VERSION 5.7 ;
  NOWIREEXTENSIONATPIN ON ;
  DIVIDERCHAR "/" ;
  BUSBITCHARS "[]" ;
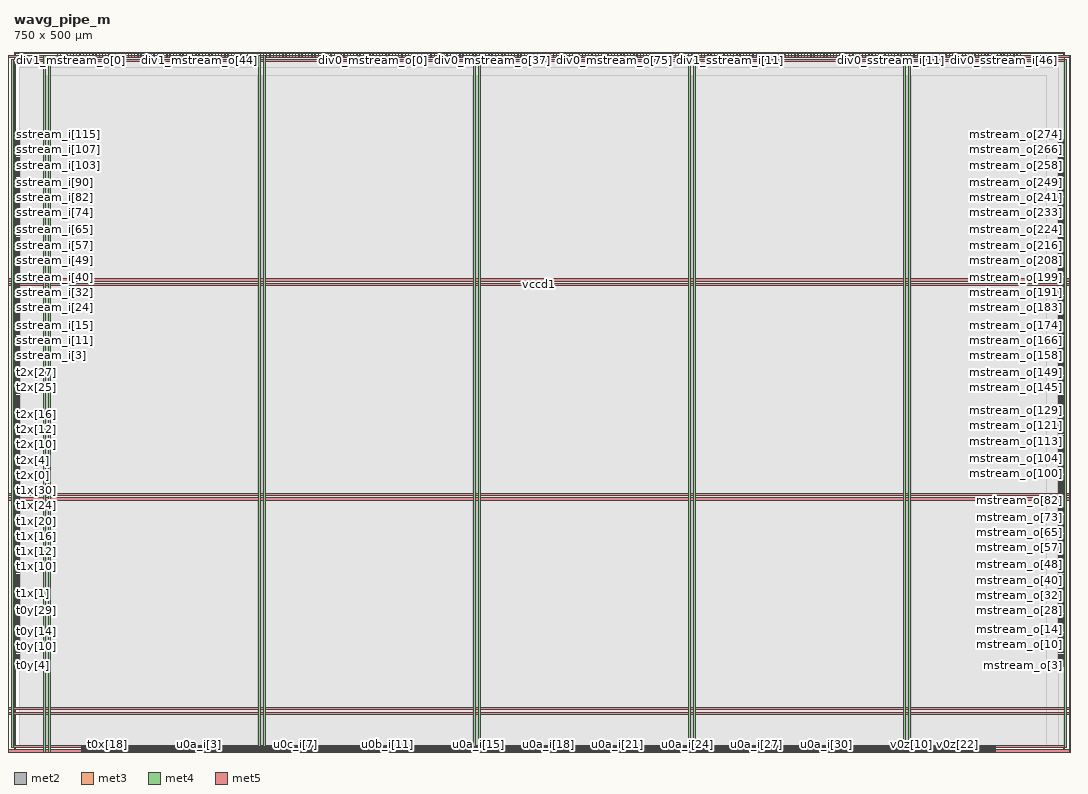
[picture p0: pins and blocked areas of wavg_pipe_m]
MACRO wavg_pipe_m
  CLASS BLOCK ;
  FOREIGN wavg_pipe_m ;
  ORIGIN 0.000 0.000 ;
  SIZE 750.000 BY 500.000 ;
  PIN clk_i
    DIRECTION INPUT ;
    USE SIGNAL ;
    ANTENNAGATEAREA 0.852000 ;
    PORT
      LAYER met2 ;
        RECT 48.390 0.000 48.670 4.000 ;
    END
  END clk_i
  PIN div0_mstream_i
    DIRECTION INPUT ;
    USE SIGNAL ;
    ANTENNAGATEAREA 0.213000 ;
    PORT
      LAYER met2 ;
        RECT 484.010 496.000 484.290 500.000 ;
    END
  END div0_mstream_i
  PIN div0_mstream_o[0]
    DIRECTION OUTPUT TRISTATE ;
    USE SIGNAL ;
    ANTENNADIFFAREA 0.795200 ;
    PORT
      LAYER met2 ;
        RECT 256.310 496.000 256.590 500.000 ;
    END
  END div0_mstream_o[0]
  PIN div0_mstream_o[10]
    DIRECTION OUTPUT TRISTATE ;
    USE SIGNAL ;
    ANTENNADIFFAREA 0.795200 ;
    PORT
      LAYER met2 ;
        RECT 279.310 496.000 279.590 500.000 ;
    END
  END div0_mstream_o[10]
  PIN div0_mstream_o[11]
    DIRECTION OUTPUT TRISTATE ;
    USE SIGNAL ;
    ANTENNADIFFAREA 0.795200 ;
    PORT
      LAYER met2 ;
        RECT 281.610 496.000 281.890 500.000 ;
    END
  END div0_mstream_o[11]
  PIN div0_mstream_o[12]
    DIRECTION OUTPUT TRISTATE ;
    USE SIGNAL ;
    ANTENNADIFFAREA 0.795200 ;
    PORT
      LAYER met2 ;
        RECT 283.910 496.000 284.190 500.000 ;
    END
  END div0_mstream_o[12]
  PIN div0_mstream_o[13]
    DIRECTION OUTPUT TRISTATE ;
    USE SIGNAL ;
    ANTENNADIFFAREA 0.795200 ;
    PORT
      LAYER met2 ;
        RECT 286.210 496.000 286.490 500.000 ;
    END
  END div0_mstream_o[13]
  PIN div0_mstream_o[14]
    DIRECTION OUTPUT TRISTATE ;
    USE SIGNAL ;
    ANTENNADIFFAREA 0.795200 ;
    PORT
      LAYER met2 ;
        RECT 288.510 496.000 288.790 500.000 ;
    END
  END div0_mstream_o[14]
  PIN div0_mstream_o[15]
    DIRECTION OUTPUT TRISTATE ;
    USE SIGNAL ;
    ANTENNADIFFAREA 0.795200 ;
    PORT
      LAYER met2 ;
        RECT 290.810 496.000 291.090 500.000 ;
    END
  END div0_mstream_o[15]
  PIN div0_mstream_o[16]
    DIRECTION OUTPUT TRISTATE ;
    USE SIGNAL ;
    ANTENNADIFFAREA 0.795200 ;
    PORT
      LAYER met2 ;
        RECT 293.110 496.000 293.390 500.000 ;
    END
  END div0_mstream_o[16]
  PIN div0_mstream_o[17]
    DIRECTION OUTPUT TRISTATE ;
    USE SIGNAL ;
    ANTENNADIFFAREA 0.795200 ;
    PORT
      LAYER met2 ;
        RECT 295.410 496.000 295.690 500.000 ;
    END
  END div0_mstream_o[17]
  PIN div0_mstream_o[18]
    DIRECTION OUTPUT TRISTATE ;
    USE SIGNAL ;
    ANTENNADIFFAREA 0.795200 ;
    PORT
      LAYER met2 ;
        RECT 297.710 496.000 297.990 500.000 ;
    END
  END div0_mstream_o[18]
  PIN div0_mstream_o[19]
    DIRECTION OUTPUT TRISTATE ;
    USE SIGNAL ;
    ANTENNADIFFAREA 0.795200 ;
    PORT
      LAYER met2 ;
        RECT 300.010 496.000 300.290 500.000 ;
    END
  END div0_mstream_o[19]
  PIN div0_mstream_o[1]
    DIRECTION OUTPUT TRISTATE ;
    USE SIGNAL ;
    ANTENNADIFFAREA 0.795200 ;
    PORT
      LAYER met2 ;
        RECT 258.610 496.000 258.890 500.000 ;
    END
  END div0_mstream_o[1]
  PIN div0_mstream_o[20]
    DIRECTION OUTPUT TRISTATE ;
    USE SIGNAL ;
    ANTENNADIFFAREA 0.795200 ;
    PORT
      LAYER met2 ;
        RECT 302.310 496.000 302.590 500.000 ;
    END
  END div0_mstream_o[20]
  PIN div0_mstream_o[21]
    DIRECTION OUTPUT TRISTATE ;
    USE SIGNAL ;
    ANTENNADIFFAREA 0.795200 ;
    PORT
      LAYER met2 ;
        RECT 304.610 496.000 304.890 500.000 ;
    END
  END div0_mstream_o[21]
  PIN div0_mstream_o[22]
    DIRECTION OUTPUT TRISTATE ;
    USE SIGNAL ;
    ANTENNADIFFAREA 0.795200 ;
    PORT
      LAYER met2 ;
        RECT 306.910 496.000 307.190 500.000 ;
    END
  END div0_mstream_o[22]
  PIN div0_mstream_o[23]
    DIRECTION OUTPUT TRISTATE ;
    USE SIGNAL ;
    ANTENNADIFFAREA 0.795200 ;
    PORT
      LAYER met2 ;
        RECT 309.210 496.000 309.490 500.000 ;
    END
  END div0_mstream_o[23]
  PIN div0_mstream_o[24]
    DIRECTION OUTPUT TRISTATE ;
    USE SIGNAL ;
    ANTENNADIFFAREA 0.795200 ;
    PORT
      LAYER met2 ;
        RECT 311.510 496.000 311.790 500.000 ;
    END
  END div0_mstream_o[24]
  PIN div0_mstream_o[25]
    DIRECTION OUTPUT TRISTATE ;
    USE SIGNAL ;
    ANTENNADIFFAREA 0.795200 ;
    PORT
      LAYER met2 ;
        RECT 313.810 496.000 314.090 500.000 ;
    END
  END div0_mstream_o[25]
  PIN div0_mstream_o[26]
    DIRECTION OUTPUT TRISTATE ;
    USE SIGNAL ;
    ANTENNADIFFAREA 0.795200 ;
    PORT
      LAYER met2 ;
        RECT 316.110 496.000 316.390 500.000 ;
    END
  END div0_mstream_o[26]
  PIN div0_mstream_o[27]
    DIRECTION OUTPUT TRISTATE ;
    USE SIGNAL ;
    ANTENNADIFFAREA 0.795200 ;
    PORT
      LAYER met2 ;
        RECT 318.410 496.000 318.690 500.000 ;
    END
  END div0_mstream_o[27]
  PIN div0_mstream_o[28]
    DIRECTION OUTPUT TRISTATE ;
    USE SIGNAL ;
    ANTENNADIFFAREA 0.795200 ;
    PORT
      LAYER met2 ;
        RECT 320.710 496.000 320.990 500.000 ;
    END
  END div0_mstream_o[28]
  PIN div0_mstream_o[29]
    DIRECTION OUTPUT TRISTATE ;
    USE SIGNAL ;
    ANTENNADIFFAREA 0.795200 ;
    PORT
      LAYER met2 ;
        RECT 323.010 496.000 323.290 500.000 ;
    END
  END div0_mstream_o[29]
  PIN div0_mstream_o[2]
    DIRECTION OUTPUT TRISTATE ;
    USE SIGNAL ;
    ANTENNADIFFAREA 0.795200 ;
    PORT
      LAYER met2 ;
        RECT 260.910 496.000 261.190 500.000 ;
    END
  END div0_mstream_o[2]
  PIN div0_mstream_o[30]
    DIRECTION OUTPUT TRISTATE ;
    USE SIGNAL ;
    ANTENNADIFFAREA 0.795200 ;
    PORT
      LAYER met2 ;
        RECT 325.310 496.000 325.590 500.000 ;
    END
  END div0_mstream_o[30]
  PIN div0_mstream_o[31]
    DIRECTION OUTPUT TRISTATE ;
    USE SIGNAL ;
    ANTENNADIFFAREA 0.795200 ;
    PORT
      LAYER met2 ;
        RECT 327.610 496.000 327.890 500.000 ;
    END
  END div0_mstream_o[31]
  PIN div0_mstream_o[32]
    DIRECTION OUTPUT TRISTATE ;
    USE SIGNAL ;
    ANTENNADIFFAREA 0.795200 ;
    PORT
      LAYER met2 ;
        RECT 329.910 496.000 330.190 500.000 ;
    END
  END div0_mstream_o[32]
  PIN div0_mstream_o[33]
    DIRECTION OUTPUT TRISTATE ;
    USE SIGNAL ;
    ANTENNADIFFAREA 0.795200 ;
    PORT
      LAYER met2 ;
        RECT 332.210 496.000 332.490 500.000 ;
    END
  END div0_mstream_o[33]
  PIN div0_mstream_o[34]
    DIRECTION OUTPUT TRISTATE ;
    USE SIGNAL ;
    ANTENNADIFFAREA 0.795200 ;
    PORT
      LAYER met2 ;
        RECT 334.510 496.000 334.790 500.000 ;
    END
  END div0_mstream_o[34]
  PIN div0_mstream_o[35]
    DIRECTION OUTPUT TRISTATE ;
    USE SIGNAL ;
    ANTENNADIFFAREA 0.795200 ;
    PORT
      LAYER met2 ;
        RECT 336.810 496.000 337.090 500.000 ;
    END
  END div0_mstream_o[35]
  PIN div0_mstream_o[36]
    DIRECTION OUTPUT TRISTATE ;
    USE SIGNAL ;
    ANTENNADIFFAREA 0.795200 ;
    PORT
      LAYER met2 ;
        RECT 339.110 496.000 339.390 500.000 ;
    END
  END div0_mstream_o[36]
  PIN div0_mstream_o[37]
    DIRECTION OUTPUT TRISTATE ;
    USE SIGNAL ;
    ANTENNADIFFAREA 0.795200 ;
    PORT
      LAYER met2 ;
        RECT 341.410 496.000 341.690 500.000 ;
    END
  END div0_mstream_o[37]
  PIN div0_mstream_o[38]
    DIRECTION OUTPUT TRISTATE ;
    USE SIGNAL ;
    ANTENNADIFFAREA 0.795200 ;
    PORT
      LAYER met2 ;
        RECT 343.710 496.000 343.990 500.000 ;
    END
  END div0_mstream_o[38]
  PIN div0_mstream_o[39]
    DIRECTION OUTPUT TRISTATE ;
    USE SIGNAL ;
    ANTENNADIFFAREA 0.795200 ;
    PORT
      LAYER met2 ;
        RECT 346.010 496.000 346.290 500.000 ;
    END
  END div0_mstream_o[39]
  PIN div0_mstream_o[3]
    DIRECTION OUTPUT TRISTATE ;
    USE SIGNAL ;
    ANTENNADIFFAREA 0.795200 ;
    PORT
      LAYER met2 ;
        RECT 263.210 496.000 263.490 500.000 ;
    END
  END div0_mstream_o[3]
  PIN div0_mstream_o[40]
    DIRECTION OUTPUT TRISTATE ;
    USE SIGNAL ;
    ANTENNADIFFAREA 0.795200 ;
    PORT
      LAYER met2 ;
        RECT 348.310 496.000 348.590 500.000 ;
    END
  END div0_mstream_o[40]
  PIN div0_mstream_o[41]
    DIRECTION OUTPUT TRISTATE ;
    USE SIGNAL ;
    ANTENNADIFFAREA 0.795200 ;
    PORT
      LAYER met2 ;
        RECT 350.610 496.000 350.890 500.000 ;
    END
  END div0_mstream_o[41]
  PIN div0_mstream_o[42]
    DIRECTION OUTPUT TRISTATE ;
    USE SIGNAL ;
    ANTENNADIFFAREA 0.795200 ;
    PORT
      LAYER met2 ;
        RECT 352.910 496.000 353.190 500.000 ;
    END
  END div0_mstream_o[42]
  PIN div0_mstream_o[43]
    DIRECTION OUTPUT TRISTATE ;
    USE SIGNAL ;
    ANTENNADIFFAREA 0.795200 ;
    PORT
      LAYER met2 ;
        RECT 355.210 496.000 355.490 500.000 ;
    END
  END div0_mstream_o[43]
  PIN div0_mstream_o[44]
    DIRECTION OUTPUT TRISTATE ;
    USE SIGNAL ;
    ANTENNADIFFAREA 0.795200 ;
    PORT
      LAYER met2 ;
        RECT 357.510 496.000 357.790 500.000 ;
    END
  END div0_mstream_o[44]
  PIN div0_mstream_o[45]
    DIRECTION OUTPUT TRISTATE ;
    USE SIGNAL ;
    ANTENNADIFFAREA 0.795200 ;
    PORT
      LAYER met2 ;
        RECT 359.810 496.000 360.090 500.000 ;
    END
  END div0_mstream_o[45]
  PIN div0_mstream_o[46]
    DIRECTION OUTPUT TRISTATE ;
    USE SIGNAL ;
    ANTENNADIFFAREA 0.795200 ;
    PORT
      LAYER met2 ;
        RECT 362.110 496.000 362.390 500.000 ;
    END
  END div0_mstream_o[46]
  PIN div0_mstream_o[47]
    DIRECTION OUTPUT TRISTATE ;
    USE SIGNAL ;
    ANTENNADIFFAREA 0.795200 ;
    PORT
      LAYER met2 ;
        RECT 364.410 496.000 364.690 500.000 ;
    END
  END div0_mstream_o[47]
  PIN div0_mstream_o[48]
    DIRECTION OUTPUT TRISTATE ;
    USE SIGNAL ;
    PORT
      LAYER met2 ;
        RECT 366.710 496.000 366.990 500.000 ;
    END
  END div0_mstream_o[48]
  PIN div0_mstream_o[49]
    DIRECTION OUTPUT TRISTATE ;
    USE SIGNAL ;
    PORT
      LAYER met2 ;
        RECT 369.010 496.000 369.290 500.000 ;
    END
  END div0_mstream_o[49]
  PIN div0_mstream_o[4]
    DIRECTION OUTPUT TRISTATE ;
    USE SIGNAL ;
    ANTENNADIFFAREA 0.795200 ;
    PORT
      LAYER met2 ;
        RECT 265.510 496.000 265.790 500.000 ;
    END
  END div0_mstream_o[4]
  PIN div0_mstream_o[50]
    DIRECTION OUTPUT TRISTATE ;
    USE SIGNAL ;
    PORT
      LAYER met2 ;
        RECT 371.310 496.000 371.590 500.000 ;
    END
  END div0_mstream_o[50]
  PIN div0_mstream_o[51]
    DIRECTION OUTPUT TRISTATE ;
    USE SIGNAL ;
    PORT
      LAYER met2 ;
        RECT 373.610 496.000 373.890 500.000 ;
    END
  END div0_mstream_o[51]
  PIN div0_mstream_o[52]
    DIRECTION OUTPUT TRISTATE ;
    USE SIGNAL ;
    PORT
      LAYER met2 ;
        RECT 375.910 496.000 376.190 500.000 ;
    END
  END div0_mstream_o[52]
  PIN div0_mstream_o[53]
    DIRECTION OUTPUT TRISTATE ;
    USE SIGNAL ;
    PORT
      LAYER met2 ;
        RECT 378.210 496.000 378.490 500.000 ;
    END
  END div0_mstream_o[53]
  PIN div0_mstream_o[54]
    DIRECTION OUTPUT TRISTATE ;
    USE SIGNAL ;
    PORT
      LAYER met2 ;
        RECT 380.510 496.000 380.790 500.000 ;
    END
  END div0_mstream_o[54]
  PIN div0_mstream_o[55]
    DIRECTION OUTPUT TRISTATE ;
    USE SIGNAL ;
    PORT
      LAYER met2 ;
        RECT 382.810 496.000 383.090 500.000 ;
    END
  END div0_mstream_o[55]
  PIN div0_mstream_o[56]
    DIRECTION OUTPUT TRISTATE ;
    USE SIGNAL ;
    PORT
      LAYER met2 ;
        RECT 385.110 496.000 385.390 500.000 ;
    END
  END div0_mstream_o[56]
  PIN div0_mstream_o[57]
    DIRECTION OUTPUT TRISTATE ;
    USE SIGNAL ;
    PORT
      LAYER met2 ;
        RECT 387.410 496.000 387.690 500.000 ;
    END
  END div0_mstream_o[57]
  PIN div0_mstream_o[58]
    DIRECTION OUTPUT TRISTATE ;
    USE SIGNAL ;
    PORT
      LAYER met2 ;
        RECT 389.710 496.000 389.990 500.000 ;
    END
  END div0_mstream_o[58]
  PIN div0_mstream_o[59]
    DIRECTION OUTPUT TRISTATE ;
    USE SIGNAL ;
    PORT
      LAYER met2 ;
        RECT 392.010 496.000 392.290 500.000 ;
    END
  END div0_mstream_o[59]
  PIN div0_mstream_o[5]
    DIRECTION OUTPUT TRISTATE ;
    USE SIGNAL ;
    ANTENNADIFFAREA 0.795200 ;
    PORT
      LAYER met2 ;
        RECT 267.810 496.000 268.090 500.000 ;
    END
  END div0_mstream_o[5]
  PIN div0_mstream_o[60]
    DIRECTION OUTPUT TRISTATE ;
    USE SIGNAL ;
    PORT
      LAYER met2 ;
        RECT 394.310 496.000 394.590 500.000 ;
    END
  END div0_mstream_o[60]
  PIN div0_mstream_o[61]
    DIRECTION OUTPUT TRISTATE ;
    USE SIGNAL ;
    PORT
      LAYER met2 ;
        RECT 396.610 496.000 396.890 500.000 ;
    END
  END div0_mstream_o[61]
  PIN div0_mstream_o[62]
    DIRECTION OUTPUT TRISTATE ;
    USE SIGNAL ;
    PORT
      LAYER met2 ;
        RECT 398.910 496.000 399.190 500.000 ;
    END
  END div0_mstream_o[62]
  PIN div0_mstream_o[63]
    DIRECTION OUTPUT TRISTATE ;
    USE SIGNAL ;
    PORT
      LAYER met2 ;
        RECT 401.210 496.000 401.490 500.000 ;
    END
  END div0_mstream_o[63]
  PIN div0_mstream_o[64]
    DIRECTION OUTPUT TRISTATE ;
    USE SIGNAL ;
    PORT
      LAYER met2 ;
        RECT 403.510 496.000 403.790 500.000 ;
    END
  END div0_mstream_o[64]
  PIN div0_mstream_o[65]
    DIRECTION OUTPUT TRISTATE ;
    USE SIGNAL ;
    PORT
      LAYER met2 ;
        RECT 405.810 496.000 406.090 500.000 ;
    END
  END div0_mstream_o[65]
  PIN div0_mstream_o[66]
    DIRECTION OUTPUT TRISTATE ;
    USE SIGNAL ;
    PORT
      LAYER met2 ;
        RECT 408.110 496.000 408.390 500.000 ;
    END
  END div0_mstream_o[66]
  PIN div0_mstream_o[67]
    DIRECTION OUTPUT TRISTATE ;
    USE SIGNAL ;
    PORT
      LAYER met2 ;
        RECT 410.410 496.000 410.690 500.000 ;
    END
  END div0_mstream_o[67]
  PIN div0_mstream_o[68]
    DIRECTION OUTPUT TRISTATE ;
    USE SIGNAL ;
    PORT
      LAYER met2 ;
        RECT 412.710 496.000 412.990 500.000 ;
    END
  END div0_mstream_o[68]
  PIN div0_mstream_o[69]
    DIRECTION OUTPUT TRISTATE ;
    USE SIGNAL ;
    PORT
      LAYER met2 ;
        RECT 415.010 496.000 415.290 500.000 ;
    END
  END div0_mstream_o[69]
  PIN div0_mstream_o[6]
    DIRECTION OUTPUT TRISTATE ;
    USE SIGNAL ;
    ANTENNADIFFAREA 0.795200 ;
    PORT
      LAYER met2 ;
        RECT 270.110 496.000 270.390 500.000 ;
    END
  END div0_mstream_o[6]
  PIN div0_mstream_o[70]
    DIRECTION OUTPUT TRISTATE ;
    USE SIGNAL ;
    PORT
      LAYER met2 ;
        RECT 417.310 496.000 417.590 500.000 ;
    END
  END div0_mstream_o[70]
  PIN div0_mstream_o[71]
    DIRECTION OUTPUT TRISTATE ;
    USE SIGNAL ;
    PORT
      LAYER met2 ;
        RECT 419.610 496.000 419.890 500.000 ;
    END
  END div0_mstream_o[71]
  PIN div0_mstream_o[72]
    DIRECTION OUTPUT TRISTATE ;
    USE SIGNAL ;
    PORT
      LAYER met2 ;
        RECT 421.910 496.000 422.190 500.000 ;
    END
  END div0_mstream_o[72]
  PIN div0_mstream_o[73]
    DIRECTION OUTPUT TRISTATE ;
    USE SIGNAL ;
    PORT
      LAYER met2 ;
        RECT 424.210 496.000 424.490 500.000 ;
    END
  END div0_mstream_o[73]
  PIN div0_mstream_o[74]
    DIRECTION OUTPUT TRISTATE ;
    USE SIGNAL ;
    PORT
      LAYER met2 ;
        RECT 426.510 496.000 426.790 500.000 ;
    END
  END div0_mstream_o[74]
  PIN div0_mstream_o[75]
    DIRECTION OUTPUT TRISTATE ;
    USE SIGNAL ;
    PORT
      LAYER met2 ;
        RECT 428.810 496.000 429.090 500.000 ;
    END
  END div0_mstream_o[75]
  PIN div0_mstream_o[76]
    DIRECTION OUTPUT TRISTATE ;
    USE SIGNAL ;
    PORT
      LAYER met2 ;
        RECT 431.110 496.000 431.390 500.000 ;
    END
  END div0_mstream_o[76]
  PIN div0_mstream_o[77]
    DIRECTION OUTPUT TRISTATE ;
    USE SIGNAL ;
    PORT
      LAYER met2 ;
        RECT 433.410 496.000 433.690 500.000 ;
    END
  END div0_mstream_o[77]
  PIN div0_mstream_o[78]
    DIRECTION OUTPUT TRISTATE ;
    USE SIGNAL ;
    PORT
      LAYER met2 ;
        RECT 435.710 496.000 435.990 500.000 ;
    END
  END div0_mstream_o[78]
  PIN div0_mstream_o[79]
    DIRECTION OUTPUT TRISTATE ;
    USE SIGNAL ;
    PORT
      LAYER met2 ;
        RECT 438.010 496.000 438.290 500.000 ;
    END
  END div0_mstream_o[79]
  PIN div0_mstream_o[7]
    DIRECTION OUTPUT TRISTATE ;
    USE SIGNAL ;
    ANTENNADIFFAREA 0.795200 ;
    PORT
      LAYER met2 ;
        RECT 272.410 496.000 272.690 500.000 ;
    END
  END div0_mstream_o[7]
  PIN div0_mstream_o[80]
    DIRECTION OUTPUT TRISTATE ;
    USE SIGNAL ;
    ANTENNADIFFAREA 0.795200 ;
    PORT
      LAYER met2 ;
        RECT 440.310 496.000 440.590 500.000 ;
    END
  END div0_mstream_o[80]
  PIN div0_mstream_o[81]
    DIRECTION OUTPUT TRISTATE ;
    USE SIGNAL ;
    ANTENNADIFFAREA 0.795200 ;
    PORT
      LAYER met2 ;
        RECT 442.610 496.000 442.890 500.000 ;
    END
  END div0_mstream_o[81]
  PIN div0_mstream_o[82]
    DIRECTION OUTPUT TRISTATE ;
    USE SIGNAL ;
    ANTENNADIFFAREA 0.795200 ;
    PORT
      LAYER met2 ;
        RECT 444.910 496.000 445.190 500.000 ;
    END
  END div0_mstream_o[82]
  PIN div0_mstream_o[83]
    DIRECTION OUTPUT TRISTATE ;
    USE SIGNAL ;
    ANTENNADIFFAREA 0.795200 ;
    PORT
      LAYER met2 ;
        RECT 447.210 496.000 447.490 500.000 ;
    END
  END div0_mstream_o[83]
  PIN div0_mstream_o[84]
    DIRECTION OUTPUT TRISTATE ;
    USE SIGNAL ;
    ANTENNADIFFAREA 0.795200 ;
    PORT
      LAYER met2 ;
        RECT 449.510 496.000 449.790 500.000 ;
    END
  END div0_mstream_o[84]
  PIN div0_mstream_o[85]
    DIRECTION OUTPUT TRISTATE ;
    USE SIGNAL ;
    ANTENNADIFFAREA 0.795200 ;
    PORT
      LAYER met2 ;
        RECT 451.810 496.000 452.090 500.000 ;
    END
  END div0_mstream_o[85]
  PIN div0_mstream_o[86]
    DIRECTION OUTPUT TRISTATE ;
    USE SIGNAL ;
    ANTENNADIFFAREA 0.795200 ;
    PORT
      LAYER met2 ;
        RECT 454.110 496.000 454.390 500.000 ;
    END
  END div0_mstream_o[86]
  PIN div0_mstream_o[87]
    DIRECTION OUTPUT TRISTATE ;
    USE SIGNAL ;
    ANTENNADIFFAREA 0.795200 ;
    PORT
      LAYER met2 ;
        RECT 456.410 496.000 456.690 500.000 ;
    END
  END div0_mstream_o[87]
  PIN div0_mstream_o[88]
    DIRECTION OUTPUT TRISTATE ;
    USE SIGNAL ;
    ANTENNADIFFAREA 0.795200 ;
    PORT
      LAYER met2 ;
        RECT 458.710 496.000 458.990 500.000 ;
    END
  END div0_mstream_o[88]
  PIN div0_mstream_o[89]
    DIRECTION OUTPUT TRISTATE ;
    USE SIGNAL ;
    ANTENNADIFFAREA 0.795200 ;
    PORT
      LAYER met2 ;
        RECT 461.010 496.000 461.290 500.000 ;
    END
  END div0_mstream_o[89]
  PIN div0_mstream_o[8]
    DIRECTION OUTPUT TRISTATE ;
    USE SIGNAL ;
    ANTENNADIFFAREA 0.795200 ;
    PORT
      LAYER met2 ;
        RECT 274.710 496.000 274.990 500.000 ;
    END
  END div0_mstream_o[8]
  PIN div0_mstream_o[90]
    DIRECTION OUTPUT TRISTATE ;
    USE SIGNAL ;
    ANTENNADIFFAREA 0.795200 ;
    PORT
      LAYER met2 ;
        RECT 463.310 496.000 463.590 500.000 ;
    END
  END div0_mstream_o[90]
  PIN div0_mstream_o[91]
    DIRECTION OUTPUT TRISTATE ;
    USE SIGNAL ;
    ANTENNADIFFAREA 0.795200 ;
    PORT
      LAYER met2 ;
        RECT 465.610 496.000 465.890 500.000 ;
    END
  END div0_mstream_o[91]
  PIN div0_mstream_o[92]
    DIRECTION OUTPUT TRISTATE ;
    USE SIGNAL ;
    ANTENNADIFFAREA 0.795200 ;
    PORT
      LAYER met2 ;
        RECT 467.910 496.000 468.190 500.000 ;
    END
  END div0_mstream_o[92]
  PIN div0_mstream_o[93]
    DIRECTION OUTPUT TRISTATE ;
    USE SIGNAL ;
    ANTENNADIFFAREA 0.795200 ;
    PORT
      LAYER met2 ;
        RECT 470.210 496.000 470.490 500.000 ;
    END
  END div0_mstream_o[93]
  PIN div0_mstream_o[94]
    DIRECTION OUTPUT TRISTATE ;
    USE SIGNAL ;
    ANTENNADIFFAREA 0.795200 ;
    PORT
      LAYER met2 ;
        RECT 472.510 496.000 472.790 500.000 ;
    END
  END div0_mstream_o[94]
  PIN div0_mstream_o[95]
    DIRECTION OUTPUT TRISTATE ;
    USE SIGNAL ;
    ANTENNADIFFAREA 0.795200 ;
    PORT
      LAYER met2 ;
        RECT 474.810 496.000 475.090 500.000 ;
    END
  END div0_mstream_o[95]
  PIN div0_mstream_o[96]
    DIRECTION OUTPUT TRISTATE ;
    USE SIGNAL ;
    ANTENNADIFFAREA 0.795200 ;
    PORT
      LAYER met2 ;
        RECT 477.110 496.000 477.390 500.000 ;
    END
  END div0_mstream_o[96]
  PIN div0_mstream_o[97]
    DIRECTION OUTPUT TRISTATE ;
    USE SIGNAL ;
    PORT
      LAYER met2 ;
        RECT 479.410 496.000 479.690 500.000 ;
    END
  END div0_mstream_o[97]
  PIN div0_mstream_o[9]
    DIRECTION OUTPUT TRISTATE ;
    USE SIGNAL ;
    ANTENNADIFFAREA 0.795200 ;
    PORT
      LAYER met2 ;
        RECT 277.010 496.000 277.290 500.000 ;
    END
  END div0_mstream_o[9]
  PIN div0_sstream_i[0]
    DIRECTION INPUT ;
    USE SIGNAL ;
    ANTENNAGATEAREA 0.426000 ;
    PORT
      LAYER met2 ;
        RECT 601.310 496.000 601.590 500.000 ;
    END
  END div0_sstream_i[0]
  PIN div0_sstream_i[10]
    DIRECTION INPUT ;
    USE SIGNAL ;
    ANTENNAGATEAREA 0.495000 ;
    PORT
      LAYER met2 ;
        RECT 624.310 496.000 624.590 500.000 ;
    END
  END div0_sstream_i[10]
  PIN div0_sstream_i[11]
    DIRECTION INPUT ;
    USE SIGNAL ;
    ANTENNAGATEAREA 0.495000 ;
    PORT
      LAYER met2 ;
        RECT 626.610 496.000 626.890 500.000 ;
    END
  END div0_sstream_i[11]
  PIN div0_sstream_i[12]
    DIRECTION INPUT ;
    USE SIGNAL ;
    ANTENNAGATEAREA 0.495000 ;
    PORT
      LAYER met2 ;
        RECT 628.910 496.000 629.190 500.000 ;
    END
  END div0_sstream_i[12]
  PIN div0_sstream_i[13]
    DIRECTION INPUT ;
    USE SIGNAL ;
    ANTENNAGATEAREA 0.426000 ;
    PORT
      LAYER met2 ;
        RECT 631.210 496.000 631.490 500.000 ;
    END
  END div0_sstream_i[13]
  PIN div0_sstream_i[14]
    DIRECTION INPUT ;
    USE SIGNAL ;
    ANTENNAGATEAREA 0.426000 ;
    PORT
      LAYER met2 ;
        RECT 633.510 496.000 633.790 500.000 ;
    END
  END div0_sstream_i[14]
  PIN div0_sstream_i[15]
    DIRECTION INPUT ;
    USE SIGNAL ;
    ANTENNAGATEAREA 0.426000 ;
    PORT
      LAYER met2 ;
        RECT 635.810 496.000 636.090 500.000 ;
    END
  END div0_sstream_i[15]
  PIN div0_sstream_i[16]
    DIRECTION INPUT ;
    USE SIGNAL ;
    ANTENNAGATEAREA 0.426000 ;
    PORT
      LAYER met2 ;
        RECT 638.110 496.000 638.390 500.000 ;
    END
  END div0_sstream_i[16]
  PIN div0_sstream_i[17]
    DIRECTION INPUT ;
    USE SIGNAL ;
    ANTENNAGATEAREA 0.426000 ;
    PORT
      LAYER met2 ;
        RECT 640.410 496.000 640.690 500.000 ;
    END
  END div0_sstream_i[17]
  PIN div0_sstream_i[18]
    DIRECTION INPUT ;
    USE SIGNAL ;
    ANTENNAGATEAREA 0.426000 ;
    PORT
      LAYER met2 ;
        RECT 642.710 496.000 642.990 500.000 ;
    END
  END div0_sstream_i[18]
  PIN div0_sstream_i[19]
    DIRECTION INPUT ;
    USE SIGNAL ;
    ANTENNAGATEAREA 0.426000 ;
    PORT
      LAYER met2 ;
        RECT 645.010 496.000 645.290 500.000 ;
    END
  END div0_sstream_i[19]
  PIN div0_sstream_i[1]
    DIRECTION INPUT ;
    USE SIGNAL ;
    ANTENNAGATEAREA 0.495000 ;
    PORT
      LAYER met2 ;
        RECT 603.610 496.000 603.890 500.000 ;
    END
  END div0_sstream_i[1]
  PIN div0_sstream_i[20]
    DIRECTION INPUT ;
    USE SIGNAL ;
    ANTENNAGATEAREA 0.426000 ;
    PORT
      LAYER met2 ;
        RECT 647.310 496.000 647.590 500.000 ;
    END
  END div0_sstream_i[20]
  PIN div0_sstream_i[21]
    DIRECTION INPUT ;
    USE SIGNAL ;
    ANTENNAGATEAREA 0.426000 ;
    PORT
      LAYER met2 ;
        RECT 649.610 496.000 649.890 500.000 ;
    END
  END div0_sstream_i[21]
  PIN div0_sstream_i[22]
    DIRECTION INPUT ;
    USE SIGNAL ;
    ANTENNAGATEAREA 0.426000 ;
    PORT
      LAYER met2 ;
        RECT 651.910 496.000 652.190 500.000 ;
    END
  END div0_sstream_i[22]
  PIN div0_sstream_i[23]
    DIRECTION INPUT ;
    USE SIGNAL ;
    ANTENNAGATEAREA 0.247500 ;
    PORT
      LAYER met2 ;
        RECT 654.210 496.000 654.490 500.000 ;
    END
  END div0_sstream_i[23]
  PIN div0_sstream_i[24]
    DIRECTION INPUT ;
    USE SIGNAL ;
    ANTENNAGATEAREA 0.247500 ;
    PORT
      LAYER met2 ;
        RECT 656.510 496.000 656.790 500.000 ;
    END
  END div0_sstream_i[24]
  PIN div0_sstream_i[25]
    DIRECTION INPUT ;
    USE SIGNAL ;
    ANTENNAGATEAREA 0.426000 ;
    PORT
      LAYER met2 ;
        RECT 658.810 496.000 659.090 500.000 ;
    END
  END div0_sstream_i[25]
  PIN div0_sstream_i[26]
    DIRECTION INPUT ;
    USE SIGNAL ;
    ANTENNAGATEAREA 0.247500 ;
    PORT
      LAYER met2 ;
        RECT 661.110 496.000 661.390 500.000 ;
    END
  END div0_sstream_i[26]
  PIN div0_sstream_i[27]
    DIRECTION INPUT ;
    USE SIGNAL ;
    ANTENNAGATEAREA 0.426000 ;
    PORT
      LAYER met2 ;
        RECT 663.410 496.000 663.690 500.000 ;
    END
  END div0_sstream_i[27]
  PIN div0_sstream_i[28]
    DIRECTION INPUT ;
    USE SIGNAL ;
    ANTENNAGATEAREA 0.247500 ;
    PORT
      LAYER met2 ;
        RECT 665.710 496.000 665.990 500.000 ;
    END
  END div0_sstream_i[28]
  PIN div0_sstream_i[29]
    DIRECTION INPUT ;
    USE SIGNAL ;
    ANTENNAGATEAREA 0.247500 ;
    PORT
      LAYER met2 ;
        RECT 668.010 496.000 668.290 500.000 ;
    END
  END div0_sstream_i[29]
  PIN div0_sstream_i[2]
    DIRECTION INPUT ;
    USE SIGNAL ;
    ANTENNAGATEAREA 0.426000 ;
    PORT
      LAYER met2 ;
        RECT 605.910 496.000 606.190 500.000 ;
    END
  END div0_sstream_i[2]
  PIN div0_sstream_i[30]
    DIRECTION INPUT ;
    USE SIGNAL ;
    ANTENNAGATEAREA 0.247500 ;
    PORT
      LAYER met2 ;
        RECT 670.310 496.000 670.590 500.000 ;
    END
  END div0_sstream_i[30]
  PIN div0_sstream_i[31]
    DIRECTION INPUT ;
    USE SIGNAL ;
    ANTENNAGATEAREA 0.426000 ;
    PORT
      LAYER met2 ;
        RECT 672.610 496.000 672.890 500.000 ;
    END
  END div0_sstream_i[31]
  PIN div0_sstream_i[32]
    DIRECTION INPUT ;
    USE SIGNAL ;
    ANTENNAGATEAREA 0.426000 ;
    PORT
      LAYER met2 ;
        RECT 674.910 496.000 675.190 500.000 ;
    END
  END div0_sstream_i[32]
  PIN div0_sstream_i[33]
    DIRECTION INPUT ;
    USE SIGNAL ;
    ANTENNAGATEAREA 0.247500 ;
    PORT
      LAYER met2 ;
        RECT 677.210 496.000 677.490 500.000 ;
    END
  END div0_sstream_i[33]
  PIN div0_sstream_i[34]
    DIRECTION INPUT ;
    USE SIGNAL ;
    ANTENNAGATEAREA 0.247500 ;
    PORT
      LAYER met2 ;
        RECT 679.510 496.000 679.790 500.000 ;
    END
  END div0_sstream_i[34]
  PIN div0_sstream_i[35]
    DIRECTION INPUT ;
    USE SIGNAL ;
    ANTENNAGATEAREA 0.247500 ;
    PORT
      LAYER met2 ;
        RECT 681.810 496.000 682.090 500.000 ;
    END
  END div0_sstream_i[35]
  PIN div0_sstream_i[36]
    DIRECTION INPUT ;
    USE SIGNAL ;
    ANTENNAGATEAREA 0.247500 ;
    PORT
      LAYER met2 ;
        RECT 684.110 496.000 684.390 500.000 ;
    END
  END div0_sstream_i[36]
  PIN div0_sstream_i[37]
    DIRECTION INPUT ;
    USE SIGNAL ;
    ANTENNAGATEAREA 0.247500 ;
    PORT
      LAYER met2 ;
        RECT 686.410 496.000 686.690 500.000 ;
    END
  END div0_sstream_i[37]
  PIN div0_sstream_i[38]
    DIRECTION INPUT ;
    USE SIGNAL ;
    ANTENNAGATEAREA 0.213000 ;
    PORT
      LAYER met2 ;
        RECT 688.710 496.000 688.990 500.000 ;
    END
  END div0_sstream_i[38]
  PIN div0_sstream_i[39]
    DIRECTION INPUT ;
    USE SIGNAL ;
    ANTENNAGATEAREA 0.213000 ;
    PORT
      LAYER met2 ;
        RECT 691.010 496.000 691.290 500.000 ;
    END
  END div0_sstream_i[39]
  PIN div0_sstream_i[3]
    DIRECTION INPUT ;
    USE SIGNAL ;
    ANTENNAGATEAREA 0.495000 ;
    PORT
      LAYER met2 ;
        RECT 608.210 496.000 608.490 500.000 ;
    END
  END div0_sstream_i[3]
  PIN div0_sstream_i[40]
    DIRECTION INPUT ;
    USE SIGNAL ;
    ANTENNAGATEAREA 0.247500 ;
    PORT
      LAYER met2 ;
        RECT 693.310 496.000 693.590 500.000 ;
    END
  END div0_sstream_i[40]
  PIN div0_sstream_i[41]
    DIRECTION INPUT ;
    USE SIGNAL ;
    ANTENNAGATEAREA 0.213000 ;
    PORT
      LAYER met2 ;
        RECT 695.610 496.000 695.890 500.000 ;
    END
  END div0_sstream_i[41]
  PIN div0_sstream_i[42]
    DIRECTION INPUT ;
    USE SIGNAL ;
    ANTENNAGATEAREA 0.213000 ;
    PORT
      LAYER met2 ;
        RECT 697.910 496.000 698.190 500.000 ;
    END
  END div0_sstream_i[42]
  PIN div0_sstream_i[43]
    DIRECTION INPUT ;
    USE SIGNAL ;
    ANTENNAGATEAREA 0.213000 ;
    PORT
      LAYER met2 ;
        RECT 700.210 496.000 700.490 500.000 ;
    END
  END div0_sstream_i[43]
  PIN div0_sstream_i[44]
    DIRECTION INPUT ;
    USE SIGNAL ;
    ANTENNAGATEAREA 0.213000 ;
    PORT
      LAYER met2 ;
        RECT 702.510 496.000 702.790 500.000 ;
    END
  END div0_sstream_i[44]
  PIN div0_sstream_i[45]
    DIRECTION INPUT ;
    USE SIGNAL ;
    ANTENNAGATEAREA 0.213000 ;
    PORT
      LAYER met2 ;
        RECT 704.810 496.000 705.090 500.000 ;
    END
  END div0_sstream_i[45]
  PIN div0_sstream_i[46]
    DIRECTION INPUT ;
    USE SIGNAL ;
    ANTENNAGATEAREA 0.213000 ;
    PORT
      LAYER met2 ;
        RECT 707.110 496.000 707.390 500.000 ;
    END
  END div0_sstream_i[46]
  PIN div0_sstream_i[47]
    DIRECTION INPUT ;
    USE SIGNAL ;
    ANTENNAGATEAREA 0.213000 ;
    PORT
      LAYER met2 ;
        RECT 709.410 496.000 709.690 500.000 ;
    END
  END div0_sstream_i[47]
  PIN div0_sstream_i[48]
    DIRECTION INPUT ;
    USE SIGNAL ;
    ANTENNAGATEAREA 0.742500 ;
    PORT
      LAYER met2 ;
        RECT 711.710 496.000 711.990 500.000 ;
    END
  END div0_sstream_i[48]
  PIN div0_sstream_i[49]
    DIRECTION INPUT ;
    USE SIGNAL ;
    PORT
      LAYER met2 ;
        RECT 714.010 496.000 714.290 500.000 ;
    END
  END div0_sstream_i[49]
  PIN div0_sstream_i[4]
    DIRECTION INPUT ;
    USE SIGNAL ;
    ANTENNAGATEAREA 0.426000 ;
    PORT
      LAYER met2 ;
        RECT 610.510 496.000 610.790 500.000 ;
    END
  END div0_sstream_i[4]
  PIN div0_sstream_i[5]
    DIRECTION INPUT ;
    USE SIGNAL ;
    ANTENNAGATEAREA 0.426000 ;
    PORT
      LAYER met2 ;
        RECT 612.810 496.000 613.090 500.000 ;
    END
  END div0_sstream_i[5]
  PIN div0_sstream_i[6]
    DIRECTION INPUT ;
    USE SIGNAL ;
    ANTENNAGATEAREA 0.247500 ;
    PORT
      LAYER met2 ;
        RECT 615.110 496.000 615.390 500.000 ;
    END
  END div0_sstream_i[6]
  PIN div0_sstream_i[7]
    DIRECTION INPUT ;
    USE SIGNAL ;
    ANTENNAGATEAREA 0.426000 ;
    PORT
      LAYER met2 ;
        RECT 617.410 496.000 617.690 500.000 ;
    END
  END div0_sstream_i[7]
  PIN div0_sstream_i[8]
    DIRECTION INPUT ;
    USE SIGNAL ;
    ANTENNAGATEAREA 0.495000 ;
    PORT
      LAYER met2 ;
        RECT 619.710 496.000 619.990 500.000 ;
    END
  END div0_sstream_i[8]
  PIN div0_sstream_i[9]
    DIRECTION INPUT ;
    USE SIGNAL ;
    ANTENNAGATEAREA 0.495000 ;
    PORT
      LAYER met2 ;
        RECT 622.010 496.000 622.290 500.000 ;
    END
  END div0_sstream_i[9]
  PIN div0_sstream_o
    DIRECTION OUTPUT TRISTATE ;
    USE SIGNAL ;
    ANTENNADIFFAREA 0.795200 ;
    PORT
      LAYER met2 ;
        RECT 718.610 496.000 718.890 500.000 ;
    END
  END div0_sstream_o
  PIN div1_mstream_i
    DIRECTION INPUT ;
    USE SIGNAL ;
    ANTENNAGATEAREA 0.213000 ;
    PORT
      LAYER met2 ;
        RECT 481.710 496.000 481.990 500.000 ;
    END
  END div1_mstream_i
  PIN div1_mstream_o[0]
    DIRECTION OUTPUT TRISTATE ;
    USE SIGNAL ;
    ANTENNADIFFAREA 0.795200 ;
    PORT
      LAYER met2 ;
        RECT 30.910 496.000 31.190 500.000 ;
    END
  END div1_mstream_o[0]
  PIN div1_mstream_o[10]
    DIRECTION OUTPUT TRISTATE ;
    USE SIGNAL ;
    ANTENNADIFFAREA 0.795200 ;
    PORT
      LAYER met2 ;
        RECT 53.910 496.000 54.190 500.000 ;
    END
  END div1_mstream_o[10]
  PIN div1_mstream_o[11]
    DIRECTION OUTPUT TRISTATE ;
    USE SIGNAL ;
    ANTENNADIFFAREA 0.795200 ;
    PORT
      LAYER met2 ;
        RECT 56.210 496.000 56.490 500.000 ;
    END
  END div1_mstream_o[11]
  PIN div1_mstream_o[12]
    DIRECTION OUTPUT TRISTATE ;
    USE SIGNAL ;
    ANTENNADIFFAREA 0.795200 ;
    PORT
      LAYER met2 ;
        RECT 58.510 496.000 58.790 500.000 ;
    END
  END div1_mstream_o[12]
  PIN div1_mstream_o[13]
    DIRECTION OUTPUT TRISTATE ;
    USE SIGNAL ;
    ANTENNADIFFAREA 0.795200 ;
    PORT
      LAYER met2 ;
        RECT 60.810 496.000 61.090 500.000 ;
    END
  END div1_mstream_o[13]
  PIN div1_mstream_o[14]
    DIRECTION OUTPUT TRISTATE ;
    USE SIGNAL ;
    ANTENNADIFFAREA 0.795200 ;
    PORT
      LAYER met2 ;
        RECT 63.110 496.000 63.390 500.000 ;
    END
  END div1_mstream_o[14]
  PIN div1_mstream_o[15]
    DIRECTION OUTPUT TRISTATE ;
    USE SIGNAL ;
    ANTENNADIFFAREA 0.795200 ;
    PORT
      LAYER met2 ;
        RECT 65.410 496.000 65.690 500.000 ;
    END
  END div1_mstream_o[15]
  PIN div1_mstream_o[16]
    DIRECTION OUTPUT TRISTATE ;
    USE SIGNAL ;
    ANTENNADIFFAREA 0.795200 ;
    PORT
      LAYER met2 ;
        RECT 67.710 496.000 67.990 500.000 ;
    END
  END div1_mstream_o[16]
  PIN div1_mstream_o[17]
    DIRECTION OUTPUT TRISTATE ;
    USE SIGNAL ;
    ANTENNADIFFAREA 0.795200 ;
    PORT
      LAYER met2 ;
        RECT 70.010 496.000 70.290 500.000 ;
    END
  END div1_mstream_o[17]
  PIN div1_mstream_o[18]
    DIRECTION OUTPUT TRISTATE ;
    USE SIGNAL ;
    ANTENNADIFFAREA 0.795200 ;
    PORT
      LAYER met2 ;
        RECT 72.310 496.000 72.590 500.000 ;
    END
  END div1_mstream_o[18]
  PIN div1_mstream_o[19]
    DIRECTION OUTPUT TRISTATE ;
    USE SIGNAL ;
    ANTENNADIFFAREA 0.795200 ;
    PORT
      LAYER met2 ;
        RECT 74.610 496.000 74.890 500.000 ;
    END
  END div1_mstream_o[19]
  PIN div1_mstream_o[1]
    DIRECTION OUTPUT TRISTATE ;
    USE SIGNAL ;
    ANTENNADIFFAREA 0.795200 ;
    PORT
      LAYER met2 ;
        RECT 33.210 496.000 33.490 500.000 ;
    END
  END div1_mstream_o[1]
  PIN div1_mstream_o[20]
    DIRECTION OUTPUT TRISTATE ;
    USE SIGNAL ;
    ANTENNADIFFAREA 0.795200 ;
    PORT
      LAYER met2 ;
        RECT 76.910 496.000 77.190 500.000 ;
    END
  END div1_mstream_o[20]
  PIN div1_mstream_o[21]
    DIRECTION OUTPUT TRISTATE ;
    USE SIGNAL ;
    ANTENNADIFFAREA 0.795200 ;
    PORT
      LAYER met2 ;
        RECT 79.210 496.000 79.490 500.000 ;
    END
  END div1_mstream_o[21]
  PIN div1_mstream_o[22]
    DIRECTION OUTPUT TRISTATE ;
    USE SIGNAL ;
    ANTENNADIFFAREA 0.795200 ;
    PORT
      LAYER met2 ;
        RECT 81.510 496.000 81.790 500.000 ;
    END
  END div1_mstream_o[22]
  PIN div1_mstream_o[23]
    DIRECTION OUTPUT TRISTATE ;
    USE SIGNAL ;
    ANTENNADIFFAREA 0.795200 ;
    PORT
      LAYER met2 ;
        RECT 83.810 496.000 84.090 500.000 ;
    END
  END div1_mstream_o[23]
  PIN div1_mstream_o[24]
    DIRECTION OUTPUT TRISTATE ;
    USE SIGNAL ;
    ANTENNADIFFAREA 0.795200 ;
    PORT
      LAYER met2 ;
        RECT 86.110 496.000 86.390 500.000 ;
    END
  END div1_mstream_o[24]
  PIN div1_mstream_o[25]
    DIRECTION OUTPUT TRISTATE ;
    USE SIGNAL ;
    ANTENNADIFFAREA 0.795200 ;
    PORT
      LAYER met2 ;
        RECT 88.410 496.000 88.690 500.000 ;
    END
  END div1_mstream_o[25]
  PIN div1_mstream_o[26]
    DIRECTION OUTPUT TRISTATE ;
    USE SIGNAL ;
    ANTENNADIFFAREA 0.795200 ;
    PORT
      LAYER met2 ;
        RECT 90.710 496.000 90.990 500.000 ;
    END
  END div1_mstream_o[26]
  PIN div1_mstream_o[27]
    DIRECTION OUTPUT TRISTATE ;
    USE SIGNAL ;
    ANTENNADIFFAREA 0.795200 ;
    PORT
      LAYER met2 ;
        RECT 93.010 496.000 93.290 500.000 ;
    END
  END div1_mstream_o[27]
  PIN div1_mstream_o[28]
    DIRECTION OUTPUT TRISTATE ;
    USE SIGNAL ;
    ANTENNADIFFAREA 0.795200 ;
    PORT
      LAYER met2 ;
        RECT 95.310 496.000 95.590 500.000 ;
    END
  END div1_mstream_o[28]
  PIN div1_mstream_o[29]
    DIRECTION OUTPUT TRISTATE ;
    USE SIGNAL ;
    ANTENNADIFFAREA 0.795200 ;
    PORT
      LAYER met2 ;
        RECT 97.610 496.000 97.890 500.000 ;
    END
  END div1_mstream_o[29]
  PIN div1_mstream_o[2]
    DIRECTION OUTPUT TRISTATE ;
    USE SIGNAL ;
    ANTENNADIFFAREA 0.795200 ;
    PORT
      LAYER met2 ;
        RECT 35.510 496.000 35.790 500.000 ;
    END
  END div1_mstream_o[2]
  PIN div1_mstream_o[30]
    DIRECTION OUTPUT TRISTATE ;
    USE SIGNAL ;
    ANTENNADIFFAREA 0.795200 ;
    PORT
      LAYER met2 ;
        RECT 99.910 496.000 100.190 500.000 ;
    END
  END div1_mstream_o[30]
  PIN div1_mstream_o[31]
    DIRECTION OUTPUT TRISTATE ;
    USE SIGNAL ;
    ANTENNADIFFAREA 0.795200 ;
    PORT
      LAYER met2 ;
        RECT 102.210 496.000 102.490 500.000 ;
    END
  END div1_mstream_o[31]
  PIN div1_mstream_o[32]
    DIRECTION OUTPUT TRISTATE ;
    USE SIGNAL ;
    ANTENNADIFFAREA 0.795200 ;
    PORT
      LAYER met2 ;
        RECT 104.510 496.000 104.790 500.000 ;
    END
  END div1_mstream_o[32]
  PIN div1_mstream_o[33]
    DIRECTION OUTPUT TRISTATE ;
    USE SIGNAL ;
    ANTENNADIFFAREA 0.795200 ;
    PORT
      LAYER met2 ;
        RECT 106.810 496.000 107.090 500.000 ;
    END
  END div1_mstream_o[33]
  PIN div1_mstream_o[34]
    DIRECTION OUTPUT TRISTATE ;
    USE SIGNAL ;
    ANTENNADIFFAREA 0.795200 ;
    PORT
      LAYER met2 ;
        RECT 109.110 496.000 109.390 500.000 ;
    END
  END div1_mstream_o[34]
  PIN div1_mstream_o[35]
    DIRECTION OUTPUT TRISTATE ;
    USE SIGNAL ;
    ANTENNADIFFAREA 0.795200 ;
    PORT
      LAYER met2 ;
        RECT 111.410 496.000 111.690 500.000 ;
    END
  END div1_mstream_o[35]
  PIN div1_mstream_o[36]
    DIRECTION OUTPUT TRISTATE ;
    USE SIGNAL ;
    ANTENNADIFFAREA 0.795200 ;
    PORT
      LAYER met2 ;
        RECT 113.710 496.000 113.990 500.000 ;
    END
  END div1_mstream_o[36]
  PIN div1_mstream_o[37]
    DIRECTION OUTPUT TRISTATE ;
    USE SIGNAL ;
    ANTENNADIFFAREA 0.795200 ;
    PORT
      LAYER met2 ;
        RECT 116.010 496.000 116.290 500.000 ;
    END
  END div1_mstream_o[37]
  PIN div1_mstream_o[38]
    DIRECTION OUTPUT TRISTATE ;
    USE SIGNAL ;
    ANTENNADIFFAREA 0.795200 ;
    PORT
      LAYER met2 ;
        RECT 118.310 496.000 118.590 500.000 ;
    END
  END div1_mstream_o[38]
  PIN div1_mstream_o[39]
    DIRECTION OUTPUT TRISTATE ;
    USE SIGNAL ;
    ANTENNADIFFAREA 0.795200 ;
    PORT
      LAYER met2 ;
        RECT 120.610 496.000 120.890 500.000 ;
    END
  END div1_mstream_o[39]
  PIN div1_mstream_o[3]
    DIRECTION OUTPUT TRISTATE ;
    USE SIGNAL ;
    ANTENNADIFFAREA 0.795200 ;
    PORT
      LAYER met2 ;
        RECT 37.810 496.000 38.090 500.000 ;
    END
  END div1_mstream_o[3]
  PIN div1_mstream_o[40]
    DIRECTION OUTPUT TRISTATE ;
    USE SIGNAL ;
    ANTENNADIFFAREA 0.795200 ;
    PORT
      LAYER met2 ;
        RECT 122.910 496.000 123.190 500.000 ;
    END
  END div1_mstream_o[40]
  PIN div1_mstream_o[41]
    DIRECTION OUTPUT TRISTATE ;
    USE SIGNAL ;
    ANTENNADIFFAREA 0.795200 ;
    PORT
      LAYER met2 ;
        RECT 125.210 496.000 125.490 500.000 ;
    END
  END div1_mstream_o[41]
  PIN div1_mstream_o[42]
    DIRECTION OUTPUT TRISTATE ;
    USE SIGNAL ;
    ANTENNADIFFAREA 0.795200 ;
    PORT
      LAYER met2 ;
        RECT 127.510 496.000 127.790 500.000 ;
    END
  END div1_mstream_o[42]
  PIN div1_mstream_o[43]
    DIRECTION OUTPUT TRISTATE ;
    USE SIGNAL ;
    ANTENNADIFFAREA 0.795200 ;
    PORT
      LAYER met2 ;
        RECT 129.810 496.000 130.090 500.000 ;
    END
  END div1_mstream_o[43]
  PIN div1_mstream_o[44]
    DIRECTION OUTPUT TRISTATE ;
    USE SIGNAL ;
    ANTENNADIFFAREA 0.795200 ;
    PORT
      LAYER met2 ;
        RECT 132.110 496.000 132.390 500.000 ;
    END
  END div1_mstream_o[44]
  PIN div1_mstream_o[45]
    DIRECTION OUTPUT TRISTATE ;
    USE SIGNAL ;
    ANTENNADIFFAREA 0.795200 ;
    PORT
      LAYER met2 ;
        RECT 134.410 496.000 134.690 500.000 ;
    END
  END div1_mstream_o[45]
  PIN div1_mstream_o[46]
    DIRECTION OUTPUT TRISTATE ;
    USE SIGNAL ;
    ANTENNADIFFAREA 0.795200 ;
    PORT
      LAYER met2 ;
        RECT 136.710 496.000 136.990 500.000 ;
    END
  END div1_mstream_o[46]
  PIN div1_mstream_o[47]
    DIRECTION OUTPUT TRISTATE ;
    USE SIGNAL ;
    ANTENNADIFFAREA 0.795200 ;
    PORT
      LAYER met2 ;
        RECT 139.010 496.000 139.290 500.000 ;
    END
  END div1_mstream_o[47]
  PIN div1_mstream_o[48]
    DIRECTION OUTPUT TRISTATE ;
    USE SIGNAL ;
    ANTENNADIFFAREA 0.795200 ;
    PORT
      LAYER met2 ;
        RECT 141.310 496.000 141.590 500.000 ;
    END
  END div1_mstream_o[48]
  PIN div1_mstream_o[49]
    DIRECTION OUTPUT TRISTATE ;
    USE SIGNAL ;
    ANTENNADIFFAREA 0.795200 ;
    PORT
      LAYER met2 ;
        RECT 143.610 496.000 143.890 500.000 ;
    END
  END div1_mstream_o[49]
  PIN div1_mstream_o[4]
    DIRECTION OUTPUT TRISTATE ;
    USE SIGNAL ;
    ANTENNADIFFAREA 0.795200 ;
    PORT
      LAYER met2 ;
        RECT 40.110 496.000 40.390 500.000 ;
    END
  END div1_mstream_o[4]
  PIN div1_mstream_o[50]
    DIRECTION OUTPUT TRISTATE ;
    USE SIGNAL ;
    ANTENNADIFFAREA 0.795200 ;
    PORT
      LAYER met2 ;
        RECT 145.910 496.000 146.190 500.000 ;
    END
  END div1_mstream_o[50]
  PIN div1_mstream_o[51]
    DIRECTION OUTPUT TRISTATE ;
    USE SIGNAL ;
    ANTENNADIFFAREA 0.795200 ;
    PORT
      LAYER met2 ;
        RECT 148.210 496.000 148.490 500.000 ;
    END
  END div1_mstream_o[51]
  PIN div1_mstream_o[52]
    DIRECTION OUTPUT TRISTATE ;
    USE SIGNAL ;
    ANTENNADIFFAREA 0.795200 ;
    PORT
      LAYER met2 ;
        RECT 150.510 496.000 150.790 500.000 ;
    END
  END div1_mstream_o[52]
  PIN div1_mstream_o[53]
    DIRECTION OUTPUT TRISTATE ;
    USE SIGNAL ;
    ANTENNADIFFAREA 0.795200 ;
    PORT
      LAYER met2 ;
        RECT 152.810 496.000 153.090 500.000 ;
    END
  END div1_mstream_o[53]
  PIN div1_mstream_o[54]
    DIRECTION OUTPUT TRISTATE ;
    USE SIGNAL ;
    ANTENNADIFFAREA 0.795200 ;
    PORT
      LAYER met2 ;
        RECT 155.110 496.000 155.390 500.000 ;
    END
  END div1_mstream_o[54]
  PIN div1_mstream_o[55]
    DIRECTION OUTPUT TRISTATE ;
    USE SIGNAL ;
    ANTENNADIFFAREA 0.795200 ;
    PORT
      LAYER met2 ;
        RECT 157.410 496.000 157.690 500.000 ;
    END
  END div1_mstream_o[55]
  PIN div1_mstream_o[56]
    DIRECTION OUTPUT TRISTATE ;
    USE SIGNAL ;
    ANTENNADIFFAREA 0.795200 ;
    PORT
      LAYER met2 ;
        RECT 159.710 496.000 159.990 500.000 ;
    END
  END div1_mstream_o[56]
  PIN div1_mstream_o[57]
    DIRECTION OUTPUT TRISTATE ;
    USE SIGNAL ;
    ANTENNADIFFAREA 0.795200 ;
    PORT
      LAYER met2 ;
        RECT 162.010 496.000 162.290 500.000 ;
    END
  END div1_mstream_o[57]
  PIN div1_mstream_o[58]
    DIRECTION OUTPUT TRISTATE ;
    USE SIGNAL ;
    ANTENNADIFFAREA 0.795200 ;
    PORT
      LAYER met2 ;
        RECT 164.310 496.000 164.590 500.000 ;
    END
  END div1_mstream_o[58]
  PIN div1_mstream_o[59]
    DIRECTION OUTPUT TRISTATE ;
    USE SIGNAL ;
    ANTENNADIFFAREA 0.795200 ;
    PORT
      LAYER met2 ;
        RECT 166.610 496.000 166.890 500.000 ;
    END
  END div1_mstream_o[59]
  PIN div1_mstream_o[5]
    DIRECTION OUTPUT TRISTATE ;
    USE SIGNAL ;
    ANTENNADIFFAREA 0.795200 ;
    PORT
      LAYER met2 ;
        RECT 42.410 496.000 42.690 500.000 ;
    END
  END div1_mstream_o[5]
  PIN div1_mstream_o[60]
    DIRECTION OUTPUT TRISTATE ;
    USE SIGNAL ;
    ANTENNADIFFAREA 0.795200 ;
    PORT
      LAYER met2 ;
        RECT 168.910 496.000 169.190 500.000 ;
    END
  END div1_mstream_o[60]
  PIN div1_mstream_o[61]
    DIRECTION OUTPUT TRISTATE ;
    USE SIGNAL ;
    ANTENNADIFFAREA 0.795200 ;
    PORT
      LAYER met2 ;
        RECT 171.210 496.000 171.490 500.000 ;
    END
  END div1_mstream_o[61]
  PIN div1_mstream_o[62]
    DIRECTION OUTPUT TRISTATE ;
    USE SIGNAL ;
    ANTENNADIFFAREA 0.795200 ;
    PORT
      LAYER met2 ;
        RECT 173.510 496.000 173.790 500.000 ;
    END
  END div1_mstream_o[62]
  PIN div1_mstream_o[63]
    DIRECTION OUTPUT TRISTATE ;
    USE SIGNAL ;
    ANTENNADIFFAREA 0.795200 ;
    PORT
      LAYER met2 ;
        RECT 175.810 496.000 176.090 500.000 ;
    END
  END div1_mstream_o[63]
  PIN div1_mstream_o[64]
    DIRECTION OUTPUT TRISTATE ;
    USE SIGNAL ;
    ANTENNADIFFAREA 0.795200 ;
    PORT
      LAYER met2 ;
        RECT 178.110 496.000 178.390 500.000 ;
    END
  END div1_mstream_o[64]
  PIN div1_mstream_o[65]
    DIRECTION OUTPUT TRISTATE ;
    USE SIGNAL ;
    ANTENNADIFFAREA 0.795200 ;
    PORT
      LAYER met2 ;
        RECT 180.410 496.000 180.690 500.000 ;
    END
  END div1_mstream_o[65]
  PIN div1_mstream_o[66]
    DIRECTION OUTPUT TRISTATE ;
    USE SIGNAL ;
    ANTENNADIFFAREA 0.795200 ;
    PORT
      LAYER met2 ;
        RECT 182.710 496.000 182.990 500.000 ;
    END
  END div1_mstream_o[66]
  PIN div1_mstream_o[67]
    DIRECTION OUTPUT TRISTATE ;
    USE SIGNAL ;
    ANTENNADIFFAREA 0.795200 ;
    PORT
      LAYER met2 ;
        RECT 185.010 496.000 185.290 500.000 ;
    END
  END div1_mstream_o[67]
  PIN div1_mstream_o[68]
    DIRECTION OUTPUT TRISTATE ;
    USE SIGNAL ;
    ANTENNADIFFAREA 0.795200 ;
    PORT
      LAYER met2 ;
        RECT 187.310 496.000 187.590 500.000 ;
    END
  END div1_mstream_o[68]
  PIN div1_mstream_o[69]
    DIRECTION OUTPUT TRISTATE ;
    USE SIGNAL ;
    ANTENNADIFFAREA 0.795200 ;
    PORT
      LAYER met2 ;
        RECT 189.610 496.000 189.890 500.000 ;
    END
  END div1_mstream_o[69]
  PIN div1_mstream_o[6]
    DIRECTION OUTPUT TRISTATE ;
    USE SIGNAL ;
    ANTENNADIFFAREA 0.795200 ;
    PORT
      LAYER met2 ;
        RECT 44.710 496.000 44.990 500.000 ;
    END
  END div1_mstream_o[6]
  PIN div1_mstream_o[70]
    DIRECTION OUTPUT TRISTATE ;
    USE SIGNAL ;
    ANTENNADIFFAREA 0.795200 ;
    PORT
      LAYER met2 ;
        RECT 191.910 496.000 192.190 500.000 ;
    END
  END div1_mstream_o[70]
  PIN div1_mstream_o[71]
    DIRECTION OUTPUT TRISTATE ;
    USE SIGNAL ;
    ANTENNADIFFAREA 0.795200 ;
    PORT
      LAYER met2 ;
        RECT 194.210 496.000 194.490 500.000 ;
    END
  END div1_mstream_o[71]
  PIN div1_mstream_o[72]
    DIRECTION OUTPUT TRISTATE ;
    USE SIGNAL ;
    ANTENNADIFFAREA 0.795200 ;
    PORT
      LAYER met2 ;
        RECT 196.510 496.000 196.790 500.000 ;
    END
  END div1_mstream_o[72]
  PIN div1_mstream_o[73]
    DIRECTION OUTPUT TRISTATE ;
    USE SIGNAL ;
    ANTENNADIFFAREA 0.795200 ;
    PORT
      LAYER met2 ;
        RECT 198.810 496.000 199.090 500.000 ;
    END
  END div1_mstream_o[73]
  PIN div1_mstream_o[74]
    DIRECTION OUTPUT TRISTATE ;
    USE SIGNAL ;
    ANTENNADIFFAREA 0.795200 ;
    PORT
      LAYER met2 ;
        RECT 201.110 496.000 201.390 500.000 ;
    END
  END div1_mstream_o[74]
  PIN div1_mstream_o[75]
    DIRECTION OUTPUT TRISTATE ;
    USE SIGNAL ;
    ANTENNADIFFAREA 0.795200 ;
    PORT
      LAYER met2 ;
        RECT 203.410 496.000 203.690 500.000 ;
    END
  END div1_mstream_o[75]
  PIN div1_mstream_o[76]
    DIRECTION OUTPUT TRISTATE ;
    USE SIGNAL ;
    ANTENNADIFFAREA 0.795200 ;
    PORT
      LAYER met2 ;
        RECT 205.710 496.000 205.990 500.000 ;
    END
  END div1_mstream_o[76]
  PIN div1_mstream_o[77]
    DIRECTION OUTPUT TRISTATE ;
    USE SIGNAL ;
    ANTENNADIFFAREA 0.795200 ;
    PORT
      LAYER met2 ;
        RECT 208.010 496.000 208.290 500.000 ;
    END
  END div1_mstream_o[77]
  PIN div1_mstream_o[78]
    DIRECTION OUTPUT TRISTATE ;
    USE SIGNAL ;
    ANTENNADIFFAREA 0.795200 ;
    PORT
      LAYER met2 ;
        RECT 210.310 496.000 210.590 500.000 ;
    END
  END div1_mstream_o[78]
  PIN div1_mstream_o[79]
    DIRECTION OUTPUT TRISTATE ;
    USE SIGNAL ;
    ANTENNADIFFAREA 0.795200 ;
    PORT
      LAYER met2 ;
        RECT 212.610 496.000 212.890 500.000 ;
    END
  END div1_mstream_o[79]
  PIN div1_mstream_o[7]
    DIRECTION OUTPUT TRISTATE ;
    USE SIGNAL ;
    ANTENNADIFFAREA 0.795200 ;
    PORT
      LAYER met2 ;
        RECT 47.010 496.000 47.290 500.000 ;
    END
  END div1_mstream_o[7]
  PIN div1_mstream_o[80]
    DIRECTION OUTPUT TRISTATE ;
    USE SIGNAL ;
    ANTENNADIFFAREA 0.795200 ;
    PORT
      LAYER met2 ;
        RECT 214.910 496.000 215.190 500.000 ;
    END
  END div1_mstream_o[80]
  PIN div1_mstream_o[81]
    DIRECTION OUTPUT TRISTATE ;
    USE SIGNAL ;
    ANTENNADIFFAREA 0.795200 ;
    PORT
      LAYER met2 ;
        RECT 217.210 496.000 217.490 500.000 ;
    END
  END div1_mstream_o[81]
  PIN div1_mstream_o[82]
    DIRECTION OUTPUT TRISTATE ;
    USE SIGNAL ;
    ANTENNADIFFAREA 0.795200 ;
    PORT
      LAYER met2 ;
        RECT 219.510 496.000 219.790 500.000 ;
    END
  END div1_mstream_o[82]
  PIN div1_mstream_o[83]
    DIRECTION OUTPUT TRISTATE ;
    USE SIGNAL ;
    ANTENNADIFFAREA 0.795200 ;
    PORT
      LAYER met2 ;
        RECT 221.810 496.000 222.090 500.000 ;
    END
  END div1_mstream_o[83]
  PIN div1_mstream_o[84]
    DIRECTION OUTPUT TRISTATE ;
    USE SIGNAL ;
    ANTENNADIFFAREA 0.795200 ;
    PORT
      LAYER met2 ;
        RECT 224.110 496.000 224.390 500.000 ;
    END
  END div1_mstream_o[84]
  PIN div1_mstream_o[85]
    DIRECTION OUTPUT TRISTATE ;
    USE SIGNAL ;
    ANTENNADIFFAREA 0.795200 ;
    PORT
      LAYER met2 ;
        RECT 226.410 496.000 226.690 500.000 ;
    END
  END div1_mstream_o[85]
  PIN div1_mstream_o[86]
    DIRECTION OUTPUT TRISTATE ;
    USE SIGNAL ;
    ANTENNADIFFAREA 0.795200 ;
    PORT
      LAYER met2 ;
        RECT 228.710 496.000 228.990 500.000 ;
    END
  END div1_mstream_o[86]
  PIN div1_mstream_o[87]
    DIRECTION OUTPUT TRISTATE ;
    USE SIGNAL ;
    ANTENNADIFFAREA 0.795200 ;
    PORT
      LAYER met2 ;
        RECT 231.010 496.000 231.290 500.000 ;
    END
  END div1_mstream_o[87]
  PIN div1_mstream_o[88]
    DIRECTION OUTPUT TRISTATE ;
    USE SIGNAL ;
    ANTENNADIFFAREA 0.795200 ;
    PORT
      LAYER met2 ;
        RECT 233.310 496.000 233.590 500.000 ;
    END
  END div1_mstream_o[88]
  PIN div1_mstream_o[89]
    DIRECTION OUTPUT TRISTATE ;
    USE SIGNAL ;
    ANTENNADIFFAREA 0.795200 ;
    PORT
      LAYER met2 ;
        RECT 235.610 496.000 235.890 500.000 ;
    END
  END div1_mstream_o[89]
  PIN div1_mstream_o[8]
    DIRECTION OUTPUT TRISTATE ;
    USE SIGNAL ;
    ANTENNADIFFAREA 0.795200 ;
    PORT
      LAYER met2 ;
        RECT 49.310 496.000 49.590 500.000 ;
    END
  END div1_mstream_o[8]
  PIN div1_mstream_o[90]
    DIRECTION OUTPUT TRISTATE ;
    USE SIGNAL ;
    ANTENNADIFFAREA 0.795200 ;
    PORT
      LAYER met2 ;
        RECT 237.910 496.000 238.190 500.000 ;
    END
  END div1_mstream_o[90]
  PIN div1_mstream_o[91]
    DIRECTION OUTPUT TRISTATE ;
    USE SIGNAL ;
    ANTENNADIFFAREA 0.795200 ;
    PORT
      LAYER met2 ;
        RECT 240.210 496.000 240.490 500.000 ;
    END
  END div1_mstream_o[91]
  PIN div1_mstream_o[92]
    DIRECTION OUTPUT TRISTATE ;
    USE SIGNAL ;
    ANTENNADIFFAREA 0.795200 ;
    PORT
      LAYER met2 ;
        RECT 242.510 496.000 242.790 500.000 ;
    END
  END div1_mstream_o[92]
  PIN div1_mstream_o[93]
    DIRECTION OUTPUT TRISTATE ;
    USE SIGNAL ;
    ANTENNADIFFAREA 0.795200 ;
    PORT
      LAYER met2 ;
        RECT 244.810 496.000 245.090 500.000 ;
    END
  END div1_mstream_o[93]
  PIN div1_mstream_o[94]
    DIRECTION OUTPUT TRISTATE ;
    USE SIGNAL ;
    ANTENNADIFFAREA 0.795200 ;
    PORT
      LAYER met2 ;
        RECT 247.110 496.000 247.390 500.000 ;
    END
  END div1_mstream_o[94]
  PIN div1_mstream_o[95]
    DIRECTION OUTPUT TRISTATE ;
    USE SIGNAL ;
    ANTENNADIFFAREA 0.795200 ;
    PORT
      LAYER met2 ;
        RECT 249.410 496.000 249.690 500.000 ;
    END
  END div1_mstream_o[95]
  PIN div1_mstream_o[96]
    DIRECTION OUTPUT TRISTATE ;
    USE SIGNAL ;
    ANTENNADIFFAREA 0.795200 ;
    PORT
      LAYER met2 ;
        RECT 251.710 496.000 251.990 500.000 ;
    END
  END div1_mstream_o[96]
  PIN div1_mstream_o[97]
    DIRECTION OUTPUT TRISTATE ;
    USE SIGNAL ;
    PORT
      LAYER met2 ;
        RECT 254.010 496.000 254.290 500.000 ;
    END
  END div1_mstream_o[97]
  PIN div1_mstream_o[9]
    DIRECTION OUTPUT TRISTATE ;
    USE SIGNAL ;
    ANTENNADIFFAREA 0.795200 ;
    PORT
      LAYER met2 ;
        RECT 51.610 496.000 51.890 500.000 ;
    END
  END div1_mstream_o[9]
  PIN div1_sstream_i[0]
    DIRECTION INPUT ;
    USE SIGNAL ;
    ANTENNAGATEAREA 0.247500 ;
    PORT
      LAYER met2 ;
        RECT 486.310 496.000 486.590 500.000 ;
    END
  END div1_sstream_i[0]
  PIN div1_sstream_i[10]
    DIRECTION INPUT ;
    USE SIGNAL ;
    ANTENNAGATEAREA 0.247500 ;
    PORT
      LAYER met2 ;
        RECT 509.310 496.000 509.590 500.000 ;
    END
  END div1_sstream_i[10]
  PIN div1_sstream_i[11]
    DIRECTION INPUT ;
    USE SIGNAL ;
    ANTENNAGATEAREA 0.247500 ;
    PORT
      LAYER met2 ;
        RECT 511.610 496.000 511.890 500.000 ;
    END
  END div1_sstream_i[11]
  PIN div1_sstream_i[12]
    DIRECTION INPUT ;
    USE SIGNAL ;
    ANTENNAGATEAREA 0.247500 ;
    PORT
      LAYER met2 ;
        RECT 513.910 496.000 514.190 500.000 ;
    END
  END div1_sstream_i[12]
  PIN div1_sstream_i[13]
    DIRECTION INPUT ;
    USE SIGNAL ;
    ANTENNAGATEAREA 0.247500 ;
    PORT
      LAYER met2 ;
        RECT 516.210 496.000 516.490 500.000 ;
    END
  END div1_sstream_i[13]
  PIN div1_sstream_i[14]
    DIRECTION INPUT ;
    USE SIGNAL ;
    ANTENNAGATEAREA 0.247500 ;
    PORT
      LAYER met2 ;
        RECT 518.510 496.000 518.790 500.000 ;
    END
  END div1_sstream_i[14]
  PIN div1_sstream_i[15]
    DIRECTION INPUT ;
    USE SIGNAL ;
    ANTENNAGATEAREA 0.247500 ;
    PORT
      LAYER met2 ;
        RECT 520.810 496.000 521.090 500.000 ;
    END
  END div1_sstream_i[15]
  PIN div1_sstream_i[16]
    DIRECTION INPUT ;
    USE SIGNAL ;
    ANTENNAGATEAREA 0.495000 ;
    PORT
      LAYER met2 ;
        RECT 523.110 496.000 523.390 500.000 ;
    END
  END div1_sstream_i[16]
  PIN div1_sstream_i[17]
    DIRECTION INPUT ;
    USE SIGNAL ;
    ANTENNAGATEAREA 0.495000 ;
    PORT
      LAYER met2 ;
        RECT 525.410 496.000 525.690 500.000 ;
    END
  END div1_sstream_i[17]
  PIN div1_sstream_i[18]
    DIRECTION INPUT ;
    USE SIGNAL ;
    ANTENNAGATEAREA 0.426000 ;
    PORT
      LAYER met2 ;
        RECT 527.710 496.000 527.990 500.000 ;
    END
  END div1_sstream_i[18]
  PIN div1_sstream_i[19]
    DIRECTION INPUT ;
    USE SIGNAL ;
    ANTENNAGATEAREA 0.426000 ;
    PORT
      LAYER met2 ;
        RECT 530.010 496.000 530.290 500.000 ;
    END
  END div1_sstream_i[19]
  PIN div1_sstream_i[1]
    DIRECTION INPUT ;
    USE SIGNAL ;
    ANTENNAGATEAREA 0.247500 ;
    PORT
      LAYER met2 ;
        RECT 488.610 496.000 488.890 500.000 ;
    END
  END div1_sstream_i[1]
  PIN div1_sstream_i[20]
    DIRECTION INPUT ;
    USE SIGNAL ;
    ANTENNAGATEAREA 0.495000 ;
    PORT
      LAYER met2 ;
        RECT 532.310 496.000 532.590 500.000 ;
    END
  END div1_sstream_i[20]
  PIN div1_sstream_i[21]
    DIRECTION INPUT ;
    USE SIGNAL ;
    ANTENNAGATEAREA 0.495000 ;
    PORT
      LAYER met2 ;
        RECT 534.610 496.000 534.890 500.000 ;
    END
  END div1_sstream_i[21]
  PIN div1_sstream_i[22]
    DIRECTION INPUT ;
    USE SIGNAL ;
    ANTENNAGATEAREA 0.426000 ;
    PORT
      LAYER met2 ;
        RECT 536.910 496.000 537.190 500.000 ;
    END
  END div1_sstream_i[22]
  PIN div1_sstream_i[23]
    DIRECTION INPUT ;
    USE SIGNAL ;
    ANTENNAGATEAREA 0.426000 ;
    PORT
      LAYER met2 ;
        RECT 539.210 496.000 539.490 500.000 ;
    END
  END div1_sstream_i[23]
  PIN div1_sstream_i[24]
    DIRECTION INPUT ;
    USE SIGNAL ;
    ANTENNAGATEAREA 0.495000 ;
    PORT
      LAYER met2 ;
        RECT 541.510 496.000 541.790 500.000 ;
    END
  END div1_sstream_i[24]
  PIN div1_sstream_i[25]
    DIRECTION INPUT ;
    USE SIGNAL ;
    ANTENNAGATEAREA 0.426000 ;
    PORT
      LAYER met2 ;
        RECT 543.810 496.000 544.090 500.000 ;
    END
  END div1_sstream_i[25]
  PIN div1_sstream_i[26]
    DIRECTION INPUT ;
    USE SIGNAL ;
    ANTENNAGATEAREA 0.426000 ;
    PORT
      LAYER met2 ;
        RECT 546.110 496.000 546.390 500.000 ;
    END
  END div1_sstream_i[26]
  PIN div1_sstream_i[27]
    DIRECTION INPUT ;
    USE SIGNAL ;
    ANTENNAGATEAREA 0.426000 ;
    PORT
      LAYER met2 ;
        RECT 548.410 496.000 548.690 500.000 ;
    END
  END div1_sstream_i[27]
  PIN div1_sstream_i[28]
    DIRECTION INPUT ;
    USE SIGNAL ;
    ANTENNAGATEAREA 0.426000 ;
    PORT
      LAYER met2 ;
        RECT 550.710 496.000 550.990 500.000 ;
    END
  END div1_sstream_i[28]
  PIN div1_sstream_i[29]
    DIRECTION INPUT ;
    USE SIGNAL ;
    ANTENNAGATEAREA 0.426000 ;
    PORT
      LAYER met2 ;
        RECT 553.010 496.000 553.290 500.000 ;
    END
  END div1_sstream_i[29]
  PIN div1_sstream_i[2]
    DIRECTION INPUT ;
    USE SIGNAL ;
    ANTENNAGATEAREA 0.247500 ;
    PORT
      LAYER met2 ;
        RECT 490.910 496.000 491.190 500.000 ;
    END
  END div1_sstream_i[2]
  PIN div1_sstream_i[30]
    DIRECTION INPUT ;
    USE SIGNAL ;
    ANTENNAGATEAREA 0.426000 ;
    PORT
      LAYER met2 ;
        RECT 555.310 496.000 555.590 500.000 ;
    END
  END div1_sstream_i[30]
  PIN div1_sstream_i[31]
    DIRECTION INPUT ;
    USE SIGNAL ;
    ANTENNAGATEAREA 0.426000 ;
    PORT
      LAYER met2 ;
        RECT 557.610 496.000 557.890 500.000 ;
    END
  END div1_sstream_i[31]
  PIN div1_sstream_i[32]
    DIRECTION INPUT ;
    USE SIGNAL ;
    PORT
      LAYER met2 ;
        RECT 559.910 496.000 560.190 500.000 ;
    END
  END div1_sstream_i[32]
  PIN div1_sstream_i[33]
    DIRECTION INPUT ;
    USE SIGNAL ;
    PORT
      LAYER met2 ;
        RECT 562.210 496.000 562.490 500.000 ;
    END
  END div1_sstream_i[33]
  PIN div1_sstream_i[34]
    DIRECTION INPUT ;
    USE SIGNAL ;
    PORT
      LAYER met2 ;
        RECT 564.510 496.000 564.790 500.000 ;
    END
  END div1_sstream_i[34]
  PIN div1_sstream_i[35]
    DIRECTION INPUT ;
    USE SIGNAL ;
    PORT
      LAYER met2 ;
        RECT 566.810 496.000 567.090 500.000 ;
    END
  END div1_sstream_i[35]
  PIN div1_sstream_i[36]
    DIRECTION INPUT ;
    USE SIGNAL ;
    PORT
      LAYER met2 ;
        RECT 569.110 496.000 569.390 500.000 ;
    END
  END div1_sstream_i[36]
  PIN div1_sstream_i[37]
    DIRECTION INPUT ;
    USE SIGNAL ;
    PORT
      LAYER met2 ;
        RECT 571.410 496.000 571.690 500.000 ;
    END
  END div1_sstream_i[37]
  PIN div1_sstream_i[38]
    DIRECTION INPUT ;
    USE SIGNAL ;
    PORT
      LAYER met2 ;
        RECT 573.710 496.000 573.990 500.000 ;
    END
  END div1_sstream_i[38]
  PIN div1_sstream_i[39]
    DIRECTION INPUT ;
    USE SIGNAL ;
    PORT
      LAYER met2 ;
        RECT 576.010 496.000 576.290 500.000 ;
    END
  END div1_sstream_i[39]
  PIN div1_sstream_i[3]
    DIRECTION INPUT ;
    USE SIGNAL ;
    ANTENNAGATEAREA 0.247500 ;
    PORT
      LAYER met2 ;
        RECT 493.210 496.000 493.490 500.000 ;
    END
  END div1_sstream_i[3]
  PIN div1_sstream_i[40]
    DIRECTION INPUT ;
    USE SIGNAL ;
    PORT
      LAYER met2 ;
        RECT 578.310 496.000 578.590 500.000 ;
    END
  END div1_sstream_i[40]
  PIN div1_sstream_i[41]
    DIRECTION INPUT ;
    USE SIGNAL ;
    PORT
      LAYER met2 ;
        RECT 580.610 496.000 580.890 500.000 ;
    END
  END div1_sstream_i[41]
  PIN div1_sstream_i[42]
    DIRECTION INPUT ;
    USE SIGNAL ;
    PORT
      LAYER met2 ;
        RECT 582.910 496.000 583.190 500.000 ;
    END
  END div1_sstream_i[42]
  PIN div1_sstream_i[43]
    DIRECTION INPUT ;
    USE SIGNAL ;
    PORT
      LAYER met2 ;
        RECT 585.210 496.000 585.490 500.000 ;
    END
  END div1_sstream_i[43]
  PIN div1_sstream_i[44]
    DIRECTION INPUT ;
    USE SIGNAL ;
    PORT
      LAYER met2 ;
        RECT 587.510 496.000 587.790 500.000 ;
    END
  END div1_sstream_i[44]
  PIN div1_sstream_i[45]
    DIRECTION INPUT ;
    USE SIGNAL ;
    PORT
      LAYER met2 ;
        RECT 589.810 496.000 590.090 500.000 ;
    END
  END div1_sstream_i[45]
  PIN div1_sstream_i[46]
    DIRECTION INPUT ;
    USE SIGNAL ;
    PORT
      LAYER met2 ;
        RECT 592.110 496.000 592.390 500.000 ;
    END
  END div1_sstream_i[46]
  PIN div1_sstream_i[47]
    DIRECTION INPUT ;
    USE SIGNAL ;
    PORT
      LAYER met2 ;
        RECT 594.410 496.000 594.690 500.000 ;
    END
  END div1_sstream_i[47]
  PIN div1_sstream_i[48]
    DIRECTION INPUT ;
    USE SIGNAL ;
    ANTENNAGATEAREA 0.247500 ;
    PORT
      LAYER met2 ;
        RECT 596.710 496.000 596.990 500.000 ;
    END
  END div1_sstream_i[48]
  PIN div1_sstream_i[49]
    DIRECTION INPUT ;
    USE SIGNAL ;
    PORT
      LAYER met2 ;
        RECT 599.010 496.000 599.290 500.000 ;
    END
  END div1_sstream_i[49]
  PIN div1_sstream_i[4]
    DIRECTION INPUT ;
    USE SIGNAL ;
    ANTENNAGATEAREA 0.247500 ;
    PORT
      LAYER met2 ;
        RECT 495.510 496.000 495.790 500.000 ;
    END
  END div1_sstream_i[4]
  PIN div1_sstream_i[5]
    DIRECTION INPUT ;
    USE SIGNAL ;
    ANTENNAGATEAREA 0.247500 ;
    PORT
      LAYER met2 ;
        RECT 497.810 496.000 498.090 500.000 ;
    END
  END div1_sstream_i[5]
  PIN div1_sstream_i[6]
    DIRECTION INPUT ;
    USE SIGNAL ;
    ANTENNAGATEAREA 0.247500 ;
    PORT
      LAYER met2 ;
        RECT 500.110 496.000 500.390 500.000 ;
    END
  END div1_sstream_i[6]
  PIN div1_sstream_i[7]
    DIRECTION INPUT ;
    USE SIGNAL ;
    ANTENNAGATEAREA 0.247500 ;
    PORT
      LAYER met2 ;
        RECT 502.410 496.000 502.690 500.000 ;
    END
  END div1_sstream_i[7]
  PIN div1_sstream_i[8]
    DIRECTION INPUT ;
    USE SIGNAL ;
    ANTENNAGATEAREA 0.247500 ;
    PORT
      LAYER met2 ;
        RECT 504.710 496.000 504.990 500.000 ;
    END
  END div1_sstream_i[8]
  PIN div1_sstream_i[9]
    DIRECTION INPUT ;
    USE SIGNAL ;
    ANTENNAGATEAREA 0.247500 ;
    PORT
      LAYER met2 ;
        RECT 507.010 496.000 507.290 500.000 ;
    END
  END div1_sstream_i[9]
  PIN div1_sstream_o
    DIRECTION OUTPUT TRISTATE ;
    USE SIGNAL ;
    ANTENNADIFFAREA 0.795200 ;
    PORT
      LAYER met2 ;
        RECT 716.310 496.000 716.590 500.000 ;
    END
  END div1_sstream_o
  PIN mstream_i
    DIRECTION INPUT ;
    USE SIGNAL ;
    ANTENNAGATEAREA 0.196500 ;
    PORT
      LAYER met3 ;
        RECT 746.000 61.240 750.000 61.840 ;
    END
  END mstream_i
  PIN mstream_o[0]
    DIRECTION OUTPUT TRISTATE ;
    USE SIGNAL ;
    ANTENNADIFFAREA 0.795200 ;
    PORT
      LAYER met3 ;
        RECT 746.000 62.600 750.000 63.200 ;
    END
  END mstream_o[0]
  PIN mstream_o[100]
    DIRECTION OUTPUT TRISTATE ;
    USE SIGNAL ;
    ANTENNADIFFAREA 0.795200 ;
    PORT
      LAYER met3 ;
        RECT 746.000 198.600 750.000 199.200 ;
    END
  END mstream_o[100]
  PIN mstream_o[101]
    DIRECTION OUTPUT TRISTATE ;
    USE SIGNAL ;
    ANTENNADIFFAREA 0.795200 ;
    PORT
      LAYER met3 ;
        RECT 746.000 199.960 750.000 200.560 ;
    END
  END mstream_o[101]
  PIN mstream_o[102]
    DIRECTION OUTPUT TRISTATE ;
    USE SIGNAL ;
    ANTENNADIFFAREA 0.795200 ;
    PORT
      LAYER met3 ;
        RECT 746.000 201.320 750.000 201.920 ;
    END
  END mstream_o[102]
  PIN mstream_o[103]
    DIRECTION OUTPUT TRISTATE ;
    USE SIGNAL ;
    ANTENNADIFFAREA 0.795200 ;
    PORT
      LAYER met3 ;
        RECT 746.000 202.680 750.000 203.280 ;
    END
  END mstream_o[103]
  PIN mstream_o[104]
    DIRECTION OUTPUT TRISTATE ;
    USE SIGNAL ;
    ANTENNADIFFAREA 0.795200 ;
    PORT
      LAYER met3 ;
        RECT 746.000 204.040 750.000 204.640 ;
    END
  END mstream_o[104]
  PIN mstream_o[105]
    DIRECTION OUTPUT TRISTATE ;
    USE SIGNAL ;
    ANTENNADIFFAREA 0.795200 ;
    PORT
      LAYER met3 ;
        RECT 746.000 205.400 750.000 206.000 ;
    END
  END mstream_o[105]
  PIN mstream_o[106]
    DIRECTION OUTPUT TRISTATE ;
    USE SIGNAL ;
    ANTENNADIFFAREA 0.795200 ;
    PORT
      LAYER met3 ;
        RECT 746.000 206.760 750.000 207.360 ;
    END
  END mstream_o[106]
  PIN mstream_o[107]
    DIRECTION OUTPUT TRISTATE ;
    USE SIGNAL ;
    ANTENNADIFFAREA 0.795200 ;
    PORT
      LAYER met3 ;
        RECT 746.000 208.120 750.000 208.720 ;
    END
  END mstream_o[107]
  PIN mstream_o[108]
    DIRECTION OUTPUT TRISTATE ;
    USE SIGNAL ;
    ANTENNADIFFAREA 0.795200 ;
    PORT
      LAYER met3 ;
        RECT 746.000 209.480 750.000 210.080 ;
    END
  END mstream_o[108]
  PIN mstream_o[109]
    DIRECTION OUTPUT TRISTATE ;
    USE SIGNAL ;
    ANTENNADIFFAREA 0.795200 ;
    PORT
      LAYER met3 ;
        RECT 746.000 210.840 750.000 211.440 ;
    END
  END mstream_o[109]
  PIN mstream_o[10]
    DIRECTION OUTPUT TRISTATE ;
    USE SIGNAL ;
    ANTENNADIFFAREA 0.795200 ;
    PORT
      LAYER met3 ;
        RECT 746.000 76.200 750.000 76.800 ;
    END
  END mstream_o[10]
  PIN mstream_o[110]
    DIRECTION OUTPUT TRISTATE ;
    USE SIGNAL ;
    ANTENNADIFFAREA 0.795200 ;
    PORT
      LAYER met3 ;
        RECT 746.000 212.200 750.000 212.800 ;
    END
  END mstream_o[110]
  PIN mstream_o[111]
    DIRECTION OUTPUT TRISTATE ;
    USE SIGNAL ;
    ANTENNADIFFAREA 0.795200 ;
    PORT
      LAYER met3 ;
        RECT 746.000 213.560 750.000 214.160 ;
    END
  END mstream_o[111]
  PIN mstream_o[112]
    DIRECTION OUTPUT TRISTATE ;
    USE SIGNAL ;
    ANTENNADIFFAREA 0.795200 ;
    PORT
      LAYER met3 ;
        RECT 746.000 214.920 750.000 215.520 ;
    END
  END mstream_o[112]
  PIN mstream_o[113]
    DIRECTION OUTPUT TRISTATE ;
    USE SIGNAL ;
    ANTENNADIFFAREA 0.795200 ;
    PORT
      LAYER met3 ;
        RECT 746.000 216.280 750.000 216.880 ;
    END
  END mstream_o[113]
  PIN mstream_o[114]
    DIRECTION OUTPUT TRISTATE ;
    USE SIGNAL ;
    ANTENNADIFFAREA 0.795200 ;
    PORT
      LAYER met3 ;
        RECT 746.000 217.640 750.000 218.240 ;
    END
  END mstream_o[114]
  PIN mstream_o[115]
    DIRECTION OUTPUT TRISTATE ;
    USE SIGNAL ;
    ANTENNADIFFAREA 0.795200 ;
    PORT
      LAYER met3 ;
        RECT 746.000 219.000 750.000 219.600 ;
    END
  END mstream_o[115]
  PIN mstream_o[116]
    DIRECTION OUTPUT TRISTATE ;
    USE SIGNAL ;
    ANTENNADIFFAREA 0.795200 ;
    PORT
      LAYER met3 ;
        RECT 746.000 220.360 750.000 220.960 ;
    END
  END mstream_o[116]
  PIN mstream_o[117]
    DIRECTION OUTPUT TRISTATE ;
    USE SIGNAL ;
    ANTENNADIFFAREA 0.795200 ;
    PORT
      LAYER met3 ;
        RECT 746.000 221.720 750.000 222.320 ;
    END
  END mstream_o[117]
  PIN mstream_o[118]
    DIRECTION OUTPUT TRISTATE ;
    USE SIGNAL ;
    ANTENNADIFFAREA 0.795200 ;
    PORT
      LAYER met3 ;
        RECT 746.000 223.080 750.000 223.680 ;
    END
  END mstream_o[118]
  PIN mstream_o[119]
    DIRECTION OUTPUT TRISTATE ;
    USE SIGNAL ;
    ANTENNADIFFAREA 0.795200 ;
    PORT
      LAYER met3 ;
        RECT 746.000 224.440 750.000 225.040 ;
    END
  END mstream_o[119]
  PIN mstream_o[11]
    DIRECTION OUTPUT TRISTATE ;
    USE SIGNAL ;
    ANTENNADIFFAREA 0.795200 ;
    PORT
      LAYER met3 ;
        RECT 746.000 77.560 750.000 78.160 ;
    END
  END mstream_o[11]
  PIN mstream_o[120]
    DIRECTION OUTPUT TRISTATE ;
    USE SIGNAL ;
    ANTENNADIFFAREA 0.795200 ;
    PORT
      LAYER met3 ;
        RECT 746.000 225.800 750.000 226.400 ;
    END
  END mstream_o[120]
  PIN mstream_o[121]
    DIRECTION OUTPUT TRISTATE ;
    USE SIGNAL ;
    ANTENNADIFFAREA 0.445500 ;
    PORT
      LAYER met3 ;
        RECT 746.000 227.160 750.000 227.760 ;
    END
  END mstream_o[121]
  PIN mstream_o[122]
    DIRECTION OUTPUT TRISTATE ;
    USE SIGNAL ;
    ANTENNADIFFAREA 0.795200 ;
    PORT
      LAYER met3 ;
        RECT 746.000 228.520 750.000 229.120 ;
    END
  END mstream_o[122]
  PIN mstream_o[123]
    DIRECTION OUTPUT TRISTATE ;
    USE SIGNAL ;
    ANTENNADIFFAREA 0.795200 ;
    PORT
      LAYER met3 ;
        RECT 746.000 229.880 750.000 230.480 ;
    END
  END mstream_o[123]
  PIN mstream_o[124]
    DIRECTION OUTPUT TRISTATE ;
    USE SIGNAL ;
    ANTENNADIFFAREA 0.795200 ;
    PORT
      LAYER met3 ;
        RECT 746.000 231.240 750.000 231.840 ;
    END
  END mstream_o[124]
  PIN mstream_o[125]
    DIRECTION OUTPUT TRISTATE ;
    USE SIGNAL ;
    ANTENNADIFFAREA 0.795200 ;
    PORT
      LAYER met3 ;
        RECT 746.000 232.600 750.000 233.200 ;
    END
  END mstream_o[125]
  PIN mstream_o[126]
    DIRECTION OUTPUT TRISTATE ;
    USE SIGNAL ;
    ANTENNADIFFAREA 0.795200 ;
    PORT
      LAYER met3 ;
        RECT 746.000 233.960 750.000 234.560 ;
    END
  END mstream_o[126]
  PIN mstream_o[127]
    DIRECTION OUTPUT TRISTATE ;
    USE SIGNAL ;
    ANTENNADIFFAREA 0.795200 ;
    PORT
      LAYER met3 ;
        RECT 746.000 235.320 750.000 235.920 ;
    END
  END mstream_o[127]
  PIN mstream_o[128]
    DIRECTION OUTPUT TRISTATE ;
    USE SIGNAL ;
    ANTENNADIFFAREA 0.445500 ;
    PORT
      LAYER met3 ;
        RECT 746.000 236.680 750.000 237.280 ;
    END
  END mstream_o[128]
  PIN mstream_o[129]
    DIRECTION OUTPUT TRISTATE ;
    USE SIGNAL ;
    ANTENNADIFFAREA 0.445500 ;
    PORT
      LAYER met3 ;
        RECT 746.000 238.040 750.000 238.640 ;
    END
  END mstream_o[129]
  PIN mstream_o[12]
    DIRECTION OUTPUT TRISTATE ;
    USE SIGNAL ;
    ANTENNADIFFAREA 0.795200 ;
    PORT
      LAYER met3 ;
        RECT 746.000 78.920 750.000 79.520 ;
    END
  END mstream_o[12]
  PIN mstream_o[130]
    DIRECTION OUTPUT TRISTATE ;
    USE SIGNAL ;
    ANTENNADIFFAREA 0.445500 ;
    PORT
      LAYER met3 ;
        RECT 746.000 239.400 750.000 240.000 ;
    END
  END mstream_o[130]
  PIN mstream_o[131]
    DIRECTION OUTPUT TRISTATE ;
    USE SIGNAL ;
    ANTENNADIFFAREA 0.795200 ;
    PORT
      LAYER met3 ;
        RECT 746.000 240.760 750.000 241.360 ;
    END
  END mstream_o[131]
  PIN mstream_o[132]
    DIRECTION OUTPUT TRISTATE ;
    USE SIGNAL ;
    ANTENNADIFFAREA 0.445500 ;
    PORT
      LAYER met3 ;
        RECT 746.000 242.120 750.000 242.720 ;
    END
  END mstream_o[132]
  PIN mstream_o[133]
    DIRECTION OUTPUT TRISTATE ;
    USE SIGNAL ;
    ANTENNADIFFAREA 0.445500 ;
    PORT
      LAYER met3 ;
        RECT 746.000 243.480 750.000 244.080 ;
    END
  END mstream_o[133]
  PIN mstream_o[134]
    DIRECTION OUTPUT TRISTATE ;
    USE SIGNAL ;
    ANTENNADIFFAREA 0.445500 ;
    PORT
      LAYER met3 ;
        RECT 746.000 244.840 750.000 245.440 ;
    END
  END mstream_o[134]
  PIN mstream_o[135]
    DIRECTION OUTPUT TRISTATE ;
    USE SIGNAL ;
    ANTENNADIFFAREA 0.795200 ;
    PORT
      LAYER met3 ;
        RECT 746.000 246.200 750.000 246.800 ;
    END
  END mstream_o[135]
  PIN mstream_o[136]
    DIRECTION OUTPUT TRISTATE ;
    USE SIGNAL ;
    ANTENNADIFFAREA 0.795200 ;
    PORT
      LAYER met3 ;
        RECT 746.000 247.560 750.000 248.160 ;
    END
  END mstream_o[136]
  PIN mstream_o[137]
    DIRECTION OUTPUT TRISTATE ;
    USE SIGNAL ;
    ANTENNADIFFAREA 0.445500 ;
    PORT
      LAYER met3 ;
        RECT 746.000 248.920 750.000 249.520 ;
    END
  END mstream_o[137]
  PIN mstream_o[138]
    DIRECTION OUTPUT TRISTATE ;
    USE SIGNAL ;
    ANTENNADIFFAREA 0.445500 ;
    PORT
      LAYER met3 ;
        RECT 746.000 250.280 750.000 250.880 ;
    END
  END mstream_o[138]
  PIN mstream_o[139]
    DIRECTION OUTPUT TRISTATE ;
    USE SIGNAL ;
    ANTENNADIFFAREA 0.445500 ;
    PORT
      LAYER met3 ;
        RECT 746.000 251.640 750.000 252.240 ;
    END
  END mstream_o[139]
  PIN mstream_o[13]
    DIRECTION OUTPUT TRISTATE ;
    USE SIGNAL ;
    ANTENNADIFFAREA 0.795200 ;
    PORT
      LAYER met3 ;
        RECT 746.000 80.280 750.000 80.880 ;
    END
  END mstream_o[13]
  PIN mstream_o[140]
    DIRECTION OUTPUT TRISTATE ;
    USE SIGNAL ;
    ANTENNADIFFAREA 0.445500 ;
    PORT
      LAYER met3 ;
        RECT 746.000 253.000 750.000 253.600 ;
    END
  END mstream_o[140]
  PIN mstream_o[141]
    DIRECTION OUTPUT TRISTATE ;
    USE SIGNAL ;
    ANTENNADIFFAREA 0.795200 ;
    PORT
      LAYER met3 ;
        RECT 746.000 254.360 750.000 254.960 ;
    END
  END mstream_o[141]
  PIN mstream_o[142]
    DIRECTION OUTPUT TRISTATE ;
    USE SIGNAL ;
    ANTENNADIFFAREA 0.445500 ;
    PORT
      LAYER met3 ;
        RECT 746.000 255.720 750.000 256.320 ;
    END
  END mstream_o[142]
  PIN mstream_o[143]
    DIRECTION OUTPUT TRISTATE ;
    USE SIGNAL ;
    ANTENNADIFFAREA 0.445500 ;
    PORT
      LAYER met3 ;
        RECT 746.000 257.080 750.000 257.680 ;
    END
  END mstream_o[143]
  PIN mstream_o[144]
    DIRECTION OUTPUT TRISTATE ;
    USE SIGNAL ;
    ANTENNADIFFAREA 0.445500 ;
    PORT
      LAYER met3 ;
        RECT 746.000 258.440 750.000 259.040 ;
    END
  END mstream_o[144]
  PIN mstream_o[145]
    DIRECTION OUTPUT TRISTATE ;
    USE SIGNAL ;
    ANTENNADIFFAREA 0.795200 ;
    PORT
      LAYER met3 ;
        RECT 746.000 259.800 750.000 260.400 ;
    END
  END mstream_o[145]
  PIN mstream_o[146]
    DIRECTION OUTPUT TRISTATE ;
    USE SIGNAL ;
    ANTENNADIFFAREA 0.795200 ;
    PORT
      LAYER met3 ;
        RECT 746.000 261.160 750.000 261.760 ;
    END
  END mstream_o[146]
  PIN mstream_o[147]
    DIRECTION OUTPUT TRISTATE ;
    USE SIGNAL ;
    ANTENNADIFFAREA 0.445500 ;
    PORT
      LAYER met3 ;
        RECT 746.000 262.520 750.000 263.120 ;
    END
  END mstream_o[147]
  PIN mstream_o[148]
    DIRECTION OUTPUT TRISTATE ;
    USE SIGNAL ;
    ANTENNADIFFAREA 0.445500 ;
    PORT
      LAYER met3 ;
        RECT 746.000 263.880 750.000 264.480 ;
    END
  END mstream_o[148]
  PIN mstream_o[149]
    DIRECTION OUTPUT TRISTATE ;
    USE SIGNAL ;
    ANTENNADIFFAREA 0.445500 ;
    PORT
      LAYER met3 ;
        RECT 746.000 265.240 750.000 265.840 ;
    END
  END mstream_o[149]
  PIN mstream_o[14]
    DIRECTION OUTPUT TRISTATE ;
    USE SIGNAL ;
    ANTENNADIFFAREA 0.795200 ;
    PORT
      LAYER met3 ;
        RECT 746.000 81.640 750.000 82.240 ;
    END
  END mstream_o[14]
  PIN mstream_o[150]
    DIRECTION OUTPUT TRISTATE ;
    USE SIGNAL ;
    ANTENNADIFFAREA 0.445500 ;
    PORT
      LAYER met3 ;
        RECT 746.000 266.600 750.000 267.200 ;
    END
  END mstream_o[150]
  PIN mstream_o[151]
    DIRECTION OUTPUT TRISTATE ;
    USE SIGNAL ;
    ANTENNADIFFAREA 0.795200 ;
    PORT
      LAYER met3 ;
        RECT 746.000 267.960 750.000 268.560 ;
    END
  END mstream_o[151]
  PIN mstream_o[152]
    DIRECTION OUTPUT TRISTATE ;
    USE SIGNAL ;
    ANTENNADIFFAREA 0.445500 ;
    PORT
      LAYER met3 ;
        RECT 746.000 269.320 750.000 269.920 ;
    END
  END mstream_o[152]
  PIN mstream_o[153]
    DIRECTION OUTPUT TRISTATE ;
    USE SIGNAL ;
    ANTENNADIFFAREA 0.445500 ;
    PORT
      LAYER met3 ;
        RECT 746.000 270.680 750.000 271.280 ;
    END
  END mstream_o[153]
  PIN mstream_o[154]
    DIRECTION OUTPUT TRISTATE ;
    USE SIGNAL ;
    ANTENNADIFFAREA 0.445500 ;
    PORT
      LAYER met3 ;
        RECT 746.000 272.040 750.000 272.640 ;
    END
  END mstream_o[154]
  PIN mstream_o[155]
    DIRECTION OUTPUT TRISTATE ;
    USE SIGNAL ;
    ANTENNADIFFAREA 0.795200 ;
    PORT
      LAYER met3 ;
        RECT 746.000 273.400 750.000 274.000 ;
    END
  END mstream_o[155]
  PIN mstream_o[156]
    DIRECTION OUTPUT TRISTATE ;
    USE SIGNAL ;
    ANTENNADIFFAREA 0.795200 ;
    PORT
      LAYER met3 ;
        RECT 746.000 274.760 750.000 275.360 ;
    END
  END mstream_o[156]
  PIN mstream_o[157]
    DIRECTION OUTPUT TRISTATE ;
    USE SIGNAL ;
    ANTENNADIFFAREA 0.445500 ;
    PORT
      LAYER met3 ;
        RECT 746.000 276.120 750.000 276.720 ;
    END
  END mstream_o[157]
  PIN mstream_o[158]
    DIRECTION OUTPUT TRISTATE ;
    USE SIGNAL ;
    ANTENNADIFFAREA 0.445500 ;
    PORT
      LAYER met3 ;
        RECT 746.000 277.480 750.000 278.080 ;
    END
  END mstream_o[158]
  PIN mstream_o[159]
    DIRECTION OUTPUT TRISTATE ;
    USE SIGNAL ;
    ANTENNADIFFAREA 0.445500 ;
    PORT
      LAYER met3 ;
        RECT 746.000 278.840 750.000 279.440 ;
    END
  END mstream_o[159]
  PIN mstream_o[15]
    DIRECTION OUTPUT TRISTATE ;
    USE SIGNAL ;
    ANTENNADIFFAREA 0.795200 ;
    PORT
      LAYER met3 ;
        RECT 746.000 83.000 750.000 83.600 ;
    END
  END mstream_o[15]
  PIN mstream_o[160]
    DIRECTION OUTPUT TRISTATE ;
    USE SIGNAL ;
    ANTENNADIFFAREA 0.445500 ;
    PORT
      LAYER met3 ;
        RECT 746.000 280.200 750.000 280.800 ;
    END
  END mstream_o[160]
  PIN mstream_o[161]
    DIRECTION OUTPUT TRISTATE ;
    USE SIGNAL ;
    ANTENNADIFFAREA 0.795200 ;
    PORT
      LAYER met3 ;
        RECT 746.000 281.560 750.000 282.160 ;
    END
  END mstream_o[161]
  PIN mstream_o[162]
    DIRECTION OUTPUT TRISTATE ;
    USE SIGNAL ;
    ANTENNADIFFAREA 0.795200 ;
    PORT
      LAYER met3 ;
        RECT 746.000 282.920 750.000 283.520 ;
    END
  END mstream_o[162]
  PIN mstream_o[163]
    DIRECTION OUTPUT TRISTATE ;
    USE SIGNAL ;
    ANTENNADIFFAREA 0.445500 ;
    PORT
      LAYER met3 ;
        RECT 746.000 284.280 750.000 284.880 ;
    END
  END mstream_o[163]
  PIN mstream_o[164]
    DIRECTION OUTPUT TRISTATE ;
    USE SIGNAL ;
    ANTENNADIFFAREA 0.445500 ;
    PORT
      LAYER met3 ;
        RECT 746.000 285.640 750.000 286.240 ;
    END
  END mstream_o[164]
  PIN mstream_o[165]
    DIRECTION OUTPUT TRISTATE ;
    USE SIGNAL ;
    ANTENNADIFFAREA 0.445500 ;
    PORT
      LAYER met3 ;
        RECT 746.000 287.000 750.000 287.600 ;
    END
  END mstream_o[165]
  PIN mstream_o[166]
    DIRECTION OUTPUT TRISTATE ;
    USE SIGNAL ;
    ANTENNADIFFAREA 0.445500 ;
    PORT
      LAYER met3 ;
        RECT 746.000 288.360 750.000 288.960 ;
    END
  END mstream_o[166]
  PIN mstream_o[167]
    DIRECTION OUTPUT TRISTATE ;
    USE SIGNAL ;
    ANTENNADIFFAREA 0.445500 ;
    PORT
      LAYER met3 ;
        RECT 746.000 289.720 750.000 290.320 ;
    END
  END mstream_o[167]
  PIN mstream_o[168]
    DIRECTION OUTPUT TRISTATE ;
    USE SIGNAL ;
    ANTENNADIFFAREA 0.445500 ;
    PORT
      LAYER met3 ;
        RECT 746.000 291.080 750.000 291.680 ;
    END
  END mstream_o[168]
  PIN mstream_o[169]
    DIRECTION OUTPUT TRISTATE ;
    USE SIGNAL ;
    ANTENNADIFFAREA 0.445500 ;
    PORT
      LAYER met3 ;
        RECT 746.000 292.440 750.000 293.040 ;
    END
  END mstream_o[169]
  PIN mstream_o[16]
    DIRECTION OUTPUT TRISTATE ;
    USE SIGNAL ;
    ANTENNADIFFAREA 0.795200 ;
    PORT
      LAYER met3 ;
        RECT 746.000 84.360 750.000 84.960 ;
    END
  END mstream_o[16]
  PIN mstream_o[170]
    DIRECTION OUTPUT TRISTATE ;
    USE SIGNAL ;
    ANTENNADIFFAREA 0.445500 ;
    PORT
      LAYER met3 ;
        RECT 746.000 293.800 750.000 294.400 ;
    END
  END mstream_o[170]
  PIN mstream_o[171]
    DIRECTION OUTPUT TRISTATE ;
    USE SIGNAL ;
    ANTENNADIFFAREA 0.795200 ;
    PORT
      LAYER met3 ;
        RECT 746.000 295.160 750.000 295.760 ;
    END
  END mstream_o[171]
  PIN mstream_o[172]
    DIRECTION OUTPUT TRISTATE ;
    USE SIGNAL ;
    ANTENNADIFFAREA 0.445500 ;
    PORT
      LAYER met3 ;
        RECT 746.000 296.520 750.000 297.120 ;
    END
  END mstream_o[172]
  PIN mstream_o[173]
    DIRECTION OUTPUT TRISTATE ;
    USE SIGNAL ;
    ANTENNADIFFAREA 0.445500 ;
    PORT
      LAYER met3 ;
        RECT 746.000 297.880 750.000 298.480 ;
    END
  END mstream_o[173]
  PIN mstream_o[174]
    DIRECTION OUTPUT TRISTATE ;
    USE SIGNAL ;
    ANTENNADIFFAREA 0.445500 ;
    PORT
      LAYER met3 ;
        RECT 746.000 299.240 750.000 299.840 ;
    END
  END mstream_o[174]
  PIN mstream_o[175]
    DIRECTION OUTPUT TRISTATE ;
    USE SIGNAL ;
    ANTENNADIFFAREA 0.445500 ;
    PORT
      LAYER met3 ;
        RECT 746.000 300.600 750.000 301.200 ;
    END
  END mstream_o[175]
  PIN mstream_o[176]
    DIRECTION OUTPUT TRISTATE ;
    USE SIGNAL ;
    ANTENNADIFFAREA 0.445500 ;
    PORT
      LAYER met3 ;
        RECT 746.000 301.960 750.000 302.560 ;
    END
  END mstream_o[176]
  PIN mstream_o[177]
    DIRECTION OUTPUT TRISTATE ;
    USE SIGNAL ;
    ANTENNADIFFAREA 0.445500 ;
    PORT
      LAYER met3 ;
        RECT 746.000 303.320 750.000 303.920 ;
    END
  END mstream_o[177]
  PIN mstream_o[178]
    DIRECTION OUTPUT TRISTATE ;
    USE SIGNAL ;
    ANTENNADIFFAREA 0.795200 ;
    PORT
      LAYER met3 ;
        RECT 746.000 304.680 750.000 305.280 ;
    END
  END mstream_o[178]
  PIN mstream_o[179]
    DIRECTION OUTPUT TRISTATE ;
    USE SIGNAL ;
    ANTENNADIFFAREA 0.445500 ;
    PORT
      LAYER met3 ;
        RECT 746.000 306.040 750.000 306.640 ;
    END
  END mstream_o[179]
  PIN mstream_o[17]
    DIRECTION OUTPUT TRISTATE ;
    USE SIGNAL ;
    ANTENNADIFFAREA 0.795200 ;
    PORT
      LAYER met3 ;
        RECT 746.000 85.720 750.000 86.320 ;
    END
  END mstream_o[17]
  PIN mstream_o[180]
    DIRECTION OUTPUT TRISTATE ;
    USE SIGNAL ;
    ANTENNADIFFAREA 0.795200 ;
    PORT
      LAYER met3 ;
        RECT 746.000 307.400 750.000 308.000 ;
    END
  END mstream_o[180]
  PIN mstream_o[181]
    DIRECTION OUTPUT TRISTATE ;
    USE SIGNAL ;
    ANTENNADIFFAREA 0.795200 ;
    PORT
      LAYER met3 ;
        RECT 746.000 308.760 750.000 309.360 ;
    END
  END mstream_o[181]
  PIN mstream_o[182]
    DIRECTION OUTPUT TRISTATE ;
    USE SIGNAL ;
    ANTENNADIFFAREA 0.795200 ;
    PORT
      LAYER met3 ;
        RECT 746.000 310.120 750.000 310.720 ;
    END
  END mstream_o[182]
  PIN mstream_o[183]
    DIRECTION OUTPUT TRISTATE ;
    USE SIGNAL ;
    ANTENNADIFFAREA 0.795200 ;
    PORT
      LAYER met3 ;
        RECT 746.000 311.480 750.000 312.080 ;
    END
  END mstream_o[183]
  PIN mstream_o[184]
    DIRECTION OUTPUT TRISTATE ;
    USE SIGNAL ;
    ANTENNADIFFAREA 0.795200 ;
    PORT
      LAYER met3 ;
        RECT 746.000 312.840 750.000 313.440 ;
    END
  END mstream_o[184]
  PIN mstream_o[185]
    DIRECTION OUTPUT TRISTATE ;
    USE SIGNAL ;
    ANTENNADIFFAREA 0.445500 ;
    PORT
      LAYER met3 ;
        RECT 746.000 314.200 750.000 314.800 ;
    END
  END mstream_o[185]
  PIN mstream_o[186]
    DIRECTION OUTPUT TRISTATE ;
    USE SIGNAL ;
    ANTENNADIFFAREA 0.445500 ;
    PORT
      LAYER met3 ;
        RECT 746.000 315.560 750.000 316.160 ;
    END
  END mstream_o[186]
  PIN mstream_o[187]
    DIRECTION OUTPUT TRISTATE ;
    USE SIGNAL ;
    ANTENNADIFFAREA 0.795200 ;
    PORT
      LAYER met3 ;
        RECT 746.000 316.920 750.000 317.520 ;
    END
  END mstream_o[187]
  PIN mstream_o[188]
    DIRECTION OUTPUT TRISTATE ;
    USE SIGNAL ;
    ANTENNADIFFAREA 0.795200 ;
    PORT
      LAYER met3 ;
        RECT 746.000 318.280 750.000 318.880 ;
    END
  END mstream_o[188]
  PIN mstream_o[189]
    DIRECTION OUTPUT TRISTATE ;
    USE SIGNAL ;
    ANTENNADIFFAREA 0.795200 ;
    PORT
      LAYER met3 ;
        RECT 746.000 319.640 750.000 320.240 ;
    END
  END mstream_o[189]
  PIN mstream_o[18]
    DIRECTION OUTPUT TRISTATE ;
    USE SIGNAL ;
    ANTENNADIFFAREA 0.795200 ;
    PORT
      LAYER met3 ;
        RECT 746.000 87.080 750.000 87.680 ;
    END
  END mstream_o[18]
  PIN mstream_o[190]
    DIRECTION OUTPUT TRISTATE ;
    USE SIGNAL ;
    ANTENNADIFFAREA 0.795200 ;
    PORT
      LAYER met3 ;
        RECT 746.000 321.000 750.000 321.600 ;
    END
  END mstream_o[190]
  PIN mstream_o[191]
    DIRECTION OUTPUT TRISTATE ;
    USE SIGNAL ;
    ANTENNADIFFAREA 0.795200 ;
    PORT
      LAYER met3 ;
        RECT 746.000 322.360 750.000 322.960 ;
    END
  END mstream_o[191]
  PIN mstream_o[192]
    DIRECTION OUTPUT TRISTATE ;
    USE SIGNAL ;
    ANTENNADIFFAREA 0.795200 ;
    PORT
      LAYER met3 ;
        RECT 746.000 323.720 750.000 324.320 ;
    END
  END mstream_o[192]
  PIN mstream_o[193]
    DIRECTION OUTPUT TRISTATE ;
    USE SIGNAL ;
    ANTENNADIFFAREA 0.795200 ;
    PORT
      LAYER met3 ;
        RECT 746.000 325.080 750.000 325.680 ;
    END
  END mstream_o[193]
  PIN mstream_o[194]
    DIRECTION OUTPUT TRISTATE ;
    USE SIGNAL ;
    ANTENNADIFFAREA 0.795200 ;
    PORT
      LAYER met3 ;
        RECT 746.000 326.440 750.000 327.040 ;
    END
  END mstream_o[194]
  PIN mstream_o[195]
    DIRECTION OUTPUT TRISTATE ;
    USE SIGNAL ;
    ANTENNADIFFAREA 0.795200 ;
    PORT
      LAYER met3 ;
        RECT 746.000 327.800 750.000 328.400 ;
    END
  END mstream_o[195]
  PIN mstream_o[196]
    DIRECTION OUTPUT TRISTATE ;
    USE SIGNAL ;
    ANTENNADIFFAREA 0.795200 ;
    PORT
      LAYER met3 ;
        RECT 746.000 329.160 750.000 329.760 ;
    END
  END mstream_o[196]
  PIN mstream_o[197]
    DIRECTION OUTPUT TRISTATE ;
    USE SIGNAL ;
    ANTENNADIFFAREA 0.795200 ;
    PORT
      LAYER met3 ;
        RECT 746.000 330.520 750.000 331.120 ;
    END
  END mstream_o[197]
  PIN mstream_o[198]
    DIRECTION OUTPUT TRISTATE ;
    USE SIGNAL ;
    ANTENNADIFFAREA 0.795200 ;
    PORT
      LAYER met3 ;
        RECT 746.000 331.880 750.000 332.480 ;
    END
  END mstream_o[198]
  PIN mstream_o[199]
    DIRECTION OUTPUT TRISTATE ;
    USE SIGNAL ;
    ANTENNADIFFAREA 0.795200 ;
    PORT
      LAYER met3 ;
        RECT 746.000 333.240 750.000 333.840 ;
    END
  END mstream_o[199]
  PIN mstream_o[19]
    DIRECTION OUTPUT TRISTATE ;
    USE SIGNAL ;
    ANTENNADIFFAREA 0.795200 ;
    PORT
      LAYER met3 ;
        RECT 746.000 88.440 750.000 89.040 ;
    END
  END mstream_o[19]
  PIN mstream_o[1]
    DIRECTION OUTPUT TRISTATE ;
    USE SIGNAL ;
    ANTENNADIFFAREA 0.795200 ;
    PORT
      LAYER met3 ;
        RECT 746.000 63.960 750.000 64.560 ;
    END
  END mstream_o[1]
  PIN mstream_o[200]
    DIRECTION OUTPUT TRISTATE ;
    USE SIGNAL ;
    ANTENNADIFFAREA 0.795200 ;
    PORT
      LAYER met3 ;
        RECT 746.000 334.600 750.000 335.200 ;
    END
  END mstream_o[200]
  PIN mstream_o[201]
    DIRECTION OUTPUT TRISTATE ;
    USE SIGNAL ;
    ANTENNADIFFAREA 0.795200 ;
    PORT
      LAYER met3 ;
        RECT 746.000 335.960 750.000 336.560 ;
    END
  END mstream_o[201]
  PIN mstream_o[202]
    DIRECTION OUTPUT TRISTATE ;
    USE SIGNAL ;
    ANTENNADIFFAREA 0.795200 ;
    PORT
      LAYER met3 ;
        RECT 746.000 337.320 750.000 337.920 ;
    END
  END mstream_o[202]
  PIN mstream_o[203]
    DIRECTION OUTPUT TRISTATE ;
    USE SIGNAL ;
    ANTENNADIFFAREA 0.795200 ;
    PORT
      LAYER met3 ;
        RECT 746.000 338.680 750.000 339.280 ;
    END
  END mstream_o[203]
  PIN mstream_o[204]
    DIRECTION OUTPUT TRISTATE ;
    USE SIGNAL ;
    ANTENNADIFFAREA 0.795200 ;
    PORT
      LAYER met3 ;
        RECT 746.000 340.040 750.000 340.640 ;
    END
  END mstream_o[204]
  PIN mstream_o[205]
    DIRECTION OUTPUT TRISTATE ;
    USE SIGNAL ;
    ANTENNADIFFAREA 0.795200 ;
    PORT
      LAYER met3 ;
        RECT 746.000 341.400 750.000 342.000 ;
    END
  END mstream_o[205]
  PIN mstream_o[206]
    DIRECTION OUTPUT TRISTATE ;
    USE SIGNAL ;
    ANTENNADIFFAREA 0.795200 ;
    PORT
      LAYER met3 ;
        RECT 746.000 342.760 750.000 343.360 ;
    END
  END mstream_o[206]
  PIN mstream_o[207]
    DIRECTION OUTPUT TRISTATE ;
    USE SIGNAL ;
    ANTENNADIFFAREA 0.795200 ;
    PORT
      LAYER met3 ;
        RECT 746.000 344.120 750.000 344.720 ;
    END
  END mstream_o[207]
  PIN mstream_o[208]
    DIRECTION OUTPUT TRISTATE ;
    USE SIGNAL ;
    ANTENNADIFFAREA 0.795200 ;
    PORT
      LAYER met3 ;
        RECT 746.000 345.480 750.000 346.080 ;
    END
  END mstream_o[208]
  PIN mstream_o[209]
    DIRECTION OUTPUT TRISTATE ;
    USE SIGNAL ;
    ANTENNADIFFAREA 0.795200 ;
    PORT
      LAYER met3 ;
        RECT 746.000 346.840 750.000 347.440 ;
    END
  END mstream_o[209]
  PIN mstream_o[20]
    DIRECTION OUTPUT TRISTATE ;
    USE SIGNAL ;
    ANTENNADIFFAREA 0.795200 ;
    PORT
      LAYER met3 ;
        RECT 746.000 89.800 750.000 90.400 ;
    END
  END mstream_o[20]
  PIN mstream_o[210]
    DIRECTION OUTPUT TRISTATE ;
    USE SIGNAL ;
    ANTENNADIFFAREA 0.795200 ;
    PORT
      LAYER met3 ;
        RECT 746.000 348.200 750.000 348.800 ;
    END
  END mstream_o[210]
  PIN mstream_o[211]
    DIRECTION OUTPUT TRISTATE ;
    USE SIGNAL ;
    ANTENNADIFFAREA 0.795200 ;
    PORT
      LAYER met3 ;
        RECT 746.000 349.560 750.000 350.160 ;
    END
  END mstream_o[211]
  PIN mstream_o[212]
    DIRECTION OUTPUT TRISTATE ;
    USE SIGNAL ;
    ANTENNADIFFAREA 0.795200 ;
    PORT
      LAYER met3 ;
        RECT 746.000 350.920 750.000 351.520 ;
    END
  END mstream_o[212]
  PIN mstream_o[213]
    DIRECTION OUTPUT TRISTATE ;
    USE SIGNAL ;
    ANTENNADIFFAREA 0.795200 ;
    PORT
      LAYER met3 ;
        RECT 746.000 352.280 750.000 352.880 ;
    END
  END mstream_o[213]
  PIN mstream_o[214]
    DIRECTION OUTPUT TRISTATE ;
    USE SIGNAL ;
    ANTENNADIFFAREA 0.795200 ;
    PORT
      LAYER met3 ;
        RECT 746.000 353.640 750.000 354.240 ;
    END
  END mstream_o[214]
  PIN mstream_o[215]
    DIRECTION OUTPUT TRISTATE ;
    USE SIGNAL ;
    ANTENNADIFFAREA 0.795200 ;
    PORT
      LAYER met3 ;
        RECT 746.000 355.000 750.000 355.600 ;
    END
  END mstream_o[215]
  PIN mstream_o[216]
    DIRECTION OUTPUT TRISTATE ;
    USE SIGNAL ;
    ANTENNADIFFAREA 0.795200 ;
    PORT
      LAYER met3 ;
        RECT 746.000 356.360 750.000 356.960 ;
    END
  END mstream_o[216]
  PIN mstream_o[217]
    DIRECTION OUTPUT TRISTATE ;
    USE SIGNAL ;
    ANTENNADIFFAREA 0.795200 ;
    PORT
      LAYER met3 ;
        RECT 746.000 357.720 750.000 358.320 ;
    END
  END mstream_o[217]
  PIN mstream_o[218]
    DIRECTION OUTPUT TRISTATE ;
    USE SIGNAL ;
    ANTENNADIFFAREA 0.795200 ;
    PORT
      LAYER met3 ;
        RECT 746.000 359.080 750.000 359.680 ;
    END
  END mstream_o[218]
  PIN mstream_o[219]
    DIRECTION OUTPUT TRISTATE ;
    USE SIGNAL ;
    ANTENNADIFFAREA 0.445500 ;
    PORT
      LAYER met3 ;
        RECT 746.000 360.440 750.000 361.040 ;
    END
  END mstream_o[219]
  PIN mstream_o[21]
    DIRECTION OUTPUT TRISTATE ;
    USE SIGNAL ;
    ANTENNADIFFAREA 0.795200 ;
    PORT
      LAYER met3 ;
        RECT 746.000 91.160 750.000 91.760 ;
    END
  END mstream_o[21]
  PIN mstream_o[220]
    DIRECTION OUTPUT TRISTATE ;
    USE SIGNAL ;
    ANTENNADIFFAREA 0.795200 ;
    PORT
      LAYER met3 ;
        RECT 746.000 361.800 750.000 362.400 ;
    END
  END mstream_o[220]
  PIN mstream_o[221]
    DIRECTION OUTPUT TRISTATE ;
    USE SIGNAL ;
    ANTENNADIFFAREA 0.445500 ;
    PORT
      LAYER met3 ;
        RECT 746.000 363.160 750.000 363.760 ;
    END
  END mstream_o[221]
  PIN mstream_o[222]
    DIRECTION OUTPUT TRISTATE ;
    USE SIGNAL ;
    ANTENNADIFFAREA 0.795200 ;
    PORT
      LAYER met3 ;
        RECT 746.000 364.520 750.000 365.120 ;
    END
  END mstream_o[222]
  PIN mstream_o[223]
    DIRECTION OUTPUT TRISTATE ;
    USE SIGNAL ;
    ANTENNADIFFAREA 0.795200 ;
    PORT
      LAYER met3 ;
        RECT 746.000 365.880 750.000 366.480 ;
    END
  END mstream_o[223]
  PIN mstream_o[224]
    DIRECTION OUTPUT TRISTATE ;
    USE SIGNAL ;
    ANTENNADIFFAREA 0.795200 ;
    PORT
      LAYER met3 ;
        RECT 746.000 367.240 750.000 367.840 ;
    END
  END mstream_o[224]
  PIN mstream_o[225]
    DIRECTION OUTPUT TRISTATE ;
    USE SIGNAL ;
    ANTENNADIFFAREA 0.795200 ;
    PORT
      LAYER met3 ;
        RECT 746.000 368.600 750.000 369.200 ;
    END
  END mstream_o[225]
  PIN mstream_o[226]
    DIRECTION OUTPUT TRISTATE ;
    USE SIGNAL ;
    ANTENNADIFFAREA 0.795200 ;
    PORT
      LAYER met3 ;
        RECT 746.000 369.960 750.000 370.560 ;
    END
  END mstream_o[226]
  PIN mstream_o[227]
    DIRECTION OUTPUT TRISTATE ;
    USE SIGNAL ;
    ANTENNADIFFAREA 0.795200 ;
    PORT
      LAYER met3 ;
        RECT 746.000 371.320 750.000 371.920 ;
    END
  END mstream_o[227]
  PIN mstream_o[228]
    DIRECTION OUTPUT TRISTATE ;
    USE SIGNAL ;
    ANTENNADIFFAREA 0.795200 ;
    PORT
      LAYER met3 ;
        RECT 746.000 372.680 750.000 373.280 ;
    END
  END mstream_o[228]
  PIN mstream_o[229]
    DIRECTION OUTPUT TRISTATE ;
    USE SIGNAL ;
    ANTENNADIFFAREA 0.795200 ;
    PORT
      LAYER met3 ;
        RECT 746.000 374.040 750.000 374.640 ;
    END
  END mstream_o[229]
  PIN mstream_o[22]
    DIRECTION OUTPUT TRISTATE ;
    USE SIGNAL ;
    ANTENNADIFFAREA 0.795200 ;
    PORT
      LAYER met3 ;
        RECT 746.000 92.520 750.000 93.120 ;
    END
  END mstream_o[22]
  PIN mstream_o[230]
    DIRECTION OUTPUT TRISTATE ;
    USE SIGNAL ;
    ANTENNADIFFAREA 0.795200 ;
    PORT
      LAYER met3 ;
        RECT 746.000 375.400 750.000 376.000 ;
    END
  END mstream_o[230]
  PIN mstream_o[231]
    DIRECTION OUTPUT TRISTATE ;
    USE SIGNAL ;
    ANTENNADIFFAREA 0.795200 ;
    PORT
      LAYER met3 ;
        RECT 746.000 376.760 750.000 377.360 ;
    END
  END mstream_o[231]
  PIN mstream_o[232]
    DIRECTION OUTPUT TRISTATE ;
    USE SIGNAL ;
    ANTENNADIFFAREA 0.795200 ;
    PORT
      LAYER met3 ;
        RECT 746.000 378.120 750.000 378.720 ;
    END
  END mstream_o[232]
  PIN mstream_o[233]
    DIRECTION OUTPUT TRISTATE ;
    USE SIGNAL ;
    ANTENNADIFFAREA 0.795200 ;
    PORT
      LAYER met3 ;
        RECT 746.000 379.480 750.000 380.080 ;
    END
  END mstream_o[233]
  PIN mstream_o[234]
    DIRECTION OUTPUT TRISTATE ;
    USE SIGNAL ;
    ANTENNADIFFAREA 0.795200 ;
    PORT
      LAYER met3 ;
        RECT 746.000 380.840 750.000 381.440 ;
    END
  END mstream_o[234]
  PIN mstream_o[235]
    DIRECTION OUTPUT TRISTATE ;
    USE SIGNAL ;
    ANTENNADIFFAREA 0.795200 ;
    PORT
      LAYER met3 ;
        RECT 746.000 382.200 750.000 382.800 ;
    END
  END mstream_o[235]
  PIN mstream_o[236]
    DIRECTION OUTPUT TRISTATE ;
    USE SIGNAL ;
    ANTENNADIFFAREA 0.795200 ;
    PORT
      LAYER met3 ;
        RECT 746.000 383.560 750.000 384.160 ;
    END
  END mstream_o[236]
  PIN mstream_o[237]
    DIRECTION OUTPUT TRISTATE ;
    USE SIGNAL ;
    ANTENNADIFFAREA 0.795200 ;
    PORT
      LAYER met3 ;
        RECT 746.000 384.920 750.000 385.520 ;
    END
  END mstream_o[237]
  PIN mstream_o[238]
    DIRECTION OUTPUT TRISTATE ;
    USE SIGNAL ;
    ANTENNADIFFAREA 0.795200 ;
    PORT
      LAYER met3 ;
        RECT 746.000 386.280 750.000 386.880 ;
    END
  END mstream_o[238]
  PIN mstream_o[239]
    DIRECTION OUTPUT TRISTATE ;
    USE SIGNAL ;
    ANTENNADIFFAREA 0.795200 ;
    PORT
      LAYER met3 ;
        RECT 746.000 387.640 750.000 388.240 ;
    END
  END mstream_o[239]
  PIN mstream_o[23]
    DIRECTION OUTPUT TRISTATE ;
    USE SIGNAL ;
    ANTENNADIFFAREA 0.795200 ;
    PORT
      LAYER met3 ;
        RECT 746.000 93.880 750.000 94.480 ;
    END
  END mstream_o[23]
  PIN mstream_o[240]
    DIRECTION OUTPUT TRISTATE ;
    USE SIGNAL ;
    ANTENNADIFFAREA 0.795200 ;
    PORT
      LAYER met3 ;
        RECT 746.000 389.000 750.000 389.600 ;
    END
  END mstream_o[240]
  PIN mstream_o[241]
    DIRECTION OUTPUT TRISTATE ;
    USE SIGNAL ;
    ANTENNADIFFAREA 0.795200 ;
    PORT
      LAYER met3 ;
        RECT 746.000 390.360 750.000 390.960 ;
    END
  END mstream_o[241]
  PIN mstream_o[242]
    DIRECTION OUTPUT TRISTATE ;
    USE SIGNAL ;
    ANTENNADIFFAREA 0.795200 ;
    PORT
      LAYER met3 ;
        RECT 746.000 391.720 750.000 392.320 ;
    END
  END mstream_o[242]
  PIN mstream_o[243]
    DIRECTION OUTPUT TRISTATE ;
    USE SIGNAL ;
    ANTENNADIFFAREA 0.795200 ;
    PORT
      LAYER met3 ;
        RECT 746.000 393.080 750.000 393.680 ;
    END
  END mstream_o[243]
  PIN mstream_o[244]
    DIRECTION OUTPUT TRISTATE ;
    USE SIGNAL ;
    ANTENNADIFFAREA 0.795200 ;
    PORT
      LAYER met3 ;
        RECT 746.000 394.440 750.000 395.040 ;
    END
  END mstream_o[244]
  PIN mstream_o[245]
    DIRECTION OUTPUT TRISTATE ;
    USE SIGNAL ;
    ANTENNADIFFAREA 0.795200 ;
    PORT
      LAYER met3 ;
        RECT 746.000 395.800 750.000 396.400 ;
    END
  END mstream_o[245]
  PIN mstream_o[246]
    DIRECTION OUTPUT TRISTATE ;
    USE SIGNAL ;
    ANTENNADIFFAREA 0.795200 ;
    PORT
      LAYER met3 ;
        RECT 746.000 397.160 750.000 397.760 ;
    END
  END mstream_o[246]
  PIN mstream_o[247]
    DIRECTION OUTPUT TRISTATE ;
    USE SIGNAL ;
    ANTENNADIFFAREA 0.795200 ;
    PORT
      LAYER met3 ;
        RECT 746.000 398.520 750.000 399.120 ;
    END
  END mstream_o[247]
  PIN mstream_o[248]
    DIRECTION OUTPUT TRISTATE ;
    USE SIGNAL ;
    ANTENNADIFFAREA 0.795200 ;
    PORT
      LAYER met3 ;
        RECT 746.000 399.880 750.000 400.480 ;
    END
  END mstream_o[248]
  PIN mstream_o[249]
    DIRECTION OUTPUT TRISTATE ;
    USE SIGNAL ;
    ANTENNADIFFAREA 0.795200 ;
    PORT
      LAYER met3 ;
        RECT 746.000 401.240 750.000 401.840 ;
    END
  END mstream_o[249]
  PIN mstream_o[24]
    DIRECTION OUTPUT TRISTATE ;
    USE SIGNAL ;
    ANTENNADIFFAREA 0.795200 ;
    PORT
      LAYER met3 ;
        RECT 746.000 95.240 750.000 95.840 ;
    END
  END mstream_o[24]
  PIN mstream_o[250]
    DIRECTION OUTPUT TRISTATE ;
    USE SIGNAL ;
    ANTENNADIFFAREA 0.795200 ;
    PORT
      LAYER met3 ;
        RECT 746.000 402.600 750.000 403.200 ;
    END
  END mstream_o[250]
  PIN mstream_o[251]
    DIRECTION OUTPUT TRISTATE ;
    USE SIGNAL ;
    ANTENNADIFFAREA 0.445500 ;
    PORT
      LAYER met3 ;
        RECT 746.000 403.960 750.000 404.560 ;
    END
  END mstream_o[251]
  PIN mstream_o[252]
    DIRECTION OUTPUT TRISTATE ;
    USE SIGNAL ;
    ANTENNADIFFAREA 0.795200 ;
    PORT
      LAYER met3 ;
        RECT 746.000 405.320 750.000 405.920 ;
    END
  END mstream_o[252]
  PIN mstream_o[253]
    DIRECTION OUTPUT TRISTATE ;
    USE SIGNAL ;
    ANTENNADIFFAREA 0.795200 ;
    PORT
      LAYER met3 ;
        RECT 746.000 406.680 750.000 407.280 ;
    END
  END mstream_o[253]
  PIN mstream_o[254]
    DIRECTION OUTPUT TRISTATE ;
    USE SIGNAL ;
    ANTENNADIFFAREA 0.795200 ;
    PORT
      LAYER met3 ;
        RECT 746.000 408.040 750.000 408.640 ;
    END
  END mstream_o[254]
  PIN mstream_o[255]
    DIRECTION OUTPUT TRISTATE ;
    USE SIGNAL ;
    ANTENNADIFFAREA 0.795200 ;
    PORT
      LAYER met3 ;
        RECT 746.000 409.400 750.000 410.000 ;
    END
  END mstream_o[255]
  PIN mstream_o[256]
    DIRECTION OUTPUT TRISTATE ;
    USE SIGNAL ;
    ANTENNADIFFAREA 0.795200 ;
    PORT
      LAYER met3 ;
        RECT 746.000 410.760 750.000 411.360 ;
    END
  END mstream_o[256]
  PIN mstream_o[257]
    DIRECTION OUTPUT TRISTATE ;
    USE SIGNAL ;
    ANTENNADIFFAREA 0.795200 ;
    PORT
      LAYER met3 ;
        RECT 746.000 412.120 750.000 412.720 ;
    END
  END mstream_o[257]
  PIN mstream_o[258]
    DIRECTION OUTPUT TRISTATE ;
    USE SIGNAL ;
    ANTENNADIFFAREA 0.795200 ;
    PORT
      LAYER met3 ;
        RECT 746.000 413.480 750.000 414.080 ;
    END
  END mstream_o[258]
  PIN mstream_o[259]
    DIRECTION OUTPUT TRISTATE ;
    USE SIGNAL ;
    ANTENNADIFFAREA 0.795200 ;
    PORT
      LAYER met3 ;
        RECT 746.000 414.840 750.000 415.440 ;
    END
  END mstream_o[259]
  PIN mstream_o[25]
    DIRECTION OUTPUT TRISTATE ;
    USE SIGNAL ;
    ANTENNADIFFAREA 0.795200 ;
    PORT
      LAYER met3 ;
        RECT 746.000 96.600 750.000 97.200 ;
    END
  END mstream_o[25]
  PIN mstream_o[260]
    DIRECTION OUTPUT TRISTATE ;
    USE SIGNAL ;
    ANTENNADIFFAREA 0.795200 ;
    PORT
      LAYER met3 ;
        RECT 746.000 416.200 750.000 416.800 ;
    END
  END mstream_o[260]
  PIN mstream_o[261]
    DIRECTION OUTPUT TRISTATE ;
    USE SIGNAL ;
    ANTENNADIFFAREA 0.795200 ;
    PORT
      LAYER met3 ;
        RECT 746.000 417.560 750.000 418.160 ;
    END
  END mstream_o[261]
  PIN mstream_o[262]
    DIRECTION OUTPUT TRISTATE ;
    USE SIGNAL ;
    ANTENNADIFFAREA 0.795200 ;
    PORT
      LAYER met3 ;
        RECT 746.000 418.920 750.000 419.520 ;
    END
  END mstream_o[262]
  PIN mstream_o[263]
    DIRECTION OUTPUT TRISTATE ;
    USE SIGNAL ;
    ANTENNADIFFAREA 0.795200 ;
    PORT
      LAYER met3 ;
        RECT 746.000 420.280 750.000 420.880 ;
    END
  END mstream_o[263]
  PIN mstream_o[264]
    DIRECTION OUTPUT TRISTATE ;
    USE SIGNAL ;
    ANTENNADIFFAREA 0.795200 ;
    PORT
      LAYER met3 ;
        RECT 746.000 421.640 750.000 422.240 ;
    END
  END mstream_o[264]
  PIN mstream_o[265]
    DIRECTION OUTPUT TRISTATE ;
    USE SIGNAL ;
    ANTENNADIFFAREA 0.795200 ;
    PORT
      LAYER met3 ;
        RECT 746.000 423.000 750.000 423.600 ;
    END
  END mstream_o[265]
  PIN mstream_o[266]
    DIRECTION OUTPUT TRISTATE ;
    USE SIGNAL ;
    ANTENNADIFFAREA 0.795200 ;
    PORT
      LAYER met3 ;
        RECT 746.000 424.360 750.000 424.960 ;
    END
  END mstream_o[266]
  PIN mstream_o[267]
    DIRECTION OUTPUT TRISTATE ;
    USE SIGNAL ;
    ANTENNADIFFAREA 0.795200 ;
    PORT
      LAYER met3 ;
        RECT 746.000 425.720 750.000 426.320 ;
    END
  END mstream_o[267]
  PIN mstream_o[268]
    DIRECTION OUTPUT TRISTATE ;
    USE SIGNAL ;
    ANTENNADIFFAREA 0.795200 ;
    PORT
      LAYER met3 ;
        RECT 746.000 427.080 750.000 427.680 ;
    END
  END mstream_o[268]
  PIN mstream_o[269]
    DIRECTION OUTPUT TRISTATE ;
    USE SIGNAL ;
    ANTENNADIFFAREA 0.795200 ;
    PORT
      LAYER met3 ;
        RECT 746.000 428.440 750.000 429.040 ;
    END
  END mstream_o[269]
  PIN mstream_o[26]
    DIRECTION OUTPUT TRISTATE ;
    USE SIGNAL ;
    ANTENNADIFFAREA 0.795200 ;
    PORT
      LAYER met3 ;
        RECT 746.000 97.960 750.000 98.560 ;
    END
  END mstream_o[26]
  PIN mstream_o[270]
    DIRECTION OUTPUT TRISTATE ;
    USE SIGNAL ;
    ANTENNADIFFAREA 0.795200 ;
    PORT
      LAYER met3 ;
        RECT 746.000 429.800 750.000 430.400 ;
    END
  END mstream_o[270]
  PIN mstream_o[271]
    DIRECTION OUTPUT TRISTATE ;
    USE SIGNAL ;
    ANTENNADIFFAREA 0.795200 ;
    PORT
      LAYER met3 ;
        RECT 746.000 431.160 750.000 431.760 ;
    END
  END mstream_o[271]
  PIN mstream_o[272]
    DIRECTION OUTPUT TRISTATE ;
    USE SIGNAL ;
    ANTENNADIFFAREA 0.795200 ;
    PORT
      LAYER met3 ;
        RECT 746.000 432.520 750.000 433.120 ;
    END
  END mstream_o[272]
  PIN mstream_o[273]
    DIRECTION OUTPUT TRISTATE ;
    USE SIGNAL ;
    ANTENNADIFFAREA 0.795200 ;
    PORT
      LAYER met3 ;
        RECT 746.000 433.880 750.000 434.480 ;
    END
  END mstream_o[273]
  PIN mstream_o[274]
    DIRECTION OUTPUT TRISTATE ;
    USE SIGNAL ;
    ANTENNADIFFAREA 0.795200 ;
    PORT
      LAYER met3 ;
        RECT 746.000 435.240 750.000 435.840 ;
    END
  END mstream_o[274]
  PIN mstream_o[275]
    DIRECTION OUTPUT TRISTATE ;
    USE SIGNAL ;
    PORT
      LAYER met3 ;
        RECT 746.000 436.600 750.000 437.200 ;
    END
  END mstream_o[275]
  PIN mstream_o[27]
    DIRECTION OUTPUT TRISTATE ;
    USE SIGNAL ;
    ANTENNADIFFAREA 0.795200 ;
    PORT
      LAYER met3 ;
        RECT 746.000 99.320 750.000 99.920 ;
    END
  END mstream_o[27]
  PIN mstream_o[28]
    DIRECTION OUTPUT TRISTATE ;
    USE SIGNAL ;
    ANTENNADIFFAREA 0.795200 ;
    PORT
      LAYER met3 ;
        RECT 746.000 100.680 750.000 101.280 ;
    END
  END mstream_o[28]
  PIN mstream_o[29]
    DIRECTION OUTPUT TRISTATE ;
    USE SIGNAL ;
    ANTENNADIFFAREA 0.795200 ;
    PORT
      LAYER met3 ;
        RECT 746.000 102.040 750.000 102.640 ;
    END
  END mstream_o[29]
  PIN mstream_o[2]
    DIRECTION OUTPUT TRISTATE ;
    USE SIGNAL ;
    ANTENNADIFFAREA 0.795200 ;
    PORT
      LAYER met3 ;
        RECT 746.000 65.320 750.000 65.920 ;
    END
  END mstream_o[2]
  PIN mstream_o[30]
    DIRECTION OUTPUT TRISTATE ;
    USE SIGNAL ;
    ANTENNADIFFAREA 0.795200 ;
    PORT
      LAYER met3 ;
        RECT 746.000 103.400 750.000 104.000 ;
    END
  END mstream_o[30]
  PIN mstream_o[31]
    DIRECTION OUTPUT TRISTATE ;
    USE SIGNAL ;
    ANTENNADIFFAREA 0.795200 ;
    PORT
      LAYER met3 ;
        RECT 746.000 104.760 750.000 105.360 ;
    END
  END mstream_o[31]
  PIN mstream_o[32]
    DIRECTION OUTPUT TRISTATE ;
    USE SIGNAL ;
    ANTENNADIFFAREA 0.795200 ;
    PORT
      LAYER met3 ;
        RECT 746.000 106.120 750.000 106.720 ;
    END
  END mstream_o[32]
  PIN mstream_o[33]
    DIRECTION OUTPUT TRISTATE ;
    USE SIGNAL ;
    ANTENNADIFFAREA 0.795200 ;
    PORT
      LAYER met3 ;
        RECT 746.000 107.480 750.000 108.080 ;
    END
  END mstream_o[33]
  PIN mstream_o[34]
    DIRECTION OUTPUT TRISTATE ;
    USE SIGNAL ;
    ANTENNADIFFAREA 0.795200 ;
    PORT
      LAYER met3 ;
        RECT 746.000 108.840 750.000 109.440 ;
    END
  END mstream_o[34]
  PIN mstream_o[35]
    DIRECTION OUTPUT TRISTATE ;
    USE SIGNAL ;
    ANTENNADIFFAREA 0.795200 ;
    PORT
      LAYER met3 ;
        RECT 746.000 110.200 750.000 110.800 ;
    END
  END mstream_o[35]
  PIN mstream_o[36]
    DIRECTION OUTPUT TRISTATE ;
    USE SIGNAL ;
    ANTENNADIFFAREA 0.795200 ;
    PORT
      LAYER met3 ;
        RECT 746.000 111.560 750.000 112.160 ;
    END
  END mstream_o[36]
  PIN mstream_o[37]
    DIRECTION OUTPUT TRISTATE ;
    USE SIGNAL ;
    ANTENNADIFFAREA 0.795200 ;
    PORT
      LAYER met3 ;
        RECT 746.000 112.920 750.000 113.520 ;
    END
  END mstream_o[37]
  PIN mstream_o[38]
    DIRECTION OUTPUT TRISTATE ;
    USE SIGNAL ;
    ANTENNADIFFAREA 0.795200 ;
    PORT
      LAYER met3 ;
        RECT 746.000 114.280 750.000 114.880 ;
    END
  END mstream_o[38]
  PIN mstream_o[39]
    DIRECTION OUTPUT TRISTATE ;
    USE SIGNAL ;
    ANTENNADIFFAREA 0.795200 ;
    PORT
      LAYER met3 ;
        RECT 746.000 115.640 750.000 116.240 ;
    END
  END mstream_o[39]
  PIN mstream_o[3]
    DIRECTION OUTPUT TRISTATE ;
    USE SIGNAL ;
    ANTENNADIFFAREA 0.795200 ;
    PORT
      LAYER met3 ;
        RECT 746.000 66.680 750.000 67.280 ;
    END
  END mstream_o[3]
  PIN mstream_o[40]
    DIRECTION OUTPUT TRISTATE ;
    USE SIGNAL ;
    ANTENNADIFFAREA 0.795200 ;
    PORT
      LAYER met3 ;
        RECT 746.000 117.000 750.000 117.600 ;
    END
  END mstream_o[40]
  PIN mstream_o[41]
    DIRECTION OUTPUT TRISTATE ;
    USE SIGNAL ;
    ANTENNADIFFAREA 0.795200 ;
    PORT
      LAYER met3 ;
        RECT 746.000 118.360 750.000 118.960 ;
    END
  END mstream_o[41]
  PIN mstream_o[42]
    DIRECTION OUTPUT TRISTATE ;
    USE SIGNAL ;
    ANTENNADIFFAREA 0.795200 ;
    PORT
      LAYER met3 ;
        RECT 746.000 119.720 750.000 120.320 ;
    END
  END mstream_o[42]
  PIN mstream_o[43]
    DIRECTION OUTPUT TRISTATE ;
    USE SIGNAL ;
    ANTENNADIFFAREA 0.795200 ;
    PORT
      LAYER met3 ;
        RECT 746.000 121.080 750.000 121.680 ;
    END
  END mstream_o[43]
  PIN mstream_o[44]
    DIRECTION OUTPUT TRISTATE ;
    USE SIGNAL ;
    ANTENNADIFFAREA 0.795200 ;
    PORT
      LAYER met3 ;
        RECT 746.000 122.440 750.000 123.040 ;
    END
  END mstream_o[44]
  PIN mstream_o[45]
    DIRECTION OUTPUT TRISTATE ;
    USE SIGNAL ;
    ANTENNADIFFAREA 0.795200 ;
    PORT
      LAYER met3 ;
        RECT 746.000 123.800 750.000 124.400 ;
    END
  END mstream_o[45]
  PIN mstream_o[46]
    DIRECTION OUTPUT TRISTATE ;
    USE SIGNAL ;
    ANTENNADIFFAREA 0.795200 ;
    PORT
      LAYER met3 ;
        RECT 746.000 125.160 750.000 125.760 ;
    END
  END mstream_o[46]
  PIN mstream_o[47]
    DIRECTION OUTPUT TRISTATE ;
    USE SIGNAL ;
    ANTENNADIFFAREA 0.795200 ;
    PORT
      LAYER met3 ;
        RECT 746.000 126.520 750.000 127.120 ;
    END
  END mstream_o[47]
  PIN mstream_o[48]
    DIRECTION OUTPUT TRISTATE ;
    USE SIGNAL ;
    ANTENNADIFFAREA 0.795200 ;
    PORT
      LAYER met3 ;
        RECT 746.000 127.880 750.000 128.480 ;
    END
  END mstream_o[48]
  PIN mstream_o[49]
    DIRECTION OUTPUT TRISTATE ;
    USE SIGNAL ;
    ANTENNADIFFAREA 0.795200 ;
    PORT
      LAYER met3 ;
        RECT 746.000 129.240 750.000 129.840 ;
    END
  END mstream_o[49]
  PIN mstream_o[4]
    DIRECTION OUTPUT TRISTATE ;
    USE SIGNAL ;
    ANTENNADIFFAREA 0.795200 ;
    PORT
      LAYER met3 ;
        RECT 746.000 68.040 750.000 68.640 ;
    END
  END mstream_o[4]
  PIN mstream_o[50]
    DIRECTION OUTPUT TRISTATE ;
    USE SIGNAL ;
    ANTENNADIFFAREA 0.795200 ;
    PORT
      LAYER met3 ;
        RECT 746.000 130.600 750.000 131.200 ;
    END
  END mstream_o[50]
  PIN mstream_o[51]
    DIRECTION OUTPUT TRISTATE ;
    USE SIGNAL ;
    ANTENNADIFFAREA 0.795200 ;
    PORT
      LAYER met3 ;
        RECT 746.000 131.960 750.000 132.560 ;
    END
  END mstream_o[51]
  PIN mstream_o[52]
    DIRECTION OUTPUT TRISTATE ;
    USE SIGNAL ;
    ANTENNADIFFAREA 0.795200 ;
    PORT
      LAYER met3 ;
        RECT 746.000 133.320 750.000 133.920 ;
    END
  END mstream_o[52]
  PIN mstream_o[53]
    DIRECTION OUTPUT TRISTATE ;
    USE SIGNAL ;
    ANTENNADIFFAREA 0.795200 ;
    PORT
      LAYER met3 ;
        RECT 746.000 134.680 750.000 135.280 ;
    END
  END mstream_o[53]
  PIN mstream_o[54]
    DIRECTION OUTPUT TRISTATE ;
    USE SIGNAL ;
    ANTENNADIFFAREA 0.795200 ;
    PORT
      LAYER met3 ;
        RECT 746.000 136.040 750.000 136.640 ;
    END
  END mstream_o[54]
  PIN mstream_o[55]
    DIRECTION OUTPUT TRISTATE ;
    USE SIGNAL ;
    ANTENNADIFFAREA 0.795200 ;
    PORT
      LAYER met3 ;
        RECT 746.000 137.400 750.000 138.000 ;
    END
  END mstream_o[55]
  PIN mstream_o[56]
    DIRECTION OUTPUT TRISTATE ;
    USE SIGNAL ;
    ANTENNADIFFAREA 0.795200 ;
    PORT
      LAYER met3 ;
        RECT 746.000 138.760 750.000 139.360 ;
    END
  END mstream_o[56]
  PIN mstream_o[57]
    DIRECTION OUTPUT TRISTATE ;
    USE SIGNAL ;
    ANTENNADIFFAREA 0.795200 ;
    PORT
      LAYER met3 ;
        RECT 746.000 140.120 750.000 140.720 ;
    END
  END mstream_o[57]
  PIN mstream_o[58]
    DIRECTION OUTPUT TRISTATE ;
    USE SIGNAL ;
    ANTENNADIFFAREA 0.795200 ;
    PORT
      LAYER met3 ;
        RECT 746.000 141.480 750.000 142.080 ;
    END
  END mstream_o[58]
  PIN mstream_o[59]
    DIRECTION OUTPUT TRISTATE ;
    USE SIGNAL ;
    ANTENNADIFFAREA 0.795200 ;
    PORT
      LAYER met3 ;
        RECT 746.000 142.840 750.000 143.440 ;
    END
  END mstream_o[59]
  PIN mstream_o[5]
    DIRECTION OUTPUT TRISTATE ;
    USE SIGNAL ;
    ANTENNADIFFAREA 0.795200 ;
    PORT
      LAYER met3 ;
        RECT 746.000 69.400 750.000 70.000 ;
    END
  END mstream_o[5]
  PIN mstream_o[60]
    DIRECTION OUTPUT TRISTATE ;
    USE SIGNAL ;
    ANTENNADIFFAREA 0.795200 ;
    PORT
      LAYER met3 ;
        RECT 746.000 144.200 750.000 144.800 ;
    END
  END mstream_o[60]
  PIN mstream_o[61]
    DIRECTION OUTPUT TRISTATE ;
    USE SIGNAL ;
    ANTENNADIFFAREA 0.795200 ;
    PORT
      LAYER met3 ;
        RECT 746.000 145.560 750.000 146.160 ;
    END
  END mstream_o[61]
  PIN mstream_o[62]
    DIRECTION OUTPUT TRISTATE ;
    USE SIGNAL ;
    ANTENNADIFFAREA 0.795200 ;
    PORT
      LAYER met3 ;
        RECT 746.000 146.920 750.000 147.520 ;
    END
  END mstream_o[62]
  PIN mstream_o[63]
    DIRECTION OUTPUT TRISTATE ;
    USE SIGNAL ;
    ANTENNADIFFAREA 0.795200 ;
    PORT
      LAYER met3 ;
        RECT 746.000 148.280 750.000 148.880 ;
    END
  END mstream_o[63]
  PIN mstream_o[64]
    DIRECTION OUTPUT TRISTATE ;
    USE SIGNAL ;
    ANTENNADIFFAREA 0.445500 ;
    PORT
      LAYER met3 ;
        RECT 746.000 149.640 750.000 150.240 ;
    END
  END mstream_o[64]
  PIN mstream_o[65]
    DIRECTION OUTPUT TRISTATE ;
    USE SIGNAL ;
    ANTENNADIFFAREA 0.795200 ;
    PORT
      LAYER met3 ;
        RECT 746.000 151.000 750.000 151.600 ;
    END
  END mstream_o[65]
  PIN mstream_o[66]
    DIRECTION OUTPUT TRISTATE ;
    USE SIGNAL ;
    ANTENNADIFFAREA 0.795200 ;
    PORT
      LAYER met3 ;
        RECT 746.000 152.360 750.000 152.960 ;
    END
  END mstream_o[66]
  PIN mstream_o[67]
    DIRECTION OUTPUT TRISTATE ;
    USE SIGNAL ;
    ANTENNADIFFAREA 0.795200 ;
    PORT
      LAYER met3 ;
        RECT 746.000 153.720 750.000 154.320 ;
    END
  END mstream_o[67]
  PIN mstream_o[68]
    DIRECTION OUTPUT TRISTATE ;
    USE SIGNAL ;
    ANTENNADIFFAREA 0.795200 ;
    PORT
      LAYER met3 ;
        RECT 746.000 155.080 750.000 155.680 ;
    END
  END mstream_o[68]
  PIN mstream_o[69]
    DIRECTION OUTPUT TRISTATE ;
    USE SIGNAL ;
    ANTENNADIFFAREA 0.795200 ;
    PORT
      LAYER met3 ;
        RECT 746.000 156.440 750.000 157.040 ;
    END
  END mstream_o[69]
  PIN mstream_o[6]
    DIRECTION OUTPUT TRISTATE ;
    USE SIGNAL ;
    ANTENNADIFFAREA 0.795200 ;
    PORT
      LAYER met3 ;
        RECT 746.000 70.760 750.000 71.360 ;
    END
  END mstream_o[6]
  PIN mstream_o[70]
    DIRECTION OUTPUT TRISTATE ;
    USE SIGNAL ;
    ANTENNADIFFAREA 0.795200 ;
    PORT
      LAYER met3 ;
        RECT 746.000 157.800 750.000 158.400 ;
    END
  END mstream_o[70]
  PIN mstream_o[71]
    DIRECTION OUTPUT TRISTATE ;
    USE SIGNAL ;
    ANTENNADIFFAREA 0.795200 ;
    PORT
      LAYER met3 ;
        RECT 746.000 159.160 750.000 159.760 ;
    END
  END mstream_o[71]
  PIN mstream_o[72]
    DIRECTION OUTPUT TRISTATE ;
    USE SIGNAL ;
    ANTENNADIFFAREA 0.795200 ;
    PORT
      LAYER met3 ;
        RECT 746.000 160.520 750.000 161.120 ;
    END
  END mstream_o[72]
  PIN mstream_o[73]
    DIRECTION OUTPUT TRISTATE ;
    USE SIGNAL ;
    ANTENNADIFFAREA 0.795200 ;
    PORT
      LAYER met3 ;
        RECT 746.000 161.880 750.000 162.480 ;
    END
  END mstream_o[73]
  PIN mstream_o[74]
    DIRECTION OUTPUT TRISTATE ;
    USE SIGNAL ;
    ANTENNADIFFAREA 0.795200 ;
    PORT
      LAYER met3 ;
        RECT 746.000 163.240 750.000 163.840 ;
    END
  END mstream_o[74]
  PIN mstream_o[75]
    DIRECTION OUTPUT TRISTATE ;
    USE SIGNAL ;
    ANTENNADIFFAREA 0.445500 ;
    PORT
      LAYER met3 ;
        RECT 746.000 164.600 750.000 165.200 ;
    END
  END mstream_o[75]
  PIN mstream_o[76]
    DIRECTION OUTPUT TRISTATE ;
    USE SIGNAL ;
    ANTENNADIFFAREA 0.795200 ;
    PORT
      LAYER met3 ;
        RECT 746.000 165.960 750.000 166.560 ;
    END
  END mstream_o[76]
  PIN mstream_o[77]
    DIRECTION OUTPUT TRISTATE ;
    USE SIGNAL ;
    ANTENNADIFFAREA 0.795200 ;
    PORT
      LAYER met3 ;
        RECT 746.000 167.320 750.000 167.920 ;
    END
  END mstream_o[77]
  PIN mstream_o[78]
    DIRECTION OUTPUT TRISTATE ;
    USE SIGNAL ;
    ANTENNADIFFAREA 0.795200 ;
    PORT
      LAYER met3 ;
        RECT 746.000 168.680 750.000 169.280 ;
    END
  END mstream_o[78]
  PIN mstream_o[79]
    DIRECTION OUTPUT TRISTATE ;
    USE SIGNAL ;
    ANTENNADIFFAREA 0.795200 ;
    PORT
      LAYER met3 ;
        RECT 746.000 170.040 750.000 170.640 ;
    END
  END mstream_o[79]
  PIN mstream_o[7]
    DIRECTION OUTPUT TRISTATE ;
    USE SIGNAL ;
    ANTENNADIFFAREA 0.795200 ;
    PORT
      LAYER met3 ;
        RECT 746.000 72.120 750.000 72.720 ;
    END
  END mstream_o[7]
  PIN mstream_o[80]
    DIRECTION OUTPUT TRISTATE ;
    USE SIGNAL ;
    ANTENNADIFFAREA 0.795200 ;
    PORT
      LAYER met3 ;
        RECT 746.000 171.400 750.000 172.000 ;
    END
  END mstream_o[80]
  PIN mstream_o[81]
    DIRECTION OUTPUT TRISTATE ;
    USE SIGNAL ;
    ANTENNADIFFAREA 0.795200 ;
    PORT
      LAYER met3 ;
        RECT 746.000 172.760 750.000 173.360 ;
    END
  END mstream_o[81]
  PIN mstream_o[82]
    DIRECTION OUTPUT TRISTATE ;
    USE SIGNAL ;
    ANTENNADIFFAREA 0.795200 ;
    PORT
      LAYER met3 ;
        RECT 746.000 174.120 750.000 174.720 ;
    END
  END mstream_o[82]
  PIN mstream_o[83]
    DIRECTION OUTPUT TRISTATE ;
    USE SIGNAL ;
    ANTENNADIFFAREA 0.795200 ;
    PORT
      LAYER met3 ;
        RECT 746.000 175.480 750.000 176.080 ;
    END
  END mstream_o[83]
  PIN mstream_o[84]
    DIRECTION OUTPUT TRISTATE ;
    USE SIGNAL ;
    ANTENNADIFFAREA 0.795200 ;
    PORT
      LAYER met3 ;
        RECT 746.000 176.840 750.000 177.440 ;
    END
  END mstream_o[84]
  PIN mstream_o[85]
    DIRECTION OUTPUT TRISTATE ;
    USE SIGNAL ;
    ANTENNADIFFAREA 0.795200 ;
    PORT
      LAYER met3 ;
        RECT 746.000 178.200 750.000 178.800 ;
    END
  END mstream_o[85]
  PIN mstream_o[86]
    DIRECTION OUTPUT TRISTATE ;
    USE SIGNAL ;
    ANTENNADIFFAREA 0.795200 ;
    PORT
      LAYER met3 ;
        RECT 746.000 179.560 750.000 180.160 ;
    END
  END mstream_o[86]
  PIN mstream_o[87]
    DIRECTION OUTPUT TRISTATE ;
    USE SIGNAL ;
    ANTENNADIFFAREA 0.795200 ;
    PORT
      LAYER met3 ;
        RECT 746.000 180.920 750.000 181.520 ;
    END
  END mstream_o[87]
  PIN mstream_o[88]
    DIRECTION OUTPUT TRISTATE ;
    USE SIGNAL ;
    ANTENNADIFFAREA 0.795200 ;
    PORT
      LAYER met3 ;
        RECT 746.000 182.280 750.000 182.880 ;
    END
  END mstream_o[88]
  PIN mstream_o[89]
    DIRECTION OUTPUT TRISTATE ;
    USE SIGNAL ;
    ANTENNADIFFAREA 0.795200 ;
    PORT
      LAYER met3 ;
        RECT 746.000 183.640 750.000 184.240 ;
    END
  END mstream_o[89]
  PIN mstream_o[8]
    DIRECTION OUTPUT TRISTATE ;
    USE SIGNAL ;
    ANTENNADIFFAREA 0.795200 ;
    PORT
      LAYER met3 ;
        RECT 746.000 73.480 750.000 74.080 ;
    END
  END mstream_o[8]
  PIN mstream_o[90]
    DIRECTION OUTPUT TRISTATE ;
    USE SIGNAL ;
    ANTENNADIFFAREA 0.795200 ;
    PORT
      LAYER met3 ;
        RECT 746.000 185.000 750.000 185.600 ;
    END
  END mstream_o[90]
  PIN mstream_o[91]
    DIRECTION OUTPUT TRISTATE ;
    USE SIGNAL ;
    ANTENNADIFFAREA 0.795200 ;
    PORT
      LAYER met3 ;
        RECT 746.000 186.360 750.000 186.960 ;
    END
  END mstream_o[91]
  PIN mstream_o[92]
    DIRECTION OUTPUT TRISTATE ;
    USE SIGNAL ;
    ANTENNADIFFAREA 0.795200 ;
    PORT
      LAYER met3 ;
        RECT 746.000 187.720 750.000 188.320 ;
    END
  END mstream_o[92]
  PIN mstream_o[93]
    DIRECTION OUTPUT TRISTATE ;
    USE SIGNAL ;
    ANTENNADIFFAREA 0.795200 ;
    PORT
      LAYER met3 ;
        RECT 746.000 189.080 750.000 189.680 ;
    END
  END mstream_o[93]
  PIN mstream_o[94]
    DIRECTION OUTPUT TRISTATE ;
    USE SIGNAL ;
    ANTENNADIFFAREA 0.795200 ;
    PORT
      LAYER met3 ;
        RECT 746.000 190.440 750.000 191.040 ;
    END
  END mstream_o[94]
  PIN mstream_o[95]
    DIRECTION OUTPUT TRISTATE ;
    USE SIGNAL ;
    ANTENNADIFFAREA 0.795200 ;
    PORT
      LAYER met3 ;
        RECT 746.000 191.800 750.000 192.400 ;
    END
  END mstream_o[95]
  PIN mstream_o[96]
    DIRECTION OUTPUT TRISTATE ;
    USE SIGNAL ;
    ANTENNADIFFAREA 0.795200 ;
    PORT
      LAYER met3 ;
        RECT 746.000 193.160 750.000 193.760 ;
    END
  END mstream_o[96]
  PIN mstream_o[97]
    DIRECTION OUTPUT TRISTATE ;
    USE SIGNAL ;
    ANTENNADIFFAREA 0.795200 ;
    PORT
      LAYER met3 ;
        RECT 746.000 194.520 750.000 195.120 ;
    END
  END mstream_o[97]
  PIN mstream_o[98]
    DIRECTION OUTPUT TRISTATE ;
    USE SIGNAL ;
    ANTENNADIFFAREA 0.795200 ;
    PORT
      LAYER met3 ;
        RECT 746.000 195.880 750.000 196.480 ;
    END
  END mstream_o[98]
  PIN mstream_o[99]
    DIRECTION OUTPUT TRISTATE ;
    USE SIGNAL ;
    ANTENNADIFFAREA 0.795200 ;
    PORT
      LAYER met3 ;
        RECT 746.000 197.240 750.000 197.840 ;
    END
  END mstream_o[99]
  PIN mstream_o[9]
    DIRECTION OUTPUT TRISTATE ;
    USE SIGNAL ;
    ANTENNADIFFAREA 0.795200 ;
    PORT
      LAYER met3 ;
        RECT 746.000 74.840 750.000 75.440 ;
    END
  END mstream_o[9]
  PIN nrst_i
    DIRECTION INPUT ;
    USE SIGNAL ;
    ANTENNAGATEAREA 0.426000 ;
    PORT
      LAYER met2 ;
        RECT 49.310 0.000 49.590 4.000 ;
    END
  END nrst_i
  PIN sstream_i[0]
    DIRECTION INPUT ;
    USE SIGNAL ;
    ANTENNAGATEAREA 0.196500 ;
    PORT
      LAYER met3 ;
        RECT 0.000 278.840 4.000 279.440 ;
    END
  END sstream_i[0]
  PIN sstream_i[100]
    DIRECTION INPUT ;
    USE SIGNAL ;
    ANTENNAGATEAREA 0.426000 ;
    PORT
      LAYER met3 ;
        RECT 0.000 414.840 4.000 415.440 ;
    END
  END sstream_i[100]
  PIN sstream_i[101]
    DIRECTION INPUT ;
    USE SIGNAL ;
    ANTENNAGATEAREA 0.426000 ;
    PORT
      LAYER met3 ;
        RECT 0.000 416.200 4.000 416.800 ;
    END
  END sstream_i[101]
  PIN sstream_i[102]
    DIRECTION INPUT ;
    USE SIGNAL ;
    ANTENNAGATEAREA 0.247500 ;
    PORT
      LAYER met3 ;
        RECT 0.000 417.560 4.000 418.160 ;
    END
  END sstream_i[102]
  PIN sstream_i[103]
    DIRECTION INPUT ;
    USE SIGNAL ;
    ANTENNAGATEAREA 0.247500 ;
    PORT
      LAYER met3 ;
        RECT 0.000 418.920 4.000 419.520 ;
    END
  END sstream_i[103]
  PIN sstream_i[104]
    DIRECTION INPUT ;
    USE SIGNAL ;
    ANTENNAGATEAREA 0.247500 ;
    PORT
      LAYER met3 ;
        RECT 0.000 420.280 4.000 420.880 ;
    END
  END sstream_i[104]
  PIN sstream_i[105]
    DIRECTION INPUT ;
    USE SIGNAL ;
    ANTENNAGATEAREA 0.247500 ;
    PORT
      LAYER met3 ;
        RECT 0.000 421.640 4.000 422.240 ;
    END
  END sstream_i[105]
  PIN sstream_i[106]
    DIRECTION INPUT ;
    USE SIGNAL ;
    ANTENNAGATEAREA 0.426000 ;
    PORT
      LAYER met3 ;
        RECT 0.000 423.000 4.000 423.600 ;
    END
  END sstream_i[106]
  PIN sstream_i[107]
    DIRECTION INPUT ;
    USE SIGNAL ;
    ANTENNAGATEAREA 0.247500 ;
    PORT
      LAYER met3 ;
        RECT 0.000 424.360 4.000 424.960 ;
    END
  END sstream_i[107]
  PIN sstream_i[108]
    DIRECTION INPUT ;
    USE SIGNAL ;
    ANTENNAGATEAREA 0.426000 ;
    PORT
      LAYER met3 ;
        RECT 0.000 425.720 4.000 426.320 ;
    END
  END sstream_i[108]
  PIN sstream_i[109]
    DIRECTION INPUT ;
    USE SIGNAL ;
    ANTENNAGATEAREA 0.247500 ;
    PORT
      LAYER met3 ;
        RECT 0.000 427.080 4.000 427.680 ;
    END
  END sstream_i[109]
  PIN sstream_i[10]
    DIRECTION INPUT ;
    USE SIGNAL ;
    ANTENNAGATEAREA 0.196500 ;
    PORT
      LAYER met3 ;
        RECT 0.000 292.440 4.000 293.040 ;
    END
  END sstream_i[10]
  PIN sstream_i[110]
    DIRECTION INPUT ;
    USE SIGNAL ;
    ANTENNAGATEAREA 0.247500 ;
    PORT
      LAYER met3 ;
        RECT 0.000 428.440 4.000 429.040 ;
    END
  END sstream_i[110]
  PIN sstream_i[111]
    DIRECTION INPUT ;
    USE SIGNAL ;
    ANTENNAGATEAREA 0.426000 ;
    PORT
      LAYER met3 ;
        RECT 0.000 429.800 4.000 430.400 ;
    END
  END sstream_i[111]
  PIN sstream_i[112]
    DIRECTION INPUT ;
    USE SIGNAL ;
    ANTENNAGATEAREA 0.426000 ;
    PORT
      LAYER met3 ;
        RECT 0.000 431.160 4.000 431.760 ;
    END
  END sstream_i[112]
  PIN sstream_i[113]
    DIRECTION INPUT ;
    USE SIGNAL ;
    ANTENNAGATEAREA 0.426000 ;
    PORT
      LAYER met3 ;
        RECT 0.000 432.520 4.000 433.120 ;
    END
  END sstream_i[113]
  PIN sstream_i[114]
    DIRECTION INPUT ;
    USE SIGNAL ;
    ANTENNAGATEAREA 0.213000 ;
    PORT
      LAYER met3 ;
        RECT 0.000 433.880 4.000 434.480 ;
    END
  END sstream_i[114]
  PIN sstream_i[115]
    DIRECTION INPUT ;
    USE SIGNAL ;
    PORT
      LAYER met3 ;
        RECT 0.000 435.240 4.000 435.840 ;
    END
  END sstream_i[115]
  PIN sstream_i[11]
    DIRECTION INPUT ;
    USE SIGNAL ;
    ANTENNAGATEAREA 0.196500 ;
    PORT
      LAYER met3 ;
        RECT 0.000 293.800 4.000 294.400 ;
    END
  END sstream_i[11]
  PIN sstream_i[12]
    DIRECTION INPUT ;
    USE SIGNAL ;
    ANTENNAGATEAREA 0.196500 ;
    PORT
      LAYER met3 ;
        RECT 0.000 295.160 4.000 295.760 ;
    END
  END sstream_i[12]
  PIN sstream_i[13]
    DIRECTION INPUT ;
    USE SIGNAL ;
    ANTENNAGATEAREA 0.196500 ;
    PORT
      LAYER met3 ;
        RECT 0.000 296.520 4.000 297.120 ;
    END
  END sstream_i[13]
  PIN sstream_i[14]
    DIRECTION INPUT ;
    USE SIGNAL ;
    ANTENNAGATEAREA 0.196500 ;
    PORT
      LAYER met3 ;
        RECT 0.000 297.880 4.000 298.480 ;
    END
  END sstream_i[14]
  PIN sstream_i[15]
    DIRECTION INPUT ;
    USE SIGNAL ;
    ANTENNAGATEAREA 0.196500 ;
    PORT
      LAYER met3 ;
        RECT 0.000 299.240 4.000 299.840 ;
    END
  END sstream_i[15]
  PIN sstream_i[16]
    DIRECTION INPUT ;
    USE SIGNAL ;
    PORT
      LAYER met3 ;
        RECT 0.000 300.600 4.000 301.200 ;
    END
  END sstream_i[16]
  PIN sstream_i[17]
    DIRECTION INPUT ;
    USE SIGNAL ;
    PORT
      LAYER met3 ;
        RECT 0.000 301.960 4.000 302.560 ;
    END
  END sstream_i[17]
  PIN sstream_i[18]
    DIRECTION INPUT ;
    USE SIGNAL ;
    PORT
      LAYER met3 ;
        RECT 0.000 303.320 4.000 303.920 ;
    END
  END sstream_i[18]
  PIN sstream_i[19]
    DIRECTION INPUT ;
    USE SIGNAL ;
    PORT
      LAYER met3 ;
        RECT 0.000 304.680 4.000 305.280 ;
    END
  END sstream_i[19]
  PIN sstream_i[1]
    DIRECTION INPUT ;
    USE SIGNAL ;
    ANTENNAGATEAREA 0.196500 ;
    PORT
      LAYER met3 ;
        RECT 0.000 280.200 4.000 280.800 ;
    END
  END sstream_i[1]
  PIN sstream_i[20]
    DIRECTION INPUT ;
    USE SIGNAL ;
    PORT
      LAYER met3 ;
        RECT 0.000 306.040 4.000 306.640 ;
    END
  END sstream_i[20]
  PIN sstream_i[21]
    DIRECTION INPUT ;
    USE SIGNAL ;
    PORT
      LAYER met3 ;
        RECT 0.000 307.400 4.000 308.000 ;
    END
  END sstream_i[21]
  PIN sstream_i[22]
    DIRECTION INPUT ;
    USE SIGNAL ;
    PORT
      LAYER met3 ;
        RECT 0.000 308.760 4.000 309.360 ;
    END
  END sstream_i[22]
  PIN sstream_i[23]
    DIRECTION INPUT ;
    USE SIGNAL ;
    PORT
      LAYER met3 ;
        RECT 0.000 310.120 4.000 310.720 ;
    END
  END sstream_i[23]
  PIN sstream_i[24]
    DIRECTION INPUT ;
    USE SIGNAL ;
    PORT
      LAYER met3 ;
        RECT 0.000 311.480 4.000 312.080 ;
    END
  END sstream_i[24]
  PIN sstream_i[25]
    DIRECTION INPUT ;
    USE SIGNAL ;
    PORT
      LAYER met3 ;
        RECT 0.000 312.840 4.000 313.440 ;
    END
  END sstream_i[25]
  PIN sstream_i[26]
    DIRECTION INPUT ;
    USE SIGNAL ;
    PORT
      LAYER met3 ;
        RECT 0.000 314.200 4.000 314.800 ;
    END
  END sstream_i[26]
  PIN sstream_i[27]
    DIRECTION INPUT ;
    USE SIGNAL ;
    PORT
      LAYER met3 ;
        RECT 0.000 315.560 4.000 316.160 ;
    END
  END sstream_i[27]
  PIN sstream_i[28]
    DIRECTION INPUT ;
    USE SIGNAL ;
    PORT
      LAYER met3 ;
        RECT 0.000 316.920 4.000 317.520 ;
    END
  END sstream_i[28]
  PIN sstream_i[29]
    DIRECTION INPUT ;
    USE SIGNAL ;
    PORT
      LAYER met3 ;
        RECT 0.000 318.280 4.000 318.880 ;
    END
  END sstream_i[29]
  PIN sstream_i[2]
    DIRECTION INPUT ;
    USE SIGNAL ;
    ANTENNAGATEAREA 0.196500 ;
    PORT
      LAYER met3 ;
        RECT 0.000 281.560 4.000 282.160 ;
    END
  END sstream_i[2]
  PIN sstream_i[30]
    DIRECTION INPUT ;
    USE SIGNAL ;
    PORT
      LAYER met3 ;
        RECT 0.000 319.640 4.000 320.240 ;
    END
  END sstream_i[30]
  PIN sstream_i[31]
    DIRECTION INPUT ;
    USE SIGNAL ;
    PORT
      LAYER met3 ;
        RECT 0.000 321.000 4.000 321.600 ;
    END
  END sstream_i[31]
  PIN sstream_i[32]
    DIRECTION INPUT ;
    USE SIGNAL ;
    ANTENNAGATEAREA 0.196500 ;
    PORT
      LAYER met3 ;
        RECT 0.000 322.360 4.000 322.960 ;
    END
  END sstream_i[32]
  PIN sstream_i[33]
    DIRECTION INPUT ;
    USE SIGNAL ;
    ANTENNAGATEAREA 0.196500 ;
    PORT
      LAYER met3 ;
        RECT 0.000 323.720 4.000 324.320 ;
    END
  END sstream_i[33]
  PIN sstream_i[34]
    DIRECTION INPUT ;
    USE SIGNAL ;
    ANTENNAGATEAREA 0.196500 ;
    PORT
      LAYER met3 ;
        RECT 0.000 325.080 4.000 325.680 ;
    END
  END sstream_i[34]
  PIN sstream_i[35]
    DIRECTION INPUT ;
    USE SIGNAL ;
    ANTENNAGATEAREA 0.196500 ;
    PORT
      LAYER met3 ;
        RECT 0.000 326.440 4.000 327.040 ;
    END
  END sstream_i[35]
  PIN sstream_i[36]
    DIRECTION INPUT ;
    USE SIGNAL ;
    ANTENNAGATEAREA 0.196500 ;
    PORT
      LAYER met3 ;
        RECT 0.000 327.800 4.000 328.400 ;
    END
  END sstream_i[36]
  PIN sstream_i[37]
    DIRECTION INPUT ;
    USE SIGNAL ;
    ANTENNAGATEAREA 0.196500 ;
    PORT
      LAYER met3 ;
        RECT 0.000 329.160 4.000 329.760 ;
    END
  END sstream_i[37]
  PIN sstream_i[38]
    DIRECTION INPUT ;
    USE SIGNAL ;
    ANTENNAGATEAREA 0.196500 ;
    PORT
      LAYER met3 ;
        RECT 0.000 330.520 4.000 331.120 ;
    END
  END sstream_i[38]
  PIN sstream_i[39]
    DIRECTION INPUT ;
    USE SIGNAL ;
    ANTENNAGATEAREA 0.196500 ;
    PORT
      LAYER met3 ;
        RECT 0.000 331.880 4.000 332.480 ;
    END
  END sstream_i[39]
  PIN sstream_i[3]
    DIRECTION INPUT ;
    USE SIGNAL ;
    ANTENNAGATEAREA 0.196500 ;
    PORT
      LAYER met3 ;
        RECT 0.000 282.920 4.000 283.520 ;
    END
  END sstream_i[3]
  PIN sstream_i[40]
    DIRECTION INPUT ;
    USE SIGNAL ;
    ANTENNAGATEAREA 0.196500 ;
    PORT
      LAYER met3 ;
        RECT 0.000 333.240 4.000 333.840 ;
    END
  END sstream_i[40]
  PIN sstream_i[41]
    DIRECTION INPUT ;
    USE SIGNAL ;
    ANTENNAGATEAREA 0.196500 ;
    PORT
      LAYER met3 ;
        RECT 0.000 334.600 4.000 335.200 ;
    END
  END sstream_i[41]
  PIN sstream_i[42]
    DIRECTION INPUT ;
    USE SIGNAL ;
    ANTENNAGATEAREA 0.196500 ;
    PORT
      LAYER met3 ;
        RECT 0.000 335.960 4.000 336.560 ;
    END
  END sstream_i[42]
  PIN sstream_i[43]
    DIRECTION INPUT ;
    USE SIGNAL ;
    ANTENNAGATEAREA 0.196500 ;
    PORT
      LAYER met3 ;
        RECT 0.000 337.320 4.000 337.920 ;
    END
  END sstream_i[43]
  PIN sstream_i[44]
    DIRECTION INPUT ;
    USE SIGNAL ;
    ANTENNAGATEAREA 0.196500 ;
    PORT
      LAYER met3 ;
        RECT 0.000 338.680 4.000 339.280 ;
    END
  END sstream_i[44]
  PIN sstream_i[45]
    DIRECTION INPUT ;
    USE SIGNAL ;
    ANTENNAGATEAREA 0.196500 ;
    PORT
      LAYER met3 ;
        RECT 0.000 340.040 4.000 340.640 ;
    END
  END sstream_i[45]
  PIN sstream_i[46]
    DIRECTION INPUT ;
    USE SIGNAL ;
    ANTENNAGATEAREA 0.196500 ;
    PORT
      LAYER met3 ;
        RECT 0.000 341.400 4.000 342.000 ;
    END
  END sstream_i[46]
  PIN sstream_i[47]
    DIRECTION INPUT ;
    USE SIGNAL ;
    ANTENNAGATEAREA 0.196500 ;
    PORT
      LAYER met3 ;
        RECT 0.000 342.760 4.000 343.360 ;
    END
  END sstream_i[47]
  PIN sstream_i[48]
    DIRECTION INPUT ;
    USE SIGNAL ;
    PORT
      LAYER met3 ;
        RECT 0.000 344.120 4.000 344.720 ;
    END
  END sstream_i[48]
  PIN sstream_i[49]
    DIRECTION INPUT ;
    USE SIGNAL ;
    PORT
      LAYER met3 ;
        RECT 0.000 345.480 4.000 346.080 ;
    END
  END sstream_i[49]
  PIN sstream_i[4]
    DIRECTION INPUT ;
    USE SIGNAL ;
    ANTENNAGATEAREA 0.196500 ;
    PORT
      LAYER met3 ;
        RECT 0.000 284.280 4.000 284.880 ;
    END
  END sstream_i[4]
  PIN sstream_i[50]
    DIRECTION INPUT ;
    USE SIGNAL ;
    PORT
      LAYER met3 ;
        RECT 0.000 346.840 4.000 347.440 ;
    END
  END sstream_i[50]
  PIN sstream_i[51]
    DIRECTION INPUT ;
    USE SIGNAL ;
    PORT
      LAYER met3 ;
        RECT 0.000 348.200 4.000 348.800 ;
    END
  END sstream_i[51]
  PIN sstream_i[52]
    DIRECTION INPUT ;
    USE SIGNAL ;
    PORT
      LAYER met3 ;
        RECT 0.000 349.560 4.000 350.160 ;
    END
  END sstream_i[52]
  PIN sstream_i[53]
    DIRECTION INPUT ;
    USE SIGNAL ;
    PORT
      LAYER met3 ;
        RECT 0.000 350.920 4.000 351.520 ;
    END
  END sstream_i[53]
  PIN sstream_i[54]
    DIRECTION INPUT ;
    USE SIGNAL ;
    PORT
      LAYER met3 ;
        RECT 0.000 352.280 4.000 352.880 ;
    END
  END sstream_i[54]
  PIN sstream_i[55]
    DIRECTION INPUT ;
    USE SIGNAL ;
    PORT
      LAYER met3 ;
        RECT 0.000 353.640 4.000 354.240 ;
    END
  END sstream_i[55]
  PIN sstream_i[56]
    DIRECTION INPUT ;
    USE SIGNAL ;
    PORT
      LAYER met3 ;
        RECT 0.000 355.000 4.000 355.600 ;
    END
  END sstream_i[56]
  PIN sstream_i[57]
    DIRECTION INPUT ;
    USE SIGNAL ;
    PORT
      LAYER met3 ;
        RECT 0.000 356.360 4.000 356.960 ;
    END
  END sstream_i[57]
  PIN sstream_i[58]
    DIRECTION INPUT ;
    USE SIGNAL ;
    PORT
      LAYER met3 ;
        RECT 0.000 357.720 4.000 358.320 ;
    END
  END sstream_i[58]
  PIN sstream_i[59]
    DIRECTION INPUT ;
    USE SIGNAL ;
    PORT
      LAYER met3 ;
        RECT 0.000 359.080 4.000 359.680 ;
    END
  END sstream_i[59]
  PIN sstream_i[5]
    DIRECTION INPUT ;
    USE SIGNAL ;
    ANTENNAGATEAREA 0.196500 ;
    PORT
      LAYER met3 ;
        RECT 0.000 285.640 4.000 286.240 ;
    END
  END sstream_i[5]
  PIN sstream_i[60]
    DIRECTION INPUT ;
    USE SIGNAL ;
    PORT
      LAYER met3 ;
        RECT 0.000 360.440 4.000 361.040 ;
    END
  END sstream_i[60]
  PIN sstream_i[61]
    DIRECTION INPUT ;
    USE SIGNAL ;
    PORT
      LAYER met3 ;
        RECT 0.000 361.800 4.000 362.400 ;
    END
  END sstream_i[61]
  PIN sstream_i[62]
    DIRECTION INPUT ;
    USE SIGNAL ;
    PORT
      LAYER met3 ;
        RECT 0.000 363.160 4.000 363.760 ;
    END
  END sstream_i[62]
  PIN sstream_i[63]
    DIRECTION INPUT ;
    USE SIGNAL ;
    PORT
      LAYER met3 ;
        RECT 0.000 364.520 4.000 365.120 ;
    END
  END sstream_i[63]
  PIN sstream_i[64]
    DIRECTION INPUT ;
    USE SIGNAL ;
    ANTENNAGATEAREA 0.196500 ;
    PORT
      LAYER met3 ;
        RECT 0.000 365.880 4.000 366.480 ;
    END
  END sstream_i[64]
  PIN sstream_i[65]
    DIRECTION INPUT ;
    USE SIGNAL ;
    ANTENNAGATEAREA 0.196500 ;
    PORT
      LAYER met3 ;
        RECT 0.000 367.240 4.000 367.840 ;
    END
  END sstream_i[65]
  PIN sstream_i[66]
    DIRECTION INPUT ;
    USE SIGNAL ;
    ANTENNAGATEAREA 0.196500 ;
    PORT
      LAYER met3 ;
        RECT 0.000 368.600 4.000 369.200 ;
    END
  END sstream_i[66]
  PIN sstream_i[67]
    DIRECTION INPUT ;
    USE SIGNAL ;
    ANTENNAGATEAREA 0.196500 ;
    PORT
      LAYER met3 ;
        RECT 0.000 369.960 4.000 370.560 ;
    END
  END sstream_i[67]
  PIN sstream_i[68]
    DIRECTION INPUT ;
    USE SIGNAL ;
    ANTENNAGATEAREA 0.196500 ;
    PORT
      LAYER met3 ;
        RECT 0.000 371.320 4.000 371.920 ;
    END
  END sstream_i[68]
  PIN sstream_i[69]
    DIRECTION INPUT ;
    USE SIGNAL ;
    ANTENNAGATEAREA 0.196500 ;
    PORT
      LAYER met3 ;
        RECT 0.000 372.680 4.000 373.280 ;
    END
  END sstream_i[69]
  PIN sstream_i[6]
    DIRECTION INPUT ;
    USE SIGNAL ;
    ANTENNAGATEAREA 0.196500 ;
    PORT
      LAYER met3 ;
        RECT 0.000 287.000 4.000 287.600 ;
    END
  END sstream_i[6]
  PIN sstream_i[70]
    DIRECTION INPUT ;
    USE SIGNAL ;
    ANTENNAGATEAREA 0.196500 ;
    PORT
      LAYER met3 ;
        RECT 0.000 374.040 4.000 374.640 ;
    END
  END sstream_i[70]
  PIN sstream_i[71]
    DIRECTION INPUT ;
    USE SIGNAL ;
    ANTENNAGATEAREA 0.196500 ;
    PORT
      LAYER met3 ;
        RECT 0.000 375.400 4.000 376.000 ;
    END
  END sstream_i[71]
  PIN sstream_i[72]
    DIRECTION INPUT ;
    USE SIGNAL ;
    ANTENNAGATEAREA 0.196500 ;
    PORT
      LAYER met3 ;
        RECT 0.000 376.760 4.000 377.360 ;
    END
  END sstream_i[72]
  PIN sstream_i[73]
    DIRECTION INPUT ;
    USE SIGNAL ;
    ANTENNAGATEAREA 0.196500 ;
    PORT
      LAYER met3 ;
        RECT 0.000 378.120 4.000 378.720 ;
    END
  END sstream_i[73]
  PIN sstream_i[74]
    DIRECTION INPUT ;
    USE SIGNAL ;
    ANTENNAGATEAREA 0.196500 ;
    PORT
      LAYER met3 ;
        RECT 0.000 379.480 4.000 380.080 ;
    END
  END sstream_i[74]
  PIN sstream_i[75]
    DIRECTION INPUT ;
    USE SIGNAL ;
    ANTENNAGATEAREA 0.196500 ;
    PORT
      LAYER met3 ;
        RECT 0.000 380.840 4.000 381.440 ;
    END
  END sstream_i[75]
  PIN sstream_i[76]
    DIRECTION INPUT ;
    USE SIGNAL ;
    ANTENNAGATEAREA 0.196500 ;
    PORT
      LAYER met3 ;
        RECT 0.000 382.200 4.000 382.800 ;
    END
  END sstream_i[76]
  PIN sstream_i[77]
    DIRECTION INPUT ;
    USE SIGNAL ;
    ANTENNAGATEAREA 0.196500 ;
    PORT
      LAYER met3 ;
        RECT 0.000 383.560 4.000 384.160 ;
    END
  END sstream_i[77]
  PIN sstream_i[78]
    DIRECTION INPUT ;
    USE SIGNAL ;
    ANTENNAGATEAREA 0.196500 ;
    PORT
      LAYER met3 ;
        RECT 0.000 384.920 4.000 385.520 ;
    END
  END sstream_i[78]
  PIN sstream_i[79]
    DIRECTION INPUT ;
    USE SIGNAL ;
    ANTENNAGATEAREA 0.196500 ;
    PORT
      LAYER met3 ;
        RECT 0.000 386.280 4.000 386.880 ;
    END
  END sstream_i[79]
  PIN sstream_i[7]
    DIRECTION INPUT ;
    USE SIGNAL ;
    ANTENNAGATEAREA 0.196500 ;
    PORT
      LAYER met3 ;
        RECT 0.000 288.360 4.000 288.960 ;
    END
  END sstream_i[7]
  PIN sstream_i[80]
    DIRECTION INPUT ;
    USE SIGNAL ;
    PORT
      LAYER met3 ;
        RECT 0.000 387.640 4.000 388.240 ;
    END
  END sstream_i[80]
  PIN sstream_i[81]
    DIRECTION INPUT ;
    USE SIGNAL ;
    PORT
      LAYER met3 ;
        RECT 0.000 389.000 4.000 389.600 ;
    END
  END sstream_i[81]
  PIN sstream_i[82]
    DIRECTION INPUT ;
    USE SIGNAL ;
    PORT
      LAYER met3 ;
        RECT 0.000 390.360 4.000 390.960 ;
    END
  END sstream_i[82]
  PIN sstream_i[83]
    DIRECTION INPUT ;
    USE SIGNAL ;
    PORT
      LAYER met3 ;
        RECT 0.000 391.720 4.000 392.320 ;
    END
  END sstream_i[83]
  PIN sstream_i[84]
    DIRECTION INPUT ;
    USE SIGNAL ;
    PORT
      LAYER met3 ;
        RECT 0.000 393.080 4.000 393.680 ;
    END
  END sstream_i[84]
  PIN sstream_i[85]
    DIRECTION INPUT ;
    USE SIGNAL ;
    PORT
      LAYER met3 ;
        RECT 0.000 394.440 4.000 395.040 ;
    END
  END sstream_i[85]
  PIN sstream_i[86]
    DIRECTION INPUT ;
    USE SIGNAL ;
    PORT
      LAYER met3 ;
        RECT 0.000 395.800 4.000 396.400 ;
    END
  END sstream_i[86]
  PIN sstream_i[87]
    DIRECTION INPUT ;
    USE SIGNAL ;
    PORT
      LAYER met3 ;
        RECT 0.000 397.160 4.000 397.760 ;
    END
  END sstream_i[87]
  PIN sstream_i[88]
    DIRECTION INPUT ;
    USE SIGNAL ;
    PORT
      LAYER met3 ;
        RECT 0.000 398.520 4.000 399.120 ;
    END
  END sstream_i[88]
  PIN sstream_i[89]
    DIRECTION INPUT ;
    USE SIGNAL ;
    PORT
      LAYER met3 ;
        RECT 0.000 399.880 4.000 400.480 ;
    END
  END sstream_i[89]
  PIN sstream_i[8]
    DIRECTION INPUT ;
    USE SIGNAL ;
    ANTENNAGATEAREA 0.196500 ;
    PORT
      LAYER met3 ;
        RECT 0.000 289.720 4.000 290.320 ;
    END
  END sstream_i[8]
  PIN sstream_i[90]
    DIRECTION INPUT ;
    USE SIGNAL ;
    PORT
      LAYER met3 ;
        RECT 0.000 401.240 4.000 401.840 ;
    END
  END sstream_i[90]
  PIN sstream_i[91]
    DIRECTION INPUT ;
    USE SIGNAL ;
    PORT
      LAYER met3 ;
        RECT 0.000 402.600 4.000 403.200 ;
    END
  END sstream_i[91]
  PIN sstream_i[92]
    DIRECTION INPUT ;
    USE SIGNAL ;
    PORT
      LAYER met3 ;
        RECT 0.000 403.960 4.000 404.560 ;
    END
  END sstream_i[92]
  PIN sstream_i[93]
    DIRECTION INPUT ;
    USE SIGNAL ;
    PORT
      LAYER met3 ;
        RECT 0.000 405.320 4.000 405.920 ;
    END
  END sstream_i[93]
  PIN sstream_i[94]
    DIRECTION INPUT ;
    USE SIGNAL ;
    PORT
      LAYER met3 ;
        RECT 0.000 406.680 4.000 407.280 ;
    END
  END sstream_i[94]
  PIN sstream_i[95]
    DIRECTION INPUT ;
    USE SIGNAL ;
    PORT
      LAYER met3 ;
        RECT 0.000 408.040 4.000 408.640 ;
    END
  END sstream_i[95]
  PIN sstream_i[96]
    DIRECTION INPUT ;
    USE SIGNAL ;
    ANTENNAGATEAREA 0.247500 ;
    PORT
      LAYER met3 ;
        RECT 0.000 409.400 4.000 410.000 ;
    END
  END sstream_i[96]
  PIN sstream_i[97]
    DIRECTION INPUT ;
    USE SIGNAL ;
    ANTENNAGATEAREA 0.426000 ;
    PORT
      LAYER met3 ;
        RECT 0.000 410.760 4.000 411.360 ;
    END
  END sstream_i[97]
  PIN sstream_i[98]
    DIRECTION INPUT ;
    USE SIGNAL ;
    ANTENNAGATEAREA 0.247500 ;
    PORT
      LAYER met3 ;
        RECT 0.000 412.120 4.000 412.720 ;
    END
  END sstream_i[98]
  PIN sstream_i[99]
    DIRECTION INPUT ;
    USE SIGNAL ;
    ANTENNAGATEAREA 0.247500 ;
    PORT
      LAYER met3 ;
        RECT 0.000 413.480 4.000 414.080 ;
    END
  END sstream_i[99]
  PIN sstream_i[9]
    DIRECTION INPUT ;
    USE SIGNAL ;
    ANTENNAGATEAREA 0.196500 ;
    PORT
      LAYER met3 ;
        RECT 0.000 291.080 4.000 291.680 ;
    END
  END sstream_i[9]
  PIN sstream_o
    DIRECTION OUTPUT TRISTATE ;
    USE SIGNAL ;
    ANTENNADIFFAREA 0.795200 ;
    PORT
      LAYER met3 ;
        RECT 0.000 436.600 4.000 437.200 ;
    END
  END sstream_o
  PIN t0x[0]
    DIRECTION INPUT ;
    USE SIGNAL ;
    ANTENNAGATEAREA 0.196500 ;
    PORT
      LAYER met2 ;
        RECT 50.230 0.000 50.510 4.000 ;
    END
  END t0x[0]
  PIN t0x[10]
    DIRECTION INPUT ;
    USE SIGNAL ;
    ANTENNAGATEAREA 0.213000 ;
    PORT
      LAYER met2 ;
        RECT 59.430 0.000 59.710 4.000 ;
    END
  END t0x[10]
  PIN t0x[11]
    DIRECTION INPUT ;
    USE SIGNAL ;
    ANTENNAGATEAREA 0.213000 ;
    PORT
      LAYER met2 ;
        RECT 60.350 0.000 60.630 4.000 ;
    END
  END t0x[11]
  PIN t0x[12]
    DIRECTION INPUT ;
    USE SIGNAL ;
    ANTENNAGATEAREA 0.159000 ;
    PORT
      LAYER met2 ;
        RECT 61.270 0.000 61.550 4.000 ;
    END
  END t0x[12]
  PIN t0x[13]
    DIRECTION INPUT ;
    USE SIGNAL ;
    ANTENNAGATEAREA 0.213000 ;
    PORT
      LAYER met2 ;
        RECT 62.190 0.000 62.470 4.000 ;
    END
  END t0x[13]
  PIN t0x[14]
    DIRECTION INPUT ;
    USE SIGNAL ;
    ANTENNAGATEAREA 0.159000 ;
    PORT
      LAYER met2 ;
        RECT 63.110 0.000 63.390 4.000 ;
    END
  END t0x[14]
  PIN t0x[15]
    DIRECTION INPUT ;
    USE SIGNAL ;
    ANTENNAGATEAREA 0.159000 ;
    PORT
      LAYER met2 ;
        RECT 64.030 0.000 64.310 4.000 ;
    END
  END t0x[15]
  PIN t0x[16]
    DIRECTION INPUT ;
    USE SIGNAL ;
    ANTENNAGATEAREA 0.159000 ;
    PORT
      LAYER met2 ;
        RECT 64.950 0.000 65.230 4.000 ;
    END
  END t0x[16]
  PIN t0x[17]
    DIRECTION INPUT ;
    USE SIGNAL ;
    ANTENNAGATEAREA 0.159000 ;
    PORT
      LAYER met2 ;
        RECT 65.870 0.000 66.150 4.000 ;
    END
  END t0x[17]
  PIN t0x[18]
    DIRECTION INPUT ;
    USE SIGNAL ;
    ANTENNAGATEAREA 0.159000 ;
    PORT
      LAYER met2 ;
        RECT 66.790 0.000 67.070 4.000 ;
    END
  END t0x[18]
  PIN t0x[19]
    DIRECTION INPUT ;
    USE SIGNAL ;
    ANTENNAGATEAREA 0.159000 ;
    PORT
      LAYER met2 ;
        RECT 67.710 0.000 67.990 4.000 ;
    END
  END t0x[19]
  PIN t0x[1]
    DIRECTION INPUT ;
    USE SIGNAL ;
    ANTENNAGATEAREA 0.196500 ;
    PORT
      LAYER met2 ;
        RECT 51.150 0.000 51.430 4.000 ;
    END
  END t0x[1]
  PIN t0x[20]
    DIRECTION INPUT ;
    USE SIGNAL ;
    ANTENNAGATEAREA 0.159000 ;
    PORT
      LAYER met2 ;
        RECT 68.630 0.000 68.910 4.000 ;
    END
  END t0x[20]
  PIN t0x[21]
    DIRECTION INPUT ;
    USE SIGNAL ;
    ANTENNAGATEAREA 0.213000 ;
    PORT
      LAYER met2 ;
        RECT 69.550 0.000 69.830 4.000 ;
    END
  END t0x[21]
  PIN t0x[22]
    DIRECTION INPUT ;
    USE SIGNAL ;
    ANTENNAGATEAREA 0.213000 ;
    PORT
      LAYER met2 ;
        RECT 70.470 0.000 70.750 4.000 ;
    END
  END t0x[22]
  PIN t0x[23]
    DIRECTION INPUT ;
    USE SIGNAL ;
    ANTENNAGATEAREA 0.213000 ;
    PORT
      LAYER met2 ;
        RECT 71.390 0.000 71.670 4.000 ;
    END
  END t0x[23]
  PIN t0x[24]
    DIRECTION INPUT ;
    USE SIGNAL ;
    ANTENNAGATEAREA 0.213000 ;
    PORT
      LAYER met2 ;
        RECT 72.310 0.000 72.590 4.000 ;
    END
  END t0x[24]
  PIN t0x[25]
    DIRECTION INPUT ;
    USE SIGNAL ;
    ANTENNAGATEAREA 0.213000 ;
    PORT
      LAYER met2 ;
        RECT 73.230 0.000 73.510 4.000 ;
    END
  END t0x[25]
  PIN t0x[26]
    DIRECTION INPUT ;
    USE SIGNAL ;
    ANTENNAGATEAREA 0.213000 ;
    PORT
      LAYER met2 ;
        RECT 74.150 0.000 74.430 4.000 ;
    END
  END t0x[26]
  PIN t0x[27]
    DIRECTION INPUT ;
    USE SIGNAL ;
    ANTENNAGATEAREA 0.247500 ;
    PORT
      LAYER met2 ;
        RECT 75.070 0.000 75.350 4.000 ;
    END
  END t0x[27]
  PIN t0x[28]
    DIRECTION INPUT ;
    USE SIGNAL ;
    ANTENNAGATEAREA 0.247500 ;
    PORT
      LAYER met2 ;
        RECT 75.990 0.000 76.270 4.000 ;
    END
  END t0x[28]
  PIN t0x[29]
    DIRECTION INPUT ;
    USE SIGNAL ;
    ANTENNAGATEAREA 0.247500 ;
    PORT
      LAYER met2 ;
        RECT 76.910 0.000 77.190 4.000 ;
    END
  END t0x[29]
  PIN t0x[2]
    DIRECTION INPUT ;
    USE SIGNAL ;
    ANTENNAGATEAREA 0.196500 ;
    PORT
      LAYER met2 ;
        RECT 52.070 0.000 52.350 4.000 ;
    END
  END t0x[2]
  PIN t0x[30]
    DIRECTION INPUT ;
    USE SIGNAL ;
    ANTENNAGATEAREA 0.247500 ;
    PORT
      LAYER met2 ;
        RECT 77.830 0.000 78.110 4.000 ;
    END
  END t0x[30]
  PIN t0x[31]
    DIRECTION INPUT ;
    USE SIGNAL ;
    ANTENNAGATEAREA 0.247500 ;
    PORT
      LAYER met2 ;
        RECT 78.750 0.000 79.030 4.000 ;
    END
  END t0x[31]
  PIN t0x[3]
    DIRECTION INPUT ;
    USE SIGNAL ;
    ANTENNAGATEAREA 0.196500 ;
    PORT
      LAYER met2 ;
        RECT 52.990 0.000 53.270 4.000 ;
    END
  END t0x[3]
  PIN t0x[4]
    DIRECTION INPUT ;
    USE SIGNAL ;
    ANTENNAGATEAREA 0.196500 ;
    PORT
      LAYER met2 ;
        RECT 53.910 0.000 54.190 4.000 ;
    END
  END t0x[4]
  PIN t0x[5]
    DIRECTION INPUT ;
    USE SIGNAL ;
    ANTENNAGATEAREA 0.196500 ;
    PORT
      LAYER met2 ;
        RECT 54.830 0.000 55.110 4.000 ;
    END
  END t0x[5]
  PIN t0x[6]
    DIRECTION INPUT ;
    USE SIGNAL ;
    ANTENNAGATEAREA 0.126000 ;
    PORT
      LAYER met2 ;
        RECT 55.750 0.000 56.030 4.000 ;
    END
  END t0x[6]
  PIN t0x[7]
    DIRECTION INPUT ;
    USE SIGNAL ;
    ANTENNAGATEAREA 0.213000 ;
    PORT
      LAYER met2 ;
        RECT 56.670 0.000 56.950 4.000 ;
    END
  END t0x[7]
  PIN t0x[8]
    DIRECTION INPUT ;
    USE SIGNAL ;
    ANTENNAGATEAREA 0.213000 ;
    PORT
      LAYER met2 ;
        RECT 57.590 0.000 57.870 4.000 ;
    END
  END t0x[8]
  PIN t0x[9]
    DIRECTION INPUT ;
    USE SIGNAL ;
    ANTENNAGATEAREA 0.213000 ;
    PORT
      LAYER met2 ;
        RECT 58.510 0.000 58.790 4.000 ;
    END
  END t0x[9]
  PIN t0y[0]
    DIRECTION INPUT ;
    USE SIGNAL ;
    ANTENNAGATEAREA 0.196500 ;
    PORT
      LAYER met3 ;
        RECT 0.000 61.240 4.000 61.840 ;
    END
  END t0y[0]
  PIN t0y[10]
    DIRECTION INPUT ;
    USE SIGNAL ;
    ANTENNAGATEAREA 0.213000 ;
    PORT
      LAYER met3 ;
        RECT 0.000 74.840 4.000 75.440 ;
    END
  END t0y[10]
  PIN t0y[11]
    DIRECTION INPUT ;
    USE SIGNAL ;
    ANTENNAGATEAREA 0.159000 ;
    PORT
      LAYER met3 ;
        RECT 0.000 76.200 4.000 76.800 ;
    END
  END t0y[11]
  PIN t0y[12]
    DIRECTION INPUT ;
    USE SIGNAL ;
    ANTENNAGATEAREA 0.159000 ;
    PORT
      LAYER met3 ;
        RECT 0.000 77.560 4.000 78.160 ;
    END
  END t0y[12]
  PIN t0y[13]
    DIRECTION INPUT ;
    USE SIGNAL ;
    ANTENNAGATEAREA 0.159000 ;
    PORT
      LAYER met3 ;
        RECT 0.000 78.920 4.000 79.520 ;
    END
  END t0y[13]
  PIN t0y[14]
    DIRECTION INPUT ;
    USE SIGNAL ;
    ANTENNAGATEAREA 0.159000 ;
    PORT
      LAYER met3 ;
        RECT 0.000 80.280 4.000 80.880 ;
    END
  END t0y[14]
  PIN t0y[15]
    DIRECTION INPUT ;
    USE SIGNAL ;
    ANTENNAGATEAREA 0.159000 ;
    PORT
      LAYER met3 ;
        RECT 0.000 81.640 4.000 82.240 ;
    END
  END t0y[15]
  PIN t0y[16]
    DIRECTION INPUT ;
    USE SIGNAL ;
    ANTENNAGATEAREA 0.213000 ;
    PORT
      LAYER met3 ;
        RECT 0.000 83.000 4.000 83.600 ;
    END
  END t0y[16]
  PIN t0y[17]
    DIRECTION INPUT ;
    USE SIGNAL ;
    ANTENNAGATEAREA 0.213000 ;
    PORT
      LAYER met3 ;
        RECT 0.000 84.360 4.000 84.960 ;
    END
  END t0y[17]
  PIN t0y[18]
    DIRECTION INPUT ;
    USE SIGNAL ;
    ANTENNAGATEAREA 0.213000 ;
    PORT
      LAYER met3 ;
        RECT 0.000 85.720 4.000 86.320 ;
    END
  END t0y[18]
  PIN t0y[19]
    DIRECTION INPUT ;
    USE SIGNAL ;
    ANTENNAGATEAREA 0.213000 ;
    PORT
      LAYER met3 ;
        RECT 0.000 87.080 4.000 87.680 ;
    END
  END t0y[19]
  PIN t0y[1]
    DIRECTION INPUT ;
    USE SIGNAL ;
    ANTENNAGATEAREA 0.196500 ;
    PORT
      LAYER met3 ;
        RECT 0.000 62.600 4.000 63.200 ;
    END
  END t0y[1]
  PIN t0y[20]
    DIRECTION INPUT ;
    USE SIGNAL ;
    ANTENNAGATEAREA 0.213000 ;
    PORT
      LAYER met3 ;
        RECT 0.000 88.440 4.000 89.040 ;
    END
  END t0y[20]
  PIN t0y[21]
    DIRECTION INPUT ;
    USE SIGNAL ;
    ANTENNAGATEAREA 0.213000 ;
    PORT
      LAYER met3 ;
        RECT 0.000 89.800 4.000 90.400 ;
    END
  END t0y[21]
  PIN t0y[22]
    DIRECTION INPUT ;
    USE SIGNAL ;
    ANTENNAGATEAREA 0.213000 ;
    PORT
      LAYER met3 ;
        RECT 0.000 91.160 4.000 91.760 ;
    END
  END t0y[22]
  PIN t0y[23]
    DIRECTION INPUT ;
    USE SIGNAL ;
    ANTENNAGATEAREA 0.213000 ;
    PORT
      LAYER met3 ;
        RECT 0.000 92.520 4.000 93.120 ;
    END
  END t0y[23]
  PIN t0y[24]
    DIRECTION INPUT ;
    USE SIGNAL ;
    ANTENNAGATEAREA 0.213000 ;
    PORT
      LAYER met3 ;
        RECT 0.000 93.880 4.000 94.480 ;
    END
  END t0y[24]
  PIN t0y[25]
    DIRECTION INPUT ;
    USE SIGNAL ;
    ANTENNAGATEAREA 0.247500 ;
    PORT
      LAYER met3 ;
        RECT 0.000 95.240 4.000 95.840 ;
    END
  END t0y[25]
  PIN t0y[26]
    DIRECTION INPUT ;
    USE SIGNAL ;
    ANTENNAGATEAREA 0.247500 ;
    PORT
      LAYER met3 ;
        RECT 0.000 96.600 4.000 97.200 ;
    END
  END t0y[26]
  PIN t0y[27]
    DIRECTION INPUT ;
    USE SIGNAL ;
    ANTENNAGATEAREA 0.247500 ;
    PORT
      LAYER met3 ;
        RECT 0.000 97.960 4.000 98.560 ;
    END
  END t0y[27]
  PIN t0y[28]
    DIRECTION INPUT ;
    USE SIGNAL ;
    ANTENNAGATEAREA 0.247500 ;
    PORT
      LAYER met3 ;
        RECT 0.000 99.320 4.000 99.920 ;
    END
  END t0y[28]
  PIN t0y[29]
    DIRECTION INPUT ;
    USE SIGNAL ;
    ANTENNAGATEAREA 0.247500 ;
    PORT
      LAYER met3 ;
        RECT 0.000 100.680 4.000 101.280 ;
    END
  END t0y[29]
  PIN t0y[2]
    DIRECTION INPUT ;
    USE SIGNAL ;
    ANTENNAGATEAREA 0.196500 ;
    PORT
      LAYER met3 ;
        RECT 0.000 63.960 4.000 64.560 ;
    END
  END t0y[2]
  PIN t0y[30]
    DIRECTION INPUT ;
    USE SIGNAL ;
    ANTENNAGATEAREA 0.247500 ;
    PORT
      LAYER met3 ;
        RECT 0.000 102.040 4.000 102.640 ;
    END
  END t0y[30]
  PIN t0y[31]
    DIRECTION INPUT ;
    USE SIGNAL ;
    ANTENNAGATEAREA 0.247500 ;
    PORT
      LAYER met3 ;
        RECT 0.000 103.400 4.000 104.000 ;
    END
  END t0y[31]
  PIN t0y[3]
    DIRECTION INPUT ;
    USE SIGNAL ;
    ANTENNAGATEAREA 0.196500 ;
    PORT
      LAYER met3 ;
        RECT 0.000 65.320 4.000 65.920 ;
    END
  END t0y[3]
  PIN t0y[4]
    DIRECTION INPUT ;
    USE SIGNAL ;
    ANTENNAGATEAREA 0.196500 ;
    PORT
      LAYER met3 ;
        RECT 0.000 66.680 4.000 67.280 ;
    END
  END t0y[4]
  PIN t0y[5]
    DIRECTION INPUT ;
    USE SIGNAL ;
    ANTENNAGATEAREA 0.213000 ;
    PORT
      LAYER met3 ;
        RECT 0.000 68.040 4.000 68.640 ;
    END
  END t0y[5]
  PIN t0y[6]
    DIRECTION INPUT ;
    USE SIGNAL ;
    ANTENNAGATEAREA 0.213000 ;
    PORT
      LAYER met3 ;
        RECT 0.000 69.400 4.000 70.000 ;
    END
  END t0y[6]
  PIN t0y[7]
    DIRECTION INPUT ;
    USE SIGNAL ;
    ANTENNAGATEAREA 0.213000 ;
    PORT
      LAYER met3 ;
        RECT 0.000 70.760 4.000 71.360 ;
    END
  END t0y[7]
  PIN t0y[8]
    DIRECTION INPUT ;
    USE SIGNAL ;
    ANTENNAGATEAREA 0.213000 ;
    PORT
      LAYER met3 ;
        RECT 0.000 72.120 4.000 72.720 ;
    END
  END t0y[8]
  PIN t0y[9]
    DIRECTION INPUT ;
    USE SIGNAL ;
    ANTENNAGATEAREA 0.213000 ;
    PORT
      LAYER met3 ;
        RECT 0.000 73.480 4.000 74.080 ;
    END
  END t0y[9]
  PIN t1x[0]
    DIRECTION INPUT ;
    USE SIGNAL ;
    ANTENNAGATEAREA 0.126000 ;
    PORT
      LAYER met3 ;
        RECT 0.000 104.760 4.000 105.360 ;
    END
  END t1x[0]
  PIN t1x[10]
    DIRECTION INPUT ;
    USE SIGNAL ;
    ANTENNAGATEAREA 0.159000 ;
    PORT
      LAYER met3 ;
        RECT 0.000 131.960 4.000 132.560 ;
    END
  END t1x[10]
  PIN t1x[11]
    DIRECTION INPUT ;
    USE SIGNAL ;
    ANTENNAGATEAREA 0.159000 ;
    PORT
      LAYER met3 ;
        RECT 0.000 134.680 4.000 135.280 ;
    END
  END t1x[11]
  PIN t1x[12]
    DIRECTION INPUT ;
    USE SIGNAL ;
    ANTENNAGATEAREA 0.213000 ;
    PORT
      LAYER met3 ;
        RECT 0.000 137.400 4.000 138.000 ;
    END
  END t1x[12]
  PIN t1x[13]
    DIRECTION INPUT ;
    USE SIGNAL ;
    ANTENNAGATEAREA 0.213000 ;
    PORT
      LAYER met3 ;
        RECT 0.000 140.120 4.000 140.720 ;
    END
  END t1x[13]
  PIN t1x[14]
    DIRECTION INPUT ;
    USE SIGNAL ;
    ANTENNAGATEAREA 0.213000 ;
    PORT
      LAYER met3 ;
        RECT 0.000 142.840 4.000 143.440 ;
    END
  END t1x[14]
  PIN t1x[15]
    DIRECTION INPUT ;
    USE SIGNAL ;
    ANTENNAGATEAREA 0.213000 ;
    PORT
      LAYER met3 ;
        RECT 0.000 145.560 4.000 146.160 ;
    END
  END t1x[15]
  PIN t1x[16]
    DIRECTION INPUT ;
    USE SIGNAL ;
    ANTENNAGATEAREA 0.213000 ;
    PORT
      LAYER met3 ;
        RECT 0.000 148.280 4.000 148.880 ;
    END
  END t1x[16]
  PIN t1x[17]
    DIRECTION INPUT ;
    USE SIGNAL ;
    ANTENNAGATEAREA 0.213000 ;
    PORT
      LAYER met3 ;
        RECT 0.000 151.000 4.000 151.600 ;
    END
  END t1x[17]
  PIN t1x[18]
    DIRECTION INPUT ;
    USE SIGNAL ;
    ANTENNAGATEAREA 0.213000 ;
    PORT
      LAYER met3 ;
        RECT 0.000 153.720 4.000 154.320 ;
    END
  END t1x[18]
  PIN t1x[19]
    DIRECTION INPUT ;
    USE SIGNAL ;
    ANTENNAGATEAREA 0.247500 ;
    PORT
      LAYER met3 ;
        RECT 0.000 156.440 4.000 157.040 ;
    END
  END t1x[19]
  PIN t1x[1]
    DIRECTION INPUT ;
    USE SIGNAL ;
    ANTENNAGATEAREA 0.213000 ;
    PORT
      LAYER met3 ;
        RECT 0.000 107.480 4.000 108.080 ;
    END
  END t1x[1]
  PIN t1x[20]
    DIRECTION INPUT ;
    USE SIGNAL ;
    ANTENNAGATEAREA 0.247500 ;
    PORT
      LAYER met3 ;
        RECT 0.000 159.160 4.000 159.760 ;
    END
  END t1x[20]
  PIN t1x[21]
    DIRECTION INPUT ;
    USE SIGNAL ;
    ANTENNAGATEAREA 0.247500 ;
    PORT
      LAYER met3 ;
        RECT 0.000 161.880 4.000 162.480 ;
    END
  END t1x[21]
  PIN t1x[22]
    DIRECTION INPUT ;
    USE SIGNAL ;
    ANTENNAGATEAREA 0.247500 ;
    PORT
      LAYER met3 ;
        RECT 0.000 164.600 4.000 165.200 ;
    END
  END t1x[22]
  PIN t1x[23]
    DIRECTION INPUT ;
    USE SIGNAL ;
    ANTENNAGATEAREA 0.247500 ;
    PORT
      LAYER met3 ;
        RECT 0.000 167.320 4.000 167.920 ;
    END
  END t1x[23]
  PIN t1x[24]
    DIRECTION INPUT ;
    USE SIGNAL ;
    ANTENNAGATEAREA 0.247500 ;
    PORT
      LAYER met3 ;
        RECT 0.000 170.040 4.000 170.640 ;
    END
  END t1x[24]
  PIN t1x[25]
    DIRECTION INPUT ;
    USE SIGNAL ;
    ANTENNAGATEAREA 0.247500 ;
    PORT
      LAYER met3 ;
        RECT 0.000 172.760 4.000 173.360 ;
    END
  END t1x[25]
  PIN t1x[26]
    DIRECTION INPUT ;
    USE SIGNAL ;
    ANTENNAGATEAREA 0.247500 ;
    PORT
      LAYER met3 ;
        RECT 0.000 175.480 4.000 176.080 ;
    END
  END t1x[26]
  PIN t1x[27]
    DIRECTION INPUT ;
    USE SIGNAL ;
    ANTENNAGATEAREA 0.247500 ;
    PORT
      LAYER met3 ;
        RECT 0.000 178.200 4.000 178.800 ;
    END
  END t1x[27]
  PIN t1x[28]
    DIRECTION INPUT ;
    USE SIGNAL ;
    ANTENNAGATEAREA 0.247500 ;
    PORT
      LAYER met3 ;
        RECT 0.000 180.920 4.000 181.520 ;
    END
  END t1x[28]
  PIN t1x[29]
    DIRECTION INPUT ;
    USE SIGNAL ;
    ANTENNAGATEAREA 0.426000 ;
    PORT
      LAYER met3 ;
        RECT 0.000 183.640 4.000 184.240 ;
    END
  END t1x[29]
  PIN t1x[2]
    DIRECTION INPUT ;
    USE SIGNAL ;
    ANTENNAGATEAREA 0.213000 ;
    PORT
      LAYER met3 ;
        RECT 0.000 110.200 4.000 110.800 ;
    END
  END t1x[2]
  PIN t1x[30]
    DIRECTION INPUT ;
    USE SIGNAL ;
    ANTENNAGATEAREA 0.426000 ;
    PORT
      LAYER met3 ;
        RECT 0.000 186.360 4.000 186.960 ;
    END
  END t1x[30]
  PIN t1x[31]
    DIRECTION INPUT ;
    USE SIGNAL ;
    ANTENNAGATEAREA 0.426000 ;
    PORT
      LAYER met3 ;
        RECT 0.000 189.080 4.000 189.680 ;
    END
  END t1x[31]
  PIN t1x[3]
    DIRECTION INPUT ;
    USE SIGNAL ;
    ANTENNAGATEAREA 0.213000 ;
    PORT
      LAYER met3 ;
        RECT 0.000 112.920 4.000 113.520 ;
    END
  END t1x[3]
  PIN t1x[4]
    DIRECTION INPUT ;
    USE SIGNAL ;
    ANTENNAGATEAREA 0.213000 ;
    PORT
      LAYER met3 ;
        RECT 0.000 115.640 4.000 116.240 ;
    END
  END t1x[4]
  PIN t1x[5]
    DIRECTION INPUT ;
    USE SIGNAL ;
    ANTENNAGATEAREA 0.213000 ;
    PORT
      LAYER met3 ;
        RECT 0.000 118.360 4.000 118.960 ;
    END
  END t1x[5]
  PIN t1x[6]
    DIRECTION INPUT ;
    USE SIGNAL ;
    ANTENNAGATEAREA 0.159000 ;
    PORT
      LAYER met3 ;
        RECT 0.000 121.080 4.000 121.680 ;
    END
  END t1x[6]
  PIN t1x[7]
    DIRECTION INPUT ;
    USE SIGNAL ;
    ANTENNAGATEAREA 0.159000 ;
    PORT
      LAYER met3 ;
        RECT 0.000 123.800 4.000 124.400 ;
    END
  END t1x[7]
  PIN t1x[8]
    DIRECTION INPUT ;
    USE SIGNAL ;
    ANTENNAGATEAREA 0.159000 ;
    PORT
      LAYER met3 ;
        RECT 0.000 126.520 4.000 127.120 ;
    END
  END t1x[8]
  PIN t1x[9]
    DIRECTION INPUT ;
    USE SIGNAL ;
    ANTENNAGATEAREA 0.159000 ;
    PORT
      LAYER met3 ;
        RECT 0.000 129.240 4.000 129.840 ;
    END
  END t1x[9]
  PIN t1y[0]
    DIRECTION INPUT ;
    USE SIGNAL ;
    ANTENNAGATEAREA 0.126000 ;
    PORT
      LAYER met3 ;
        RECT 0.000 106.120 4.000 106.720 ;
    END
  END t1y[0]
  PIN t1y[10]
    DIRECTION INPUT ;
    USE SIGNAL ;
    ANTENNAGATEAREA 0.159000 ;
    PORT
      LAYER met3 ;
        RECT 0.000 133.320 4.000 133.920 ;
    END
  END t1y[10]
  PIN t1y[11]
    DIRECTION INPUT ;
    USE SIGNAL ;
    ANTENNAGATEAREA 0.159000 ;
    PORT
      LAYER met3 ;
        RECT 0.000 136.040 4.000 136.640 ;
    END
  END t1y[11]
  PIN t1y[12]
    DIRECTION INPUT ;
    USE SIGNAL ;
    ANTENNAGATEAREA 0.213000 ;
    PORT
      LAYER met3 ;
        RECT 0.000 138.760 4.000 139.360 ;
    END
  END t1y[12]
  PIN t1y[13]
    DIRECTION INPUT ;
    USE SIGNAL ;
    ANTENNAGATEAREA 0.213000 ;
    PORT
      LAYER met3 ;
        RECT 0.000 141.480 4.000 142.080 ;
    END
  END t1y[13]
  PIN t1y[14]
    DIRECTION INPUT ;
    USE SIGNAL ;
    ANTENNAGATEAREA 0.213000 ;
    PORT
      LAYER met3 ;
        RECT 0.000 144.200 4.000 144.800 ;
    END
  END t1y[14]
  PIN t1y[15]
    DIRECTION INPUT ;
    USE SIGNAL ;
    ANTENNAGATEAREA 0.213000 ;
    PORT
      LAYER met3 ;
        RECT 0.000 146.920 4.000 147.520 ;
    END
  END t1y[15]
  PIN t1y[16]
    DIRECTION INPUT ;
    USE SIGNAL ;
    ANTENNAGATEAREA 0.213000 ;
    PORT
      LAYER met3 ;
        RECT 0.000 149.640 4.000 150.240 ;
    END
  END t1y[16]
  PIN t1y[17]
    DIRECTION INPUT ;
    USE SIGNAL ;
    ANTENNAGATEAREA 0.213000 ;
    PORT
      LAYER met3 ;
        RECT 0.000 152.360 4.000 152.960 ;
    END
  END t1y[17]
  PIN t1y[18]
    DIRECTION INPUT ;
    USE SIGNAL ;
    ANTENNAGATEAREA 0.213000 ;
    PORT
      LAYER met3 ;
        RECT 0.000 155.080 4.000 155.680 ;
    END
  END t1y[18]
  PIN t1y[19]
    DIRECTION INPUT ;
    USE SIGNAL ;
    ANTENNAGATEAREA 0.247500 ;
    PORT
      LAYER met3 ;
        RECT 0.000 157.800 4.000 158.400 ;
    END
  END t1y[19]
  PIN t1y[1]
    DIRECTION INPUT ;
    USE SIGNAL ;
    ANTENNAGATEAREA 0.213000 ;
    PORT
      LAYER met3 ;
        RECT 0.000 108.840 4.000 109.440 ;
    END
  END t1y[1]
  PIN t1y[20]
    DIRECTION INPUT ;
    USE SIGNAL ;
    ANTENNAGATEAREA 0.247500 ;
    PORT
      LAYER met3 ;
        RECT 0.000 160.520 4.000 161.120 ;
    END
  END t1y[20]
  PIN t1y[21]
    DIRECTION INPUT ;
    USE SIGNAL ;
    ANTENNAGATEAREA 0.247500 ;
    PORT
      LAYER met3 ;
        RECT 0.000 163.240 4.000 163.840 ;
    END
  END t1y[21]
  PIN t1y[22]
    DIRECTION INPUT ;
    USE SIGNAL ;
    ANTENNAGATEAREA 0.247500 ;
    PORT
      LAYER met3 ;
        RECT 0.000 165.960 4.000 166.560 ;
    END
  END t1y[22]
  PIN t1y[23]
    DIRECTION INPUT ;
    USE SIGNAL ;
    ANTENNAGATEAREA 0.247500 ;
    PORT
      LAYER met3 ;
        RECT 0.000 168.680 4.000 169.280 ;
    END
  END t1y[23]
  PIN t1y[24]
    DIRECTION INPUT ;
    USE SIGNAL ;
    ANTENNAGATEAREA 0.247500 ;
    PORT
      LAYER met3 ;
        RECT 0.000 171.400 4.000 172.000 ;
    END
  END t1y[24]
  PIN t1y[25]
    DIRECTION INPUT ;
    USE SIGNAL ;
    ANTENNAGATEAREA 0.247500 ;
    PORT
      LAYER met3 ;
        RECT 0.000 174.120 4.000 174.720 ;
    END
  END t1y[25]
  PIN t1y[26]
    DIRECTION INPUT ;
    USE SIGNAL ;
    ANTENNAGATEAREA 0.247500 ;
    PORT
      LAYER met3 ;
        RECT 0.000 176.840 4.000 177.440 ;
    END
  END t1y[26]
  PIN t1y[27]
    DIRECTION INPUT ;
    USE SIGNAL ;
    ANTENNAGATEAREA 0.247500 ;
    PORT
      LAYER met3 ;
        RECT 0.000 179.560 4.000 180.160 ;
    END
  END t1y[27]
  PIN t1y[28]
    DIRECTION INPUT ;
    USE SIGNAL ;
    ANTENNAGATEAREA 0.247500 ;
    PORT
      LAYER met3 ;
        RECT 0.000 182.280 4.000 182.880 ;
    END
  END t1y[28]
  PIN t1y[29]
    DIRECTION INPUT ;
    USE SIGNAL ;
    ANTENNAGATEAREA 0.426000 ;
    PORT
      LAYER met3 ;
        RECT 0.000 185.000 4.000 185.600 ;
    END
  END t1y[29]
  PIN t1y[2]
    DIRECTION INPUT ;
    USE SIGNAL ;
    ANTENNAGATEAREA 0.213000 ;
    PORT
      LAYER met3 ;
        RECT 0.000 111.560 4.000 112.160 ;
    END
  END t1y[2]
  PIN t1y[30]
    DIRECTION INPUT ;
    USE SIGNAL ;
    ANTENNAGATEAREA 0.426000 ;
    PORT
      LAYER met3 ;
        RECT 0.000 187.720 4.000 188.320 ;
    END
  END t1y[30]
  PIN t1y[31]
    DIRECTION INPUT ;
    USE SIGNAL ;
    ANTENNAGATEAREA 0.426000 ;
    PORT
      LAYER met3 ;
        RECT 0.000 190.440 4.000 191.040 ;
    END
  END t1y[31]
  PIN t1y[3]
    DIRECTION INPUT ;
    USE SIGNAL ;
    ANTENNAGATEAREA 0.213000 ;
    PORT
      LAYER met3 ;
        RECT 0.000 114.280 4.000 114.880 ;
    END
  END t1y[3]
  PIN t1y[4]
    DIRECTION INPUT ;
    USE SIGNAL ;
    ANTENNAGATEAREA 0.213000 ;
    PORT
      LAYER met3 ;
        RECT 0.000 117.000 4.000 117.600 ;
    END
  END t1y[4]
  PIN t1y[5]
    DIRECTION INPUT ;
    USE SIGNAL ;
    ANTENNAGATEAREA 0.213000 ;
    PORT
      LAYER met3 ;
        RECT 0.000 119.720 4.000 120.320 ;
    END
  END t1y[5]
  PIN t1y[6]
    DIRECTION INPUT ;
    USE SIGNAL ;
    ANTENNAGATEAREA 0.159000 ;
    PORT
      LAYER met3 ;
        RECT 0.000 122.440 4.000 123.040 ;
    END
  END t1y[6]
  PIN t1y[7]
    DIRECTION INPUT ;
    USE SIGNAL ;
    ANTENNAGATEAREA 0.159000 ;
    PORT
      LAYER met3 ;
        RECT 0.000 125.160 4.000 125.760 ;
    END
  END t1y[7]
  PIN t1y[8]
    DIRECTION INPUT ;
    USE SIGNAL ;
    ANTENNAGATEAREA 0.159000 ;
    PORT
      LAYER met3 ;
        RECT 0.000 127.880 4.000 128.480 ;
    END
  END t1y[8]
  PIN t1y[9]
    DIRECTION INPUT ;
    USE SIGNAL ;
    ANTENNAGATEAREA 0.159000 ;
    PORT
      LAYER met3 ;
        RECT 0.000 130.600 4.000 131.200 ;
    END
  END t1y[9]
  PIN t2x[0]
    DIRECTION INPUT ;
    USE SIGNAL ;
    ANTENNAGATEAREA 0.213000 ;
    PORT
      LAYER met3 ;
        RECT 0.000 191.800 4.000 192.400 ;
    END
  END t2x[0]
  PIN t2x[10]
    DIRECTION INPUT ;
    USE SIGNAL ;
    ANTENNAGATEAREA 0.213000 ;
    PORT
      LAYER met3 ;
        RECT 0.000 219.000 4.000 219.600 ;
    END
  END t2x[10]
  PIN t2x[11]
    DIRECTION INPUT ;
    USE SIGNAL ;
    ANTENNAGATEAREA 0.213000 ;
    PORT
      LAYER met3 ;
        RECT 0.000 221.720 4.000 222.320 ;
    END
  END t2x[11]
  PIN t2x[12]
    DIRECTION INPUT ;
    USE SIGNAL ;
    ANTENNAGATEAREA 0.213000 ;
    PORT
      LAYER met3 ;
        RECT 0.000 224.440 4.000 225.040 ;
    END
  END t2x[12]
  PIN t2x[13]
    DIRECTION INPUT ;
    USE SIGNAL ;
    ANTENNAGATEAREA 0.213000 ;
    PORT
      LAYER met3 ;
        RECT 0.000 227.160 4.000 227.760 ;
    END
  END t2x[13]
  PIN t2x[14]
    DIRECTION INPUT ;
    USE SIGNAL ;
    ANTENNAGATEAREA 0.247500 ;
    PORT
      LAYER met3 ;
        RECT 0.000 229.880 4.000 230.480 ;
    END
  END t2x[14]
  PIN t2x[15]
    DIRECTION INPUT ;
    USE SIGNAL ;
    ANTENNAGATEAREA 0.247500 ;
    PORT
      LAYER met3 ;
        RECT 0.000 232.600 4.000 233.200 ;
    END
  END t2x[15]
  PIN t2x[16]
    DIRECTION INPUT ;
    USE SIGNAL ;
    ANTENNAGATEAREA 0.247500 ;
    PORT
      LAYER met3 ;
        RECT 0.000 235.320 4.000 235.920 ;
    END
  END t2x[16]
  PIN t2x[17]
    DIRECTION INPUT ;
    USE SIGNAL ;
    ANTENNAGATEAREA 0.247500 ;
    PORT
      LAYER met3 ;
        RECT 0.000 238.040 4.000 238.640 ;
    END
  END t2x[17]
  PIN t2x[18]
    DIRECTION INPUT ;
    USE SIGNAL ;
    ANTENNAGATEAREA 0.247500 ;
    PORT
      LAYER met3 ;
        RECT 0.000 240.760 4.000 241.360 ;
    END
  END t2x[18]
  PIN t2x[19]
    DIRECTION INPUT ;
    USE SIGNAL ;
    ANTENNAGATEAREA 0.247500 ;
    PORT
      LAYER met3 ;
        RECT 0.000 243.480 4.000 244.080 ;
    END
  END t2x[19]
  PIN t2x[1]
    DIRECTION INPUT ;
    USE SIGNAL ;
    ANTENNAGATEAREA 0.213000 ;
    PORT
      LAYER met3 ;
        RECT 0.000 194.520 4.000 195.120 ;
    END
  END t2x[1]
  PIN t2x[20]
    DIRECTION INPUT ;
    USE SIGNAL ;
    ANTENNAGATEAREA 0.247500 ;
    PORT
      LAYER met3 ;
        RECT 0.000 246.200 4.000 246.800 ;
    END
  END t2x[20]
  PIN t2x[21]
    DIRECTION INPUT ;
    USE SIGNAL ;
    ANTENNAGATEAREA 0.247500 ;
    PORT
      LAYER met3 ;
        RECT 0.000 248.920 4.000 249.520 ;
    END
  END t2x[21]
  PIN t2x[22]
    DIRECTION INPUT ;
    USE SIGNAL ;
    ANTENNAGATEAREA 0.247500 ;
    PORT
      LAYER met3 ;
        RECT 0.000 251.640 4.000 252.240 ;
    END
  END t2x[22]
  PIN t2x[23]
    DIRECTION INPUT ;
    USE SIGNAL ;
    ANTENNAGATEAREA 0.247500 ;
    PORT
      LAYER met3 ;
        RECT 0.000 254.360 4.000 254.960 ;
    END
  END t2x[23]
  PIN t2x[24]
    DIRECTION INPUT ;
    USE SIGNAL ;
    ANTENNAGATEAREA 0.426000 ;
    PORT
      LAYER met3 ;
        RECT 0.000 257.080 4.000 257.680 ;
    END
  END t2x[24]
  PIN t2x[25]
    DIRECTION INPUT ;
    USE SIGNAL ;
    ANTENNAGATEAREA 0.426000 ;
    PORT
      LAYER met3 ;
        RECT 0.000 259.800 4.000 260.400 ;
    END
  END t2x[25]
  PIN t2x[26]
    DIRECTION INPUT ;
    USE SIGNAL ;
    ANTENNAGATEAREA 0.426000 ;
    PORT
      LAYER met3 ;
        RECT 0.000 262.520 4.000 263.120 ;
    END
  END t2x[26]
  PIN t2x[27]
    DIRECTION INPUT ;
    USE SIGNAL ;
    ANTENNAGATEAREA 0.426000 ;
    PORT
      LAYER met3 ;
        RECT 0.000 265.240 4.000 265.840 ;
    END
  END t2x[27]
  PIN t2x[28]
    DIRECTION INPUT ;
    USE SIGNAL ;
    ANTENNAGATEAREA 0.426000 ;
    PORT
      LAYER met3 ;
        RECT 0.000 267.960 4.000 268.560 ;
    END
  END t2x[28]
  PIN t2x[29]
    DIRECTION INPUT ;
    USE SIGNAL ;
    ANTENNAGATEAREA 0.426000 ;
    PORT
      LAYER met3 ;
        RECT 0.000 270.680 4.000 271.280 ;
    END
  END t2x[29]
  PIN t2x[2]
    DIRECTION INPUT ;
    USE SIGNAL ;
    ANTENNAGATEAREA 0.159000 ;
    PORT
      LAYER met3 ;
        RECT 0.000 197.240 4.000 197.840 ;
    END
  END t2x[2]
  PIN t2x[30]
    DIRECTION INPUT ;
    USE SIGNAL ;
    ANTENNAGATEAREA 0.426000 ;
    PORT
      LAYER met3 ;
        RECT 0.000 273.400 4.000 274.000 ;
    END
  END t2x[30]
  PIN t2x[31]
    DIRECTION INPUT ;
    USE SIGNAL ;
    ANTENNAGATEAREA 0.426000 ;
    PORT
      LAYER met3 ;
        RECT 0.000 276.120 4.000 276.720 ;
    END
  END t2x[31]
  PIN t2x[3]
    DIRECTION INPUT ;
    USE SIGNAL ;
    ANTENNAGATEAREA 0.159000 ;
    PORT
      LAYER met3 ;
        RECT 0.000 199.960 4.000 200.560 ;
    END
  END t2x[3]
  PIN t2x[4]
    DIRECTION INPUT ;
    USE SIGNAL ;
    ANTENNAGATEAREA 0.159000 ;
    PORT
      LAYER met3 ;
        RECT 0.000 202.680 4.000 203.280 ;
    END
  END t2x[4]
  PIN t2x[5]
    DIRECTION INPUT ;
    USE SIGNAL ;
    ANTENNAGATEAREA 0.159000 ;
    PORT
      LAYER met3 ;
        RECT 0.000 205.400 4.000 206.000 ;
    END
  END t2x[5]
  PIN t2x[6]
    DIRECTION INPUT ;
    USE SIGNAL ;
    ANTENNAGATEAREA 0.159000 ;
    PORT
      LAYER met3 ;
        RECT 0.000 208.120 4.000 208.720 ;
    END
  END t2x[6]
  PIN t2x[7]
    DIRECTION INPUT ;
    USE SIGNAL ;
    ANTENNAGATEAREA 0.213000 ;
    PORT
      LAYER met3 ;
        RECT 0.000 210.840 4.000 211.440 ;
    END
  END t2x[7]
  PIN t2x[8]
    DIRECTION INPUT ;
    USE SIGNAL ;
    ANTENNAGATEAREA 0.213000 ;
    PORT
      LAYER met3 ;
        RECT 0.000 213.560 4.000 214.160 ;
    END
  END t2x[8]
  PIN t2x[9]
    DIRECTION INPUT ;
    USE SIGNAL ;
    ANTENNAGATEAREA 0.213000 ;
    PORT
      LAYER met3 ;
        RECT 0.000 216.280 4.000 216.880 ;
    END
  END t2x[9]
  PIN t2y[0]
    DIRECTION INPUT ;
    USE SIGNAL ;
    ANTENNAGATEAREA 0.213000 ;
    PORT
      LAYER met3 ;
        RECT 0.000 193.160 4.000 193.760 ;
    END
  END t2y[0]
  PIN t2y[10]
    DIRECTION INPUT ;
    USE SIGNAL ;
    ANTENNAGATEAREA 0.213000 ;
    PORT
      LAYER met3 ;
        RECT 0.000 220.360 4.000 220.960 ;
    END
  END t2y[10]
  PIN t2y[11]
    DIRECTION INPUT ;
    USE SIGNAL ;
    ANTENNAGATEAREA 0.213000 ;
    PORT
      LAYER met3 ;
        RECT 0.000 223.080 4.000 223.680 ;
    END
  END t2y[11]
  PIN t2y[12]
    DIRECTION INPUT ;
    USE SIGNAL ;
    ANTENNAGATEAREA 0.213000 ;
    PORT
      LAYER met3 ;
        RECT 0.000 225.800 4.000 226.400 ;
    END
  END t2y[12]
  PIN t2y[13]
    DIRECTION INPUT ;
    USE SIGNAL ;
    ANTENNAGATEAREA 0.213000 ;
    PORT
      LAYER met3 ;
        RECT 0.000 228.520 4.000 229.120 ;
    END
  END t2y[13]
  PIN t2y[14]
    DIRECTION INPUT ;
    USE SIGNAL ;
    ANTENNAGATEAREA 0.247500 ;
    PORT
      LAYER met3 ;
        RECT 0.000 231.240 4.000 231.840 ;
    END
  END t2y[14]
  PIN t2y[15]
    DIRECTION INPUT ;
    USE SIGNAL ;
    ANTENNAGATEAREA 0.247500 ;
    PORT
      LAYER met3 ;
        RECT 0.000 233.960 4.000 234.560 ;
    END
  END t2y[15]
  PIN t2y[16]
    DIRECTION INPUT ;
    USE SIGNAL ;
    ANTENNAGATEAREA 0.247500 ;
    PORT
      LAYER met3 ;
        RECT 0.000 236.680 4.000 237.280 ;
    END
  END t2y[16]
  PIN t2y[17]
    DIRECTION INPUT ;
    USE SIGNAL ;
    ANTENNAGATEAREA 0.247500 ;
    PORT
      LAYER met3 ;
        RECT 0.000 239.400 4.000 240.000 ;
    END
  END t2y[17]
  PIN t2y[18]
    DIRECTION INPUT ;
    USE SIGNAL ;
    ANTENNAGATEAREA 0.247500 ;
    PORT
      LAYER met3 ;
        RECT 0.000 242.120 4.000 242.720 ;
    END
  END t2y[18]
  PIN t2y[19]
    DIRECTION INPUT ;
    USE SIGNAL ;
    ANTENNAGATEAREA 0.247500 ;
    PORT
      LAYER met3 ;
        RECT 0.000 244.840 4.000 245.440 ;
    END
  END t2y[19]
  PIN t2y[1]
    DIRECTION INPUT ;
    USE SIGNAL ;
    ANTENNAGATEAREA 0.213000 ;
    PORT
      LAYER met3 ;
        RECT 0.000 195.880 4.000 196.480 ;
    END
  END t2y[1]
  PIN t2y[20]
    DIRECTION INPUT ;
    USE SIGNAL ;
    ANTENNAGATEAREA 0.247500 ;
    PORT
      LAYER met3 ;
        RECT 0.000 247.560 4.000 248.160 ;
    END
  END t2y[20]
  PIN t2y[21]
    DIRECTION INPUT ;
    USE SIGNAL ;
    ANTENNAGATEAREA 0.247500 ;
    PORT
      LAYER met3 ;
        RECT 0.000 250.280 4.000 250.880 ;
    END
  END t2y[21]
  PIN t2y[22]
    DIRECTION INPUT ;
    USE SIGNAL ;
    ANTENNAGATEAREA 0.247500 ;
    PORT
      LAYER met3 ;
        RECT 0.000 253.000 4.000 253.600 ;
    END
  END t2y[22]
  PIN t2y[23]
    DIRECTION INPUT ;
    USE SIGNAL ;
    ANTENNAGATEAREA 0.247500 ;
    PORT
      LAYER met3 ;
        RECT 0.000 255.720 4.000 256.320 ;
    END
  END t2y[23]
  PIN t2y[24]
    DIRECTION INPUT ;
    USE SIGNAL ;
    ANTENNAGATEAREA 0.426000 ;
    PORT
      LAYER met3 ;
        RECT 0.000 258.440 4.000 259.040 ;
    END
  END t2y[24]
  PIN t2y[25]
    DIRECTION INPUT ;
    USE SIGNAL ;
    ANTENNAGATEAREA 0.426000 ;
    PORT
      LAYER met3 ;
        RECT 0.000 261.160 4.000 261.760 ;
    END
  END t2y[25]
  PIN t2y[26]
    DIRECTION INPUT ;
    USE SIGNAL ;
    ANTENNAGATEAREA 0.426000 ;
    PORT
      LAYER met3 ;
        RECT 0.000 263.880 4.000 264.480 ;
    END
  END t2y[26]
  PIN t2y[27]
    DIRECTION INPUT ;
    USE SIGNAL ;
    ANTENNAGATEAREA 0.426000 ;
    PORT
      LAYER met3 ;
        RECT 0.000 266.600 4.000 267.200 ;
    END
  END t2y[27]
  PIN t2y[28]
    DIRECTION INPUT ;
    USE SIGNAL ;
    ANTENNAGATEAREA 0.426000 ;
    PORT
      LAYER met3 ;
        RECT 0.000 269.320 4.000 269.920 ;
    END
  END t2y[28]
  PIN t2y[29]
    DIRECTION INPUT ;
    USE SIGNAL ;
    ANTENNAGATEAREA 0.426000 ;
    PORT
      LAYER met3 ;
        RECT 0.000 272.040 4.000 272.640 ;
    END
  END t2y[29]
  PIN t2y[2]
    DIRECTION INPUT ;
    USE SIGNAL ;
    ANTENNAGATEAREA 0.159000 ;
    PORT
      LAYER met3 ;
        RECT 0.000 198.600 4.000 199.200 ;
    END
  END t2y[2]
  PIN t2y[30]
    DIRECTION INPUT ;
    USE SIGNAL ;
    ANTENNAGATEAREA 0.426000 ;
    PORT
      LAYER met3 ;
        RECT 0.000 274.760 4.000 275.360 ;
    END
  END t2y[30]
  PIN t2y[31]
    DIRECTION INPUT ;
    USE SIGNAL ;
    ANTENNAGATEAREA 0.426000 ;
    PORT
      LAYER met3 ;
        RECT 0.000 277.480 4.000 278.080 ;
    END
  END t2y[31]
  PIN t2y[3]
    DIRECTION INPUT ;
    USE SIGNAL ;
    ANTENNAGATEAREA 0.159000 ;
    PORT
      LAYER met3 ;
        RECT 0.000 201.320 4.000 201.920 ;
    END
  END t2y[3]
  PIN t2y[4]
    DIRECTION INPUT ;
    USE SIGNAL ;
    ANTENNAGATEAREA 0.159000 ;
    PORT
      LAYER met3 ;
        RECT 0.000 204.040 4.000 204.640 ;
    END
  END t2y[4]
  PIN t2y[5]
    DIRECTION INPUT ;
    USE SIGNAL ;
    ANTENNAGATEAREA 0.159000 ;
    PORT
      LAYER met3 ;
        RECT 0.000 206.760 4.000 207.360 ;
    END
  END t2y[5]
  PIN t2y[6]
    DIRECTION INPUT ;
    USE SIGNAL ;
    ANTENNAGATEAREA 0.159000 ;
    PORT
      LAYER met3 ;
        RECT 0.000 209.480 4.000 210.080 ;
    END
  END t2y[6]
  PIN t2y[7]
    DIRECTION INPUT ;
    USE SIGNAL ;
    ANTENNAGATEAREA 0.213000 ;
    PORT
      LAYER met3 ;
        RECT 0.000 212.200 4.000 212.800 ;
    END
  END t2y[7]
  PIN t2y[8]
    DIRECTION INPUT ;
    USE SIGNAL ;
    ANTENNAGATEAREA 0.213000 ;
    PORT
      LAYER met3 ;
        RECT 0.000 214.920 4.000 215.520 ;
    END
  END t2y[8]
  PIN t2y[9]
    DIRECTION INPUT ;
    USE SIGNAL ;
    ANTENNAGATEAREA 0.213000 ;
    PORT
      LAYER met3 ;
        RECT 0.000 217.640 4.000 218.240 ;
    END
  END t2y[9]
  PIN u0a_i[0]
    DIRECTION INPUT ;
    USE SIGNAL ;
    ANTENNAGATEAREA 0.247500 ;
    PORT
      LAYER met2 ;
        RECT 79.670 0.000 79.950 4.000 ;
    END
  END u0a_i[0]
  PIN u0a_i[10]
    DIRECTION INPUT ;
    USE SIGNAL ;
    ANTENNAGATEAREA 0.213000 ;
    PORT
      LAYER met2 ;
        RECT 248.950 0.000 249.230 4.000 ;
    END
  END u0a_i[10]
  PIN u0a_i[11]
    DIRECTION INPUT ;
    USE SIGNAL ;
    ANTENNAGATEAREA 0.213000 ;
    PORT
      LAYER met2 ;
        RECT 265.510 0.000 265.790 4.000 ;
    END
  END u0a_i[11]
  PIN u0a_i[12]
    DIRECTION INPUT ;
    USE SIGNAL ;
    ANTENNAGATEAREA 0.213000 ;
    PORT
      LAYER met2 ;
        RECT 282.070 0.000 282.350 4.000 ;
    END
  END u0a_i[12]
  PIN u0a_i[13]
    DIRECTION INPUT ;
    USE SIGNAL ;
    ANTENNAGATEAREA 0.213000 ;
    PORT
      LAYER met2 ;
        RECT 298.630 0.000 298.910 4.000 ;
    END
  END u0a_i[13]
  PIN u0a_i[14]
    DIRECTION INPUT ;
    USE SIGNAL ;
    ANTENNAGATEAREA 0.159000 ;
    PORT
      LAYER met2 ;
        RECT 315.190 0.000 315.470 4.000 ;
    END
  END u0a_i[14]
  PIN u0a_i[15]
    DIRECTION INPUT ;
    USE SIGNAL ;
    ANTENNAGATEAREA 0.159000 ;
    PORT
      LAYER met2 ;
        RECT 331.750 0.000 332.030 4.000 ;
    END
  END u0a_i[15]
  PIN u0a_i[16]
    DIRECTION INPUT ;
    USE SIGNAL ;
    ANTENNAGATEAREA 0.213000 ;
    PORT
      LAYER met2 ;
        RECT 348.310 0.000 348.590 4.000 ;
    END
  END u0a_i[16]
  PIN u0a_i[17]
    DIRECTION INPUT ;
    USE SIGNAL ;
    ANTENNAGATEAREA 0.213000 ;
    PORT
      LAYER met2 ;
        RECT 364.870 0.000 365.150 4.000 ;
    END
  END u0a_i[17]
  PIN u0a_i[18]
    DIRECTION INPUT ;
    USE SIGNAL ;
    ANTENNAGATEAREA 0.213000 ;
    PORT
      LAYER met2 ;
        RECT 381.430 0.000 381.710 4.000 ;
    END
  END u0a_i[18]
  PIN u0a_i[19]
    DIRECTION INPUT ;
    USE SIGNAL ;
    ANTENNAGATEAREA 0.213000 ;
    PORT
      LAYER met2 ;
        RECT 397.990 0.000 398.270 4.000 ;
    END
  END u0a_i[19]
  PIN u0a_i[1]
    DIRECTION INPUT ;
    USE SIGNAL ;
    ANTENNAGATEAREA 0.247500 ;
    PORT
      LAYER met2 ;
        RECT 97.150 0.000 97.430 4.000 ;
    END
  END u0a_i[1]
  PIN u0a_i[20]
    DIRECTION INPUT ;
    USE SIGNAL ;
    ANTENNAGATEAREA 0.213000 ;
    PORT
      LAYER met2 ;
        RECT 414.550 0.000 414.830 4.000 ;
    END
  END u0a_i[20]
  PIN u0a_i[21]
    DIRECTION INPUT ;
    USE SIGNAL ;
    ANTENNAGATEAREA 0.213000 ;
    PORT
      LAYER met2 ;
        RECT 431.110 0.000 431.390 4.000 ;
    END
  END u0a_i[21]
  PIN u0a_i[22]
    DIRECTION INPUT ;
    USE SIGNAL ;
    ANTENNAGATEAREA 0.159000 ;
    PORT
      LAYER met2 ;
        RECT 447.670 0.000 447.950 4.000 ;
    END
  END u0a_i[22]
  PIN u0a_i[23]
    DIRECTION INPUT ;
    USE SIGNAL ;
    ANTENNAGATEAREA 0.159000 ;
    PORT
      LAYER met2 ;
        RECT 464.230 0.000 464.510 4.000 ;
    END
  END u0a_i[23]
  PIN u0a_i[24]
    DIRECTION INPUT ;
    USE SIGNAL ;
    ANTENNAGATEAREA 0.159000 ;
    PORT
      LAYER met2 ;
        RECT 480.790 0.000 481.070 4.000 ;
    END
  END u0a_i[24]
  PIN u0a_i[25]
    DIRECTION INPUT ;
    USE SIGNAL ;
    ANTENNAGATEAREA 0.159000 ;
    PORT
      LAYER met2 ;
        RECT 497.350 0.000 497.630 4.000 ;
    END
  END u0a_i[25]
  PIN u0a_i[26]
    DIRECTION INPUT ;
    USE SIGNAL ;
    ANTENNAGATEAREA 0.159000 ;
    PORT
      LAYER met2 ;
        RECT 513.910 0.000 514.190 4.000 ;
    END
  END u0a_i[26]
  PIN u0a_i[27]
    DIRECTION INPUT ;
    USE SIGNAL ;
    ANTENNAGATEAREA 0.159000 ;
    PORT
      LAYER met2 ;
        RECT 530.470 0.000 530.750 4.000 ;
    END
  END u0a_i[27]
  PIN u0a_i[28]
    DIRECTION INPUT ;
    USE SIGNAL ;
    ANTENNAGATEAREA 0.159000 ;
    PORT
      LAYER met2 ;
        RECT 547.030 0.000 547.310 4.000 ;
    END
  END u0a_i[28]
  PIN u0a_i[29]
    DIRECTION INPUT ;
    USE SIGNAL ;
    ANTENNAGATEAREA 0.159000 ;
    PORT
      LAYER met2 ;
        RECT 563.590 0.000 563.870 4.000 ;
    END
  END u0a_i[29]
  PIN u0a_i[2]
    DIRECTION INPUT ;
    USE SIGNAL ;
    ANTENNAGATEAREA 0.247500 ;
    PORT
      LAYER met2 ;
        RECT 114.630 0.000 114.910 4.000 ;
    END
  END u0a_i[2]
  PIN u0a_i[30]
    DIRECTION INPUT ;
    USE SIGNAL ;
    ANTENNAGATEAREA 0.213000 ;
    PORT
      LAYER met2 ;
        RECT 580.150 0.000 580.430 4.000 ;
    END
  END u0a_i[30]
  PIN u0a_i[31]
    DIRECTION INPUT ;
    USE SIGNAL ;
    ANTENNAGATEAREA 0.213000 ;
    PORT
      LAYER met2 ;
        RECT 596.710 0.000 596.990 4.000 ;
    END
  END u0a_i[31]
  PIN u0a_i[3]
    DIRECTION INPUT ;
    USE SIGNAL ;
    ANTENNAGATEAREA 0.247500 ;
    PORT
      LAYER met2 ;
        RECT 132.110 0.000 132.390 4.000 ;
    END
  END u0a_i[3]
  PIN u0a_i[4]
    DIRECTION INPUT ;
    USE SIGNAL ;
    ANTENNAGATEAREA 0.247500 ;
    PORT
      LAYER met2 ;
        RECT 149.590 0.000 149.870 4.000 ;
    END
  END u0a_i[4]
  PIN u0a_i[5]
    DIRECTION INPUT ;
    USE SIGNAL ;
    ANTENNAGATEAREA 0.247500 ;
    PORT
      LAYER met2 ;
        RECT 166.150 0.000 166.430 4.000 ;
    END
  END u0a_i[5]
  PIN u0a_i[6]
    DIRECTION INPUT ;
    USE SIGNAL ;
    ANTENNAGATEAREA 0.247500 ;
    PORT
      LAYER met2 ;
        RECT 182.710 0.000 182.990 4.000 ;
    END
  END u0a_i[6]
  PIN u0a_i[7]
    DIRECTION INPUT ;
    USE SIGNAL ;
    ANTENNAGATEAREA 0.213000 ;
    PORT
      LAYER met2 ;
        RECT 199.270 0.000 199.550 4.000 ;
    END
  END u0a_i[7]
  PIN u0a_i[8]
    DIRECTION INPUT ;
    USE SIGNAL ;
    ANTENNAGATEAREA 0.213000 ;
    PORT
      LAYER met2 ;
        RECT 215.830 0.000 216.110 4.000 ;
    END
  END u0a_i[8]
  PIN u0a_i[9]
    DIRECTION INPUT ;
    USE SIGNAL ;
    ANTENNAGATEAREA 0.213000 ;
    PORT
      LAYER met2 ;
        RECT 232.390 0.000 232.670 4.000 ;
    END
  END u0a_i[9]
  PIN u0b_i[0]
    DIRECTION INPUT ;
    USE SIGNAL ;
    ANTENNAGATEAREA 0.426000 ;
    PORT
      LAYER met2 ;
        RECT 80.590 0.000 80.870 4.000 ;
    END
  END u0b_i[0]
  PIN u0b_i[10]
    DIRECTION INPUT ;
    USE SIGNAL ;
    ANTENNAGATEAREA 0.213000 ;
    PORT
      LAYER met2 ;
        RECT 249.870 0.000 250.150 4.000 ;
    END
  END u0b_i[10]
  PIN u0b_i[11]
    DIRECTION INPUT ;
    USE SIGNAL ;
    ANTENNAGATEAREA 0.213000 ;
    PORT
      LAYER met2 ;
        RECT 266.430 0.000 266.710 4.000 ;
    END
  END u0b_i[11]
  PIN u0b_i[12]
    DIRECTION INPUT ;
    USE SIGNAL ;
    ANTENNAGATEAREA 0.213000 ;
    PORT
      LAYER met2 ;
        RECT 282.990 0.000 283.270 4.000 ;
    END
  END u0b_i[12]
  PIN u0b_i[13]
    DIRECTION INPUT ;
    USE SIGNAL ;
    ANTENNAGATEAREA 0.247500 ;
    PORT
      LAYER met2 ;
        RECT 299.550 0.000 299.830 4.000 ;
    END
  END u0b_i[13]
  PIN u0b_i[14]
    DIRECTION INPUT ;
    USE SIGNAL ;
    ANTENNAGATEAREA 0.213000 ;
    PORT
      LAYER met2 ;
        RECT 316.110 0.000 316.390 4.000 ;
    END
  END u0b_i[14]
  PIN u0b_i[15]
    DIRECTION INPUT ;
    USE SIGNAL ;
    ANTENNAGATEAREA 0.213000 ;
    PORT
      LAYER met2 ;
        RECT 332.670 0.000 332.950 4.000 ;
    END
  END u0b_i[15]
  PIN u0b_i[16]
    DIRECTION INPUT ;
    USE SIGNAL ;
    ANTENNAGATEAREA 0.247500 ;
    PORT
      LAYER met2 ;
        RECT 349.230 0.000 349.510 4.000 ;
    END
  END u0b_i[16]
  PIN u0b_i[17]
    DIRECTION INPUT ;
    USE SIGNAL ;
    ANTENNAGATEAREA 0.247500 ;
    PORT
      LAYER met2 ;
        RECT 365.790 0.000 366.070 4.000 ;
    END
  END u0b_i[17]
  PIN u0b_i[18]
    DIRECTION INPUT ;
    USE SIGNAL ;
    ANTENNAGATEAREA 0.213000 ;
    PORT
      LAYER met2 ;
        RECT 382.350 0.000 382.630 4.000 ;
    END
  END u0b_i[18]
  PIN u0b_i[19]
    DIRECTION INPUT ;
    USE SIGNAL ;
    ANTENNAGATEAREA 0.213000 ;
    PORT
      LAYER met2 ;
        RECT 398.910 0.000 399.190 4.000 ;
    END
  END u0b_i[19]
  PIN u0b_i[1]
    DIRECTION INPUT ;
    USE SIGNAL ;
    ANTENNAGATEAREA 0.247500 ;
    PORT
      LAYER met2 ;
        RECT 98.070 0.000 98.350 4.000 ;
    END
  END u0b_i[1]
  PIN u0b_i[20]
    DIRECTION INPUT ;
    USE SIGNAL ;
    ANTENNAGATEAREA 0.213000 ;
    PORT
      LAYER met2 ;
        RECT 415.470 0.000 415.750 4.000 ;
    END
  END u0b_i[20]
  PIN u0b_i[21]
    DIRECTION INPUT ;
    USE SIGNAL ;
    ANTENNAGATEAREA 0.213000 ;
    PORT
      LAYER met2 ;
        RECT 432.030 0.000 432.310 4.000 ;
    END
  END u0b_i[21]
  PIN u0b_i[22]
    DIRECTION INPUT ;
    USE SIGNAL ;
    ANTENNAGATEAREA 0.213000 ;
    PORT
      LAYER met2 ;
        RECT 448.590 0.000 448.870 4.000 ;
    END
  END u0b_i[22]
  PIN u0b_i[23]
    DIRECTION INPUT ;
    USE SIGNAL ;
    ANTENNAGATEAREA 0.213000 ;
    PORT
      LAYER met2 ;
        RECT 465.150 0.000 465.430 4.000 ;
    END
  END u0b_i[23]
  PIN u0b_i[24]
    DIRECTION INPUT ;
    USE SIGNAL ;
    ANTENNAGATEAREA 0.213000 ;
    PORT
      LAYER met2 ;
        RECT 481.710 0.000 481.990 4.000 ;
    END
  END u0b_i[24]
  PIN u0b_i[25]
    DIRECTION INPUT ;
    USE SIGNAL ;
    ANTENNAGATEAREA 0.213000 ;
    PORT
      LAYER met2 ;
        RECT 498.270 0.000 498.550 4.000 ;
    END
  END u0b_i[25]
  PIN u0b_i[26]
    DIRECTION INPUT ;
    USE SIGNAL ;
    ANTENNAGATEAREA 0.213000 ;
    PORT
      LAYER met2 ;
        RECT 514.830 0.000 515.110 4.000 ;
    END
  END u0b_i[26]
  PIN u0b_i[27]
    DIRECTION INPUT ;
    USE SIGNAL ;
    ANTENNAGATEAREA 0.159000 ;
    PORT
      LAYER met2 ;
        RECT 531.390 0.000 531.670 4.000 ;
    END
  END u0b_i[27]
  PIN u0b_i[28]
    DIRECTION INPUT ;
    USE SIGNAL ;
    ANTENNAGATEAREA 0.213000 ;
    PORT
      LAYER met2 ;
        RECT 547.950 0.000 548.230 4.000 ;
    END
  END u0b_i[28]
  PIN u0b_i[29]
    DIRECTION INPUT ;
    USE SIGNAL ;
    ANTENNAGATEAREA 0.213000 ;
    PORT
      LAYER met2 ;
        RECT 564.510 0.000 564.790 4.000 ;
    END
  END u0b_i[29]
  PIN u0b_i[2]
    DIRECTION INPUT ;
    USE SIGNAL ;
    ANTENNAGATEAREA 0.247500 ;
    PORT
      LAYER met2 ;
        RECT 115.550 0.000 115.830 4.000 ;
    END
  END u0b_i[2]
  PIN u0b_i[30]
    DIRECTION INPUT ;
    USE SIGNAL ;
    ANTENNAGATEAREA 0.213000 ;
    PORT
      LAYER met2 ;
        RECT 581.070 0.000 581.350 4.000 ;
    END
  END u0b_i[30]
  PIN u0b_i[31]
    DIRECTION INPUT ;
    USE SIGNAL ;
    ANTENNAGATEAREA 0.213000 ;
    PORT
      LAYER met2 ;
        RECT 597.630 0.000 597.910 4.000 ;
    END
  END u0b_i[31]
  PIN u0b_i[3]
    DIRECTION INPUT ;
    USE SIGNAL ;
    ANTENNAGATEAREA 0.247500 ;
    PORT
      LAYER met2 ;
        RECT 133.030 0.000 133.310 4.000 ;
    END
  END u0b_i[3]
  PIN u0b_i[4]
    DIRECTION INPUT ;
    USE SIGNAL ;
    ANTENNAGATEAREA 0.247500 ;
    PORT
      LAYER met2 ;
        RECT 150.510 0.000 150.790 4.000 ;
    END
  END u0b_i[4]
  PIN u0b_i[5]
    DIRECTION INPUT ;
    USE SIGNAL ;
    ANTENNAGATEAREA 0.247500 ;
    PORT
      LAYER met2 ;
        RECT 167.070 0.000 167.350 4.000 ;
    END
  END u0b_i[5]
  PIN u0b_i[6]
    DIRECTION INPUT ;
    USE SIGNAL ;
    ANTENNAGATEAREA 0.247500 ;
    PORT
      LAYER met2 ;
        RECT 183.630 0.000 183.910 4.000 ;
    END
  END u0b_i[6]
  PIN u0b_i[7]
    DIRECTION INPUT ;
    USE SIGNAL ;
    ANTENNAGATEAREA 0.247500 ;
    PORT
      LAYER met2 ;
        RECT 200.190 0.000 200.470 4.000 ;
    END
  END u0b_i[7]
  PIN u0b_i[8]
    DIRECTION INPUT ;
    USE SIGNAL ;
    ANTENNAGATEAREA 0.247500 ;
    PORT
      LAYER met2 ;
        RECT 216.750 0.000 217.030 4.000 ;
    END
  END u0b_i[8]
  PIN u0b_i[9]
    DIRECTION INPUT ;
    USE SIGNAL ;
    ANTENNAGATEAREA 0.247500 ;
    PORT
      LAYER met2 ;
        RECT 233.310 0.000 233.590 4.000 ;
    END
  END u0b_i[9]
  PIN u0c_i[0]
    DIRECTION INPUT ;
    USE SIGNAL ;
    ANTENNAGATEAREA 0.426000 ;
    PORT
      LAYER met2 ;
        RECT 81.510 0.000 81.790 4.000 ;
    END
  END u0c_i[0]
  PIN u0c_i[10]
    DIRECTION INPUT ;
    USE SIGNAL ;
    ANTENNAGATEAREA 0.247500 ;
    PORT
      LAYER met2 ;
        RECT 250.790 0.000 251.070 4.000 ;
    END
  END u0c_i[10]
  PIN u0c_i[11]
    DIRECTION INPUT ;
    USE SIGNAL ;
    ANTENNAGATEAREA 0.247500 ;
    PORT
      LAYER met2 ;
        RECT 267.350 0.000 267.630 4.000 ;
    END
  END u0c_i[11]
  PIN u0c_i[12]
    DIRECTION INPUT ;
    USE SIGNAL ;
    ANTENNAGATEAREA 0.247500 ;
    PORT
      LAYER met2 ;
        RECT 283.910 0.000 284.190 4.000 ;
    END
  END u0c_i[12]
  PIN u0c_i[13]
    DIRECTION INPUT ;
    USE SIGNAL ;
    ANTENNAGATEAREA 0.213000 ;
    PORT
      LAYER met2 ;
        RECT 300.470 0.000 300.750 4.000 ;
    END
  END u0c_i[13]
  PIN u0c_i[14]
    DIRECTION INPUT ;
    USE SIGNAL ;
    ANTENNAGATEAREA 0.213000 ;
    PORT
      LAYER met2 ;
        RECT 317.030 0.000 317.310 4.000 ;
    END
  END u0c_i[14]
  PIN u0c_i[15]
    DIRECTION INPUT ;
    USE SIGNAL ;
    ANTENNAGATEAREA 0.213000 ;
    PORT
      LAYER met2 ;
        RECT 333.590 0.000 333.870 4.000 ;
    END
  END u0c_i[15]
  PIN u0c_i[16]
    DIRECTION INPUT ;
    USE SIGNAL ;
    ANTENNAGATEAREA 0.213000 ;
    PORT
      LAYER met2 ;
        RECT 350.150 0.000 350.430 4.000 ;
    END
  END u0c_i[16]
  PIN u0c_i[17]
    DIRECTION INPUT ;
    USE SIGNAL ;
    ANTENNAGATEAREA 0.213000 ;
    PORT
      LAYER met2 ;
        RECT 366.710 0.000 366.990 4.000 ;
    END
  END u0c_i[17]
  PIN u0c_i[18]
    DIRECTION INPUT ;
    USE SIGNAL ;
    ANTENNAGATEAREA 0.213000 ;
    PORT
      LAYER met2 ;
        RECT 383.270 0.000 383.550 4.000 ;
    END
  END u0c_i[18]
  PIN u0c_i[19]
    DIRECTION INPUT ;
    USE SIGNAL ;
    ANTENNAGATEAREA 0.213000 ;
    PORT
      LAYER met2 ;
        RECT 399.830 0.000 400.110 4.000 ;
    END
  END u0c_i[19]
  PIN u0c_i[1]
    DIRECTION INPUT ;
    USE SIGNAL ;
    ANTENNAGATEAREA 0.426000 ;
    PORT
      LAYER met2 ;
        RECT 98.990 0.000 99.270 4.000 ;
    END
  END u0c_i[1]
  PIN u0c_i[20]
    DIRECTION INPUT ;
    USE SIGNAL ;
    ANTENNAGATEAREA 0.213000 ;
    PORT
      LAYER met2 ;
        RECT 416.390 0.000 416.670 4.000 ;
    END
  END u0c_i[20]
  PIN u0c_i[21]
    DIRECTION INPUT ;
    USE SIGNAL ;
    ANTENNAGATEAREA 0.213000 ;
    PORT
      LAYER met2 ;
        RECT 432.950 0.000 433.230 4.000 ;
    END
  END u0c_i[21]
  PIN u0c_i[22]
    DIRECTION INPUT ;
    USE SIGNAL ;
    ANTENNAGATEAREA 0.159000 ;
    PORT
      LAYER met2 ;
        RECT 449.510 0.000 449.790 4.000 ;
    END
  END u0c_i[22]
  PIN u0c_i[23]
    DIRECTION INPUT ;
    USE SIGNAL ;
    ANTENNAGATEAREA 0.159000 ;
    PORT
      LAYER met2 ;
        RECT 466.070 0.000 466.350 4.000 ;
    END
  END u0c_i[23]
  PIN u0c_i[24]
    DIRECTION INPUT ;
    USE SIGNAL ;
    ANTENNAGATEAREA 0.159000 ;
    PORT
      LAYER met2 ;
        RECT 482.630 0.000 482.910 4.000 ;
    END
  END u0c_i[24]
  PIN u0c_i[25]
    DIRECTION INPUT ;
    USE SIGNAL ;
    ANTENNAGATEAREA 0.159000 ;
    PORT
      LAYER met2 ;
        RECT 499.190 0.000 499.470 4.000 ;
    END
  END u0c_i[25]
  PIN u0c_i[26]
    DIRECTION INPUT ;
    USE SIGNAL ;
    ANTENNAGATEAREA 0.213000 ;
    PORT
      LAYER met2 ;
        RECT 515.750 0.000 516.030 4.000 ;
    END
  END u0c_i[26]
  PIN u0c_i[27]
    DIRECTION INPUT ;
    USE SIGNAL ;
    ANTENNAGATEAREA 0.213000 ;
    PORT
      LAYER met2 ;
        RECT 532.310 0.000 532.590 4.000 ;
    END
  END u0c_i[27]
  PIN u0c_i[28]
    DIRECTION INPUT ;
    USE SIGNAL ;
    ANTENNAGATEAREA 0.213000 ;
    PORT
      LAYER met2 ;
        RECT 548.870 0.000 549.150 4.000 ;
    END
  END u0c_i[28]
  PIN u0c_i[29]
    DIRECTION INPUT ;
    USE SIGNAL ;
    ANTENNAGATEAREA 0.159000 ;
    PORT
      LAYER met2 ;
        RECT 565.430 0.000 565.710 4.000 ;
    END
  END u0c_i[29]
  PIN u0c_i[2]
    DIRECTION INPUT ;
    USE SIGNAL ;
    ANTENNAGATEAREA 0.426000 ;
    PORT
      LAYER met2 ;
        RECT 116.470 0.000 116.750 4.000 ;
    END
  END u0c_i[2]
  PIN u0c_i[30]
    DIRECTION INPUT ;
    USE SIGNAL ;
    ANTENNAGATEAREA 0.213000 ;
    PORT
      LAYER met2 ;
        RECT 581.990 0.000 582.270 4.000 ;
    END
  END u0c_i[30]
  PIN u0c_i[31]
    DIRECTION INPUT ;
    USE SIGNAL ;
    ANTENNAGATEAREA 0.213000 ;
    PORT
      LAYER met2 ;
        RECT 598.550 0.000 598.830 4.000 ;
    END
  END u0c_i[31]
  PIN u0c_i[3]
    DIRECTION INPUT ;
    USE SIGNAL ;
    ANTENNAGATEAREA 0.247500 ;
    PORT
      LAYER met2 ;
        RECT 133.950 0.000 134.230 4.000 ;
    END
  END u0c_i[3]
  PIN u0c_i[4]
    DIRECTION INPUT ;
    USE SIGNAL ;
    ANTENNAGATEAREA 0.247500 ;
    PORT
      LAYER met2 ;
        RECT 151.430 0.000 151.710 4.000 ;
    END
  END u0c_i[4]
  PIN u0c_i[5]
    DIRECTION INPUT ;
    USE SIGNAL ;
    ANTENNAGATEAREA 0.247500 ;
    PORT
      LAYER met2 ;
        RECT 167.990 0.000 168.270 4.000 ;
    END
  END u0c_i[5]
  PIN u0c_i[6]
    DIRECTION INPUT ;
    USE SIGNAL ;
    ANTENNAGATEAREA 0.247500 ;
    PORT
      LAYER met2 ;
        RECT 184.550 0.000 184.830 4.000 ;
    END
  END u0c_i[6]
  PIN u0c_i[7]
    DIRECTION INPUT ;
    USE SIGNAL ;
    ANTENNAGATEAREA 0.247500 ;
    PORT
      LAYER met2 ;
        RECT 201.110 0.000 201.390 4.000 ;
    END
  END u0c_i[7]
  PIN u0c_i[8]
    DIRECTION INPUT ;
    USE SIGNAL ;
    ANTENNAGATEAREA 0.247500 ;
    PORT
      LAYER met2 ;
        RECT 217.670 0.000 217.950 4.000 ;
    END
  END u0c_i[8]
  PIN u0c_i[9]
    DIRECTION INPUT ;
    USE SIGNAL ;
    ANTENNAGATEAREA 0.247500 ;
    PORT
      LAYER met2 ;
        RECT 234.230 0.000 234.510 4.000 ;
    END
  END u0c_i[9]
  PIN u0d_i[0]
    DIRECTION INPUT ;
    USE SIGNAL ;
    ANTENNAGATEAREA 0.247500 ;
    PORT
      LAYER met2 ;
        RECT 82.430 0.000 82.710 4.000 ;
    END
  END u0d_i[0]
  PIN u0d_i[10]
    DIRECTION INPUT ;
    USE SIGNAL ;
    ANTENNAGATEAREA 0.247500 ;
    PORT
      LAYER met2 ;
        RECT 251.710 0.000 251.990 4.000 ;
    END
  END u0d_i[10]
  PIN u0d_i[11]
    DIRECTION INPUT ;
    USE SIGNAL ;
    ANTENNAGATEAREA 0.247500 ;
    PORT
      LAYER met2 ;
        RECT 268.270 0.000 268.550 4.000 ;
    END
  END u0d_i[11]
  PIN u0d_i[12]
    DIRECTION INPUT ;
    USE SIGNAL ;
    ANTENNAGATEAREA 0.213000 ;
    PORT
      LAYER met2 ;
        RECT 284.830 0.000 285.110 4.000 ;
    END
  END u0d_i[12]
  PIN u0d_i[13]
    DIRECTION INPUT ;
    USE SIGNAL ;
    ANTENNAGATEAREA 0.213000 ;
    PORT
      LAYER met2 ;
        RECT 301.390 0.000 301.670 4.000 ;
    END
  END u0d_i[13]
  PIN u0d_i[14]
    DIRECTION INPUT ;
    USE SIGNAL ;
    ANTENNAGATEAREA 0.213000 ;
    PORT
      LAYER met2 ;
        RECT 317.950 0.000 318.230 4.000 ;
    END
  END u0d_i[14]
  PIN u0d_i[15]
    DIRECTION INPUT ;
    USE SIGNAL ;
    ANTENNAGATEAREA 0.213000 ;
    PORT
      LAYER met2 ;
        RECT 334.510 0.000 334.790 4.000 ;
    END
  END u0d_i[15]
  PIN u0d_i[16]
    DIRECTION INPUT ;
    USE SIGNAL ;
    ANTENNAGATEAREA 0.213000 ;
    PORT
      LAYER met2 ;
        RECT 351.070 0.000 351.350 4.000 ;
    END
  END u0d_i[16]
  PIN u0d_i[17]
    DIRECTION INPUT ;
    USE SIGNAL ;
    ANTENNAGATEAREA 0.213000 ;
    PORT
      LAYER met2 ;
        RECT 367.630 0.000 367.910 4.000 ;
    END
  END u0d_i[17]
  PIN u0d_i[18]
    DIRECTION INPUT ;
    USE SIGNAL ;
    ANTENNAGATEAREA 0.213000 ;
    PORT
      LAYER met2 ;
        RECT 384.190 0.000 384.470 4.000 ;
    END
  END u0d_i[18]
  PIN u0d_i[19]
    DIRECTION INPUT ;
    USE SIGNAL ;
    ANTENNAGATEAREA 0.213000 ;
    PORT
      LAYER met2 ;
        RECT 400.750 0.000 401.030 4.000 ;
    END
  END u0d_i[19]
  PIN u0d_i[1]
    DIRECTION INPUT ;
    USE SIGNAL ;
    ANTENNAGATEAREA 0.247500 ;
    PORT
      LAYER met2 ;
        RECT 99.910 0.000 100.190 4.000 ;
    END
  END u0d_i[1]
  PIN u0d_i[20]
    DIRECTION INPUT ;
    USE SIGNAL ;
    ANTENNAGATEAREA 0.213000 ;
    PORT
      LAYER met2 ;
        RECT 417.310 0.000 417.590 4.000 ;
    END
  END u0d_i[20]
  PIN u0d_i[21]
    DIRECTION INPUT ;
    USE SIGNAL ;
    ANTENNAGATEAREA 0.159000 ;
    PORT
      LAYER met2 ;
        RECT 433.870 0.000 434.150 4.000 ;
    END
  END u0d_i[21]
  PIN u0d_i[22]
    DIRECTION INPUT ;
    USE SIGNAL ;
    ANTENNAGATEAREA 0.159000 ;
    PORT
      LAYER met2 ;
        RECT 450.430 0.000 450.710 4.000 ;
    END
  END u0d_i[22]
  PIN u0d_i[23]
    DIRECTION INPUT ;
    USE SIGNAL ;
    ANTENNAGATEAREA 0.159000 ;
    PORT
      LAYER met2 ;
        RECT 466.990 0.000 467.270 4.000 ;
    END
  END u0d_i[23]
  PIN u0d_i[24]
    DIRECTION INPUT ;
    USE SIGNAL ;
    ANTENNAGATEAREA 0.213000 ;
    PORT
      LAYER met2 ;
        RECT 483.550 0.000 483.830 4.000 ;
    END
  END u0d_i[24]
  PIN u0d_i[25]
    DIRECTION INPUT ;
    USE SIGNAL ;
    ANTENNAGATEAREA 0.159000 ;
    PORT
      LAYER met2 ;
        RECT 500.110 0.000 500.390 4.000 ;
    END
  END u0d_i[25]
  PIN u0d_i[26]
    DIRECTION INPUT ;
    USE SIGNAL ;
    ANTENNAGATEAREA 0.213000 ;
    PORT
      LAYER met2 ;
        RECT 516.670 0.000 516.950 4.000 ;
    END
  END u0d_i[26]
  PIN u0d_i[27]
    DIRECTION INPUT ;
    USE SIGNAL ;
    ANTENNAGATEAREA 0.213000 ;
    PORT
      LAYER met2 ;
        RECT 533.230 0.000 533.510 4.000 ;
    END
  END u0d_i[27]
  PIN u0d_i[28]
    DIRECTION INPUT ;
    USE SIGNAL ;
    ANTENNAGATEAREA 0.213000 ;
    PORT
      LAYER met2 ;
        RECT 549.790 0.000 550.070 4.000 ;
    END
  END u0d_i[28]
  PIN u0d_i[29]
    DIRECTION INPUT ;
    USE SIGNAL ;
    ANTENNAGATEAREA 0.213000 ;
    PORT
      LAYER met2 ;
        RECT 566.350 0.000 566.630 4.000 ;
    END
  END u0d_i[29]
  PIN u0d_i[2]
    DIRECTION INPUT ;
    USE SIGNAL ;
    ANTENNAGATEAREA 0.247500 ;
    PORT
      LAYER met2 ;
        RECT 117.390 0.000 117.670 4.000 ;
    END
  END u0d_i[2]
  PIN u0d_i[30]
    DIRECTION INPUT ;
    USE SIGNAL ;
    ANTENNAGATEAREA 0.213000 ;
    PORT
      LAYER met2 ;
        RECT 582.910 0.000 583.190 4.000 ;
    END
  END u0d_i[30]
  PIN u0d_i[31]
    DIRECTION INPUT ;
    USE SIGNAL ;
    ANTENNAGATEAREA 0.126000 ;
    PORT
      LAYER met2 ;
        RECT 599.470 0.000 599.750 4.000 ;
    END
  END u0d_i[31]
  PIN u0d_i[3]
    DIRECTION INPUT ;
    USE SIGNAL ;
    ANTENNAGATEAREA 0.247500 ;
    PORT
      LAYER met2 ;
        RECT 134.870 0.000 135.150 4.000 ;
    END
  END u0d_i[3]
  PIN u0d_i[4]
    DIRECTION INPUT ;
    USE SIGNAL ;
    ANTENNAGATEAREA 0.247500 ;
    PORT
      LAYER met2 ;
        RECT 152.350 0.000 152.630 4.000 ;
    END
  END u0d_i[4]
  PIN u0d_i[5]
    DIRECTION INPUT ;
    USE SIGNAL ;
    ANTENNAGATEAREA 0.247500 ;
    PORT
      LAYER met2 ;
        RECT 168.910 0.000 169.190 4.000 ;
    END
  END u0d_i[5]
  PIN u0d_i[6]
    DIRECTION INPUT ;
    USE SIGNAL ;
    ANTENNAGATEAREA 0.247500 ;
    PORT
      LAYER met2 ;
        RECT 185.470 0.000 185.750 4.000 ;
    END
  END u0d_i[6]
  PIN u0d_i[7]
    DIRECTION INPUT ;
    USE SIGNAL ;
    ANTENNAGATEAREA 0.247500 ;
    PORT
      LAYER met2 ;
        RECT 202.030 0.000 202.310 4.000 ;
    END
  END u0d_i[7]
  PIN u0d_i[8]
    DIRECTION INPUT ;
    USE SIGNAL ;
    ANTENNAGATEAREA 0.213000 ;
    PORT
      LAYER met2 ;
        RECT 218.590 0.000 218.870 4.000 ;
    END
  END u0d_i[8]
  PIN u0d_i[9]
    DIRECTION INPUT ;
    USE SIGNAL ;
    ANTENNAGATEAREA 0.247500 ;
    PORT
      LAYER met2 ;
        RECT 235.150 0.000 235.430 4.000 ;
    END
  END u0d_i[9]
  PIN u0e_i[0]
    DIRECTION INPUT ;
    USE SIGNAL ;
    ANTENNAGATEAREA 0.247500 ;
    PORT
      LAYER met2 ;
        RECT 83.350 0.000 83.630 4.000 ;
    END
  END u0e_i[0]
  PIN u0e_i[10]
    DIRECTION INPUT ;
    USE SIGNAL ;
    ANTENNAGATEAREA 0.213000 ;
    PORT
      LAYER met2 ;
        RECT 252.630 0.000 252.910 4.000 ;
    END
  END u0e_i[10]
  PIN u0e_i[11]
    DIRECTION INPUT ;
    USE SIGNAL ;
    ANTENNAGATEAREA 0.213000 ;
    PORT
      LAYER met2 ;
        RECT 269.190 0.000 269.470 4.000 ;
    END
  END u0e_i[11]
  PIN u0e_i[12]
    DIRECTION INPUT ;
    USE SIGNAL ;
    ANTENNAGATEAREA 0.213000 ;
    PORT
      LAYER met2 ;
        RECT 285.750 0.000 286.030 4.000 ;
    END
  END u0e_i[12]
  PIN u0e_i[13]
    DIRECTION INPUT ;
    USE SIGNAL ;
    ANTENNAGATEAREA 0.213000 ;
    PORT
      LAYER met2 ;
        RECT 302.310 0.000 302.590 4.000 ;
    END
  END u0e_i[13]
  PIN u0e_i[14]
    DIRECTION INPUT ;
    USE SIGNAL ;
    ANTENNAGATEAREA 0.213000 ;
    PORT
      LAYER met2 ;
        RECT 318.870 0.000 319.150 4.000 ;
    END
  END u0e_i[14]
  PIN u0e_i[15]
    DIRECTION INPUT ;
    USE SIGNAL ;
    ANTENNAGATEAREA 0.213000 ;
    PORT
      LAYER met2 ;
        RECT 335.430 0.000 335.710 4.000 ;
    END
  END u0e_i[15]
  PIN u0e_i[16]
    DIRECTION INPUT ;
    USE SIGNAL ;
    ANTENNAGATEAREA 0.159000 ;
    PORT
      LAYER met2 ;
        RECT 351.990 0.000 352.270 4.000 ;
    END
  END u0e_i[16]
  PIN u0e_i[17]
    DIRECTION INPUT ;
    USE SIGNAL ;
    ANTENNAGATEAREA 0.159000 ;
    PORT
      LAYER met2 ;
        RECT 368.550 0.000 368.830 4.000 ;
    END
  END u0e_i[17]
  PIN u0e_i[18]
    DIRECTION INPUT ;
    USE SIGNAL ;
    ANTENNAGATEAREA 0.159000 ;
    PORT
      LAYER met2 ;
        RECT 385.110 0.000 385.390 4.000 ;
    END
  END u0e_i[18]
  PIN u0e_i[19]
    DIRECTION INPUT ;
    USE SIGNAL ;
    ANTENNAGATEAREA 0.159000 ;
    PORT
      LAYER met2 ;
        RECT 401.670 0.000 401.950 4.000 ;
    END
  END u0e_i[19]
  PIN u0e_i[1]
    DIRECTION INPUT ;
    USE SIGNAL ;
    ANTENNAGATEAREA 0.247500 ;
    PORT
      LAYER met2 ;
        RECT 100.830 0.000 101.110 4.000 ;
    END
  END u0e_i[1]
  PIN u0e_i[20]
    DIRECTION INPUT ;
    USE SIGNAL ;
    ANTENNAGATEAREA 0.159000 ;
    PORT
      LAYER met2 ;
        RECT 418.230 0.000 418.510 4.000 ;
    END
  END u0e_i[20]
  PIN u0e_i[21]
    DIRECTION INPUT ;
    USE SIGNAL ;
    ANTENNAGATEAREA 0.159000 ;
    PORT
      LAYER met2 ;
        RECT 434.790 0.000 435.070 4.000 ;
    END
  END u0e_i[21]
  PIN u0e_i[22]
    DIRECTION INPUT ;
    USE SIGNAL ;
    ANTENNAGATEAREA 0.159000 ;
    PORT
      LAYER met2 ;
        RECT 451.350 0.000 451.630 4.000 ;
    END
  END u0e_i[22]
  PIN u0e_i[23]
    DIRECTION INPUT ;
    USE SIGNAL ;
    ANTENNAGATEAREA 0.213000 ;
    PORT
      LAYER met2 ;
        RECT 467.910 0.000 468.190 4.000 ;
    END
  END u0e_i[23]
  PIN u0e_i[24]
    DIRECTION INPUT ;
    USE SIGNAL ;
    ANTENNAGATEAREA 0.213000 ;
    PORT
      LAYER met2 ;
        RECT 484.470 0.000 484.750 4.000 ;
    END
  END u0e_i[24]
  PIN u0e_i[25]
    DIRECTION INPUT ;
    USE SIGNAL ;
    ANTENNAGATEAREA 0.213000 ;
    PORT
      LAYER met2 ;
        RECT 501.030 0.000 501.310 4.000 ;
    END
  END u0e_i[25]
  PIN u0e_i[26]
    DIRECTION INPUT ;
    USE SIGNAL ;
    ANTENNAGATEAREA 0.213000 ;
    PORT
      LAYER met2 ;
        RECT 517.590 0.000 517.870 4.000 ;
    END
  END u0e_i[26]
  PIN u0e_i[27]
    DIRECTION INPUT ;
    USE SIGNAL ;
    ANTENNAGATEAREA 0.213000 ;
    PORT
      LAYER met2 ;
        RECT 534.150 0.000 534.430 4.000 ;
    END
  END u0e_i[27]
  PIN u0e_i[28]
    DIRECTION INPUT ;
    USE SIGNAL ;
    ANTENNAGATEAREA 0.213000 ;
    PORT
      LAYER met2 ;
        RECT 550.710 0.000 550.990 4.000 ;
    END
  END u0e_i[28]
  PIN u0e_i[29]
    DIRECTION INPUT ;
    USE SIGNAL ;
    ANTENNAGATEAREA 0.213000 ;
    PORT
      LAYER met2 ;
        RECT 567.270 0.000 567.550 4.000 ;
    END
  END u0e_i[29]
  PIN u0e_i[2]
    DIRECTION INPUT ;
    USE SIGNAL ;
    ANTENNAGATEAREA 0.247500 ;
    PORT
      LAYER met2 ;
        RECT 118.310 0.000 118.590 4.000 ;
    END
  END u0e_i[2]
  PIN u0e_i[30]
    DIRECTION INPUT ;
    USE SIGNAL ;
    ANTENNAGATEAREA 0.196500 ;
    PORT
      LAYER met2 ;
        RECT 583.830 0.000 584.110 4.000 ;
    END
  END u0e_i[30]
  PIN u0e_i[31]
    DIRECTION INPUT ;
    USE SIGNAL ;
    ANTENNAGATEAREA 0.196500 ;
    PORT
      LAYER met2 ;
        RECT 600.390 0.000 600.670 4.000 ;
    END
  END u0e_i[31]
  PIN u0e_i[3]
    DIRECTION INPUT ;
    USE SIGNAL ;
    ANTENNAGATEAREA 0.247500 ;
    PORT
      LAYER met2 ;
        RECT 135.790 0.000 136.070 4.000 ;
    END
  END u0e_i[3]
  PIN u0e_i[4]
    DIRECTION INPUT ;
    USE SIGNAL ;
    ANTENNAGATEAREA 0.247500 ;
    PORT
      LAYER met2 ;
        RECT 153.270 0.000 153.550 4.000 ;
    END
  END u0e_i[4]
  PIN u0e_i[5]
    DIRECTION INPUT ;
    USE SIGNAL ;
    ANTENNAGATEAREA 0.247500 ;
    PORT
      LAYER met2 ;
        RECT 169.830 0.000 170.110 4.000 ;
    END
  END u0e_i[5]
  PIN u0e_i[6]
    DIRECTION INPUT ;
    USE SIGNAL ;
    ANTENNAGATEAREA 0.213000 ;
    PORT
      LAYER met2 ;
        RECT 186.390 0.000 186.670 4.000 ;
    END
  END u0e_i[6]
  PIN u0e_i[7]
    DIRECTION INPUT ;
    USE SIGNAL ;
    ANTENNAGATEAREA 0.213000 ;
    PORT
      LAYER met2 ;
        RECT 202.950 0.000 203.230 4.000 ;
    END
  END u0e_i[7]
  PIN u0e_i[8]
    DIRECTION INPUT ;
    USE SIGNAL ;
    ANTENNAGATEAREA 0.213000 ;
    PORT
      LAYER met2 ;
        RECT 219.510 0.000 219.790 4.000 ;
    END
  END u0e_i[8]
  PIN u0e_i[9]
    DIRECTION INPUT ;
    USE SIGNAL ;
    ANTENNAGATEAREA 0.213000 ;
    PORT
      LAYER met2 ;
        RECT 236.070 0.000 236.350 4.000 ;
    END
  END u0e_i[9]
  PIN u0f_i[0]
    DIRECTION INPUT ;
    USE SIGNAL ;
    ANTENNAGATEAREA 0.247500 ;
    PORT
      LAYER met2 ;
        RECT 84.270 0.000 84.550 4.000 ;
    END
  END u0f_i[0]
  PIN u0f_i[10]
    DIRECTION INPUT ;
    USE SIGNAL ;
    ANTENNAGATEAREA 0.213000 ;
    PORT
      LAYER met2 ;
        RECT 253.550 0.000 253.830 4.000 ;
    END
  END u0f_i[10]
  PIN u0f_i[11]
    DIRECTION INPUT ;
    USE SIGNAL ;
    ANTENNAGATEAREA 0.213000 ;
    PORT
      LAYER met2 ;
        RECT 270.110 0.000 270.390 4.000 ;
    END
  END u0f_i[11]
  PIN u0f_i[12]
    DIRECTION INPUT ;
    USE SIGNAL ;
    ANTENNAGATEAREA 0.213000 ;
    PORT
      LAYER met2 ;
        RECT 286.670 0.000 286.950 4.000 ;
    END
  END u0f_i[12]
  PIN u0f_i[13]
    DIRECTION INPUT ;
    USE SIGNAL ;
    ANTENNAGATEAREA 0.213000 ;
    PORT
      LAYER met2 ;
        RECT 303.230 0.000 303.510 4.000 ;
    END
  END u0f_i[13]
  PIN u0f_i[14]
    DIRECTION INPUT ;
    USE SIGNAL ;
    ANTENNAGATEAREA 0.213000 ;
    PORT
      LAYER met2 ;
        RECT 319.790 0.000 320.070 4.000 ;
    END
  END u0f_i[14]
  PIN u0f_i[15]
    DIRECTION INPUT ;
    USE SIGNAL ;
    ANTENNAGATEAREA 0.213000 ;
    PORT
      LAYER met2 ;
        RECT 336.350 0.000 336.630 4.000 ;
    END
  END u0f_i[15]
  PIN u0f_i[16]
    DIRECTION INPUT ;
    USE SIGNAL ;
    ANTENNAGATEAREA 0.213000 ;
    PORT
      LAYER met2 ;
        RECT 352.910 0.000 353.190 4.000 ;
    END
  END u0f_i[16]
  PIN u0f_i[17]
    DIRECTION INPUT ;
    USE SIGNAL ;
    ANTENNAGATEAREA 0.213000 ;
    PORT
      LAYER met2 ;
        RECT 369.470 0.000 369.750 4.000 ;
    END
  END u0f_i[17]
  PIN u0f_i[18]
    DIRECTION INPUT ;
    USE SIGNAL ;
    ANTENNAGATEAREA 0.159000 ;
    PORT
      LAYER met2 ;
        RECT 386.030 0.000 386.310 4.000 ;
    END
  END u0f_i[18]
  PIN u0f_i[19]
    DIRECTION INPUT ;
    USE SIGNAL ;
    ANTENNAGATEAREA 0.159000 ;
    PORT
      LAYER met2 ;
        RECT 402.590 0.000 402.870 4.000 ;
    END
  END u0f_i[19]
  PIN u0f_i[1]
    DIRECTION INPUT ;
    USE SIGNAL ;
    ANTENNAGATEAREA 0.247500 ;
    PORT
      LAYER met2 ;
        RECT 101.750 0.000 102.030 4.000 ;
    END
  END u0f_i[1]
  PIN u0f_i[20]
    DIRECTION INPUT ;
    USE SIGNAL ;
    ANTENNAGATEAREA 0.159000 ;
    PORT
      LAYER met2 ;
        RECT 419.150 0.000 419.430 4.000 ;
    END
  END u0f_i[20]
  PIN u0f_i[21]
    DIRECTION INPUT ;
    USE SIGNAL ;
    ANTENNAGATEAREA 0.159000 ;
    PORT
      LAYER met2 ;
        RECT 435.710 0.000 435.990 4.000 ;
    END
  END u0f_i[21]
  PIN u0f_i[22]
    DIRECTION INPUT ;
    USE SIGNAL ;
    ANTENNAGATEAREA 0.159000 ;
    PORT
      LAYER met2 ;
        RECT 452.270 0.000 452.550 4.000 ;
    END
  END u0f_i[22]
  PIN u0f_i[23]
    DIRECTION INPUT ;
    USE SIGNAL ;
    ANTENNAGATEAREA 0.159000 ;
    PORT
      LAYER met2 ;
        RECT 468.830 0.000 469.110 4.000 ;
    END
  END u0f_i[23]
  PIN u0f_i[24]
    DIRECTION INPUT ;
    USE SIGNAL ;
    ANTENNAGATEAREA 0.159000 ;
    PORT
      LAYER met2 ;
        RECT 485.390 0.000 485.670 4.000 ;
    END
  END u0f_i[24]
  PIN u0f_i[25]
    DIRECTION INPUT ;
    USE SIGNAL ;
    ANTENNAGATEAREA 0.213000 ;
    PORT
      LAYER met2 ;
        RECT 501.950 0.000 502.230 4.000 ;
    END
  END u0f_i[25]
  PIN u0f_i[26]
    DIRECTION INPUT ;
    USE SIGNAL ;
    ANTENNAGATEAREA 0.213000 ;
    PORT
      LAYER met2 ;
        RECT 518.510 0.000 518.790 4.000 ;
    END
  END u0f_i[26]
  PIN u0f_i[27]
    DIRECTION INPUT ;
    USE SIGNAL ;
    ANTENNAGATEAREA 0.213000 ;
    PORT
      LAYER met2 ;
        RECT 535.070 0.000 535.350 4.000 ;
    END
  END u0f_i[27]
  PIN u0f_i[28]
    DIRECTION INPUT ;
    USE SIGNAL ;
    ANTENNAGATEAREA 0.213000 ;
    PORT
      LAYER met2 ;
        RECT 551.630 0.000 551.910 4.000 ;
    END
  END u0f_i[28]
  PIN u0f_i[29]
    DIRECTION INPUT ;
    USE SIGNAL ;
    ANTENNAGATEAREA 0.213000 ;
    PORT
      LAYER met2 ;
        RECT 568.190 0.000 568.470 4.000 ;
    END
  END u0f_i[29]
  PIN u0f_i[2]
    DIRECTION INPUT ;
    USE SIGNAL ;
    ANTENNAGATEAREA 0.247500 ;
    PORT
      LAYER met2 ;
        RECT 119.230 0.000 119.510 4.000 ;
    END
  END u0f_i[2]
  PIN u0f_i[30]
    DIRECTION INPUT ;
    USE SIGNAL ;
    ANTENNAGATEAREA 0.213000 ;
    PORT
      LAYER met2 ;
        RECT 584.750 0.000 585.030 4.000 ;
    END
  END u0f_i[30]
  PIN u0f_i[31]
    DIRECTION INPUT ;
    USE SIGNAL ;
    ANTENNAGATEAREA 0.213000 ;
    PORT
      LAYER met2 ;
        RECT 601.310 0.000 601.590 4.000 ;
    END
  END u0f_i[31]
  PIN u0f_i[3]
    DIRECTION INPUT ;
    USE SIGNAL ;
    ANTENNAGATEAREA 0.247500 ;
    PORT
      LAYER met2 ;
        RECT 136.710 0.000 136.990 4.000 ;
    END
  END u0f_i[3]
  PIN u0f_i[4]
    DIRECTION INPUT ;
    USE SIGNAL ;
    ANTENNAGATEAREA 0.247500 ;
    PORT
      LAYER met2 ;
        RECT 154.190 0.000 154.470 4.000 ;
    END
  END u0f_i[4]
  PIN u0f_i[5]
    DIRECTION INPUT ;
    USE SIGNAL ;
    ANTENNAGATEAREA 0.247500 ;
    PORT
      LAYER met2 ;
        RECT 170.750 0.000 171.030 4.000 ;
    END
  END u0f_i[5]
  PIN u0f_i[6]
    DIRECTION INPUT ;
    USE SIGNAL ;
    ANTENNAGATEAREA 0.213000 ;
    PORT
      LAYER met2 ;
        RECT 187.310 0.000 187.590 4.000 ;
    END
  END u0f_i[6]
  PIN u0f_i[7]
    DIRECTION INPUT ;
    USE SIGNAL ;
    ANTENNAGATEAREA 0.213000 ;
    PORT
      LAYER met2 ;
        RECT 203.870 0.000 204.150 4.000 ;
    END
  END u0f_i[7]
  PIN u0f_i[8]
    DIRECTION INPUT ;
    USE SIGNAL ;
    ANTENNAGATEAREA 0.213000 ;
    PORT
      LAYER met2 ;
        RECT 220.430 0.000 220.710 4.000 ;
    END
  END u0f_i[8]
  PIN u0f_i[9]
    DIRECTION INPUT ;
    USE SIGNAL ;
    ANTENNAGATEAREA 0.213000 ;
    PORT
      LAYER met2 ;
        RECT 236.990 0.000 237.270 4.000 ;
    END
  END u0f_i[9]
  PIN u1a_i[0]
    DIRECTION INPUT ;
    USE SIGNAL ;
    ANTENNAGATEAREA 0.196500 ;
    PORT
      LAYER met2 ;
        RECT 85.190 0.000 85.470 4.000 ;
    END
  END u1a_i[0]
  PIN u1a_i[10]
    DIRECTION INPUT ;
    USE SIGNAL ;
    ANTENNAGATEAREA 0.196500 ;
    PORT
      LAYER met2 ;
        RECT 254.470 0.000 254.750 4.000 ;
    END
  END u1a_i[10]
  PIN u1a_i[11]
    DIRECTION INPUT ;
    USE SIGNAL ;
    ANTENNAGATEAREA 0.196500 ;
    PORT
      LAYER met2 ;
        RECT 271.030 0.000 271.310 4.000 ;
    END
  END u1a_i[11]
  PIN u1a_i[12]
    DIRECTION INPUT ;
    USE SIGNAL ;
    ANTENNAGATEAREA 0.196500 ;
    PORT
      LAYER met2 ;
        RECT 287.590 0.000 287.870 4.000 ;
    END
  END u1a_i[12]
  PIN u1a_i[13]
    DIRECTION INPUT ;
    USE SIGNAL ;
    ANTENNAGATEAREA 0.196500 ;
    PORT
      LAYER met2 ;
        RECT 304.150 0.000 304.430 4.000 ;
    END
  END u1a_i[13]
  PIN u1a_i[14]
    DIRECTION INPUT ;
    USE SIGNAL ;
    ANTENNAGATEAREA 0.196500 ;
    PORT
      LAYER met2 ;
        RECT 320.710 0.000 320.990 4.000 ;
    END
  END u1a_i[14]
  PIN u1a_i[15]
    DIRECTION INPUT ;
    USE SIGNAL ;
    ANTENNAGATEAREA 0.196500 ;
    PORT
      LAYER met2 ;
        RECT 337.270 0.000 337.550 4.000 ;
    END
  END u1a_i[15]
  PIN u1a_i[16]
    DIRECTION INPUT ;
    USE SIGNAL ;
    ANTENNAGATEAREA 0.196500 ;
    PORT
      LAYER met2 ;
        RECT 353.830 0.000 354.110 4.000 ;
    END
  END u1a_i[16]
  PIN u1a_i[17]
    DIRECTION INPUT ;
    USE SIGNAL ;
    ANTENNAGATEAREA 0.196500 ;
    PORT
      LAYER met2 ;
        RECT 370.390 0.000 370.670 4.000 ;
    END
  END u1a_i[17]
  PIN u1a_i[18]
    DIRECTION INPUT ;
    USE SIGNAL ;
    ANTENNAGATEAREA 0.196500 ;
    PORT
      LAYER met2 ;
        RECT 386.950 0.000 387.230 4.000 ;
    END
  END u1a_i[18]
  PIN u1a_i[19]
    DIRECTION INPUT ;
    USE SIGNAL ;
    ANTENNAGATEAREA 0.196500 ;
    PORT
      LAYER met2 ;
        RECT 403.510 0.000 403.790 4.000 ;
    END
  END u1a_i[19]
  PIN u1a_i[1]
    DIRECTION INPUT ;
    USE SIGNAL ;
    ANTENNAGATEAREA 0.196500 ;
    PORT
      LAYER met2 ;
        RECT 102.670 0.000 102.950 4.000 ;
    END
  END u1a_i[1]
  PIN u1a_i[20]
    DIRECTION INPUT ;
    USE SIGNAL ;
    ANTENNAGATEAREA 0.196500 ;
    PORT
      LAYER met2 ;
        RECT 420.070 0.000 420.350 4.000 ;
    END
  END u1a_i[20]
  PIN u1a_i[21]
    DIRECTION INPUT ;
    USE SIGNAL ;
    ANTENNAGATEAREA 0.196500 ;
    PORT
      LAYER met2 ;
        RECT 436.630 0.000 436.910 4.000 ;
    END
  END u1a_i[21]
  PIN u1a_i[22]
    DIRECTION INPUT ;
    USE SIGNAL ;
    ANTENNAGATEAREA 0.196500 ;
    PORT
      LAYER met2 ;
        RECT 453.190 0.000 453.470 4.000 ;
    END
  END u1a_i[22]
  PIN u1a_i[23]
    DIRECTION INPUT ;
    USE SIGNAL ;
    ANTENNAGATEAREA 0.196500 ;
    PORT
      LAYER met2 ;
        RECT 469.750 0.000 470.030 4.000 ;
    END
  END u1a_i[23]
  PIN u1a_i[24]
    DIRECTION INPUT ;
    USE SIGNAL ;
    ANTENNAGATEAREA 0.196500 ;
    PORT
      LAYER met2 ;
        RECT 486.310 0.000 486.590 4.000 ;
    END
  END u1a_i[24]
  PIN u1a_i[25]
    DIRECTION INPUT ;
    USE SIGNAL ;
    ANTENNAGATEAREA 0.196500 ;
    PORT
      LAYER met2 ;
        RECT 502.870 0.000 503.150 4.000 ;
    END
  END u1a_i[25]
  PIN u1a_i[26]
    DIRECTION INPUT ;
    USE SIGNAL ;
    ANTENNAGATEAREA 0.196500 ;
    PORT
      LAYER met2 ;
        RECT 519.430 0.000 519.710 4.000 ;
    END
  END u1a_i[26]
  PIN u1a_i[27]
    DIRECTION INPUT ;
    USE SIGNAL ;
    ANTENNAGATEAREA 0.196500 ;
    PORT
      LAYER met2 ;
        RECT 535.990 0.000 536.270 4.000 ;
    END
  END u1a_i[27]
  PIN u1a_i[28]
    DIRECTION INPUT ;
    USE SIGNAL ;
    ANTENNAGATEAREA 0.196500 ;
    PORT
      LAYER met2 ;
        RECT 552.550 0.000 552.830 4.000 ;
    END
  END u1a_i[28]
  PIN u1a_i[29]
    DIRECTION INPUT ;
    USE SIGNAL ;
    ANTENNAGATEAREA 0.196500 ;
    PORT
      LAYER met2 ;
        RECT 569.110 0.000 569.390 4.000 ;
    END
  END u1a_i[29]
  PIN u1a_i[2]
    DIRECTION INPUT ;
    USE SIGNAL ;
    ANTENNAGATEAREA 0.196500 ;
    PORT
      LAYER met2 ;
        RECT 120.150 0.000 120.430 4.000 ;
    END
  END u1a_i[2]
  PIN u1a_i[30]
    DIRECTION INPUT ;
    USE SIGNAL ;
    ANTENNAGATEAREA 0.196500 ;
    PORT
      LAYER met2 ;
        RECT 585.670 0.000 585.950 4.000 ;
    END
  END u1a_i[30]
  PIN u1a_i[31]
    DIRECTION INPUT ;
    USE SIGNAL ;
    ANTENNAGATEAREA 0.196500 ;
    PORT
      LAYER met2 ;
        RECT 602.230 0.000 602.510 4.000 ;
    END
  END u1a_i[31]
  PIN u1a_i[3]
    DIRECTION INPUT ;
    USE SIGNAL ;
    ANTENNAGATEAREA 0.196500 ;
    PORT
      LAYER met2 ;
        RECT 137.630 0.000 137.910 4.000 ;
    END
  END u1a_i[3]
  PIN u1a_i[4]
    DIRECTION INPUT ;
    USE SIGNAL ;
    ANTENNAGATEAREA 0.196500 ;
    PORT
      LAYER met2 ;
        RECT 155.110 0.000 155.390 4.000 ;
    END
  END u1a_i[4]
  PIN u1a_i[5]
    DIRECTION INPUT ;
    USE SIGNAL ;
    ANTENNAGATEAREA 0.196500 ;
    PORT
      LAYER met2 ;
        RECT 171.670 0.000 171.950 4.000 ;
    END
  END u1a_i[5]
  PIN u1a_i[6]
    DIRECTION INPUT ;
    USE SIGNAL ;
    ANTENNAGATEAREA 0.196500 ;
    PORT
      LAYER met2 ;
        RECT 188.230 0.000 188.510 4.000 ;
    END
  END u1a_i[6]
  PIN u1a_i[7]
    DIRECTION INPUT ;
    USE SIGNAL ;
    ANTENNAGATEAREA 0.196500 ;
    PORT
      LAYER met2 ;
        RECT 204.790 0.000 205.070 4.000 ;
    END
  END u1a_i[7]
  PIN u1a_i[8]
    DIRECTION INPUT ;
    USE SIGNAL ;
    ANTENNAGATEAREA 0.196500 ;
    PORT
      LAYER met2 ;
        RECT 221.350 0.000 221.630 4.000 ;
    END
  END u1a_i[8]
  PIN u1a_i[9]
    DIRECTION INPUT ;
    USE SIGNAL ;
    ANTENNAGATEAREA 0.196500 ;
    PORT
      LAYER met2 ;
        RECT 237.910 0.000 238.190 4.000 ;
    END
  END u1a_i[9]
  PIN u1b_i[0]
    DIRECTION INPUT ;
    USE SIGNAL ;
    ANTENNAGATEAREA 0.196500 ;
    PORT
      LAYER met2 ;
        RECT 86.110 0.000 86.390 4.000 ;
    END
  END u1b_i[0]
  PIN u1b_i[10]
    DIRECTION INPUT ;
    USE SIGNAL ;
    ANTENNAGATEAREA 0.196500 ;
    PORT
      LAYER met2 ;
        RECT 255.390 0.000 255.670 4.000 ;
    END
  END u1b_i[10]
  PIN u1b_i[11]
    DIRECTION INPUT ;
    USE SIGNAL ;
    ANTENNAGATEAREA 0.196500 ;
    PORT
      LAYER met2 ;
        RECT 271.950 0.000 272.230 4.000 ;
    END
  END u1b_i[11]
  PIN u1b_i[12]
    DIRECTION INPUT ;
    USE SIGNAL ;
    ANTENNAGATEAREA 0.196500 ;
    PORT
      LAYER met2 ;
        RECT 288.510 0.000 288.790 4.000 ;
    END
  END u1b_i[12]
  PIN u1b_i[13]
    DIRECTION INPUT ;
    USE SIGNAL ;
    ANTENNAGATEAREA 0.196500 ;
    PORT
      LAYER met2 ;
        RECT 305.070 0.000 305.350 4.000 ;
    END
  END u1b_i[13]
  PIN u1b_i[14]
    DIRECTION INPUT ;
    USE SIGNAL ;
    ANTENNAGATEAREA 0.196500 ;
    PORT
      LAYER met2 ;
        RECT 321.630 0.000 321.910 4.000 ;
    END
  END u1b_i[14]
  PIN u1b_i[15]
    DIRECTION INPUT ;
    USE SIGNAL ;
    ANTENNAGATEAREA 0.196500 ;
    PORT
      LAYER met2 ;
        RECT 338.190 0.000 338.470 4.000 ;
    END
  END u1b_i[15]
  PIN u1b_i[16]
    DIRECTION INPUT ;
    USE SIGNAL ;
    ANTENNAGATEAREA 0.196500 ;
    PORT
      LAYER met2 ;
        RECT 354.750 0.000 355.030 4.000 ;
    END
  END u1b_i[16]
  PIN u1b_i[17]
    DIRECTION INPUT ;
    USE SIGNAL ;
    ANTENNAGATEAREA 0.196500 ;
    PORT
      LAYER met2 ;
        RECT 371.310 0.000 371.590 4.000 ;
    END
  END u1b_i[17]
  PIN u1b_i[18]
    DIRECTION INPUT ;
    USE SIGNAL ;
    ANTENNAGATEAREA 0.196500 ;
    PORT
      LAYER met2 ;
        RECT 387.870 0.000 388.150 4.000 ;
    END
  END u1b_i[18]
  PIN u1b_i[19]
    DIRECTION INPUT ;
    USE SIGNAL ;
    ANTENNAGATEAREA 0.196500 ;
    PORT
      LAYER met2 ;
        RECT 404.430 0.000 404.710 4.000 ;
    END
  END u1b_i[19]
  PIN u1b_i[1]
    DIRECTION INPUT ;
    USE SIGNAL ;
    ANTENNAGATEAREA 0.196500 ;
    PORT
      LAYER met2 ;
        RECT 103.590 0.000 103.870 4.000 ;
    END
  END u1b_i[1]
  PIN u1b_i[20]
    DIRECTION INPUT ;
    USE SIGNAL ;
    ANTENNAGATEAREA 0.196500 ;
    PORT
      LAYER met2 ;
        RECT 420.990 0.000 421.270 4.000 ;
    END
  END u1b_i[20]
  PIN u1b_i[21]
    DIRECTION INPUT ;
    USE SIGNAL ;
    ANTENNAGATEAREA 0.196500 ;
    PORT
      LAYER met2 ;
        RECT 437.550 0.000 437.830 4.000 ;
    END
  END u1b_i[21]
  PIN u1b_i[22]
    DIRECTION INPUT ;
    USE SIGNAL ;
    ANTENNAGATEAREA 0.196500 ;
    PORT
      LAYER met2 ;
        RECT 454.110 0.000 454.390 4.000 ;
    END
  END u1b_i[22]
  PIN u1b_i[23]
    DIRECTION INPUT ;
    USE SIGNAL ;
    ANTENNAGATEAREA 0.196500 ;
    PORT
      LAYER met2 ;
        RECT 470.670 0.000 470.950 4.000 ;
    END
  END u1b_i[23]
  PIN u1b_i[24]
    DIRECTION INPUT ;
    USE SIGNAL ;
    ANTENNAGATEAREA 0.196500 ;
    PORT
      LAYER met2 ;
        RECT 487.230 0.000 487.510 4.000 ;
    END
  END u1b_i[24]
  PIN u1b_i[25]
    DIRECTION INPUT ;
    USE SIGNAL ;
    ANTENNAGATEAREA 0.196500 ;
    PORT
      LAYER met2 ;
        RECT 503.790 0.000 504.070 4.000 ;
    END
  END u1b_i[25]
  PIN u1b_i[26]
    DIRECTION INPUT ;
    USE SIGNAL ;
    ANTENNAGATEAREA 0.196500 ;
    PORT
      LAYER met2 ;
        RECT 520.350 0.000 520.630 4.000 ;
    END
  END u1b_i[26]
  PIN u1b_i[27]
    DIRECTION INPUT ;
    USE SIGNAL ;
    ANTENNAGATEAREA 0.196500 ;
    PORT
      LAYER met2 ;
        RECT 536.910 0.000 537.190 4.000 ;
    END
  END u1b_i[27]
  PIN u1b_i[28]
    DIRECTION INPUT ;
    USE SIGNAL ;
    ANTENNAGATEAREA 0.196500 ;
    PORT
      LAYER met2 ;
        RECT 553.470 0.000 553.750 4.000 ;
    END
  END u1b_i[28]
  PIN u1b_i[29]
    DIRECTION INPUT ;
    USE SIGNAL ;
    ANTENNAGATEAREA 0.196500 ;
    PORT
      LAYER met2 ;
        RECT 570.030 0.000 570.310 4.000 ;
    END
  END u1b_i[29]
  PIN u1b_i[2]
    DIRECTION INPUT ;
    USE SIGNAL ;
    ANTENNAGATEAREA 0.196500 ;
    PORT
      LAYER met2 ;
        RECT 121.070 0.000 121.350 4.000 ;
    END
  END u1b_i[2]
  PIN u1b_i[30]
    DIRECTION INPUT ;
    USE SIGNAL ;
    ANTENNAGATEAREA 0.196500 ;
    PORT
      LAYER met2 ;
        RECT 586.590 0.000 586.870 4.000 ;
    END
  END u1b_i[30]
  PIN u1b_i[31]
    DIRECTION INPUT ;
    USE SIGNAL ;
    ANTENNAGATEAREA 0.196500 ;
    PORT
      LAYER met2 ;
        RECT 603.150 0.000 603.430 4.000 ;
    END
  END u1b_i[31]
  PIN u1b_i[3]
    DIRECTION INPUT ;
    USE SIGNAL ;
    ANTENNAGATEAREA 0.196500 ;
    PORT
      LAYER met2 ;
        RECT 138.550 0.000 138.830 4.000 ;
    END
  END u1b_i[3]
  PIN u1b_i[4]
    DIRECTION INPUT ;
    USE SIGNAL ;
    ANTENNAGATEAREA 0.196500 ;
    PORT
      LAYER met2 ;
        RECT 156.030 0.000 156.310 4.000 ;
    END
  END u1b_i[4]
  PIN u1b_i[5]
    DIRECTION INPUT ;
    USE SIGNAL ;
    ANTENNAGATEAREA 0.196500 ;
    PORT
      LAYER met2 ;
        RECT 172.590 0.000 172.870 4.000 ;
    END
  END u1b_i[5]
  PIN u1b_i[6]
    DIRECTION INPUT ;
    USE SIGNAL ;
    ANTENNAGATEAREA 0.196500 ;
    PORT
      LAYER met2 ;
        RECT 189.150 0.000 189.430 4.000 ;
    END
  END u1b_i[6]
  PIN u1b_i[7]
    DIRECTION INPUT ;
    USE SIGNAL ;
    ANTENNAGATEAREA 0.196500 ;
    PORT
      LAYER met2 ;
        RECT 205.710 0.000 205.990 4.000 ;
    END
  END u1b_i[7]
  PIN u1b_i[8]
    DIRECTION INPUT ;
    USE SIGNAL ;
    ANTENNAGATEAREA 0.196500 ;
    PORT
      LAYER met2 ;
        RECT 222.270 0.000 222.550 4.000 ;
    END
  END u1b_i[8]
  PIN u1b_i[9]
    DIRECTION INPUT ;
    USE SIGNAL ;
    ANTENNAGATEAREA 0.196500 ;
    PORT
      LAYER met2 ;
        RECT 238.830 0.000 239.110 4.000 ;
    END
  END u1b_i[9]
  PIN u1c_i[0]
    DIRECTION INPUT ;
    USE SIGNAL ;
    ANTENNAGATEAREA 0.196500 ;
    PORT
      LAYER met2 ;
        RECT 87.030 0.000 87.310 4.000 ;
    END
  END u1c_i[0]
  PIN u1c_i[10]
    DIRECTION INPUT ;
    USE SIGNAL ;
    ANTENNAGATEAREA 0.196500 ;
    PORT
      LAYER met2 ;
        RECT 256.310 0.000 256.590 4.000 ;
    END
  END u1c_i[10]
  PIN u1c_i[11]
    DIRECTION INPUT ;
    USE SIGNAL ;
    ANTENNAGATEAREA 0.196500 ;
    PORT
      LAYER met2 ;
        RECT 272.870 0.000 273.150 4.000 ;
    END
  END u1c_i[11]
  PIN u1c_i[12]
    DIRECTION INPUT ;
    USE SIGNAL ;
    ANTENNAGATEAREA 0.196500 ;
    PORT
      LAYER met2 ;
        RECT 289.430 0.000 289.710 4.000 ;
    END
  END u1c_i[12]
  PIN u1c_i[13]
    DIRECTION INPUT ;
    USE SIGNAL ;
    ANTENNAGATEAREA 0.196500 ;
    PORT
      LAYER met2 ;
        RECT 305.990 0.000 306.270 4.000 ;
    END
  END u1c_i[13]
  PIN u1c_i[14]
    DIRECTION INPUT ;
    USE SIGNAL ;
    ANTENNAGATEAREA 0.196500 ;
    PORT
      LAYER met2 ;
        RECT 322.550 0.000 322.830 4.000 ;
    END
  END u1c_i[14]
  PIN u1c_i[15]
    DIRECTION INPUT ;
    USE SIGNAL ;
    ANTENNAGATEAREA 0.196500 ;
    PORT
      LAYER met2 ;
        RECT 339.110 0.000 339.390 4.000 ;
    END
  END u1c_i[15]
  PIN u1c_i[16]
    DIRECTION INPUT ;
    USE SIGNAL ;
    ANTENNAGATEAREA 0.196500 ;
    PORT
      LAYER met2 ;
        RECT 355.670 0.000 355.950 4.000 ;
    END
  END u1c_i[16]
  PIN u1c_i[17]
    DIRECTION INPUT ;
    USE SIGNAL ;
    ANTENNAGATEAREA 0.196500 ;
    PORT
      LAYER met2 ;
        RECT 372.230 0.000 372.510 4.000 ;
    END
  END u1c_i[17]
  PIN u1c_i[18]
    DIRECTION INPUT ;
    USE SIGNAL ;
    ANTENNAGATEAREA 0.196500 ;
    PORT
      LAYER met2 ;
        RECT 388.790 0.000 389.070 4.000 ;
    END
  END u1c_i[18]
  PIN u1c_i[19]
    DIRECTION INPUT ;
    USE SIGNAL ;
    ANTENNAGATEAREA 0.196500 ;
    PORT
      LAYER met2 ;
        RECT 405.350 0.000 405.630 4.000 ;
    END
  END u1c_i[19]
  PIN u1c_i[1]
    DIRECTION INPUT ;
    USE SIGNAL ;
    ANTENNAGATEAREA 0.196500 ;
    PORT
      LAYER met2 ;
        RECT 104.510 0.000 104.790 4.000 ;
    END
  END u1c_i[1]
  PIN u1c_i[20]
    DIRECTION INPUT ;
    USE SIGNAL ;
    ANTENNAGATEAREA 0.196500 ;
    PORT
      LAYER met2 ;
        RECT 421.910 0.000 422.190 4.000 ;
    END
  END u1c_i[20]
  PIN u1c_i[21]
    DIRECTION INPUT ;
    USE SIGNAL ;
    ANTENNAGATEAREA 0.196500 ;
    PORT
      LAYER met2 ;
        RECT 438.470 0.000 438.750 4.000 ;
    END
  END u1c_i[21]
  PIN u1c_i[22]
    DIRECTION INPUT ;
    USE SIGNAL ;
    ANTENNAGATEAREA 0.196500 ;
    PORT
      LAYER met2 ;
        RECT 455.030 0.000 455.310 4.000 ;
    END
  END u1c_i[22]
  PIN u1c_i[23]
    DIRECTION INPUT ;
    USE SIGNAL ;
    ANTENNAGATEAREA 0.196500 ;
    PORT
      LAYER met2 ;
        RECT 471.590 0.000 471.870 4.000 ;
    END
  END u1c_i[23]
  PIN u1c_i[24]
    DIRECTION INPUT ;
    USE SIGNAL ;
    ANTENNAGATEAREA 0.196500 ;
    PORT
      LAYER met2 ;
        RECT 488.150 0.000 488.430 4.000 ;
    END
  END u1c_i[24]
  PIN u1c_i[25]
    DIRECTION INPUT ;
    USE SIGNAL ;
    ANTENNAGATEAREA 0.196500 ;
    PORT
      LAYER met2 ;
        RECT 504.710 0.000 504.990 4.000 ;
    END
  END u1c_i[25]
  PIN u1c_i[26]
    DIRECTION INPUT ;
    USE SIGNAL ;
    ANTENNAGATEAREA 0.196500 ;
    PORT
      LAYER met2 ;
        RECT 521.270 0.000 521.550 4.000 ;
    END
  END u1c_i[26]
  PIN u1c_i[27]
    DIRECTION INPUT ;
    USE SIGNAL ;
    ANTENNAGATEAREA 0.196500 ;
    PORT
      LAYER met2 ;
        RECT 537.830 0.000 538.110 4.000 ;
    END
  END u1c_i[27]
  PIN u1c_i[28]
    DIRECTION INPUT ;
    USE SIGNAL ;
    ANTENNAGATEAREA 0.196500 ;
    PORT
      LAYER met2 ;
        RECT 554.390 0.000 554.670 4.000 ;
    END
  END u1c_i[28]
  PIN u1c_i[29]
    DIRECTION INPUT ;
    USE SIGNAL ;
    ANTENNAGATEAREA 0.196500 ;
    PORT
      LAYER met2 ;
        RECT 570.950 0.000 571.230 4.000 ;
    END
  END u1c_i[29]
  PIN u1c_i[2]
    DIRECTION INPUT ;
    USE SIGNAL ;
    ANTENNAGATEAREA 0.196500 ;
    PORT
      LAYER met2 ;
        RECT 121.990 0.000 122.270 4.000 ;
    END
  END u1c_i[2]
  PIN u1c_i[30]
    DIRECTION INPUT ;
    USE SIGNAL ;
    ANTENNAGATEAREA 0.196500 ;
    PORT
      LAYER met2 ;
        RECT 587.510 0.000 587.790 4.000 ;
    END
  END u1c_i[30]
  PIN u1c_i[31]
    DIRECTION INPUT ;
    USE SIGNAL ;
    ANTENNAGATEAREA 0.196500 ;
    PORT
      LAYER met2 ;
        RECT 604.070 0.000 604.350 4.000 ;
    END
  END u1c_i[31]
  PIN u1c_i[3]
    DIRECTION INPUT ;
    USE SIGNAL ;
    ANTENNAGATEAREA 0.196500 ;
    PORT
      LAYER met2 ;
        RECT 139.470 0.000 139.750 4.000 ;
    END
  END u1c_i[3]
  PIN u1c_i[4]
    DIRECTION INPUT ;
    USE SIGNAL ;
    ANTENNAGATEAREA 0.196500 ;
    PORT
      LAYER met2 ;
        RECT 156.950 0.000 157.230 4.000 ;
    END
  END u1c_i[4]
  PIN u1c_i[5]
    DIRECTION INPUT ;
    USE SIGNAL ;
    ANTENNAGATEAREA 0.196500 ;
    PORT
      LAYER met2 ;
        RECT 173.510 0.000 173.790 4.000 ;
    END
  END u1c_i[5]
  PIN u1c_i[6]
    DIRECTION INPUT ;
    USE SIGNAL ;
    ANTENNAGATEAREA 0.196500 ;
    PORT
      LAYER met2 ;
        RECT 190.070 0.000 190.350 4.000 ;
    END
  END u1c_i[6]
  PIN u1c_i[7]
    DIRECTION INPUT ;
    USE SIGNAL ;
    ANTENNAGATEAREA 0.196500 ;
    PORT
      LAYER met2 ;
        RECT 206.630 0.000 206.910 4.000 ;
    END
  END u1c_i[7]
  PIN u1c_i[8]
    DIRECTION INPUT ;
    USE SIGNAL ;
    ANTENNAGATEAREA 0.196500 ;
    PORT
      LAYER met2 ;
        RECT 223.190 0.000 223.470 4.000 ;
    END
  END u1c_i[8]
  PIN u1c_i[9]
    DIRECTION INPUT ;
    USE SIGNAL ;
    ANTENNAGATEAREA 0.196500 ;
    PORT
      LAYER met2 ;
        RECT 239.750 0.000 240.030 4.000 ;
    END
  END u1c_i[9]
  PIN u1d_i[0]
    DIRECTION INPUT ;
    USE SIGNAL ;
    ANTENNAGATEAREA 0.196500 ;
    PORT
      LAYER met2 ;
        RECT 87.950 0.000 88.230 4.000 ;
    END
  END u1d_i[0]
  PIN u1d_i[10]
    DIRECTION INPUT ;
    USE SIGNAL ;
    ANTENNAGATEAREA 0.196500 ;
    PORT
      LAYER met2 ;
        RECT 257.230 0.000 257.510 4.000 ;
    END
  END u1d_i[10]
  PIN u1d_i[11]
    DIRECTION INPUT ;
    USE SIGNAL ;
    ANTENNAGATEAREA 0.196500 ;
    PORT
      LAYER met2 ;
        RECT 273.790 0.000 274.070 4.000 ;
    END
  END u1d_i[11]
  PIN u1d_i[12]
    DIRECTION INPUT ;
    USE SIGNAL ;
    ANTENNAGATEAREA 0.196500 ;
    PORT
      LAYER met2 ;
        RECT 290.350 0.000 290.630 4.000 ;
    END
  END u1d_i[12]
  PIN u1d_i[13]
    DIRECTION INPUT ;
    USE SIGNAL ;
    ANTENNAGATEAREA 0.196500 ;
    PORT
      LAYER met2 ;
        RECT 306.910 0.000 307.190 4.000 ;
    END
  END u1d_i[13]
  PIN u1d_i[14]
    DIRECTION INPUT ;
    USE SIGNAL ;
    ANTENNAGATEAREA 0.196500 ;
    PORT
      LAYER met2 ;
        RECT 323.470 0.000 323.750 4.000 ;
    END
  END u1d_i[14]
  PIN u1d_i[15]
    DIRECTION INPUT ;
    USE SIGNAL ;
    ANTENNAGATEAREA 0.196500 ;
    PORT
      LAYER met2 ;
        RECT 340.030 0.000 340.310 4.000 ;
    END
  END u1d_i[15]
  PIN u1d_i[16]
    DIRECTION INPUT ;
    USE SIGNAL ;
    ANTENNAGATEAREA 0.196500 ;
    PORT
      LAYER met2 ;
        RECT 356.590 0.000 356.870 4.000 ;
    END
  END u1d_i[16]
  PIN u1d_i[17]
    DIRECTION INPUT ;
    USE SIGNAL ;
    ANTENNAGATEAREA 0.196500 ;
    PORT
      LAYER met2 ;
        RECT 373.150 0.000 373.430 4.000 ;
    END
  END u1d_i[17]
  PIN u1d_i[18]
    DIRECTION INPUT ;
    USE SIGNAL ;
    ANTENNAGATEAREA 0.196500 ;
    PORT
      LAYER met2 ;
        RECT 389.710 0.000 389.990 4.000 ;
    END
  END u1d_i[18]
  PIN u1d_i[19]
    DIRECTION INPUT ;
    USE SIGNAL ;
    ANTENNAGATEAREA 0.196500 ;
    PORT
      LAYER met2 ;
        RECT 406.270 0.000 406.550 4.000 ;
    END
  END u1d_i[19]
  PIN u1d_i[1]
    DIRECTION INPUT ;
    USE SIGNAL ;
    ANTENNAGATEAREA 0.196500 ;
    PORT
      LAYER met2 ;
        RECT 105.430 0.000 105.710 4.000 ;
    END
  END u1d_i[1]
  PIN u1d_i[20]
    DIRECTION INPUT ;
    USE SIGNAL ;
    ANTENNAGATEAREA 0.196500 ;
    PORT
      LAYER met2 ;
        RECT 422.830 0.000 423.110 4.000 ;
    END
  END u1d_i[20]
  PIN u1d_i[21]
    DIRECTION INPUT ;
    USE SIGNAL ;
    ANTENNAGATEAREA 0.196500 ;
    PORT
      LAYER met2 ;
        RECT 439.390 0.000 439.670 4.000 ;
    END
  END u1d_i[21]
  PIN u1d_i[22]
    DIRECTION INPUT ;
    USE SIGNAL ;
    ANTENNAGATEAREA 0.196500 ;
    PORT
      LAYER met2 ;
        RECT 455.950 0.000 456.230 4.000 ;
    END
  END u1d_i[22]
  PIN u1d_i[23]
    DIRECTION INPUT ;
    USE SIGNAL ;
    ANTENNAGATEAREA 0.196500 ;
    PORT
      LAYER met2 ;
        RECT 472.510 0.000 472.790 4.000 ;
    END
  END u1d_i[23]
  PIN u1d_i[24]
    DIRECTION INPUT ;
    USE SIGNAL ;
    ANTENNAGATEAREA 0.196500 ;
    PORT
      LAYER met2 ;
        RECT 489.070 0.000 489.350 4.000 ;
    END
  END u1d_i[24]
  PIN u1d_i[25]
    DIRECTION INPUT ;
    USE SIGNAL ;
    ANTENNAGATEAREA 0.196500 ;
    PORT
      LAYER met2 ;
        RECT 505.630 0.000 505.910 4.000 ;
    END
  END u1d_i[25]
  PIN u1d_i[26]
    DIRECTION INPUT ;
    USE SIGNAL ;
    ANTENNAGATEAREA 0.196500 ;
    PORT
      LAYER met2 ;
        RECT 522.190 0.000 522.470 4.000 ;
    END
  END u1d_i[26]
  PIN u1d_i[27]
    DIRECTION INPUT ;
    USE SIGNAL ;
    ANTENNAGATEAREA 0.196500 ;
    PORT
      LAYER met2 ;
        RECT 538.750 0.000 539.030 4.000 ;
    END
  END u1d_i[27]
  PIN u1d_i[28]
    DIRECTION INPUT ;
    USE SIGNAL ;
    ANTENNAGATEAREA 0.196500 ;
    PORT
      LAYER met2 ;
        RECT 555.310 0.000 555.590 4.000 ;
    END
  END u1d_i[28]
  PIN u1d_i[29]
    DIRECTION INPUT ;
    USE SIGNAL ;
    ANTENNAGATEAREA 0.196500 ;
    PORT
      LAYER met2 ;
        RECT 571.870 0.000 572.150 4.000 ;
    END
  END u1d_i[29]
  PIN u1d_i[2]
    DIRECTION INPUT ;
    USE SIGNAL ;
    ANTENNAGATEAREA 0.196500 ;
    PORT
      LAYER met2 ;
        RECT 122.910 0.000 123.190 4.000 ;
    END
  END u1d_i[2]
  PIN u1d_i[30]
    DIRECTION INPUT ;
    USE SIGNAL ;
    ANTENNAGATEAREA 0.196500 ;
    PORT
      LAYER met2 ;
        RECT 588.430 0.000 588.710 4.000 ;
    END
  END u1d_i[30]
  PIN u1d_i[31]
    DIRECTION INPUT ;
    USE SIGNAL ;
    ANTENNAGATEAREA 0.196500 ;
    PORT
      LAYER met2 ;
        RECT 604.990 0.000 605.270 4.000 ;
    END
  END u1d_i[31]
  PIN u1d_i[3]
    DIRECTION INPUT ;
    USE SIGNAL ;
    ANTENNAGATEAREA 0.196500 ;
    PORT
      LAYER met2 ;
        RECT 140.390 0.000 140.670 4.000 ;
    END
  END u1d_i[3]
  PIN u1d_i[4]
    DIRECTION INPUT ;
    USE SIGNAL ;
    ANTENNAGATEAREA 0.196500 ;
    PORT
      LAYER met2 ;
        RECT 157.870 0.000 158.150 4.000 ;
    END
  END u1d_i[4]
  PIN u1d_i[5]
    DIRECTION INPUT ;
    USE SIGNAL ;
    ANTENNAGATEAREA 0.196500 ;
    PORT
      LAYER met2 ;
        RECT 174.430 0.000 174.710 4.000 ;
    END
  END u1d_i[5]
  PIN u1d_i[6]
    DIRECTION INPUT ;
    USE SIGNAL ;
    ANTENNAGATEAREA 0.196500 ;
    PORT
      LAYER met2 ;
        RECT 190.990 0.000 191.270 4.000 ;
    END
  END u1d_i[6]
  PIN u1d_i[7]
    DIRECTION INPUT ;
    USE SIGNAL ;
    ANTENNAGATEAREA 0.196500 ;
    PORT
      LAYER met2 ;
        RECT 207.550 0.000 207.830 4.000 ;
    END
  END u1d_i[7]
  PIN u1d_i[8]
    DIRECTION INPUT ;
    USE SIGNAL ;
    ANTENNAGATEAREA 0.196500 ;
    PORT
      LAYER met2 ;
        RECT 224.110 0.000 224.390 4.000 ;
    END
  END u1d_i[8]
  PIN u1d_i[9]
    DIRECTION INPUT ;
    USE SIGNAL ;
    ANTENNAGATEAREA 0.196500 ;
    PORT
      LAYER met2 ;
        RECT 240.670 0.000 240.950 4.000 ;
    END
  END u1d_i[9]
  PIN u1e_i[0]
    DIRECTION INPUT ;
    USE SIGNAL ;
    ANTENNAGATEAREA 0.196500 ;
    PORT
      LAYER met2 ;
        RECT 88.870 0.000 89.150 4.000 ;
    END
  END u1e_i[0]
  PIN u1e_i[10]
    DIRECTION INPUT ;
    USE SIGNAL ;
    ANTENNAGATEAREA 0.196500 ;
    PORT
      LAYER met2 ;
        RECT 258.150 0.000 258.430 4.000 ;
    END
  END u1e_i[10]
  PIN u1e_i[11]
    DIRECTION INPUT ;
    USE SIGNAL ;
    ANTENNAGATEAREA 0.196500 ;
    PORT
      LAYER met2 ;
        RECT 274.710 0.000 274.990 4.000 ;
    END
  END u1e_i[11]
  PIN u1e_i[12]
    DIRECTION INPUT ;
    USE SIGNAL ;
    ANTENNAGATEAREA 0.196500 ;
    PORT
      LAYER met2 ;
        RECT 291.270 0.000 291.550 4.000 ;
    END
  END u1e_i[12]
  PIN u1e_i[13]
    DIRECTION INPUT ;
    USE SIGNAL ;
    ANTENNAGATEAREA 0.196500 ;
    PORT
      LAYER met2 ;
        RECT 307.830 0.000 308.110 4.000 ;
    END
  END u1e_i[13]
  PIN u1e_i[14]
    DIRECTION INPUT ;
    USE SIGNAL ;
    ANTENNAGATEAREA 0.196500 ;
    PORT
      LAYER met2 ;
        RECT 324.390 0.000 324.670 4.000 ;
    END
  END u1e_i[14]
  PIN u1e_i[15]
    DIRECTION INPUT ;
    USE SIGNAL ;
    ANTENNAGATEAREA 0.196500 ;
    PORT
      LAYER met2 ;
        RECT 340.950 0.000 341.230 4.000 ;
    END
  END u1e_i[15]
  PIN u1e_i[16]
    DIRECTION INPUT ;
    USE SIGNAL ;
    ANTENNAGATEAREA 0.196500 ;
    PORT
      LAYER met2 ;
        RECT 357.510 0.000 357.790 4.000 ;
    END
  END u1e_i[16]
  PIN u1e_i[17]
    DIRECTION INPUT ;
    USE SIGNAL ;
    ANTENNAGATEAREA 0.196500 ;
    PORT
      LAYER met2 ;
        RECT 374.070 0.000 374.350 4.000 ;
    END
  END u1e_i[17]
  PIN u1e_i[18]
    DIRECTION INPUT ;
    USE SIGNAL ;
    ANTENNAGATEAREA 0.196500 ;
    PORT
      LAYER met2 ;
        RECT 390.630 0.000 390.910 4.000 ;
    END
  END u1e_i[18]
  PIN u1e_i[19]
    DIRECTION INPUT ;
    USE SIGNAL ;
    ANTENNAGATEAREA 0.196500 ;
    PORT
      LAYER met2 ;
        RECT 407.190 0.000 407.470 4.000 ;
    END
  END u1e_i[19]
  PIN u1e_i[1]
    DIRECTION INPUT ;
    USE SIGNAL ;
    ANTENNAGATEAREA 0.196500 ;
    PORT
      LAYER met2 ;
        RECT 106.350 0.000 106.630 4.000 ;
    END
  END u1e_i[1]
  PIN u1e_i[20]
    DIRECTION INPUT ;
    USE SIGNAL ;
    ANTENNAGATEAREA 0.196500 ;
    PORT
      LAYER met2 ;
        RECT 423.750 0.000 424.030 4.000 ;
    END
  END u1e_i[20]
  PIN u1e_i[21]
    DIRECTION INPUT ;
    USE SIGNAL ;
    ANTENNAGATEAREA 0.196500 ;
    PORT
      LAYER met2 ;
        RECT 440.310 0.000 440.590 4.000 ;
    END
  END u1e_i[21]
  PIN u1e_i[22]
    DIRECTION INPUT ;
    USE SIGNAL ;
    ANTENNAGATEAREA 0.196500 ;
    PORT
      LAYER met2 ;
        RECT 456.870 0.000 457.150 4.000 ;
    END
  END u1e_i[22]
  PIN u1e_i[23]
    DIRECTION INPUT ;
    USE SIGNAL ;
    ANTENNAGATEAREA 0.196500 ;
    PORT
      LAYER met2 ;
        RECT 473.430 0.000 473.710 4.000 ;
    END
  END u1e_i[23]
  PIN u1e_i[24]
    DIRECTION INPUT ;
    USE SIGNAL ;
    ANTENNAGATEAREA 0.196500 ;
    PORT
      LAYER met2 ;
        RECT 489.990 0.000 490.270 4.000 ;
    END
  END u1e_i[24]
  PIN u1e_i[25]
    DIRECTION INPUT ;
    USE SIGNAL ;
    ANTENNAGATEAREA 0.196500 ;
    PORT
      LAYER met2 ;
        RECT 506.550 0.000 506.830 4.000 ;
    END
  END u1e_i[25]
  PIN u1e_i[26]
    DIRECTION INPUT ;
    USE SIGNAL ;
    ANTENNAGATEAREA 0.196500 ;
    PORT
      LAYER met2 ;
        RECT 523.110 0.000 523.390 4.000 ;
    END
  END u1e_i[26]
  PIN u1e_i[27]
    DIRECTION INPUT ;
    USE SIGNAL ;
    ANTENNAGATEAREA 0.196500 ;
    PORT
      LAYER met2 ;
        RECT 539.670 0.000 539.950 4.000 ;
    END
  END u1e_i[27]
  PIN u1e_i[28]
    DIRECTION INPUT ;
    USE SIGNAL ;
    ANTENNAGATEAREA 0.196500 ;
    PORT
      LAYER met2 ;
        RECT 556.230 0.000 556.510 4.000 ;
    END
  END u1e_i[28]
  PIN u1e_i[29]
    DIRECTION INPUT ;
    USE SIGNAL ;
    ANTENNAGATEAREA 0.196500 ;
    PORT
      LAYER met2 ;
        RECT 572.790 0.000 573.070 4.000 ;
    END
  END u1e_i[29]
  PIN u1e_i[2]
    DIRECTION INPUT ;
    USE SIGNAL ;
    ANTENNAGATEAREA 0.196500 ;
    PORT
      LAYER met2 ;
        RECT 123.830 0.000 124.110 4.000 ;
    END
  END u1e_i[2]
  PIN u1e_i[30]
    DIRECTION INPUT ;
    USE SIGNAL ;
    ANTENNAGATEAREA 0.196500 ;
    PORT
      LAYER met2 ;
        RECT 589.350 0.000 589.630 4.000 ;
    END
  END u1e_i[30]
  PIN u1e_i[31]
    DIRECTION INPUT ;
    USE SIGNAL ;
    ANTENNAGATEAREA 0.196500 ;
    PORT
      LAYER met2 ;
        RECT 605.910 0.000 606.190 4.000 ;
    END
  END u1e_i[31]
  PIN u1e_i[3]
    DIRECTION INPUT ;
    USE SIGNAL ;
    ANTENNAGATEAREA 0.196500 ;
    PORT
      LAYER met2 ;
        RECT 141.310 0.000 141.590 4.000 ;
    END
  END u1e_i[3]
  PIN u1e_i[4]
    DIRECTION INPUT ;
    USE SIGNAL ;
    ANTENNAGATEAREA 0.196500 ;
    PORT
      LAYER met2 ;
        RECT 158.790 0.000 159.070 4.000 ;
    END
  END u1e_i[4]
  PIN u1e_i[5]
    DIRECTION INPUT ;
    USE SIGNAL ;
    ANTENNAGATEAREA 0.196500 ;
    PORT
      LAYER met2 ;
        RECT 175.350 0.000 175.630 4.000 ;
    END
  END u1e_i[5]
  PIN u1e_i[6]
    DIRECTION INPUT ;
    USE SIGNAL ;
    ANTENNAGATEAREA 0.196500 ;
    PORT
      LAYER met2 ;
        RECT 191.910 0.000 192.190 4.000 ;
    END
  END u1e_i[6]
  PIN u1e_i[7]
    DIRECTION INPUT ;
    USE SIGNAL ;
    ANTENNAGATEAREA 0.196500 ;
    PORT
      LAYER met2 ;
        RECT 208.470 0.000 208.750 4.000 ;
    END
  END u1e_i[7]
  PIN u1e_i[8]
    DIRECTION INPUT ;
    USE SIGNAL ;
    ANTENNAGATEAREA 0.196500 ;
    PORT
      LAYER met2 ;
        RECT 225.030 0.000 225.310 4.000 ;
    END
  END u1e_i[8]
  PIN u1e_i[9]
    DIRECTION INPUT ;
    USE SIGNAL ;
    ANTENNAGATEAREA 0.196500 ;
    PORT
      LAYER met2 ;
        RECT 241.590 0.000 241.870 4.000 ;
    END
  END u1e_i[9]
  PIN u1f_i[0]
    DIRECTION INPUT ;
    USE SIGNAL ;
    ANTENNAGATEAREA 0.196500 ;
    PORT
      LAYER met2 ;
        RECT 89.790 0.000 90.070 4.000 ;
    END
  END u1f_i[0]
  PIN u1f_i[10]
    DIRECTION INPUT ;
    USE SIGNAL ;
    ANTENNAGATEAREA 0.196500 ;
    PORT
      LAYER met2 ;
        RECT 259.070 0.000 259.350 4.000 ;
    END
  END u1f_i[10]
  PIN u1f_i[11]
    DIRECTION INPUT ;
    USE SIGNAL ;
    ANTENNAGATEAREA 0.196500 ;
    PORT
      LAYER met2 ;
        RECT 275.630 0.000 275.910 4.000 ;
    END
  END u1f_i[11]
  PIN u1f_i[12]
    DIRECTION INPUT ;
    USE SIGNAL ;
    ANTENNAGATEAREA 0.196500 ;
    PORT
      LAYER met2 ;
        RECT 292.190 0.000 292.470 4.000 ;
    END
  END u1f_i[12]
  PIN u1f_i[13]
    DIRECTION INPUT ;
    USE SIGNAL ;
    ANTENNAGATEAREA 0.196500 ;
    PORT
      LAYER met2 ;
        RECT 308.750 0.000 309.030 4.000 ;
    END
  END u1f_i[13]
  PIN u1f_i[14]
    DIRECTION INPUT ;
    USE SIGNAL ;
    ANTENNAGATEAREA 0.196500 ;
    PORT
      LAYER met2 ;
        RECT 325.310 0.000 325.590 4.000 ;
    END
  END u1f_i[14]
  PIN u1f_i[15]
    DIRECTION INPUT ;
    USE SIGNAL ;
    ANTENNAGATEAREA 0.196500 ;
    PORT
      LAYER met2 ;
        RECT 341.870 0.000 342.150 4.000 ;
    END
  END u1f_i[15]
  PIN u1f_i[16]
    DIRECTION INPUT ;
    USE SIGNAL ;
    ANTENNAGATEAREA 0.196500 ;
    PORT
      LAYER met2 ;
        RECT 358.430 0.000 358.710 4.000 ;
    END
  END u1f_i[16]
  PIN u1f_i[17]
    DIRECTION INPUT ;
    USE SIGNAL ;
    ANTENNAGATEAREA 0.196500 ;
    PORT
      LAYER met2 ;
        RECT 374.990 0.000 375.270 4.000 ;
    END
  END u1f_i[17]
  PIN u1f_i[18]
    DIRECTION INPUT ;
    USE SIGNAL ;
    ANTENNAGATEAREA 0.196500 ;
    PORT
      LAYER met2 ;
        RECT 391.550 0.000 391.830 4.000 ;
    END
  END u1f_i[18]
  PIN u1f_i[19]
    DIRECTION INPUT ;
    USE SIGNAL ;
    ANTENNAGATEAREA 0.196500 ;
    PORT
      LAYER met2 ;
        RECT 408.110 0.000 408.390 4.000 ;
    END
  END u1f_i[19]
  PIN u1f_i[1]
    DIRECTION INPUT ;
    USE SIGNAL ;
    ANTENNAGATEAREA 0.196500 ;
    PORT
      LAYER met2 ;
        RECT 107.270 0.000 107.550 4.000 ;
    END
  END u1f_i[1]
  PIN u1f_i[20]
    DIRECTION INPUT ;
    USE SIGNAL ;
    ANTENNAGATEAREA 0.196500 ;
    PORT
      LAYER met2 ;
        RECT 424.670 0.000 424.950 4.000 ;
    END
  END u1f_i[20]
  PIN u1f_i[21]
    DIRECTION INPUT ;
    USE SIGNAL ;
    ANTENNAGATEAREA 0.196500 ;
    PORT
      LAYER met2 ;
        RECT 441.230 0.000 441.510 4.000 ;
    END
  END u1f_i[21]
  PIN u1f_i[22]
    DIRECTION INPUT ;
    USE SIGNAL ;
    ANTENNAGATEAREA 0.196500 ;
    PORT
      LAYER met2 ;
        RECT 457.790 0.000 458.070 4.000 ;
    END
  END u1f_i[22]
  PIN u1f_i[23]
    DIRECTION INPUT ;
    USE SIGNAL ;
    ANTENNAGATEAREA 0.196500 ;
    PORT
      LAYER met2 ;
        RECT 474.350 0.000 474.630 4.000 ;
    END
  END u1f_i[23]
  PIN u1f_i[24]
    DIRECTION INPUT ;
    USE SIGNAL ;
    ANTENNAGATEAREA 0.196500 ;
    PORT
      LAYER met2 ;
        RECT 490.910 0.000 491.190 4.000 ;
    END
  END u1f_i[24]
  PIN u1f_i[25]
    DIRECTION INPUT ;
    USE SIGNAL ;
    ANTENNAGATEAREA 0.196500 ;
    PORT
      LAYER met2 ;
        RECT 507.470 0.000 507.750 4.000 ;
    END
  END u1f_i[25]
  PIN u1f_i[26]
    DIRECTION INPUT ;
    USE SIGNAL ;
    ANTENNAGATEAREA 0.196500 ;
    PORT
      LAYER met2 ;
        RECT 524.030 0.000 524.310 4.000 ;
    END
  END u1f_i[26]
  PIN u1f_i[27]
    DIRECTION INPUT ;
    USE SIGNAL ;
    ANTENNAGATEAREA 0.196500 ;
    PORT
      LAYER met2 ;
        RECT 540.590 0.000 540.870 4.000 ;
    END
  END u1f_i[27]
  PIN u1f_i[28]
    DIRECTION INPUT ;
    USE SIGNAL ;
    ANTENNAGATEAREA 0.196500 ;
    PORT
      LAYER met2 ;
        RECT 557.150 0.000 557.430 4.000 ;
    END
  END u1f_i[28]
  PIN u1f_i[29]
    DIRECTION INPUT ;
    USE SIGNAL ;
    ANTENNAGATEAREA 0.196500 ;
    PORT
      LAYER met2 ;
        RECT 573.710 0.000 573.990 4.000 ;
    END
  END u1f_i[29]
  PIN u1f_i[2]
    DIRECTION INPUT ;
    USE SIGNAL ;
    ANTENNAGATEAREA 0.196500 ;
    PORT
      LAYER met2 ;
        RECT 124.750 0.000 125.030 4.000 ;
    END
  END u1f_i[2]
  PIN u1f_i[30]
    DIRECTION INPUT ;
    USE SIGNAL ;
    ANTENNAGATEAREA 0.196500 ;
    PORT
      LAYER met2 ;
        RECT 590.270 0.000 590.550 4.000 ;
    END
  END u1f_i[30]
  PIN u1f_i[31]
    DIRECTION INPUT ;
    USE SIGNAL ;
    ANTENNAGATEAREA 0.196500 ;
    PORT
      LAYER met2 ;
        RECT 606.830 0.000 607.110 4.000 ;
    END
  END u1f_i[31]
  PIN u1f_i[3]
    DIRECTION INPUT ;
    USE SIGNAL ;
    ANTENNAGATEAREA 0.196500 ;
    PORT
      LAYER met2 ;
        RECT 142.230 0.000 142.510 4.000 ;
    END
  END u1f_i[3]
  PIN u1f_i[4]
    DIRECTION INPUT ;
    USE SIGNAL ;
    ANTENNAGATEAREA 0.196500 ;
    PORT
      LAYER met2 ;
        RECT 159.710 0.000 159.990 4.000 ;
    END
  END u1f_i[4]
  PIN u1f_i[5]
    DIRECTION INPUT ;
    USE SIGNAL ;
    ANTENNAGATEAREA 0.196500 ;
    PORT
      LAYER met2 ;
        RECT 176.270 0.000 176.550 4.000 ;
    END
  END u1f_i[5]
  PIN u1f_i[6]
    DIRECTION INPUT ;
    USE SIGNAL ;
    ANTENNAGATEAREA 0.196500 ;
    PORT
      LAYER met2 ;
        RECT 192.830 0.000 193.110 4.000 ;
    END
  END u1f_i[6]
  PIN u1f_i[7]
    DIRECTION INPUT ;
    USE SIGNAL ;
    ANTENNAGATEAREA 0.196500 ;
    PORT
      LAYER met2 ;
        RECT 209.390 0.000 209.670 4.000 ;
    END
  END u1f_i[7]
  PIN u1f_i[8]
    DIRECTION INPUT ;
    USE SIGNAL ;
    ANTENNAGATEAREA 0.196500 ;
    PORT
      LAYER met2 ;
        RECT 225.950 0.000 226.230 4.000 ;
    END
  END u1f_i[8]
  PIN u1f_i[9]
    DIRECTION INPUT ;
    USE SIGNAL ;
    ANTENNAGATEAREA 0.196500 ;
    PORT
      LAYER met2 ;
        RECT 242.510 0.000 242.790 4.000 ;
    END
  END u1f_i[9]
  PIN u2a_i[0]
    DIRECTION INPUT ;
    USE SIGNAL ;
    ANTENNAGATEAREA 0.196500 ;
    PORT
      LAYER met2 ;
        RECT 90.710 0.000 90.990 4.000 ;
    END
  END u2a_i[0]
  PIN u2a_i[10]
    DIRECTION INPUT ;
    USE SIGNAL ;
    ANTENNAGATEAREA 0.196500 ;
    PORT
      LAYER met2 ;
        RECT 259.990 0.000 260.270 4.000 ;
    END
  END u2a_i[10]
  PIN u2a_i[11]
    DIRECTION INPUT ;
    USE SIGNAL ;
    ANTENNAGATEAREA 0.196500 ;
    PORT
      LAYER met2 ;
        RECT 276.550 0.000 276.830 4.000 ;
    END
  END u2a_i[11]
  PIN u2a_i[12]
    DIRECTION INPUT ;
    USE SIGNAL ;
    ANTENNAGATEAREA 0.196500 ;
    PORT
      LAYER met2 ;
        RECT 293.110 0.000 293.390 4.000 ;
    END
  END u2a_i[12]
  PIN u2a_i[13]
    DIRECTION INPUT ;
    USE SIGNAL ;
    ANTENNAGATEAREA 0.196500 ;
    PORT
      LAYER met2 ;
        RECT 309.670 0.000 309.950 4.000 ;
    END
  END u2a_i[13]
  PIN u2a_i[14]
    DIRECTION INPUT ;
    USE SIGNAL ;
    ANTENNAGATEAREA 0.196500 ;
    PORT
      LAYER met2 ;
        RECT 326.230 0.000 326.510 4.000 ;
    END
  END u2a_i[14]
  PIN u2a_i[15]
    DIRECTION INPUT ;
    USE SIGNAL ;
    ANTENNAGATEAREA 0.196500 ;
    PORT
      LAYER met2 ;
        RECT 342.790 0.000 343.070 4.000 ;
    END
  END u2a_i[15]
  PIN u2a_i[16]
    DIRECTION INPUT ;
    USE SIGNAL ;
    ANTENNAGATEAREA 0.196500 ;
    PORT
      LAYER met2 ;
        RECT 359.350 0.000 359.630 4.000 ;
    END
  END u2a_i[16]
  PIN u2a_i[17]
    DIRECTION INPUT ;
    USE SIGNAL ;
    ANTENNAGATEAREA 0.196500 ;
    PORT
      LAYER met2 ;
        RECT 375.910 0.000 376.190 4.000 ;
    END
  END u2a_i[17]
  PIN u2a_i[18]
    DIRECTION INPUT ;
    USE SIGNAL ;
    ANTENNAGATEAREA 0.196500 ;
    PORT
      LAYER met2 ;
        RECT 392.470 0.000 392.750 4.000 ;
    END
  END u2a_i[18]
  PIN u2a_i[19]
    DIRECTION INPUT ;
    USE SIGNAL ;
    ANTENNAGATEAREA 0.196500 ;
    PORT
      LAYER met2 ;
        RECT 409.030 0.000 409.310 4.000 ;
    END
  END u2a_i[19]
  PIN u2a_i[1]
    DIRECTION INPUT ;
    USE SIGNAL ;
    ANTENNAGATEAREA 0.196500 ;
    PORT
      LAYER met2 ;
        RECT 108.190 0.000 108.470 4.000 ;
    END
  END u2a_i[1]
  PIN u2a_i[20]
    DIRECTION INPUT ;
    USE SIGNAL ;
    ANTENNAGATEAREA 0.196500 ;
    PORT
      LAYER met2 ;
        RECT 425.590 0.000 425.870 4.000 ;
    END
  END u2a_i[20]
  PIN u2a_i[21]
    DIRECTION INPUT ;
    USE SIGNAL ;
    ANTENNAGATEAREA 0.196500 ;
    PORT
      LAYER met2 ;
        RECT 442.150 0.000 442.430 4.000 ;
    END
  END u2a_i[21]
  PIN u2a_i[22]
    DIRECTION INPUT ;
    USE SIGNAL ;
    ANTENNAGATEAREA 0.196500 ;
    PORT
      LAYER met2 ;
        RECT 458.710 0.000 458.990 4.000 ;
    END
  END u2a_i[22]
  PIN u2a_i[23]
    DIRECTION INPUT ;
    USE SIGNAL ;
    ANTENNAGATEAREA 0.196500 ;
    PORT
      LAYER met2 ;
        RECT 475.270 0.000 475.550 4.000 ;
    END
  END u2a_i[23]
  PIN u2a_i[24]
    DIRECTION INPUT ;
    USE SIGNAL ;
    ANTENNAGATEAREA 0.196500 ;
    PORT
      LAYER met2 ;
        RECT 491.830 0.000 492.110 4.000 ;
    END
  END u2a_i[24]
  PIN u2a_i[25]
    DIRECTION INPUT ;
    USE SIGNAL ;
    ANTENNAGATEAREA 0.196500 ;
    PORT
      LAYER met2 ;
        RECT 508.390 0.000 508.670 4.000 ;
    END
  END u2a_i[25]
  PIN u2a_i[26]
    DIRECTION INPUT ;
    USE SIGNAL ;
    ANTENNAGATEAREA 0.196500 ;
    PORT
      LAYER met2 ;
        RECT 524.950 0.000 525.230 4.000 ;
    END
  END u2a_i[26]
  PIN u2a_i[27]
    DIRECTION INPUT ;
    USE SIGNAL ;
    ANTENNAGATEAREA 0.196500 ;
    PORT
      LAYER met2 ;
        RECT 541.510 0.000 541.790 4.000 ;
    END
  END u2a_i[27]
  PIN u2a_i[28]
    DIRECTION INPUT ;
    USE SIGNAL ;
    ANTENNAGATEAREA 0.196500 ;
    PORT
      LAYER met2 ;
        RECT 558.070 0.000 558.350 4.000 ;
    END
  END u2a_i[28]
  PIN u2a_i[29]
    DIRECTION INPUT ;
    USE SIGNAL ;
    ANTENNAGATEAREA 0.196500 ;
    PORT
      LAYER met2 ;
        RECT 574.630 0.000 574.910 4.000 ;
    END
  END u2a_i[29]
  PIN u2a_i[2]
    DIRECTION INPUT ;
    USE SIGNAL ;
    ANTENNAGATEAREA 0.196500 ;
    PORT
      LAYER met2 ;
        RECT 125.670 0.000 125.950 4.000 ;
    END
  END u2a_i[2]
  PIN u2a_i[30]
    DIRECTION INPUT ;
    USE SIGNAL ;
    ANTENNAGATEAREA 0.196500 ;
    PORT
      LAYER met2 ;
        RECT 591.190 0.000 591.470 4.000 ;
    END
  END u2a_i[30]
  PIN u2a_i[31]
    DIRECTION INPUT ;
    USE SIGNAL ;
    ANTENNAGATEAREA 0.196500 ;
    PORT
      LAYER met2 ;
        RECT 607.750 0.000 608.030 4.000 ;
    END
  END u2a_i[31]
  PIN u2a_i[3]
    DIRECTION INPUT ;
    USE SIGNAL ;
    ANTENNAGATEAREA 0.196500 ;
    PORT
      LAYER met2 ;
        RECT 143.150 0.000 143.430 4.000 ;
    END
  END u2a_i[3]
  PIN u2a_i[4]
    DIRECTION INPUT ;
    USE SIGNAL ;
    ANTENNAGATEAREA 0.196500 ;
    PORT
      LAYER met2 ;
        RECT 160.630 0.000 160.910 4.000 ;
    END
  END u2a_i[4]
  PIN u2a_i[5]
    DIRECTION INPUT ;
    USE SIGNAL ;
    ANTENNAGATEAREA 0.196500 ;
    PORT
      LAYER met2 ;
        RECT 177.190 0.000 177.470 4.000 ;
    END
  END u2a_i[5]
  PIN u2a_i[6]
    DIRECTION INPUT ;
    USE SIGNAL ;
    ANTENNAGATEAREA 0.196500 ;
    PORT
      LAYER met2 ;
        RECT 193.750 0.000 194.030 4.000 ;
    END
  END u2a_i[6]
  PIN u2a_i[7]
    DIRECTION INPUT ;
    USE SIGNAL ;
    ANTENNAGATEAREA 0.196500 ;
    PORT
      LAYER met2 ;
        RECT 210.310 0.000 210.590 4.000 ;
    END
  END u2a_i[7]
  PIN u2a_i[8]
    DIRECTION INPUT ;
    USE SIGNAL ;
    ANTENNAGATEAREA 0.196500 ;
    PORT
      LAYER met2 ;
        RECT 226.870 0.000 227.150 4.000 ;
    END
  END u2a_i[8]
  PIN u2a_i[9]
    DIRECTION INPUT ;
    USE SIGNAL ;
    ANTENNAGATEAREA 0.196500 ;
    PORT
      LAYER met2 ;
        RECT 243.430 0.000 243.710 4.000 ;
    END
  END u2a_i[9]
  PIN u2b_i[0]
    DIRECTION INPUT ;
    USE SIGNAL ;
    ANTENNAGATEAREA 0.196500 ;
    PORT
      LAYER met2 ;
        RECT 91.630 0.000 91.910 4.000 ;
    END
  END u2b_i[0]
  PIN u2b_i[10]
    DIRECTION INPUT ;
    USE SIGNAL ;
    ANTENNAGATEAREA 0.196500 ;
    PORT
      LAYER met2 ;
        RECT 260.910 0.000 261.190 4.000 ;
    END
  END u2b_i[10]
  PIN u2b_i[11]
    DIRECTION INPUT ;
    USE SIGNAL ;
    ANTENNAGATEAREA 0.196500 ;
    PORT
      LAYER met2 ;
        RECT 277.470 0.000 277.750 4.000 ;
    END
  END u2b_i[11]
  PIN u2b_i[12]
    DIRECTION INPUT ;
    USE SIGNAL ;
    ANTENNAGATEAREA 0.196500 ;
    PORT
      LAYER met2 ;
        RECT 294.030 0.000 294.310 4.000 ;
    END
  END u2b_i[12]
  PIN u2b_i[13]
    DIRECTION INPUT ;
    USE SIGNAL ;
    ANTENNAGATEAREA 0.196500 ;
    PORT
      LAYER met2 ;
        RECT 310.590 0.000 310.870 4.000 ;
    END
  END u2b_i[13]
  PIN u2b_i[14]
    DIRECTION INPUT ;
    USE SIGNAL ;
    ANTENNAGATEAREA 0.196500 ;
    PORT
      LAYER met2 ;
        RECT 327.150 0.000 327.430 4.000 ;
    END
  END u2b_i[14]
  PIN u2b_i[15]
    DIRECTION INPUT ;
    USE SIGNAL ;
    ANTENNAGATEAREA 0.196500 ;
    PORT
      LAYER met2 ;
        RECT 343.710 0.000 343.990 4.000 ;
    END
  END u2b_i[15]
  PIN u2b_i[16]
    DIRECTION INPUT ;
    USE SIGNAL ;
    ANTENNAGATEAREA 0.196500 ;
    PORT
      LAYER met2 ;
        RECT 360.270 0.000 360.550 4.000 ;
    END
  END u2b_i[16]
  PIN u2b_i[17]
    DIRECTION INPUT ;
    USE SIGNAL ;
    ANTENNAGATEAREA 0.196500 ;
    PORT
      LAYER met2 ;
        RECT 376.830 0.000 377.110 4.000 ;
    END
  END u2b_i[17]
  PIN u2b_i[18]
    DIRECTION INPUT ;
    USE SIGNAL ;
    ANTENNAGATEAREA 0.196500 ;
    PORT
      LAYER met2 ;
        RECT 393.390 0.000 393.670 4.000 ;
    END
  END u2b_i[18]
  PIN u2b_i[19]
    DIRECTION INPUT ;
    USE SIGNAL ;
    ANTENNAGATEAREA 0.196500 ;
    PORT
      LAYER met2 ;
        RECT 409.950 0.000 410.230 4.000 ;
    END
  END u2b_i[19]
  PIN u2b_i[1]
    DIRECTION INPUT ;
    USE SIGNAL ;
    ANTENNAGATEAREA 0.196500 ;
    PORT
      LAYER met2 ;
        RECT 109.110 0.000 109.390 4.000 ;
    END
  END u2b_i[1]
  PIN u2b_i[20]
    DIRECTION INPUT ;
    USE SIGNAL ;
    ANTENNAGATEAREA 0.196500 ;
    PORT
      LAYER met2 ;
        RECT 426.510 0.000 426.790 4.000 ;
    END
  END u2b_i[20]
  PIN u2b_i[21]
    DIRECTION INPUT ;
    USE SIGNAL ;
    ANTENNAGATEAREA 0.196500 ;
    PORT
      LAYER met2 ;
        RECT 443.070 0.000 443.350 4.000 ;
    END
  END u2b_i[21]
  PIN u2b_i[22]
    DIRECTION INPUT ;
    USE SIGNAL ;
    ANTENNAGATEAREA 0.196500 ;
    PORT
      LAYER met2 ;
        RECT 459.630 0.000 459.910 4.000 ;
    END
  END u2b_i[22]
  PIN u2b_i[23]
    DIRECTION INPUT ;
    USE SIGNAL ;
    ANTENNAGATEAREA 0.196500 ;
    PORT
      LAYER met2 ;
        RECT 476.190 0.000 476.470 4.000 ;
    END
  END u2b_i[23]
  PIN u2b_i[24]
    DIRECTION INPUT ;
    USE SIGNAL ;
    ANTENNAGATEAREA 0.196500 ;
    PORT
      LAYER met2 ;
        RECT 492.750 0.000 493.030 4.000 ;
    END
  END u2b_i[24]
  PIN u2b_i[25]
    DIRECTION INPUT ;
    USE SIGNAL ;
    ANTENNAGATEAREA 0.196500 ;
    PORT
      LAYER met2 ;
        RECT 509.310 0.000 509.590 4.000 ;
    END
  END u2b_i[25]
  PIN u2b_i[26]
    DIRECTION INPUT ;
    USE SIGNAL ;
    ANTENNAGATEAREA 0.196500 ;
    PORT
      LAYER met2 ;
        RECT 525.870 0.000 526.150 4.000 ;
    END
  END u2b_i[26]
  PIN u2b_i[27]
    DIRECTION INPUT ;
    USE SIGNAL ;
    ANTENNAGATEAREA 0.196500 ;
    PORT
      LAYER met2 ;
        RECT 542.430 0.000 542.710 4.000 ;
    END
  END u2b_i[27]
  PIN u2b_i[28]
    DIRECTION INPUT ;
    USE SIGNAL ;
    ANTENNAGATEAREA 0.196500 ;
    PORT
      LAYER met2 ;
        RECT 558.990 0.000 559.270 4.000 ;
    END
  END u2b_i[28]
  PIN u2b_i[29]
    DIRECTION INPUT ;
    USE SIGNAL ;
    ANTENNAGATEAREA 0.196500 ;
    PORT
      LAYER met2 ;
        RECT 575.550 0.000 575.830 4.000 ;
    END
  END u2b_i[29]
  PIN u2b_i[2]
    DIRECTION INPUT ;
    USE SIGNAL ;
    ANTENNAGATEAREA 0.196500 ;
    PORT
      LAYER met2 ;
        RECT 126.590 0.000 126.870 4.000 ;
    END
  END u2b_i[2]
  PIN u2b_i[30]
    DIRECTION INPUT ;
    USE SIGNAL ;
    ANTENNAGATEAREA 0.196500 ;
    PORT
      LAYER met2 ;
        RECT 592.110 0.000 592.390 4.000 ;
    END
  END u2b_i[30]
  PIN u2b_i[31]
    DIRECTION INPUT ;
    USE SIGNAL ;
    ANTENNAGATEAREA 0.196500 ;
    PORT
      LAYER met2 ;
        RECT 608.670 0.000 608.950 4.000 ;
    END
  END u2b_i[31]
  PIN u2b_i[3]
    DIRECTION INPUT ;
    USE SIGNAL ;
    ANTENNAGATEAREA 0.196500 ;
    PORT
      LAYER met2 ;
        RECT 144.070 0.000 144.350 4.000 ;
    END
  END u2b_i[3]
  PIN u2b_i[4]
    DIRECTION INPUT ;
    USE SIGNAL ;
    ANTENNAGATEAREA 0.196500 ;
    PORT
      LAYER met2 ;
        RECT 161.550 0.000 161.830 4.000 ;
    END
  END u2b_i[4]
  PIN u2b_i[5]
    DIRECTION INPUT ;
    USE SIGNAL ;
    ANTENNAGATEAREA 0.196500 ;
    PORT
      LAYER met2 ;
        RECT 178.110 0.000 178.390 4.000 ;
    END
  END u2b_i[5]
  PIN u2b_i[6]
    DIRECTION INPUT ;
    USE SIGNAL ;
    ANTENNAGATEAREA 0.196500 ;
    PORT
      LAYER met2 ;
        RECT 194.670 0.000 194.950 4.000 ;
    END
  END u2b_i[6]
  PIN u2b_i[7]
    DIRECTION INPUT ;
    USE SIGNAL ;
    ANTENNAGATEAREA 0.196500 ;
    PORT
      LAYER met2 ;
        RECT 211.230 0.000 211.510 4.000 ;
    END
  END u2b_i[7]
  PIN u2b_i[8]
    DIRECTION INPUT ;
    USE SIGNAL ;
    ANTENNAGATEAREA 0.196500 ;
    PORT
      LAYER met2 ;
        RECT 227.790 0.000 228.070 4.000 ;
    END
  END u2b_i[8]
  PIN u2b_i[9]
    DIRECTION INPUT ;
    USE SIGNAL ;
    ANTENNAGATEAREA 0.196500 ;
    PORT
      LAYER met2 ;
        RECT 244.350 0.000 244.630 4.000 ;
    END
  END u2b_i[9]
  PIN u2c_i[0]
    DIRECTION INPUT ;
    USE SIGNAL ;
    ANTENNAGATEAREA 0.196500 ;
    PORT
      LAYER met2 ;
        RECT 92.550 0.000 92.830 4.000 ;
    END
  END u2c_i[0]
  PIN u2c_i[10]
    DIRECTION INPUT ;
    USE SIGNAL ;
    ANTENNAGATEAREA 0.196500 ;
    PORT
      LAYER met2 ;
        RECT 261.830 0.000 262.110 4.000 ;
    END
  END u2c_i[10]
  PIN u2c_i[11]
    DIRECTION INPUT ;
    USE SIGNAL ;
    ANTENNAGATEAREA 0.196500 ;
    PORT
      LAYER met2 ;
        RECT 278.390 0.000 278.670 4.000 ;
    END
  END u2c_i[11]
  PIN u2c_i[12]
    DIRECTION INPUT ;
    USE SIGNAL ;
    ANTENNAGATEAREA 0.196500 ;
    PORT
      LAYER met2 ;
        RECT 294.950 0.000 295.230 4.000 ;
    END
  END u2c_i[12]
  PIN u2c_i[13]
    DIRECTION INPUT ;
    USE SIGNAL ;
    ANTENNAGATEAREA 0.196500 ;
    PORT
      LAYER met2 ;
        RECT 311.510 0.000 311.790 4.000 ;
    END
  END u2c_i[13]
  PIN u2c_i[14]
    DIRECTION INPUT ;
    USE SIGNAL ;
    ANTENNAGATEAREA 0.196500 ;
    PORT
      LAYER met2 ;
        RECT 328.070 0.000 328.350 4.000 ;
    END
  END u2c_i[14]
  PIN u2c_i[15]
    DIRECTION INPUT ;
    USE SIGNAL ;
    ANTENNAGATEAREA 0.196500 ;
    PORT
      LAYER met2 ;
        RECT 344.630 0.000 344.910 4.000 ;
    END
  END u2c_i[15]
  PIN u2c_i[16]
    DIRECTION INPUT ;
    USE SIGNAL ;
    ANTENNAGATEAREA 0.196500 ;
    PORT
      LAYER met2 ;
        RECT 361.190 0.000 361.470 4.000 ;
    END
  END u2c_i[16]
  PIN u2c_i[17]
    DIRECTION INPUT ;
    USE SIGNAL ;
    ANTENNAGATEAREA 0.196500 ;
    PORT
      LAYER met2 ;
        RECT 377.750 0.000 378.030 4.000 ;
    END
  END u2c_i[17]
  PIN u2c_i[18]
    DIRECTION INPUT ;
    USE SIGNAL ;
    ANTENNAGATEAREA 0.196500 ;
    PORT
      LAYER met2 ;
        RECT 394.310 0.000 394.590 4.000 ;
    END
  END u2c_i[18]
  PIN u2c_i[19]
    DIRECTION INPUT ;
    USE SIGNAL ;
    ANTENNAGATEAREA 0.196500 ;
    PORT
      LAYER met2 ;
        RECT 410.870 0.000 411.150 4.000 ;
    END
  END u2c_i[19]
  PIN u2c_i[1]
    DIRECTION INPUT ;
    USE SIGNAL ;
    ANTENNAGATEAREA 0.196500 ;
    PORT
      LAYER met2 ;
        RECT 110.030 0.000 110.310 4.000 ;
    END
  END u2c_i[1]
  PIN u2c_i[20]
    DIRECTION INPUT ;
    USE SIGNAL ;
    ANTENNAGATEAREA 0.196500 ;
    PORT
      LAYER met2 ;
        RECT 427.430 0.000 427.710 4.000 ;
    END
  END u2c_i[20]
  PIN u2c_i[21]
    DIRECTION INPUT ;
    USE SIGNAL ;
    ANTENNAGATEAREA 0.196500 ;
    PORT
      LAYER met2 ;
        RECT 443.990 0.000 444.270 4.000 ;
    END
  END u2c_i[21]
  PIN u2c_i[22]
    DIRECTION INPUT ;
    USE SIGNAL ;
    ANTENNAGATEAREA 0.196500 ;
    PORT
      LAYER met2 ;
        RECT 460.550 0.000 460.830 4.000 ;
    END
  END u2c_i[22]
  PIN u2c_i[23]
    DIRECTION INPUT ;
    USE SIGNAL ;
    ANTENNAGATEAREA 0.196500 ;
    PORT
      LAYER met2 ;
        RECT 477.110 0.000 477.390 4.000 ;
    END
  END u2c_i[23]
  PIN u2c_i[24]
    DIRECTION INPUT ;
    USE SIGNAL ;
    ANTENNAGATEAREA 0.196500 ;
    PORT
      LAYER met2 ;
        RECT 493.670 0.000 493.950 4.000 ;
    END
  END u2c_i[24]
  PIN u2c_i[25]
    DIRECTION INPUT ;
    USE SIGNAL ;
    ANTENNAGATEAREA 0.196500 ;
    PORT
      LAYER met2 ;
        RECT 510.230 0.000 510.510 4.000 ;
    END
  END u2c_i[25]
  PIN u2c_i[26]
    DIRECTION INPUT ;
    USE SIGNAL ;
    ANTENNAGATEAREA 0.196500 ;
    PORT
      LAYER met2 ;
        RECT 526.790 0.000 527.070 4.000 ;
    END
  END u2c_i[26]
  PIN u2c_i[27]
    DIRECTION INPUT ;
    USE SIGNAL ;
    ANTENNAGATEAREA 0.196500 ;
    PORT
      LAYER met2 ;
        RECT 543.350 0.000 543.630 4.000 ;
    END
  END u2c_i[27]
  PIN u2c_i[28]
    DIRECTION INPUT ;
    USE SIGNAL ;
    ANTENNAGATEAREA 0.196500 ;
    PORT
      LAYER met2 ;
        RECT 559.910 0.000 560.190 4.000 ;
    END
  END u2c_i[28]
  PIN u2c_i[29]
    DIRECTION INPUT ;
    USE SIGNAL ;
    ANTENNAGATEAREA 0.196500 ;
    PORT
      LAYER met2 ;
        RECT 576.470 0.000 576.750 4.000 ;
    END
  END u2c_i[29]
  PIN u2c_i[2]
    DIRECTION INPUT ;
    USE SIGNAL ;
    ANTENNAGATEAREA 0.196500 ;
    PORT
      LAYER met2 ;
        RECT 127.510 0.000 127.790 4.000 ;
    END
  END u2c_i[2]
  PIN u2c_i[30]
    DIRECTION INPUT ;
    USE SIGNAL ;
    ANTENNAGATEAREA 0.196500 ;
    PORT
      LAYER met2 ;
        RECT 593.030 0.000 593.310 4.000 ;
    END
  END u2c_i[30]
  PIN u2c_i[31]
    DIRECTION INPUT ;
    USE SIGNAL ;
    ANTENNAGATEAREA 0.196500 ;
    PORT
      LAYER met2 ;
        RECT 609.590 0.000 609.870 4.000 ;
    END
  END u2c_i[31]
  PIN u2c_i[3]
    DIRECTION INPUT ;
    USE SIGNAL ;
    ANTENNAGATEAREA 0.196500 ;
    PORT
      LAYER met2 ;
        RECT 144.990 0.000 145.270 4.000 ;
    END
  END u2c_i[3]
  PIN u2c_i[4]
    DIRECTION INPUT ;
    USE SIGNAL ;
    ANTENNAGATEAREA 0.196500 ;
    PORT
      LAYER met2 ;
        RECT 162.470 0.000 162.750 4.000 ;
    END
  END u2c_i[4]
  PIN u2c_i[5]
    DIRECTION INPUT ;
    USE SIGNAL ;
    ANTENNAGATEAREA 0.196500 ;
    PORT
      LAYER met2 ;
        RECT 179.030 0.000 179.310 4.000 ;
    END
  END u2c_i[5]
  PIN u2c_i[6]
    DIRECTION INPUT ;
    USE SIGNAL ;
    ANTENNAGATEAREA 0.196500 ;
    PORT
      LAYER met2 ;
        RECT 195.590 0.000 195.870 4.000 ;
    END
  END u2c_i[6]
  PIN u2c_i[7]
    DIRECTION INPUT ;
    USE SIGNAL ;
    ANTENNAGATEAREA 0.196500 ;
    PORT
      LAYER met2 ;
        RECT 212.150 0.000 212.430 4.000 ;
    END
  END u2c_i[7]
  PIN u2c_i[8]
    DIRECTION INPUT ;
    USE SIGNAL ;
    ANTENNAGATEAREA 0.196500 ;
    PORT
      LAYER met2 ;
        RECT 228.710 0.000 228.990 4.000 ;
    END
  END u2c_i[8]
  PIN u2c_i[9]
    DIRECTION INPUT ;
    USE SIGNAL ;
    ANTENNAGATEAREA 0.196500 ;
    PORT
      LAYER met2 ;
        RECT 245.270 0.000 245.550 4.000 ;
    END
  END u2c_i[9]
  PIN u2d_i[0]
    DIRECTION INPUT ;
    USE SIGNAL ;
    ANTENNAGATEAREA 0.196500 ;
    PORT
      LAYER met2 ;
        RECT 93.470 0.000 93.750 4.000 ;
    END
  END u2d_i[0]
  PIN u2d_i[10]
    DIRECTION INPUT ;
    USE SIGNAL ;
    ANTENNAGATEAREA 0.196500 ;
    PORT
      LAYER met2 ;
        RECT 262.750 0.000 263.030 4.000 ;
    END
  END u2d_i[10]
  PIN u2d_i[11]
    DIRECTION INPUT ;
    USE SIGNAL ;
    ANTENNAGATEAREA 0.196500 ;
    PORT
      LAYER met2 ;
        RECT 279.310 0.000 279.590 4.000 ;
    END
  END u2d_i[11]
  PIN u2d_i[12]
    DIRECTION INPUT ;
    USE SIGNAL ;
    ANTENNAGATEAREA 0.196500 ;
    PORT
      LAYER met2 ;
        RECT 295.870 0.000 296.150 4.000 ;
    END
  END u2d_i[12]
  PIN u2d_i[13]
    DIRECTION INPUT ;
    USE SIGNAL ;
    ANTENNAGATEAREA 0.196500 ;
    PORT
      LAYER met2 ;
        RECT 312.430 0.000 312.710 4.000 ;
    END
  END u2d_i[13]
  PIN u2d_i[14]
    DIRECTION INPUT ;
    USE SIGNAL ;
    ANTENNAGATEAREA 0.196500 ;
    PORT
      LAYER met2 ;
        RECT 328.990 0.000 329.270 4.000 ;
    END
  END u2d_i[14]
  PIN u2d_i[15]
    DIRECTION INPUT ;
    USE SIGNAL ;
    ANTENNAGATEAREA 0.196500 ;
    PORT
      LAYER met2 ;
        RECT 345.550 0.000 345.830 4.000 ;
    END
  END u2d_i[15]
  PIN u2d_i[16]
    DIRECTION INPUT ;
    USE SIGNAL ;
    ANTENNAGATEAREA 0.196500 ;
    PORT
      LAYER met2 ;
        RECT 362.110 0.000 362.390 4.000 ;
    END
  END u2d_i[16]
  PIN u2d_i[17]
    DIRECTION INPUT ;
    USE SIGNAL ;
    ANTENNAGATEAREA 0.196500 ;
    PORT
      LAYER met2 ;
        RECT 378.670 0.000 378.950 4.000 ;
    END
  END u2d_i[17]
  PIN u2d_i[18]
    DIRECTION INPUT ;
    USE SIGNAL ;
    ANTENNAGATEAREA 0.196500 ;
    PORT
      LAYER met2 ;
        RECT 395.230 0.000 395.510 4.000 ;
    END
  END u2d_i[18]
  PIN u2d_i[19]
    DIRECTION INPUT ;
    USE SIGNAL ;
    ANTENNAGATEAREA 0.196500 ;
    PORT
      LAYER met2 ;
        RECT 411.790 0.000 412.070 4.000 ;
    END
  END u2d_i[19]
  PIN u2d_i[1]
    DIRECTION INPUT ;
    USE SIGNAL ;
    ANTENNAGATEAREA 0.196500 ;
    PORT
      LAYER met2 ;
        RECT 110.950 0.000 111.230 4.000 ;
    END
  END u2d_i[1]
  PIN u2d_i[20]
    DIRECTION INPUT ;
    USE SIGNAL ;
    ANTENNAGATEAREA 0.196500 ;
    PORT
      LAYER met2 ;
        RECT 428.350 0.000 428.630 4.000 ;
    END
  END u2d_i[20]
  PIN u2d_i[21]
    DIRECTION INPUT ;
    USE SIGNAL ;
    ANTENNAGATEAREA 0.196500 ;
    PORT
      LAYER met2 ;
        RECT 444.910 0.000 445.190 4.000 ;
    END
  END u2d_i[21]
  PIN u2d_i[22]
    DIRECTION INPUT ;
    USE SIGNAL ;
    ANTENNAGATEAREA 0.196500 ;
    PORT
      LAYER met2 ;
        RECT 461.470 0.000 461.750 4.000 ;
    END
  END u2d_i[22]
  PIN u2d_i[23]
    DIRECTION INPUT ;
    USE SIGNAL ;
    ANTENNAGATEAREA 0.196500 ;
    PORT
      LAYER met2 ;
        RECT 478.030 0.000 478.310 4.000 ;
    END
  END u2d_i[23]
  PIN u2d_i[24]
    DIRECTION INPUT ;
    USE SIGNAL ;
    ANTENNAGATEAREA 0.196500 ;
    PORT
      LAYER met2 ;
        RECT 494.590 0.000 494.870 4.000 ;
    END
  END u2d_i[24]
  PIN u2d_i[25]
    DIRECTION INPUT ;
    USE SIGNAL ;
    ANTENNAGATEAREA 0.196500 ;
    PORT
      LAYER met2 ;
        RECT 511.150 0.000 511.430 4.000 ;
    END
  END u2d_i[25]
  PIN u2d_i[26]
    DIRECTION INPUT ;
    USE SIGNAL ;
    ANTENNAGATEAREA 0.196500 ;
    PORT
      LAYER met2 ;
        RECT 527.710 0.000 527.990 4.000 ;
    END
  END u2d_i[26]
  PIN u2d_i[27]
    DIRECTION INPUT ;
    USE SIGNAL ;
    ANTENNAGATEAREA 0.196500 ;
    PORT
      LAYER met2 ;
        RECT 544.270 0.000 544.550 4.000 ;
    END
  END u2d_i[27]
  PIN u2d_i[28]
    DIRECTION INPUT ;
    USE SIGNAL ;
    ANTENNAGATEAREA 0.196500 ;
    PORT
      LAYER met2 ;
        RECT 560.830 0.000 561.110 4.000 ;
    END
  END u2d_i[28]
  PIN u2d_i[29]
    DIRECTION INPUT ;
    USE SIGNAL ;
    ANTENNAGATEAREA 0.196500 ;
    PORT
      LAYER met2 ;
        RECT 577.390 0.000 577.670 4.000 ;
    END
  END u2d_i[29]
  PIN u2d_i[2]
    DIRECTION INPUT ;
    USE SIGNAL ;
    ANTENNAGATEAREA 0.196500 ;
    PORT
      LAYER met2 ;
        RECT 128.430 0.000 128.710 4.000 ;
    END
  END u2d_i[2]
  PIN u2d_i[30]
    DIRECTION INPUT ;
    USE SIGNAL ;
    ANTENNAGATEAREA 0.196500 ;
    PORT
      LAYER met2 ;
        RECT 593.950 0.000 594.230 4.000 ;
    END
  END u2d_i[30]
  PIN u2d_i[31]
    DIRECTION INPUT ;
    USE SIGNAL ;
    ANTENNAGATEAREA 0.196500 ;
    PORT
      LAYER met2 ;
        RECT 610.510 0.000 610.790 4.000 ;
    END
  END u2d_i[31]
  PIN u2d_i[3]
    DIRECTION INPUT ;
    USE SIGNAL ;
    ANTENNAGATEAREA 0.196500 ;
    PORT
      LAYER met2 ;
        RECT 145.910 0.000 146.190 4.000 ;
    END
  END u2d_i[3]
  PIN u2d_i[4]
    DIRECTION INPUT ;
    USE SIGNAL ;
    ANTENNAGATEAREA 0.196500 ;
    PORT
      LAYER met2 ;
        RECT 163.390 0.000 163.670 4.000 ;
    END
  END u2d_i[4]
  PIN u2d_i[5]
    DIRECTION INPUT ;
    USE SIGNAL ;
    ANTENNAGATEAREA 0.196500 ;
    PORT
      LAYER met2 ;
        RECT 179.950 0.000 180.230 4.000 ;
    END
  END u2d_i[5]
  PIN u2d_i[6]
    DIRECTION INPUT ;
    USE SIGNAL ;
    ANTENNAGATEAREA 0.196500 ;
    PORT
      LAYER met2 ;
        RECT 196.510 0.000 196.790 4.000 ;
    END
  END u2d_i[6]
  PIN u2d_i[7]
    DIRECTION INPUT ;
    USE SIGNAL ;
    ANTENNAGATEAREA 0.196500 ;
    PORT
      LAYER met2 ;
        RECT 213.070 0.000 213.350 4.000 ;
    END
  END u2d_i[7]
  PIN u2d_i[8]
    DIRECTION INPUT ;
    USE SIGNAL ;
    ANTENNAGATEAREA 0.196500 ;
    PORT
      LAYER met2 ;
        RECT 229.630 0.000 229.910 4.000 ;
    END
  END u2d_i[8]
  PIN u2d_i[9]
    DIRECTION INPUT ;
    USE SIGNAL ;
    ANTENNAGATEAREA 0.196500 ;
    PORT
      LAYER met2 ;
        RECT 246.190 0.000 246.470 4.000 ;
    END
  END u2d_i[9]
  PIN u2e_i[0]
    DIRECTION INPUT ;
    USE SIGNAL ;
    ANTENNAGATEAREA 0.196500 ;
    PORT
      LAYER met2 ;
        RECT 94.390 0.000 94.670 4.000 ;
    END
  END u2e_i[0]
  PIN u2e_i[10]
    DIRECTION INPUT ;
    USE SIGNAL ;
    ANTENNAGATEAREA 0.196500 ;
    PORT
      LAYER met2 ;
        RECT 263.670 0.000 263.950 4.000 ;
    END
  END u2e_i[10]
  PIN u2e_i[11]
    DIRECTION INPUT ;
    USE SIGNAL ;
    ANTENNAGATEAREA 0.196500 ;
    PORT
      LAYER met2 ;
        RECT 280.230 0.000 280.510 4.000 ;
    END
  END u2e_i[11]
  PIN u2e_i[12]
    DIRECTION INPUT ;
    USE SIGNAL ;
    ANTENNAGATEAREA 0.196500 ;
    PORT
      LAYER met2 ;
        RECT 296.790 0.000 297.070 4.000 ;
    END
  END u2e_i[12]
  PIN u2e_i[13]
    DIRECTION INPUT ;
    USE SIGNAL ;
    ANTENNAGATEAREA 0.196500 ;
    PORT
      LAYER met2 ;
        RECT 313.350 0.000 313.630 4.000 ;
    END
  END u2e_i[13]
  PIN u2e_i[14]
    DIRECTION INPUT ;
    USE SIGNAL ;
    ANTENNAGATEAREA 0.196500 ;
    PORT
      LAYER met2 ;
        RECT 329.910 0.000 330.190 4.000 ;
    END
  END u2e_i[14]
  PIN u2e_i[15]
    DIRECTION INPUT ;
    USE SIGNAL ;
    ANTENNAGATEAREA 0.196500 ;
    PORT
      LAYER met2 ;
        RECT 346.470 0.000 346.750 4.000 ;
    END
  END u2e_i[15]
  PIN u2e_i[16]
    DIRECTION INPUT ;
    USE SIGNAL ;
    ANTENNAGATEAREA 0.196500 ;
    PORT
      LAYER met2 ;
        RECT 363.030 0.000 363.310 4.000 ;
    END
  END u2e_i[16]
  PIN u2e_i[17]
    DIRECTION INPUT ;
    USE SIGNAL ;
    ANTENNAGATEAREA 0.196500 ;
    PORT
      LAYER met2 ;
        RECT 379.590 0.000 379.870 4.000 ;
    END
  END u2e_i[17]
  PIN u2e_i[18]
    DIRECTION INPUT ;
    USE SIGNAL ;
    ANTENNAGATEAREA 0.196500 ;
    PORT
      LAYER met2 ;
        RECT 396.150 0.000 396.430 4.000 ;
    END
  END u2e_i[18]
  PIN u2e_i[19]
    DIRECTION INPUT ;
    USE SIGNAL ;
    ANTENNAGATEAREA 0.196500 ;
    PORT
      LAYER met2 ;
        RECT 412.710 0.000 412.990 4.000 ;
    END
  END u2e_i[19]
  PIN u2e_i[1]
    DIRECTION INPUT ;
    USE SIGNAL ;
    ANTENNAGATEAREA 0.196500 ;
    PORT
      LAYER met2 ;
        RECT 111.870 0.000 112.150 4.000 ;
    END
  END u2e_i[1]
  PIN u2e_i[20]
    DIRECTION INPUT ;
    USE SIGNAL ;
    ANTENNAGATEAREA 0.196500 ;
    PORT
      LAYER met2 ;
        RECT 429.270 0.000 429.550 4.000 ;
    END
  END u2e_i[20]
  PIN u2e_i[21]
    DIRECTION INPUT ;
    USE SIGNAL ;
    ANTENNAGATEAREA 0.196500 ;
    PORT
      LAYER met2 ;
        RECT 445.830 0.000 446.110 4.000 ;
    END
  END u2e_i[21]
  PIN u2e_i[22]
    DIRECTION INPUT ;
    USE SIGNAL ;
    ANTENNAGATEAREA 0.196500 ;
    PORT
      LAYER met2 ;
        RECT 462.390 0.000 462.670 4.000 ;
    END
  END u2e_i[22]
  PIN u2e_i[23]
    DIRECTION INPUT ;
    USE SIGNAL ;
    ANTENNAGATEAREA 0.196500 ;
    PORT
      LAYER met2 ;
        RECT 478.950 0.000 479.230 4.000 ;
    END
  END u2e_i[23]
  PIN u2e_i[24]
    DIRECTION INPUT ;
    USE SIGNAL ;
    ANTENNAGATEAREA 0.196500 ;
    PORT
      LAYER met2 ;
        RECT 495.510 0.000 495.790 4.000 ;
    END
  END u2e_i[24]
  PIN u2e_i[25]
    DIRECTION INPUT ;
    USE SIGNAL ;
    ANTENNAGATEAREA 0.196500 ;
    PORT
      LAYER met2 ;
        RECT 512.070 0.000 512.350 4.000 ;
    END
  END u2e_i[25]
  PIN u2e_i[26]
    DIRECTION INPUT ;
    USE SIGNAL ;
    ANTENNAGATEAREA 0.196500 ;
    PORT
      LAYER met2 ;
        RECT 528.630 0.000 528.910 4.000 ;
    END
  END u2e_i[26]
  PIN u2e_i[27]
    DIRECTION INPUT ;
    USE SIGNAL ;
    ANTENNAGATEAREA 0.196500 ;
    PORT
      LAYER met2 ;
        RECT 545.190 0.000 545.470 4.000 ;
    END
  END u2e_i[27]
  PIN u2e_i[28]
    DIRECTION INPUT ;
    USE SIGNAL ;
    ANTENNAGATEAREA 0.196500 ;
    PORT
      LAYER met2 ;
        RECT 561.750 0.000 562.030 4.000 ;
    END
  END u2e_i[28]
  PIN u2e_i[29]
    DIRECTION INPUT ;
    USE SIGNAL ;
    ANTENNAGATEAREA 0.196500 ;
    PORT
      LAYER met2 ;
        RECT 578.310 0.000 578.590 4.000 ;
    END
  END u2e_i[29]
  PIN u2e_i[2]
    DIRECTION INPUT ;
    USE SIGNAL ;
    ANTENNAGATEAREA 0.196500 ;
    PORT
      LAYER met2 ;
        RECT 129.350 0.000 129.630 4.000 ;
    END
  END u2e_i[2]
  PIN u2e_i[30]
    DIRECTION INPUT ;
    USE SIGNAL ;
    ANTENNAGATEAREA 0.196500 ;
    PORT
      LAYER met2 ;
        RECT 594.870 0.000 595.150 4.000 ;
    END
  END u2e_i[30]
  PIN u2e_i[31]
    DIRECTION INPUT ;
    USE SIGNAL ;
    ANTENNAGATEAREA 0.196500 ;
    PORT
      LAYER met2 ;
        RECT 611.430 0.000 611.710 4.000 ;
    END
  END u2e_i[31]
  PIN u2e_i[3]
    DIRECTION INPUT ;
    USE SIGNAL ;
    ANTENNAGATEAREA 0.196500 ;
    PORT
      LAYER met2 ;
        RECT 146.830 0.000 147.110 4.000 ;
    END
  END u2e_i[3]
  PIN u2e_i[4]
    DIRECTION INPUT ;
    USE SIGNAL ;
    ANTENNAGATEAREA 0.196500 ;
    PORT
      LAYER met2 ;
        RECT 164.310 0.000 164.590 4.000 ;
    END
  END u2e_i[4]
  PIN u2e_i[5]
    DIRECTION INPUT ;
    USE SIGNAL ;
    ANTENNAGATEAREA 0.196500 ;
    PORT
      LAYER met2 ;
        RECT 180.870 0.000 181.150 4.000 ;
    END
  END u2e_i[5]
  PIN u2e_i[6]
    DIRECTION INPUT ;
    USE SIGNAL ;
    ANTENNAGATEAREA 0.196500 ;
    PORT
      LAYER met2 ;
        RECT 197.430 0.000 197.710 4.000 ;
    END
  END u2e_i[6]
  PIN u2e_i[7]
    DIRECTION INPUT ;
    USE SIGNAL ;
    ANTENNAGATEAREA 0.196500 ;
    PORT
      LAYER met2 ;
        RECT 213.990 0.000 214.270 4.000 ;
    END
  END u2e_i[7]
  PIN u2e_i[8]
    DIRECTION INPUT ;
    USE SIGNAL ;
    ANTENNAGATEAREA 0.196500 ;
    PORT
      LAYER met2 ;
        RECT 230.550 0.000 230.830 4.000 ;
    END
  END u2e_i[8]
  PIN u2e_i[9]
    DIRECTION INPUT ;
    USE SIGNAL ;
    ANTENNAGATEAREA 0.196500 ;
    PORT
      LAYER met2 ;
        RECT 247.110 0.000 247.390 4.000 ;
    END
  END u2e_i[9]
  PIN u2f_i[0]
    DIRECTION INPUT ;
    USE SIGNAL ;
    ANTENNAGATEAREA 0.196500 ;
    PORT
      LAYER met2 ;
        RECT 95.310 0.000 95.590 4.000 ;
    END
  END u2f_i[0]
  PIN u2f_i[10]
    DIRECTION INPUT ;
    USE SIGNAL ;
    ANTENNAGATEAREA 0.196500 ;
    PORT
      LAYER met2 ;
        RECT 264.590 0.000 264.870 4.000 ;
    END
  END u2f_i[10]
  PIN u2f_i[11]
    DIRECTION INPUT ;
    USE SIGNAL ;
    ANTENNAGATEAREA 0.196500 ;
    PORT
      LAYER met2 ;
        RECT 281.150 0.000 281.430 4.000 ;
    END
  END u2f_i[11]
  PIN u2f_i[12]
    DIRECTION INPUT ;
    USE SIGNAL ;
    ANTENNAGATEAREA 0.196500 ;
    PORT
      LAYER met2 ;
        RECT 297.710 0.000 297.990 4.000 ;
    END
  END u2f_i[12]
  PIN u2f_i[13]
    DIRECTION INPUT ;
    USE SIGNAL ;
    ANTENNAGATEAREA 0.196500 ;
    PORT
      LAYER met2 ;
        RECT 314.270 0.000 314.550 4.000 ;
    END
  END u2f_i[13]
  PIN u2f_i[14]
    DIRECTION INPUT ;
    USE SIGNAL ;
    ANTENNAGATEAREA 0.196500 ;
    PORT
      LAYER met2 ;
        RECT 330.830 0.000 331.110 4.000 ;
    END
  END u2f_i[14]
  PIN u2f_i[15]
    DIRECTION INPUT ;
    USE SIGNAL ;
    ANTENNAGATEAREA 0.196500 ;
    PORT
      LAYER met2 ;
        RECT 347.390 0.000 347.670 4.000 ;
    END
  END u2f_i[15]
  PIN u2f_i[16]
    DIRECTION INPUT ;
    USE SIGNAL ;
    ANTENNAGATEAREA 0.196500 ;
    PORT
      LAYER met2 ;
        RECT 363.950 0.000 364.230 4.000 ;
    END
  END u2f_i[16]
  PIN u2f_i[17]
    DIRECTION INPUT ;
    USE SIGNAL ;
    ANTENNAGATEAREA 0.196500 ;
    PORT
      LAYER met2 ;
        RECT 380.510 0.000 380.790 4.000 ;
    END
  END u2f_i[17]
  PIN u2f_i[18]
    DIRECTION INPUT ;
    USE SIGNAL ;
    ANTENNAGATEAREA 0.196500 ;
    PORT
      LAYER met2 ;
        RECT 397.070 0.000 397.350 4.000 ;
    END
  END u2f_i[18]
  PIN u2f_i[19]
    DIRECTION INPUT ;
    USE SIGNAL ;
    ANTENNAGATEAREA 0.196500 ;
    PORT
      LAYER met2 ;
        RECT 413.630 0.000 413.910 4.000 ;
    END
  END u2f_i[19]
  PIN u2f_i[1]
    DIRECTION INPUT ;
    USE SIGNAL ;
    ANTENNAGATEAREA 0.196500 ;
    PORT
      LAYER met2 ;
        RECT 112.790 0.000 113.070 4.000 ;
    END
  END u2f_i[1]
  PIN u2f_i[20]
    DIRECTION INPUT ;
    USE SIGNAL ;
    ANTENNAGATEAREA 0.196500 ;
    PORT
      LAYER met2 ;
        RECT 430.190 0.000 430.470 4.000 ;
    END
  END u2f_i[20]
  PIN u2f_i[21]
    DIRECTION INPUT ;
    USE SIGNAL ;
    ANTENNAGATEAREA 0.196500 ;
    PORT
      LAYER met2 ;
        RECT 446.750 0.000 447.030 4.000 ;
    END
  END u2f_i[21]
  PIN u2f_i[22]
    DIRECTION INPUT ;
    USE SIGNAL ;
    ANTENNAGATEAREA 0.196500 ;
    PORT
      LAYER met2 ;
        RECT 463.310 0.000 463.590 4.000 ;
    END
  END u2f_i[22]
  PIN u2f_i[23]
    DIRECTION INPUT ;
    USE SIGNAL ;
    ANTENNAGATEAREA 0.196500 ;
    PORT
      LAYER met2 ;
        RECT 479.870 0.000 480.150 4.000 ;
    END
  END u2f_i[23]
  PIN u2f_i[24]
    DIRECTION INPUT ;
    USE SIGNAL ;
    ANTENNAGATEAREA 0.196500 ;
    PORT
      LAYER met2 ;
        RECT 496.430 0.000 496.710 4.000 ;
    END
  END u2f_i[24]
  PIN u2f_i[25]
    DIRECTION INPUT ;
    USE SIGNAL ;
    ANTENNAGATEAREA 0.196500 ;
    PORT
      LAYER met2 ;
        RECT 512.990 0.000 513.270 4.000 ;
    END
  END u2f_i[25]
  PIN u2f_i[26]
    DIRECTION INPUT ;
    USE SIGNAL ;
    ANTENNAGATEAREA 0.196500 ;
    PORT
      LAYER met2 ;
        RECT 529.550 0.000 529.830 4.000 ;
    END
  END u2f_i[26]
  PIN u2f_i[27]
    DIRECTION INPUT ;
    USE SIGNAL ;
    ANTENNAGATEAREA 0.196500 ;
    PORT
      LAYER met2 ;
        RECT 546.110 0.000 546.390 4.000 ;
    END
  END u2f_i[27]
  PIN u2f_i[28]
    DIRECTION INPUT ;
    USE SIGNAL ;
    ANTENNAGATEAREA 0.196500 ;
    PORT
      LAYER met2 ;
        RECT 562.670 0.000 562.950 4.000 ;
    END
  END u2f_i[28]
  PIN u2f_i[29]
    DIRECTION INPUT ;
    USE SIGNAL ;
    ANTENNAGATEAREA 0.196500 ;
    PORT
      LAYER met2 ;
        RECT 579.230 0.000 579.510 4.000 ;
    END
  END u2f_i[29]
  PIN u2f_i[2]
    DIRECTION INPUT ;
    USE SIGNAL ;
    ANTENNAGATEAREA 0.196500 ;
    PORT
      LAYER met2 ;
        RECT 130.270 0.000 130.550 4.000 ;
    END
  END u2f_i[2]
  PIN u2f_i[30]
    DIRECTION INPUT ;
    USE SIGNAL ;
    ANTENNAGATEAREA 0.196500 ;
    PORT
      LAYER met2 ;
        RECT 595.790 0.000 596.070 4.000 ;
    END
  END u2f_i[30]
  PIN u2f_i[31]
    DIRECTION INPUT ;
    USE SIGNAL ;
    ANTENNAGATEAREA 0.196500 ;
    PORT
      LAYER met2 ;
        RECT 612.350 0.000 612.630 4.000 ;
    END
  END u2f_i[31]
  PIN u2f_i[3]
    DIRECTION INPUT ;
    USE SIGNAL ;
    ANTENNAGATEAREA 0.196500 ;
    PORT
      LAYER met2 ;
        RECT 147.750 0.000 148.030 4.000 ;
    END
  END u2f_i[3]
  PIN u2f_i[4]
    DIRECTION INPUT ;
    USE SIGNAL ;
    ANTENNAGATEAREA 0.196500 ;
    PORT
      LAYER met2 ;
        RECT 165.230 0.000 165.510 4.000 ;
    END
  END u2f_i[4]
  PIN u2f_i[5]
    DIRECTION INPUT ;
    USE SIGNAL ;
    ANTENNAGATEAREA 0.196500 ;
    PORT
      LAYER met2 ;
        RECT 181.790 0.000 182.070 4.000 ;
    END
  END u2f_i[5]
  PIN u2f_i[6]
    DIRECTION INPUT ;
    USE SIGNAL ;
    ANTENNAGATEAREA 0.196500 ;
    PORT
      LAYER met2 ;
        RECT 198.350 0.000 198.630 4.000 ;
    END
  END u2f_i[6]
  PIN u2f_i[7]
    DIRECTION INPUT ;
    USE SIGNAL ;
    ANTENNAGATEAREA 0.196500 ;
    PORT
      LAYER met2 ;
        RECT 214.910 0.000 215.190 4.000 ;
    END
  END u2f_i[7]
  PIN u2f_i[8]
    DIRECTION INPUT ;
    USE SIGNAL ;
    ANTENNAGATEAREA 0.196500 ;
    PORT
      LAYER met2 ;
        RECT 231.470 0.000 231.750 4.000 ;
    END
  END u2f_i[8]
  PIN u2f_i[9]
    DIRECTION INPUT ;
    USE SIGNAL ;
    ANTENNAGATEAREA 0.196500 ;
    PORT
      LAYER met2 ;
        RECT 248.030 0.000 248.310 4.000 ;
    END
  END u2f_i[9]
  PIN user_count_i[0]
    DIRECTION INPUT ;
    USE SIGNAL ;
    ANTENNAGATEAREA 0.247500 ;
    PORT
      LAYER met2 ;
        RECT 96.230 0.000 96.510 4.000 ;
    END
  END user_count_i[0]
  PIN user_count_i[1]
    DIRECTION INPUT ;
    USE SIGNAL ;
    ANTENNAGATEAREA 0.495000 ;
    PORT
      LAYER met2 ;
        RECT 113.710 0.000 113.990 4.000 ;
    END
  END user_count_i[1]
  PIN user_count_i[2]
    DIRECTION INPUT ;
    USE SIGNAL ;
    ANTENNAGATEAREA 0.213000 ;
    PORT
      LAYER met2 ;
        RECT 131.190 0.000 131.470 4.000 ;
    END
  END user_count_i[2]
  PIN user_count_i[3]
    DIRECTION INPUT ;
    USE SIGNAL ;
    ANTENNAGATEAREA 0.126000 ;
    PORT
      LAYER met2 ;
        RECT 148.670 0.000 148.950 4.000 ;
    END
  END user_count_i[3]
  PIN v0z[0]
    DIRECTION INPUT ;
    USE SIGNAL ;
    ANTENNAGATEAREA 0.196500 ;
    PORT
      LAYER met2 ;
        RECT 613.270 0.000 613.550 4.000 ;
    END
  END v0z[0]
  PIN v0z[10]
    DIRECTION INPUT ;
    USE SIGNAL ;
    ANTENNAGATEAREA 0.196500 ;
    PORT
      LAYER met2 ;
        RECT 640.870 0.000 641.150 4.000 ;
    END
  END v0z[10]
  PIN v0z[11]
    DIRECTION INPUT ;
    USE SIGNAL ;
    ANTENNAGATEAREA 0.196500 ;
    PORT
      LAYER met2 ;
        RECT 643.630 0.000 643.910 4.000 ;
    END
  END v0z[11]
  PIN v0z[12]
    DIRECTION INPUT ;
    USE SIGNAL ;
    ANTENNAGATEAREA 0.196500 ;
    PORT
      LAYER met2 ;
        RECT 646.390 0.000 646.670 4.000 ;
    END
  END v0z[12]
  PIN v0z[13]
    DIRECTION INPUT ;
    USE SIGNAL ;
    ANTENNAGATEAREA 0.196500 ;
    PORT
      LAYER met2 ;
        RECT 649.150 0.000 649.430 4.000 ;
    END
  END v0z[13]
  PIN v0z[14]
    DIRECTION INPUT ;
    USE SIGNAL ;
    ANTENNAGATEAREA 0.196500 ;
    PORT
      LAYER met2 ;
        RECT 651.910 0.000 652.190 4.000 ;
    END
  END v0z[14]
  PIN v0z[15]
    DIRECTION INPUT ;
    USE SIGNAL ;
    ANTENNAGATEAREA 0.196500 ;
    PORT
      LAYER met2 ;
        RECT 654.670 0.000 654.950 4.000 ;
    END
  END v0z[15]
  PIN v0z[16]
    DIRECTION INPUT ;
    USE SIGNAL ;
    ANTENNAGATEAREA 0.196500 ;
    PORT
      LAYER met2 ;
        RECT 657.430 0.000 657.710 4.000 ;
    END
  END v0z[16]
  PIN v0z[17]
    DIRECTION INPUT ;
    USE SIGNAL ;
    ANTENNAGATEAREA 0.196500 ;
    PORT
      LAYER met2 ;
        RECT 660.190 0.000 660.470 4.000 ;
    END
  END v0z[17]
  PIN v0z[18]
    DIRECTION INPUT ;
    USE SIGNAL ;
    ANTENNAGATEAREA 0.196500 ;
    PORT
      LAYER met2 ;
        RECT 662.950 0.000 663.230 4.000 ;
    END
  END v0z[18]
  PIN v0z[19]
    DIRECTION INPUT ;
    USE SIGNAL ;
    ANTENNAGATEAREA 0.196500 ;
    PORT
      LAYER met2 ;
        RECT 665.710 0.000 665.990 4.000 ;
    END
  END v0z[19]
  PIN v0z[1]
    DIRECTION INPUT ;
    USE SIGNAL ;
    ANTENNAGATEAREA 0.196500 ;
    PORT
      LAYER met2 ;
        RECT 616.030 0.000 616.310 4.000 ;
    END
  END v0z[1]
  PIN v0z[20]
    DIRECTION INPUT ;
    USE SIGNAL ;
    ANTENNAGATEAREA 0.196500 ;
    PORT
      LAYER met2 ;
        RECT 668.470 0.000 668.750 4.000 ;
    END
  END v0z[20]
  PIN v0z[21]
    DIRECTION INPUT ;
    USE SIGNAL ;
    ANTENNAGATEAREA 0.196500 ;
    PORT
      LAYER met2 ;
        RECT 671.230 0.000 671.510 4.000 ;
    END
  END v0z[21]
  PIN v0z[22]
    DIRECTION INPUT ;
    USE SIGNAL ;
    ANTENNAGATEAREA 0.196500 ;
    PORT
      LAYER met2 ;
        RECT 673.990 0.000 674.270 4.000 ;
    END
  END v0z[22]
  PIN v0z[23]
    DIRECTION INPUT ;
    USE SIGNAL ;
    ANTENNAGATEAREA 0.196500 ;
    PORT
      LAYER met2 ;
        RECT 676.750 0.000 677.030 4.000 ;
    END
  END v0z[23]
  PIN v0z[24]
    DIRECTION INPUT ;
    USE SIGNAL ;
    ANTENNAGATEAREA 0.196500 ;
    PORT
      LAYER met2 ;
        RECT 679.510 0.000 679.790 4.000 ;
    END
  END v0z[24]
  PIN v0z[25]
    DIRECTION INPUT ;
    USE SIGNAL ;
    ANTENNAGATEAREA 0.196500 ;
    PORT
      LAYER met2 ;
        RECT 682.270 0.000 682.550 4.000 ;
    END
  END v0z[25]
  PIN v0z[26]
    DIRECTION INPUT ;
    USE SIGNAL ;
    ANTENNAGATEAREA 0.196500 ;
    PORT
      LAYER met2 ;
        RECT 685.030 0.000 685.310 4.000 ;
    END
  END v0z[26]
  PIN v0z[27]
    DIRECTION INPUT ;
    USE SIGNAL ;
    ANTENNAGATEAREA 0.196500 ;
    PORT
      LAYER met2 ;
        RECT 687.790 0.000 688.070 4.000 ;
    END
  END v0z[27]
  PIN v0z[28]
    DIRECTION INPUT ;
    USE SIGNAL ;
    ANTENNAGATEAREA 0.196500 ;
    PORT
      LAYER met2 ;
        RECT 690.550 0.000 690.830 4.000 ;
    END
  END v0z[28]
  PIN v0z[29]
    DIRECTION INPUT ;
    USE SIGNAL ;
    ANTENNAGATEAREA 0.196500 ;
    PORT
      LAYER met2 ;
        RECT 693.310 0.000 693.590 4.000 ;
    END
  END v0z[29]
  PIN v0z[2]
    DIRECTION INPUT ;
    USE SIGNAL ;
    ANTENNAGATEAREA 0.196500 ;
    PORT
      LAYER met2 ;
        RECT 618.790 0.000 619.070 4.000 ;
    END
  END v0z[2]
  PIN v0z[30]
    DIRECTION INPUT ;
    USE SIGNAL ;
    ANTENNAGATEAREA 0.196500 ;
    PORT
      LAYER met2 ;
        RECT 696.070 0.000 696.350 4.000 ;
    END
  END v0z[30]
  PIN v0z[31]
    DIRECTION INPUT ;
    USE SIGNAL ;
    ANTENNAGATEAREA 0.196500 ;
    PORT
      LAYER met2 ;
        RECT 698.830 0.000 699.110 4.000 ;
    END
  END v0z[31]
  PIN v0z[3]
    DIRECTION INPUT ;
    USE SIGNAL ;
    ANTENNAGATEAREA 0.196500 ;
    PORT
      LAYER met2 ;
        RECT 621.550 0.000 621.830 4.000 ;
    END
  END v0z[3]
  PIN v0z[4]
    DIRECTION INPUT ;
    USE SIGNAL ;
    ANTENNAGATEAREA 0.196500 ;
    PORT
      LAYER met2 ;
        RECT 624.310 0.000 624.590 4.000 ;
    END
  END v0z[4]
  PIN v0z[5]
    DIRECTION INPUT ;
    USE SIGNAL ;
    ANTENNAGATEAREA 0.196500 ;
    PORT
      LAYER met2 ;
        RECT 627.070 0.000 627.350 4.000 ;
    END
  END v0z[5]
  PIN v0z[6]
    DIRECTION INPUT ;
    USE SIGNAL ;
    ANTENNAGATEAREA 0.196500 ;
    PORT
      LAYER met2 ;
        RECT 629.830 0.000 630.110 4.000 ;
    END
  END v0z[6]
  PIN v0z[7]
    DIRECTION INPUT ;
    USE SIGNAL ;
    ANTENNAGATEAREA 0.196500 ;
    PORT
      LAYER met2 ;
        RECT 632.590 0.000 632.870 4.000 ;
    END
  END v0z[7]
  PIN v0z[8]
    DIRECTION INPUT ;
    USE SIGNAL ;
    ANTENNAGATEAREA 0.196500 ;
    PORT
      LAYER met2 ;
        RECT 635.350 0.000 635.630 4.000 ;
    END
  END v0z[8]
  PIN v0z[9]
    DIRECTION INPUT ;
    USE SIGNAL ;
    ANTENNAGATEAREA 0.196500 ;
    PORT
      LAYER met2 ;
        RECT 638.110 0.000 638.390 4.000 ;
    END
  END v0z[9]
  PIN v1z[0]
    DIRECTION INPUT ;
    USE SIGNAL ;
    ANTENNAGATEAREA 0.196500 ;
    PORT
      LAYER met2 ;
        RECT 614.190 0.000 614.470 4.000 ;
    END
  END v1z[0]
  PIN v1z[10]
    DIRECTION INPUT ;
    USE SIGNAL ;
    ANTENNAGATEAREA 0.196500 ;
    PORT
      LAYER met2 ;
        RECT 641.790 0.000 642.070 4.000 ;
    END
  END v1z[10]
  PIN v1z[11]
    DIRECTION INPUT ;
    USE SIGNAL ;
    ANTENNAGATEAREA 0.196500 ;
    PORT
      LAYER met2 ;
        RECT 644.550 0.000 644.830 4.000 ;
    END
  END v1z[11]
  PIN v1z[12]
    DIRECTION INPUT ;
    USE SIGNAL ;
    ANTENNAGATEAREA 0.196500 ;
    PORT
      LAYER met2 ;
        RECT 647.310 0.000 647.590 4.000 ;
    END
  END v1z[12]
  PIN v1z[13]
    DIRECTION INPUT ;
    USE SIGNAL ;
    ANTENNAGATEAREA 0.196500 ;
    PORT
      LAYER met2 ;
        RECT 650.070 0.000 650.350 4.000 ;
    END
  END v1z[13]
  PIN v1z[14]
    DIRECTION INPUT ;
    USE SIGNAL ;
    ANTENNAGATEAREA 0.196500 ;
    PORT
      LAYER met2 ;
        RECT 652.830 0.000 653.110 4.000 ;
    END
  END v1z[14]
  PIN v1z[15]
    DIRECTION INPUT ;
    USE SIGNAL ;
    ANTENNAGATEAREA 0.196500 ;
    PORT
      LAYER met2 ;
        RECT 655.590 0.000 655.870 4.000 ;
    END
  END v1z[15]
  PIN v1z[16]
    DIRECTION INPUT ;
    USE SIGNAL ;
    ANTENNAGATEAREA 0.196500 ;
    PORT
      LAYER met2 ;
        RECT 658.350 0.000 658.630 4.000 ;
    END
  END v1z[16]
  PIN v1z[17]
    DIRECTION INPUT ;
    USE SIGNAL ;
    ANTENNAGATEAREA 0.196500 ;
    PORT
      LAYER met2 ;
        RECT 661.110 0.000 661.390 4.000 ;
    END
  END v1z[17]
  PIN v1z[18]
    DIRECTION INPUT ;
    USE SIGNAL ;
    ANTENNAGATEAREA 0.196500 ;
    PORT
      LAYER met2 ;
        RECT 663.870 0.000 664.150 4.000 ;
    END
  END v1z[18]
  PIN v1z[19]
    DIRECTION INPUT ;
    USE SIGNAL ;
    ANTENNAGATEAREA 0.196500 ;
    PORT
      LAYER met2 ;
        RECT 666.630 0.000 666.910 4.000 ;
    END
  END v1z[19]
  PIN v1z[1]
    DIRECTION INPUT ;
    USE SIGNAL ;
    ANTENNAGATEAREA 0.196500 ;
    PORT
      LAYER met2 ;
        RECT 616.950 0.000 617.230 4.000 ;
    END
  END v1z[1]
  PIN v1z[20]
    DIRECTION INPUT ;
    USE SIGNAL ;
    ANTENNAGATEAREA 0.196500 ;
    PORT
      LAYER met2 ;
        RECT 669.390 0.000 669.670 4.000 ;
    END
  END v1z[20]
  PIN v1z[21]
    DIRECTION INPUT ;
    USE SIGNAL ;
    ANTENNAGATEAREA 0.196500 ;
    PORT
      LAYER met2 ;
        RECT 672.150 0.000 672.430 4.000 ;
    END
  END v1z[21]
  PIN v1z[22]
    DIRECTION INPUT ;
    USE SIGNAL ;
    ANTENNAGATEAREA 0.196500 ;
    PORT
      LAYER met2 ;
        RECT 674.910 0.000 675.190 4.000 ;
    END
  END v1z[22]
  PIN v1z[23]
    DIRECTION INPUT ;
    USE SIGNAL ;
    ANTENNAGATEAREA 0.196500 ;
    PORT
      LAYER met2 ;
        RECT 677.670 0.000 677.950 4.000 ;
    END
  END v1z[23]
  PIN v1z[24]
    DIRECTION INPUT ;
    USE SIGNAL ;
    ANTENNAGATEAREA 0.196500 ;
    PORT
      LAYER met2 ;
        RECT 680.430 0.000 680.710 4.000 ;
    END
  END v1z[24]
  PIN v1z[25]
    DIRECTION INPUT ;
    USE SIGNAL ;
    ANTENNAGATEAREA 0.196500 ;
    PORT
      LAYER met2 ;
        RECT 683.190 0.000 683.470 4.000 ;
    END
  END v1z[25]
  PIN v1z[26]
    DIRECTION INPUT ;
    USE SIGNAL ;
    ANTENNAGATEAREA 0.196500 ;
    PORT
      LAYER met2 ;
        RECT 685.950 0.000 686.230 4.000 ;
    END
  END v1z[26]
  PIN v1z[27]
    DIRECTION INPUT ;
    USE SIGNAL ;
    ANTENNAGATEAREA 0.196500 ;
    PORT
      LAYER met2 ;
        RECT 688.710 0.000 688.990 4.000 ;
    END
  END v1z[27]
  PIN v1z[28]
    DIRECTION INPUT ;
    USE SIGNAL ;
    ANTENNAGATEAREA 0.196500 ;
    PORT
      LAYER met2 ;
        RECT 691.470 0.000 691.750 4.000 ;
    END
  END v1z[28]
  PIN v1z[29]
    DIRECTION INPUT ;
    USE SIGNAL ;
    ANTENNAGATEAREA 0.196500 ;
    PORT
      LAYER met2 ;
        RECT 694.230 0.000 694.510 4.000 ;
    END
  END v1z[29]
  PIN v1z[2]
    DIRECTION INPUT ;
    USE SIGNAL ;
    ANTENNAGATEAREA 0.196500 ;
    PORT
      LAYER met2 ;
        RECT 619.710 0.000 619.990 4.000 ;
    END
  END v1z[2]
  PIN v1z[30]
    DIRECTION INPUT ;
    USE SIGNAL ;
    ANTENNAGATEAREA 0.196500 ;
    PORT
      LAYER met2 ;
        RECT 696.990 0.000 697.270 4.000 ;
    END
  END v1z[30]
  PIN v1z[31]
    DIRECTION INPUT ;
    USE SIGNAL ;
    ANTENNAGATEAREA 0.196500 ;
    PORT
      LAYER met2 ;
        RECT 699.750 0.000 700.030 4.000 ;
    END
  END v1z[31]
  PIN v1z[3]
    DIRECTION INPUT ;
    USE SIGNAL ;
    ANTENNAGATEAREA 0.196500 ;
    PORT
      LAYER met2 ;
        RECT 622.470 0.000 622.750 4.000 ;
    END
  END v1z[3]
  PIN v1z[4]
    DIRECTION INPUT ;
    USE SIGNAL ;
    ANTENNAGATEAREA 0.196500 ;
    PORT
      LAYER met2 ;
        RECT 625.230 0.000 625.510 4.000 ;
    END
  END v1z[4]
  PIN v1z[5]
    DIRECTION INPUT ;
    USE SIGNAL ;
    ANTENNAGATEAREA 0.196500 ;
    PORT
      LAYER met2 ;
        RECT 627.990 0.000 628.270 4.000 ;
    END
  END v1z[5]
  PIN v1z[6]
    DIRECTION INPUT ;
    USE SIGNAL ;
    ANTENNAGATEAREA 0.196500 ;
    PORT
      LAYER met2 ;
        RECT 630.750 0.000 631.030 4.000 ;
    END
  END v1z[6]
  PIN v1z[7]
    DIRECTION INPUT ;
    USE SIGNAL ;
    ANTENNAGATEAREA 0.196500 ;
    PORT
      LAYER met2 ;
        RECT 633.510 0.000 633.790 4.000 ;
    END
  END v1z[7]
  PIN v1z[8]
    DIRECTION INPUT ;
    USE SIGNAL ;
    ANTENNAGATEAREA 0.196500 ;
    PORT
      LAYER met2 ;
        RECT 636.270 0.000 636.550 4.000 ;
    END
  END v1z[8]
  PIN v1z[9]
    DIRECTION INPUT ;
    USE SIGNAL ;
    ANTENNAGATEAREA 0.196500 ;
    PORT
      LAYER met2 ;
        RECT 639.030 0.000 639.310 4.000 ;
    END
  END v1z[9]
  PIN v2z[0]
    DIRECTION INPUT ;
    USE SIGNAL ;
    ANTENNAGATEAREA 0.196500 ;
    PORT
      LAYER met2 ;
        RECT 615.110 0.000 615.390 4.000 ;
    END
  END v2z[0]
  PIN v2z[10]
    DIRECTION INPUT ;
    USE SIGNAL ;
    ANTENNAGATEAREA 0.196500 ;
    PORT
      LAYER met2 ;
        RECT 642.710 0.000 642.990 4.000 ;
    END
  END v2z[10]
  PIN v2z[11]
    DIRECTION INPUT ;
    USE SIGNAL ;
    ANTENNAGATEAREA 0.196500 ;
    PORT
      LAYER met2 ;
        RECT 645.470 0.000 645.750 4.000 ;
    END
  END v2z[11]
  PIN v2z[12]
    DIRECTION INPUT ;
    USE SIGNAL ;
    ANTENNAGATEAREA 0.196500 ;
    PORT
      LAYER met2 ;
        RECT 648.230 0.000 648.510 4.000 ;
    END
  END v2z[12]
  PIN v2z[13]
    DIRECTION INPUT ;
    USE SIGNAL ;
    ANTENNAGATEAREA 0.196500 ;
    PORT
      LAYER met2 ;
        RECT 650.990 0.000 651.270 4.000 ;
    END
  END v2z[13]
  PIN v2z[14]
    DIRECTION INPUT ;
    USE SIGNAL ;
    ANTENNAGATEAREA 0.196500 ;
    PORT
      LAYER met2 ;
        RECT 653.750 0.000 654.030 4.000 ;
    END
  END v2z[14]
  PIN v2z[15]
    DIRECTION INPUT ;
    USE SIGNAL ;
    ANTENNAGATEAREA 0.196500 ;
    PORT
      LAYER met2 ;
        RECT 656.510 0.000 656.790 4.000 ;
    END
  END v2z[15]
  PIN v2z[16]
    DIRECTION INPUT ;
    USE SIGNAL ;
    ANTENNAGATEAREA 0.196500 ;
    PORT
      LAYER met2 ;
        RECT 659.270 0.000 659.550 4.000 ;
    END
  END v2z[16]
  PIN v2z[17]
    DIRECTION INPUT ;
    USE SIGNAL ;
    ANTENNAGATEAREA 0.196500 ;
    PORT
      LAYER met2 ;
        RECT 662.030 0.000 662.310 4.000 ;
    END
  END v2z[17]
  PIN v2z[18]
    DIRECTION INPUT ;
    USE SIGNAL ;
    ANTENNAGATEAREA 0.196500 ;
    PORT
      LAYER met2 ;
        RECT 664.790 0.000 665.070 4.000 ;
    END
  END v2z[18]
  PIN v2z[19]
    DIRECTION INPUT ;
    USE SIGNAL ;
    ANTENNAGATEAREA 0.196500 ;
    PORT
      LAYER met2 ;
        RECT 667.550 0.000 667.830 4.000 ;
    END
  END v2z[19]
  PIN v2z[1]
    DIRECTION INPUT ;
    USE SIGNAL ;
    ANTENNAGATEAREA 0.196500 ;
    PORT
      LAYER met2 ;
        RECT 617.870 0.000 618.150 4.000 ;
    END
  END v2z[1]
  PIN v2z[20]
    DIRECTION INPUT ;
    USE SIGNAL ;
    ANTENNAGATEAREA 0.196500 ;
    PORT
      LAYER met2 ;
        RECT 670.310 0.000 670.590 4.000 ;
    END
  END v2z[20]
  PIN v2z[21]
    DIRECTION INPUT ;
    USE SIGNAL ;
    ANTENNAGATEAREA 0.196500 ;
    PORT
      LAYER met2 ;
        RECT 673.070 0.000 673.350 4.000 ;
    END
  END v2z[21]
  PIN v2z[22]
    DIRECTION INPUT ;
    USE SIGNAL ;
    ANTENNAGATEAREA 0.196500 ;
    PORT
      LAYER met2 ;
        RECT 675.830 0.000 676.110 4.000 ;
    END
  END v2z[22]
  PIN v2z[23]
    DIRECTION INPUT ;
    USE SIGNAL ;
    ANTENNAGATEAREA 0.196500 ;
    PORT
      LAYER met2 ;
        RECT 678.590 0.000 678.870 4.000 ;
    END
  END v2z[23]
  PIN v2z[24]
    DIRECTION INPUT ;
    USE SIGNAL ;
    ANTENNAGATEAREA 0.196500 ;
    PORT
      LAYER met2 ;
        RECT 681.350 0.000 681.630 4.000 ;
    END
  END v2z[24]
  PIN v2z[25]
    DIRECTION INPUT ;
    USE SIGNAL ;
    ANTENNAGATEAREA 0.196500 ;
    PORT
      LAYER met2 ;
        RECT 684.110 0.000 684.390 4.000 ;
    END
  END v2z[25]
  PIN v2z[26]
    DIRECTION INPUT ;
    USE SIGNAL ;
    ANTENNAGATEAREA 0.196500 ;
    PORT
      LAYER met2 ;
        RECT 686.870 0.000 687.150 4.000 ;
    END
  END v2z[26]
  PIN v2z[27]
    DIRECTION INPUT ;
    USE SIGNAL ;
    ANTENNAGATEAREA 0.196500 ;
    PORT
      LAYER met2 ;
        RECT 689.630 0.000 689.910 4.000 ;
    END
  END v2z[27]
  PIN v2z[28]
    DIRECTION INPUT ;
    USE SIGNAL ;
    ANTENNAGATEAREA 0.196500 ;
    PORT
      LAYER met2 ;
        RECT 692.390 0.000 692.670 4.000 ;
    END
  END v2z[28]
  PIN v2z[29]
    DIRECTION INPUT ;
    USE SIGNAL ;
    ANTENNAGATEAREA 0.196500 ;
    PORT
      LAYER met2 ;
        RECT 695.150 0.000 695.430 4.000 ;
    END
  END v2z[29]
  PIN v2z[2]
    DIRECTION INPUT ;
    USE SIGNAL ;
    ANTENNAGATEAREA 0.196500 ;
    PORT
      LAYER met2 ;
        RECT 620.630 0.000 620.910 4.000 ;
    END
  END v2z[2]
  PIN v2z[30]
    DIRECTION INPUT ;
    USE SIGNAL ;
    ANTENNAGATEAREA 0.196500 ;
    PORT
      LAYER met2 ;
        RECT 697.910 0.000 698.190 4.000 ;
    END
  END v2z[30]
  PIN v2z[31]
    DIRECTION INPUT ;
    USE SIGNAL ;
    ANTENNAGATEAREA 0.196500 ;
    PORT
      LAYER met2 ;
        RECT 700.670 0.000 700.950 4.000 ;
    END
  END v2z[31]
  PIN v2z[3]
    DIRECTION INPUT ;
    USE SIGNAL ;
    ANTENNAGATEAREA 0.196500 ;
    PORT
      LAYER met2 ;
        RECT 623.390 0.000 623.670 4.000 ;
    END
  END v2z[3]
  PIN v2z[4]
    DIRECTION INPUT ;
    USE SIGNAL ;
    ANTENNAGATEAREA 0.196500 ;
    PORT
      LAYER met2 ;
        RECT 626.150 0.000 626.430 4.000 ;
    END
  END v2z[4]
  PIN v2z[5]
    DIRECTION INPUT ;
    USE SIGNAL ;
    ANTENNAGATEAREA 0.196500 ;
    PORT
      LAYER met2 ;
        RECT 628.910 0.000 629.190 4.000 ;
    END
  END v2z[5]
  PIN v2z[6]
    DIRECTION INPUT ;
    USE SIGNAL ;
    ANTENNAGATEAREA 0.196500 ;
    PORT
      LAYER met2 ;
        RECT 631.670 0.000 631.950 4.000 ;
    END
  END v2z[6]
  PIN v2z[7]
    DIRECTION INPUT ;
    USE SIGNAL ;
    ANTENNAGATEAREA 0.196500 ;
    PORT
      LAYER met2 ;
        RECT 634.430 0.000 634.710 4.000 ;
    END
  END v2z[7]
  PIN v2z[8]
    DIRECTION INPUT ;
    USE SIGNAL ;
    ANTENNAGATEAREA 0.196500 ;
    PORT
      LAYER met2 ;
        RECT 637.190 0.000 637.470 4.000 ;
    END
  END v2z[8]
  PIN v2z[9]
    DIRECTION INPUT ;
    USE SIGNAL ;
    ANTENNAGATEAREA 0.196500 ;
    PORT
      LAYER met2 ;
        RECT 639.950 0.000 640.230 4.000 ;
    END
  END v2z[9]
  PIN vccd1
    DIRECTION INOUT ;
    USE POWER ;
    PORT
      LAYER met4 ;
        RECT -2.080 3.280 -0.480 494.480 ;
    END
    PORT
      LAYER met5 ;
        RECT -2.080 3.280 751.880 4.880 ;
    END
    PORT
      LAYER met5 ;
        RECT -2.080 492.880 751.880 494.480 ;
    END
    PORT
      LAYER met4 ;
        RECT 750.280 3.280 751.880 494.480 ;
    END
    PORT
      LAYER met4 ;
        RECT 21.040 -0.020 22.640 497.780 ;
    END
    PORT
      LAYER met4 ;
        RECT 174.640 -0.020 176.240 497.780 ;
    END
    PORT
      LAYER met4 ;
        RECT 328.240 -0.020 329.840 497.780 ;
    END
    PORT
      LAYER met4 ;
        RECT 481.840 -0.020 483.440 497.780 ;
    END
    PORT
      LAYER met4 ;
        RECT 635.440 -0.020 637.040 497.780 ;
    END
    PORT
      LAYER met5 ;
        RECT -5.380 26.730 755.180 28.330 ;
    END
    PORT
      LAYER met5 ;
        RECT -5.380 179.910 755.180 181.510 ;
    END
    PORT
      LAYER met5 ;
        RECT -5.380 333.090 755.180 334.690 ;
    END
  END vccd1
  PIN vssd1
    DIRECTION INOUT ;
    USE GROUND ;
    PORT
      LAYER met4 ;
        RECT -5.380 -0.020 -3.780 497.780 ;
    END
    PORT
      LAYER met5 ;
        RECT -5.380 -0.020 755.180 1.580 ;
    END
    PORT
      LAYER met5 ;
        RECT -5.380 496.180 755.180 497.780 ;
    END
    PORT
      LAYER met4 ;
        RECT 753.580 -0.020 755.180 497.780 ;
    END
    PORT
      LAYER met4 ;
        RECT 24.340 -0.020 25.940 497.780 ;
    END
    PORT
      LAYER met4 ;
        RECT 177.940 -0.020 179.540 497.780 ;
    END
    PORT
      LAYER met4 ;
        RECT 331.540 -0.020 333.140 497.780 ;
    END
    PORT
      LAYER met4 ;
        RECT 485.140 -0.020 486.740 497.780 ;
    END
    PORT
      LAYER met4 ;
        RECT 638.740 -0.020 640.340 497.780 ;
    END
    PORT
      LAYER met5 ;
        RECT -5.380 30.030 755.180 31.630 ;
    END
    PORT
      LAYER met5 ;
        RECT -5.380 183.210 755.180 184.810 ;
    END
    PORT
      LAYER met5 ;
        RECT -5.380 336.390 755.180 337.990 ;
    END
  END vssd1
  OBS
      LAYER li1 ;
        RECT 5.520 10.795 744.280 486.965 ;
      LAYER met1 ;
        RECT 4.670 4.460 749.730 491.600 ;
      LAYER met2 ;
        RECT 4.690 495.720 30.630 496.810 ;
        RECT 31.470 495.720 32.930 496.810 ;
        RECT 33.770 495.720 35.230 496.810 ;
        RECT 36.070 495.720 37.530 496.810 ;
        RECT 38.370 495.720 39.830 496.810 ;
        RECT 40.670 495.720 42.130 496.810 ;
        RECT 42.970 495.720 44.430 496.810 ;
        RECT 45.270 495.720 46.730 496.810 ;
        RECT 47.570 495.720 49.030 496.810 ;
        RECT 49.870 495.720 51.330 496.810 ;
        RECT 52.170 495.720 53.630 496.810 ;
        RECT 54.470 495.720 55.930 496.810 ;
        RECT 56.770 495.720 58.230 496.810 ;
        RECT 59.070 495.720 60.530 496.810 ;
        RECT 61.370 495.720 62.830 496.810 ;
        RECT 63.670 495.720 65.130 496.810 ;
        RECT 65.970 495.720 67.430 496.810 ;
        RECT 68.270 495.720 69.730 496.810 ;
        RECT 70.570 495.720 72.030 496.810 ;
        RECT 72.870 495.720 74.330 496.810 ;
        RECT 75.170 495.720 76.630 496.810 ;
        RECT 77.470 495.720 78.930 496.810 ;
        RECT 79.770 495.720 81.230 496.810 ;
        RECT 82.070 495.720 83.530 496.810 ;
        RECT 84.370 495.720 85.830 496.810 ;
        RECT 86.670 495.720 88.130 496.810 ;
        RECT 88.970 495.720 90.430 496.810 ;
        RECT 91.270 495.720 92.730 496.810 ;
        RECT 93.570 495.720 95.030 496.810 ;
        RECT 95.870 495.720 97.330 496.810 ;
        RECT 98.170 495.720 99.630 496.810 ;
        RECT 100.470 495.720 101.930 496.810 ;
        RECT 102.770 495.720 104.230 496.810 ;
        RECT 105.070 495.720 106.530 496.810 ;
        RECT 107.370 495.720 108.830 496.810 ;
        RECT 109.670 495.720 111.130 496.810 ;
        RECT 111.970 495.720 113.430 496.810 ;
        RECT 114.270 495.720 115.730 496.810 ;
        RECT 116.570 495.720 118.030 496.810 ;
        RECT 118.870 495.720 120.330 496.810 ;
        RECT 121.170 495.720 122.630 496.810 ;
        RECT 123.470 495.720 124.930 496.810 ;
        RECT 125.770 495.720 127.230 496.810 ;
        RECT 128.070 495.720 129.530 496.810 ;
        RECT 130.370 495.720 131.830 496.810 ;
        RECT 132.670 495.720 134.130 496.810 ;
        RECT 134.970 495.720 136.430 496.810 ;
        RECT 137.270 495.720 138.730 496.810 ;
        RECT 139.570 495.720 141.030 496.810 ;
        RECT 141.870 495.720 143.330 496.810 ;
        RECT 144.170 495.720 145.630 496.810 ;
        RECT 146.470 495.720 147.930 496.810 ;
        RECT 148.770 495.720 150.230 496.810 ;
        RECT 151.070 495.720 152.530 496.810 ;
        RECT 153.370 495.720 154.830 496.810 ;
        RECT 155.670 495.720 157.130 496.810 ;
        RECT 157.970 495.720 159.430 496.810 ;
        RECT 160.270 495.720 161.730 496.810 ;
        RECT 162.570 495.720 164.030 496.810 ;
        RECT 164.870 495.720 166.330 496.810 ;
        RECT 167.170 495.720 168.630 496.810 ;
        RECT 169.470 495.720 170.930 496.810 ;
        RECT 171.770 495.720 173.230 496.810 ;
        RECT 174.070 495.720 175.530 496.810 ;
        RECT 176.370 495.720 177.830 496.810 ;
        RECT 178.670 495.720 180.130 496.810 ;
        RECT 180.970 495.720 182.430 496.810 ;
        RECT 183.270 495.720 184.730 496.810 ;
        RECT 185.570 495.720 187.030 496.810 ;
        RECT 187.870 495.720 189.330 496.810 ;
        RECT 190.170 495.720 191.630 496.810 ;
        RECT 192.470 495.720 193.930 496.810 ;
        RECT 194.770 495.720 196.230 496.810 ;
        RECT 197.070 495.720 198.530 496.810 ;
        RECT 199.370 495.720 200.830 496.810 ;
        RECT 201.670 495.720 203.130 496.810 ;
        RECT 203.970 495.720 205.430 496.810 ;
        RECT 206.270 495.720 207.730 496.810 ;
        RECT 208.570 495.720 210.030 496.810 ;
        RECT 210.870 495.720 212.330 496.810 ;
        RECT 213.170 495.720 214.630 496.810 ;
        RECT 215.470 495.720 216.930 496.810 ;
        RECT 217.770 495.720 219.230 496.810 ;
        RECT 220.070 495.720 221.530 496.810 ;
        RECT 222.370 495.720 223.830 496.810 ;
        RECT 224.670 495.720 226.130 496.810 ;
        RECT 226.970 495.720 228.430 496.810 ;
        RECT 229.270 495.720 230.730 496.810 ;
        RECT 231.570 495.720 233.030 496.810 ;
        RECT 233.870 495.720 235.330 496.810 ;
        RECT 236.170 495.720 237.630 496.810 ;
        RECT 238.470 495.720 239.930 496.810 ;
        RECT 240.770 495.720 242.230 496.810 ;
        RECT 243.070 495.720 244.530 496.810 ;
        RECT 245.370 495.720 246.830 496.810 ;
        RECT 247.670 495.720 249.130 496.810 ;
        RECT 249.970 495.720 251.430 496.810 ;
        RECT 252.270 495.720 253.730 496.810 ;
        RECT 254.570 495.720 256.030 496.810 ;
        RECT 256.870 495.720 258.330 496.810 ;
        RECT 259.170 495.720 260.630 496.810 ;
        RECT 261.470 495.720 262.930 496.810 ;
        RECT 263.770 495.720 265.230 496.810 ;
        RECT 266.070 495.720 267.530 496.810 ;
        RECT 268.370 495.720 269.830 496.810 ;
        RECT 270.670 495.720 272.130 496.810 ;
        RECT 272.970 495.720 274.430 496.810 ;
        RECT 275.270 495.720 276.730 496.810 ;
        RECT 277.570 495.720 279.030 496.810 ;
        RECT 279.870 495.720 281.330 496.810 ;
        RECT 282.170 495.720 283.630 496.810 ;
        RECT 284.470 495.720 285.930 496.810 ;
        RECT 286.770 495.720 288.230 496.810 ;
        RECT 289.070 495.720 290.530 496.810 ;
        RECT 291.370 495.720 292.830 496.810 ;
        RECT 293.670 495.720 295.130 496.810 ;
        RECT 295.970 495.720 297.430 496.810 ;
        RECT 298.270 495.720 299.730 496.810 ;
        RECT 300.570 495.720 302.030 496.810 ;
        RECT 302.870 495.720 304.330 496.810 ;
        RECT 305.170 495.720 306.630 496.810 ;
        RECT 307.470 495.720 308.930 496.810 ;
        RECT 309.770 495.720 311.230 496.810 ;
        RECT 312.070 495.720 313.530 496.810 ;
        RECT 314.370 495.720 315.830 496.810 ;
        RECT 316.670 495.720 318.130 496.810 ;
        RECT 318.970 495.720 320.430 496.810 ;
        RECT 321.270 495.720 322.730 496.810 ;
        RECT 323.570 495.720 325.030 496.810 ;
        RECT 325.870 495.720 327.330 496.810 ;
        RECT 328.170 495.720 329.630 496.810 ;
        RECT 330.470 495.720 331.930 496.810 ;
        RECT 332.770 495.720 334.230 496.810 ;
        RECT 335.070 495.720 336.530 496.810 ;
        RECT 337.370 495.720 338.830 496.810 ;
        RECT 339.670 495.720 341.130 496.810 ;
        RECT 341.970 495.720 343.430 496.810 ;
        RECT 344.270 495.720 345.730 496.810 ;
        RECT 346.570 495.720 348.030 496.810 ;
        RECT 348.870 495.720 350.330 496.810 ;
        RECT 351.170 495.720 352.630 496.810 ;
        RECT 353.470 495.720 354.930 496.810 ;
        RECT 355.770 495.720 357.230 496.810 ;
        RECT 358.070 495.720 359.530 496.810 ;
        RECT 360.370 495.720 361.830 496.810 ;
        RECT 362.670 495.720 364.130 496.810 ;
        RECT 364.970 495.720 366.430 496.810 ;
        RECT 367.270 495.720 368.730 496.810 ;
        RECT 369.570 495.720 371.030 496.810 ;
        RECT 371.870 495.720 373.330 496.810 ;
        RECT 374.170 495.720 375.630 496.810 ;
        RECT 376.470 495.720 377.930 496.810 ;
        RECT 378.770 495.720 380.230 496.810 ;
        RECT 381.070 495.720 382.530 496.810 ;
        RECT 383.370 495.720 384.830 496.810 ;
        RECT 385.670 495.720 387.130 496.810 ;
        RECT 387.970 495.720 389.430 496.810 ;
        RECT 390.270 495.720 391.730 496.810 ;
        RECT 392.570 495.720 394.030 496.810 ;
        RECT 394.870 495.720 396.330 496.810 ;
        RECT 397.170 495.720 398.630 496.810 ;
        RECT 399.470 495.720 400.930 496.810 ;
        RECT 401.770 495.720 403.230 496.810 ;
        RECT 404.070 495.720 405.530 496.810 ;
        RECT 406.370 495.720 407.830 496.810 ;
        RECT 408.670 495.720 410.130 496.810 ;
        RECT 410.970 495.720 412.430 496.810 ;
        RECT 413.270 495.720 414.730 496.810 ;
        RECT 415.570 495.720 417.030 496.810 ;
        RECT 417.870 495.720 419.330 496.810 ;
        RECT 420.170 495.720 421.630 496.810 ;
        RECT 422.470 495.720 423.930 496.810 ;
        RECT 424.770 495.720 426.230 496.810 ;
        RECT 427.070 495.720 428.530 496.810 ;
        RECT 429.370 495.720 430.830 496.810 ;
        RECT 431.670 495.720 433.130 496.810 ;
        RECT 433.970 495.720 435.430 496.810 ;
        RECT 436.270 495.720 437.730 496.810 ;
        RECT 438.570 495.720 440.030 496.810 ;
        RECT 440.870 495.720 442.330 496.810 ;
        RECT 443.170 495.720 444.630 496.810 ;
        RECT 445.470 495.720 446.930 496.810 ;
        RECT 447.770 495.720 449.230 496.810 ;
        RECT 450.070 495.720 451.530 496.810 ;
        RECT 452.370 495.720 453.830 496.810 ;
        RECT 454.670 495.720 456.130 496.810 ;
        RECT 456.970 495.720 458.430 496.810 ;
        RECT 459.270 495.720 460.730 496.810 ;
        RECT 461.570 495.720 463.030 496.810 ;
        RECT 463.870 495.720 465.330 496.810 ;
        RECT 466.170 495.720 467.630 496.810 ;
        RECT 468.470 495.720 469.930 496.810 ;
        RECT 470.770 495.720 472.230 496.810 ;
        RECT 473.070 495.720 474.530 496.810 ;
        RECT 475.370 495.720 476.830 496.810 ;
        RECT 477.670 495.720 479.130 496.810 ;
        RECT 479.970 495.720 481.430 496.810 ;
        RECT 482.270 495.720 483.730 496.810 ;
        RECT 484.570 495.720 486.030 496.810 ;
        RECT 486.870 495.720 488.330 496.810 ;
        RECT 489.170 495.720 490.630 496.810 ;
        RECT 491.470 495.720 492.930 496.810 ;
        RECT 493.770 495.720 495.230 496.810 ;
        RECT 496.070 495.720 497.530 496.810 ;
        RECT 498.370 495.720 499.830 496.810 ;
        RECT 500.670 495.720 502.130 496.810 ;
        RECT 502.970 495.720 504.430 496.810 ;
        RECT 505.270 495.720 506.730 496.810 ;
        RECT 507.570 495.720 509.030 496.810 ;
        RECT 509.870 495.720 511.330 496.810 ;
        RECT 512.170 495.720 513.630 496.810 ;
        RECT 514.470 495.720 515.930 496.810 ;
        RECT 516.770 495.720 518.230 496.810 ;
        RECT 519.070 495.720 520.530 496.810 ;
        RECT 521.370 495.720 522.830 496.810 ;
        RECT 523.670 495.720 525.130 496.810 ;
        RECT 525.970 495.720 527.430 496.810 ;
        RECT 528.270 495.720 529.730 496.810 ;
        RECT 530.570 495.720 532.030 496.810 ;
        RECT 532.870 495.720 534.330 496.810 ;
        RECT 535.170 495.720 536.630 496.810 ;
        RECT 537.470 495.720 538.930 496.810 ;
        RECT 539.770 495.720 541.230 496.810 ;
        RECT 542.070 495.720 543.530 496.810 ;
        RECT 544.370 495.720 545.830 496.810 ;
        RECT 546.670 495.720 548.130 496.810 ;
        RECT 548.970 495.720 550.430 496.810 ;
        RECT 551.270 495.720 552.730 496.810 ;
        RECT 553.570 495.720 555.030 496.810 ;
        RECT 555.870 495.720 557.330 496.810 ;
        RECT 558.170 495.720 559.630 496.810 ;
        RECT 560.470 495.720 561.930 496.810 ;
        RECT 562.770 495.720 564.230 496.810 ;
        RECT 565.070 495.720 566.530 496.810 ;
        RECT 567.370 495.720 568.830 496.810 ;
        RECT 569.670 495.720 571.130 496.810 ;
        RECT 571.970 495.720 573.430 496.810 ;
        RECT 574.270 495.720 575.730 496.810 ;
        RECT 576.570 495.720 578.030 496.810 ;
        RECT 578.870 495.720 580.330 496.810 ;
        RECT 581.170 495.720 582.630 496.810 ;
        RECT 583.470 495.720 584.930 496.810 ;
        RECT 585.770 495.720 587.230 496.810 ;
        RECT 588.070 495.720 589.530 496.810 ;
        RECT 590.370 495.720 591.830 496.810 ;
        RECT 592.670 495.720 594.130 496.810 ;
        RECT 594.970 495.720 596.430 496.810 ;
        RECT 597.270 495.720 598.730 496.810 ;
        RECT 599.570 495.720 601.030 496.810 ;
        RECT 601.870 495.720 603.330 496.810 ;
        RECT 604.170 495.720 605.630 496.810 ;
        RECT 606.470 495.720 607.930 496.810 ;
        RECT 608.770 495.720 610.230 496.810 ;
        RECT 611.070 495.720 612.530 496.810 ;
        RECT 613.370 495.720 614.830 496.810 ;
        RECT 615.670 495.720 617.130 496.810 ;
        RECT 617.970 495.720 619.430 496.810 ;
        RECT 620.270 495.720 621.730 496.810 ;
        RECT 622.570 495.720 624.030 496.810 ;
        RECT 624.870 495.720 626.330 496.810 ;
        RECT 627.170 495.720 628.630 496.810 ;
        RECT 629.470 495.720 630.930 496.810 ;
        RECT 631.770 495.720 633.230 496.810 ;
        RECT 634.070 495.720 635.530 496.810 ;
        RECT 636.370 495.720 637.830 496.810 ;
        RECT 638.670 495.720 640.130 496.810 ;
        RECT 640.970 495.720 642.430 496.810 ;
        RECT 643.270 495.720 644.730 496.810 ;
        RECT 645.570 495.720 647.030 496.810 ;
        RECT 647.870 495.720 649.330 496.810 ;
        RECT 650.170 495.720 651.630 496.810 ;
        RECT 652.470 495.720 653.930 496.810 ;
        RECT 654.770 495.720 656.230 496.810 ;
        RECT 657.070 495.720 658.530 496.810 ;
        RECT 659.370 495.720 660.830 496.810 ;
        RECT 661.670 495.720 663.130 496.810 ;
        RECT 663.970 495.720 665.430 496.810 ;
        RECT 666.270 495.720 667.730 496.810 ;
        RECT 668.570 495.720 670.030 496.810 ;
        RECT 670.870 495.720 672.330 496.810 ;
        RECT 673.170 495.720 674.630 496.810 ;
        RECT 675.470 495.720 676.930 496.810 ;
        RECT 677.770 495.720 679.230 496.810 ;
        RECT 680.070 495.720 681.530 496.810 ;
        RECT 682.370 495.720 683.830 496.810 ;
        RECT 684.670 495.720 686.130 496.810 ;
        RECT 686.970 495.720 688.430 496.810 ;
        RECT 689.270 495.720 690.730 496.810 ;
        RECT 691.570 495.720 693.030 496.810 ;
        RECT 693.870 495.720 695.330 496.810 ;
        RECT 696.170 495.720 697.630 496.810 ;
        RECT 698.470 495.720 699.930 496.810 ;
        RECT 700.770 495.720 702.230 496.810 ;
        RECT 703.070 495.720 704.530 496.810 ;
        RECT 705.370 495.720 706.830 496.810 ;
        RECT 707.670 495.720 709.130 496.810 ;
        RECT 709.970 495.720 711.430 496.810 ;
        RECT 712.270 495.720 713.730 496.810 ;
        RECT 714.570 495.720 716.030 496.810 ;
        RECT 716.870 495.720 718.330 496.810 ;
        RECT 719.170 495.720 749.700 496.810 ;
        RECT 4.690 4.280 749.700 495.720 ;
        RECT 4.690 3.555 48.110 4.280 ;
        RECT 48.950 3.555 49.030 4.280 ;
        RECT 49.870 3.555 49.950 4.280 ;
        RECT 50.790 3.555 50.870 4.280 ;
        RECT 51.710 3.555 51.790 4.280 ;
        RECT 52.630 3.555 52.710 4.280 ;
        RECT 53.550 3.555 53.630 4.280 ;
        RECT 54.470 3.555 54.550 4.280 ;
        RECT 55.390 3.555 55.470 4.280 ;
        RECT 56.310 3.555 56.390 4.280 ;
        RECT 57.230 3.555 57.310 4.280 ;
        RECT 58.150 3.555 58.230 4.280 ;
        RECT 59.070 3.555 59.150 4.280 ;
        RECT 59.990 3.555 60.070 4.280 ;
        RECT 60.910 3.555 60.990 4.280 ;
        RECT 61.830 3.555 61.910 4.280 ;
        RECT 62.750 3.555 62.830 4.280 ;
        RECT 63.670 3.555 63.750 4.280 ;
        RECT 64.590 3.555 64.670 4.280 ;
        RECT 65.510 3.555 65.590 4.280 ;
        RECT 66.430 3.555 66.510 4.280 ;
        RECT 67.350 3.555 67.430 4.280 ;
        RECT 68.270 3.555 68.350 4.280 ;
        RECT 69.190 3.555 69.270 4.280 ;
        RECT 70.110 3.555 70.190 4.280 ;
        RECT 71.030 3.555 71.110 4.280 ;
        RECT 71.950 3.555 72.030 4.280 ;
        RECT 72.870 3.555 72.950 4.280 ;
        RECT 73.790 3.555 73.870 4.280 ;
        RECT 74.710 3.555 74.790 4.280 ;
        RECT 75.630 3.555 75.710 4.280 ;
        RECT 76.550 3.555 76.630 4.280 ;
        RECT 77.470 3.555 77.550 4.280 ;
        RECT 78.390 3.555 78.470 4.280 ;
        RECT 79.310 3.555 79.390 4.280 ;
        RECT 80.230 3.555 80.310 4.280 ;
        RECT 81.150 3.555 81.230 4.280 ;
        RECT 82.070 3.555 82.150 4.280 ;
        RECT 82.990 3.555 83.070 4.280 ;
        RECT 83.910 3.555 83.990 4.280 ;
        RECT 84.830 3.555 84.910 4.280 ;
        RECT 85.750 3.555 85.830 4.280 ;
        RECT 86.670 3.555 86.750 4.280 ;
        RECT 87.590 3.555 87.670 4.280 ;
        RECT 88.510 3.555 88.590 4.280 ;
        RECT 89.430 3.555 89.510 4.280 ;
        RECT 90.350 3.555 90.430 4.280 ;
        RECT 91.270 3.555 91.350 4.280 ;
        RECT 92.190 3.555 92.270 4.280 ;
        RECT 93.110 3.555 93.190 4.280 ;
        RECT 94.030 3.555 94.110 4.280 ;
        RECT 94.950 3.555 95.030 4.280 ;
        RECT 95.870 3.555 95.950 4.280 ;
        RECT 96.790 3.555 96.870 4.280 ;
        RECT 97.710 3.555 97.790 4.280 ;
        RECT 98.630 3.555 98.710 4.280 ;
        RECT 99.550 3.555 99.630 4.280 ;
        RECT 100.470 3.555 100.550 4.280 ;
        RECT 101.390 3.555 101.470 4.280 ;
        RECT 102.310 3.555 102.390 4.280 ;
        RECT 103.230 3.555 103.310 4.280 ;
        RECT 104.150 3.555 104.230 4.280 ;
        RECT 105.070 3.555 105.150 4.280 ;
        RECT 105.990 3.555 106.070 4.280 ;
        RECT 106.910 3.555 106.990 4.280 ;
        RECT 107.830 3.555 107.910 4.280 ;
        RECT 108.750 3.555 108.830 4.280 ;
        RECT 109.670 3.555 109.750 4.280 ;
        RECT 110.590 3.555 110.670 4.280 ;
        RECT 111.510 3.555 111.590 4.280 ;
        RECT 112.430 3.555 112.510 4.280 ;
        RECT 113.350 3.555 113.430 4.280 ;
        RECT 114.270 3.555 114.350 4.280 ;
        RECT 115.190 3.555 115.270 4.280 ;
        RECT 116.110 3.555 116.190 4.280 ;
        RECT 117.030 3.555 117.110 4.280 ;
        RECT 117.950 3.555 118.030 4.280 ;
        RECT 118.870 3.555 118.950 4.280 ;
        RECT 119.790 3.555 119.870 4.280 ;
        RECT 120.710 3.555 120.790 4.280 ;
        RECT 121.630 3.555 121.710 4.280 ;
        RECT 122.550 3.555 122.630 4.280 ;
        RECT 123.470 3.555 123.550 4.280 ;
        RECT 124.390 3.555 124.470 4.280 ;
        RECT 125.310 3.555 125.390 4.280 ;
        RECT 126.230 3.555 126.310 4.280 ;
        RECT 127.150 3.555 127.230 4.280 ;
        RECT 128.070 3.555 128.150 4.280 ;
        RECT 128.990 3.555 129.070 4.280 ;
        RECT 129.910 3.555 129.990 4.280 ;
        RECT 130.830 3.555 130.910 4.280 ;
        RECT 131.750 3.555 131.830 4.280 ;
        RECT 132.670 3.555 132.750 4.280 ;
        RECT 133.590 3.555 133.670 4.280 ;
        RECT 134.510 3.555 134.590 4.280 ;
        RECT 135.430 3.555 135.510 4.280 ;
        RECT 136.350 3.555 136.430 4.280 ;
        RECT 137.270 3.555 137.350 4.280 ;
        RECT 138.190 3.555 138.270 4.280 ;
        RECT 139.110 3.555 139.190 4.280 ;
        RECT 140.030 3.555 140.110 4.280 ;
        RECT 140.950 3.555 141.030 4.280 ;
        RECT 141.870 3.555 141.950 4.280 ;
        RECT 142.790 3.555 142.870 4.280 ;
        RECT 143.710 3.555 143.790 4.280 ;
        RECT 144.630 3.555 144.710 4.280 ;
        RECT 145.550 3.555 145.630 4.280 ;
        RECT 146.470 3.555 146.550 4.280 ;
        RECT 147.390 3.555 147.470 4.280 ;
        RECT 148.310 3.555 148.390 4.280 ;
        RECT 149.230 3.555 149.310 4.280 ;
        RECT 150.150 3.555 150.230 4.280 ;
        RECT 151.070 3.555 151.150 4.280 ;
        RECT 151.990 3.555 152.070 4.280 ;
        RECT 152.910 3.555 152.990 4.280 ;
        RECT 153.830 3.555 153.910 4.280 ;
        RECT 154.750 3.555 154.830 4.280 ;
        RECT 155.670 3.555 155.750 4.280 ;
        RECT 156.590 3.555 156.670 4.280 ;
        RECT 157.510 3.555 157.590 4.280 ;
        RECT 158.430 3.555 158.510 4.280 ;
        RECT 159.350 3.555 159.430 4.280 ;
        RECT 160.270 3.555 160.350 4.280 ;
        RECT 161.190 3.555 161.270 4.280 ;
        RECT 162.110 3.555 162.190 4.280 ;
        RECT 163.030 3.555 163.110 4.280 ;
        RECT 163.950 3.555 164.030 4.280 ;
        RECT 164.870 3.555 164.950 4.280 ;
        RECT 165.790 3.555 165.870 4.280 ;
        RECT 166.710 3.555 166.790 4.280 ;
        RECT 167.630 3.555 167.710 4.280 ;
        RECT 168.550 3.555 168.630 4.280 ;
        RECT 169.470 3.555 169.550 4.280 ;
        RECT 170.390 3.555 170.470 4.280 ;
        RECT 171.310 3.555 171.390 4.280 ;
        RECT 172.230 3.555 172.310 4.280 ;
        RECT 173.150 3.555 173.230 4.280 ;
        RECT 174.070 3.555 174.150 4.280 ;
        RECT 174.990 3.555 175.070 4.280 ;
        RECT 175.910 3.555 175.990 4.280 ;
        RECT 176.830 3.555 176.910 4.280 ;
        RECT 177.750 3.555 177.830 4.280 ;
        RECT 178.670 3.555 178.750 4.280 ;
        RECT 179.590 3.555 179.670 4.280 ;
        RECT 180.510 3.555 180.590 4.280 ;
        RECT 181.430 3.555 181.510 4.280 ;
        RECT 182.350 3.555 182.430 4.280 ;
        RECT 183.270 3.555 183.350 4.280 ;
        RECT 184.190 3.555 184.270 4.280 ;
        RECT 185.110 3.555 185.190 4.280 ;
        RECT 186.030 3.555 186.110 4.280 ;
        RECT 186.950 3.555 187.030 4.280 ;
        RECT 187.870 3.555 187.950 4.280 ;
        RECT 188.790 3.555 188.870 4.280 ;
        RECT 189.710 3.555 189.790 4.280 ;
        RECT 190.630 3.555 190.710 4.280 ;
        RECT 191.550 3.555 191.630 4.280 ;
        RECT 192.470 3.555 192.550 4.280 ;
        RECT 193.390 3.555 193.470 4.280 ;
        RECT 194.310 3.555 194.390 4.280 ;
        RECT 195.230 3.555 195.310 4.280 ;
        RECT 196.150 3.555 196.230 4.280 ;
        RECT 197.070 3.555 197.150 4.280 ;
        RECT 197.990 3.555 198.070 4.280 ;
        RECT 198.910 3.555 198.990 4.280 ;
        RECT 199.830 3.555 199.910 4.280 ;
        RECT 200.750 3.555 200.830 4.280 ;
        RECT 201.670 3.555 201.750 4.280 ;
        RECT 202.590 3.555 202.670 4.280 ;
        RECT 203.510 3.555 203.590 4.280 ;
        RECT 204.430 3.555 204.510 4.280 ;
        RECT 205.350 3.555 205.430 4.280 ;
        RECT 206.270 3.555 206.350 4.280 ;
        RECT 207.190 3.555 207.270 4.280 ;
        RECT 208.110 3.555 208.190 4.280 ;
        RECT 209.030 3.555 209.110 4.280 ;
        RECT 209.950 3.555 210.030 4.280 ;
        RECT 210.870 3.555 210.950 4.280 ;
        RECT 211.790 3.555 211.870 4.280 ;
        RECT 212.710 3.555 212.790 4.280 ;
        RECT 213.630 3.555 213.710 4.280 ;
        RECT 214.550 3.555 214.630 4.280 ;
        RECT 215.470 3.555 215.550 4.280 ;
        RECT 216.390 3.555 216.470 4.280 ;
        RECT 217.310 3.555 217.390 4.280 ;
        RECT 218.230 3.555 218.310 4.280 ;
        RECT 219.150 3.555 219.230 4.280 ;
        RECT 220.070 3.555 220.150 4.280 ;
        RECT 220.990 3.555 221.070 4.280 ;
        RECT 221.910 3.555 221.990 4.280 ;
        RECT 222.830 3.555 222.910 4.280 ;
        RECT 223.750 3.555 223.830 4.280 ;
        RECT 224.670 3.555 224.750 4.280 ;
        RECT 225.590 3.555 225.670 4.280 ;
        RECT 226.510 3.555 226.590 4.280 ;
        RECT 227.430 3.555 227.510 4.280 ;
        RECT 228.350 3.555 228.430 4.280 ;
        RECT 229.270 3.555 229.350 4.280 ;
        RECT 230.190 3.555 230.270 4.280 ;
        RECT 231.110 3.555 231.190 4.280 ;
        RECT 232.030 3.555 232.110 4.280 ;
        RECT 232.950 3.555 233.030 4.280 ;
        RECT 233.870 3.555 233.950 4.280 ;
        RECT 234.790 3.555 234.870 4.280 ;
        RECT 235.710 3.555 235.790 4.280 ;
        RECT 236.630 3.555 236.710 4.280 ;
        RECT 237.550 3.555 237.630 4.280 ;
        RECT 238.470 3.555 238.550 4.280 ;
        RECT 239.390 3.555 239.470 4.280 ;
        RECT 240.310 3.555 240.390 4.280 ;
        RECT 241.230 3.555 241.310 4.280 ;
        RECT 242.150 3.555 242.230 4.280 ;
        RECT 243.070 3.555 243.150 4.280 ;
        RECT 243.990 3.555 244.070 4.280 ;
        RECT 244.910 3.555 244.990 4.280 ;
        RECT 245.830 3.555 245.910 4.280 ;
        RECT 246.750 3.555 246.830 4.280 ;
        RECT 247.670 3.555 247.750 4.280 ;
        RECT 248.590 3.555 248.670 4.280 ;
        RECT 249.510 3.555 249.590 4.280 ;
        RECT 250.430 3.555 250.510 4.280 ;
        RECT 251.350 3.555 251.430 4.280 ;
        RECT 252.270 3.555 252.350 4.280 ;
        RECT 253.190 3.555 253.270 4.280 ;
        RECT 254.110 3.555 254.190 4.280 ;
        RECT 255.030 3.555 255.110 4.280 ;
        RECT 255.950 3.555 256.030 4.280 ;
        RECT 256.870 3.555 256.950 4.280 ;
        RECT 257.790 3.555 257.870 4.280 ;
        RECT 258.710 3.555 258.790 4.280 ;
        RECT 259.630 3.555 259.710 4.280 ;
        RECT 260.550 3.555 260.630 4.280 ;
        RECT 261.470 3.555 261.550 4.280 ;
        RECT 262.390 3.555 262.470 4.280 ;
        RECT 263.310 3.555 263.390 4.280 ;
        RECT 264.230 3.555 264.310 4.280 ;
        RECT 265.150 3.555 265.230 4.280 ;
        RECT 266.070 3.555 266.150 4.280 ;
        RECT 266.990 3.555 267.070 4.280 ;
        RECT 267.910 3.555 267.990 4.280 ;
        RECT 268.830 3.555 268.910 4.280 ;
        RECT 269.750 3.555 269.830 4.280 ;
        RECT 270.670 3.555 270.750 4.280 ;
        RECT 271.590 3.555 271.670 4.280 ;
        RECT 272.510 3.555 272.590 4.280 ;
        RECT 273.430 3.555 273.510 4.280 ;
        RECT 274.350 3.555 274.430 4.280 ;
        RECT 275.270 3.555 275.350 4.280 ;
        RECT 276.190 3.555 276.270 4.280 ;
        RECT 277.110 3.555 277.190 4.280 ;
        RECT 278.030 3.555 278.110 4.280 ;
        RECT 278.950 3.555 279.030 4.280 ;
        RECT 279.870 3.555 279.950 4.280 ;
        RECT 280.790 3.555 280.870 4.280 ;
        RECT 281.710 3.555 281.790 4.280 ;
        RECT 282.630 3.555 282.710 4.280 ;
        RECT 283.550 3.555 283.630 4.280 ;
        RECT 284.470 3.555 284.550 4.280 ;
        RECT 285.390 3.555 285.470 4.280 ;
        RECT 286.310 3.555 286.390 4.280 ;
        RECT 287.230 3.555 287.310 4.280 ;
        RECT 288.150 3.555 288.230 4.280 ;
        RECT 289.070 3.555 289.150 4.280 ;
        RECT 289.990 3.555 290.070 4.280 ;
        RECT 290.910 3.555 290.990 4.280 ;
        RECT 291.830 3.555 291.910 4.280 ;
        RECT 292.750 3.555 292.830 4.280 ;
        RECT 293.670 3.555 293.750 4.280 ;
        RECT 294.590 3.555 294.670 4.280 ;
        RECT 295.510 3.555 295.590 4.280 ;
        RECT 296.430 3.555 296.510 4.280 ;
        RECT 297.350 3.555 297.430 4.280 ;
        RECT 298.270 3.555 298.350 4.280 ;
        RECT 299.190 3.555 299.270 4.280 ;
        RECT 300.110 3.555 300.190 4.280 ;
        RECT 301.030 3.555 301.110 4.280 ;
        RECT 301.950 3.555 302.030 4.280 ;
        RECT 302.870 3.555 302.950 4.280 ;
        RECT 303.790 3.555 303.870 4.280 ;
        RECT 304.710 3.555 304.790 4.280 ;
        RECT 305.630 3.555 305.710 4.280 ;
        RECT 306.550 3.555 306.630 4.280 ;
        RECT 307.470 3.555 307.550 4.280 ;
        RECT 308.390 3.555 308.470 4.280 ;
        RECT 309.310 3.555 309.390 4.280 ;
        RECT 310.230 3.555 310.310 4.280 ;
        RECT 311.150 3.555 311.230 4.280 ;
        RECT 312.070 3.555 312.150 4.280 ;
        RECT 312.990 3.555 313.070 4.280 ;
        RECT 313.910 3.555 313.990 4.280 ;
        RECT 314.830 3.555 314.910 4.280 ;
        RECT 315.750 3.555 315.830 4.280 ;
        RECT 316.670 3.555 316.750 4.280 ;
        RECT 317.590 3.555 317.670 4.280 ;
        RECT 318.510 3.555 318.590 4.280 ;
        RECT 319.430 3.555 319.510 4.280 ;
        RECT 320.350 3.555 320.430 4.280 ;
        RECT 321.270 3.555 321.350 4.280 ;
        RECT 322.190 3.555 322.270 4.280 ;
        RECT 323.110 3.555 323.190 4.280 ;
        RECT 324.030 3.555 324.110 4.280 ;
        RECT 324.950 3.555 325.030 4.280 ;
        RECT 325.870 3.555 325.950 4.280 ;
        RECT 326.790 3.555 326.870 4.280 ;
        RECT 327.710 3.555 327.790 4.280 ;
        RECT 328.630 3.555 328.710 4.280 ;
        RECT 329.550 3.555 329.630 4.280 ;
        RECT 330.470 3.555 330.550 4.280 ;
        RECT 331.390 3.555 331.470 4.280 ;
        RECT 332.310 3.555 332.390 4.280 ;
        RECT 333.230 3.555 333.310 4.280 ;
        RECT 334.150 3.555 334.230 4.280 ;
        RECT 335.070 3.555 335.150 4.280 ;
        RECT 335.990 3.555 336.070 4.280 ;
        RECT 336.910 3.555 336.990 4.280 ;
        RECT 337.830 3.555 337.910 4.280 ;
        RECT 338.750 3.555 338.830 4.280 ;
        RECT 339.670 3.555 339.750 4.280 ;
        RECT 340.590 3.555 340.670 4.280 ;
        RECT 341.510 3.555 341.590 4.280 ;
        RECT 342.430 3.555 342.510 4.280 ;
        RECT 343.350 3.555 343.430 4.280 ;
        RECT 344.270 3.555 344.350 4.280 ;
        RECT 345.190 3.555 345.270 4.280 ;
        RECT 346.110 3.555 346.190 4.280 ;
        RECT 347.030 3.555 347.110 4.280 ;
        RECT 347.950 3.555 348.030 4.280 ;
        RECT 348.870 3.555 348.950 4.280 ;
        RECT 349.790 3.555 349.870 4.280 ;
        RECT 350.710 3.555 350.790 4.280 ;
        RECT 351.630 3.555 351.710 4.280 ;
        RECT 352.550 3.555 352.630 4.280 ;
        RECT 353.470 3.555 353.550 4.280 ;
        RECT 354.390 3.555 354.470 4.280 ;
        RECT 355.310 3.555 355.390 4.280 ;
        RECT 356.230 3.555 356.310 4.280 ;
        RECT 357.150 3.555 357.230 4.280 ;
        RECT 358.070 3.555 358.150 4.280 ;
        RECT 358.990 3.555 359.070 4.280 ;
        RECT 359.910 3.555 359.990 4.280 ;
        RECT 360.830 3.555 360.910 4.280 ;
        RECT 361.750 3.555 361.830 4.280 ;
        RECT 362.670 3.555 362.750 4.280 ;
        RECT 363.590 3.555 363.670 4.280 ;
        RECT 364.510 3.555 364.590 4.280 ;
        RECT 365.430 3.555 365.510 4.280 ;
        RECT 366.350 3.555 366.430 4.280 ;
        RECT 367.270 3.555 367.350 4.280 ;
        RECT 368.190 3.555 368.270 4.280 ;
        RECT 369.110 3.555 369.190 4.280 ;
        RECT 370.030 3.555 370.110 4.280 ;
        RECT 370.950 3.555 371.030 4.280 ;
        RECT 371.870 3.555 371.950 4.280 ;
        RECT 372.790 3.555 372.870 4.280 ;
        RECT 373.710 3.555 373.790 4.280 ;
        RECT 374.630 3.555 374.710 4.280 ;
        RECT 375.550 3.555 375.630 4.280 ;
        RECT 376.470 3.555 376.550 4.280 ;
        RECT 377.390 3.555 377.470 4.280 ;
        RECT 378.310 3.555 378.390 4.280 ;
        RECT 379.230 3.555 379.310 4.280 ;
        RECT 380.150 3.555 380.230 4.280 ;
        RECT 381.070 3.555 381.150 4.280 ;
        RECT 381.990 3.555 382.070 4.280 ;
        RECT 382.910 3.555 382.990 4.280 ;
        RECT 383.830 3.555 383.910 4.280 ;
        RECT 384.750 3.555 384.830 4.280 ;
        RECT 385.670 3.555 385.750 4.280 ;
        RECT 386.590 3.555 386.670 4.280 ;
        RECT 387.510 3.555 387.590 4.280 ;
        RECT 388.430 3.555 388.510 4.280 ;
        RECT 389.350 3.555 389.430 4.280 ;
        RECT 390.270 3.555 390.350 4.280 ;
        RECT 391.190 3.555 391.270 4.280 ;
        RECT 392.110 3.555 392.190 4.280 ;
        RECT 393.030 3.555 393.110 4.280 ;
        RECT 393.950 3.555 394.030 4.280 ;
        RECT 394.870 3.555 394.950 4.280 ;
        RECT 395.790 3.555 395.870 4.280 ;
        RECT 396.710 3.555 396.790 4.280 ;
        RECT 397.630 3.555 397.710 4.280 ;
        RECT 398.550 3.555 398.630 4.280 ;
        RECT 399.470 3.555 399.550 4.280 ;
        RECT 400.390 3.555 400.470 4.280 ;
        RECT 401.310 3.555 401.390 4.280 ;
        RECT 402.230 3.555 402.310 4.280 ;
        RECT 403.150 3.555 403.230 4.280 ;
        RECT 404.070 3.555 404.150 4.280 ;
        RECT 404.990 3.555 405.070 4.280 ;
        RECT 405.910 3.555 405.990 4.280 ;
        RECT 406.830 3.555 406.910 4.280 ;
        RECT 407.750 3.555 407.830 4.280 ;
        RECT 408.670 3.555 408.750 4.280 ;
        RECT 409.590 3.555 409.670 4.280 ;
        RECT 410.510 3.555 410.590 4.280 ;
        RECT 411.430 3.555 411.510 4.280 ;
        RECT 412.350 3.555 412.430 4.280 ;
        RECT 413.270 3.555 413.350 4.280 ;
        RECT 414.190 3.555 414.270 4.280 ;
        RECT 415.110 3.555 415.190 4.280 ;
        RECT 416.030 3.555 416.110 4.280 ;
        RECT 416.950 3.555 417.030 4.280 ;
        RECT 417.870 3.555 417.950 4.280 ;
        RECT 418.790 3.555 418.870 4.280 ;
        RECT 419.710 3.555 419.790 4.280 ;
        RECT 420.630 3.555 420.710 4.280 ;
        RECT 421.550 3.555 421.630 4.280 ;
        RECT 422.470 3.555 422.550 4.280 ;
        RECT 423.390 3.555 423.470 4.280 ;
        RECT 424.310 3.555 424.390 4.280 ;
        RECT 425.230 3.555 425.310 4.280 ;
        RECT 426.150 3.555 426.230 4.280 ;
        RECT 427.070 3.555 427.150 4.280 ;
        RECT 427.990 3.555 428.070 4.280 ;
        RECT 428.910 3.555 428.990 4.280 ;
        RECT 429.830 3.555 429.910 4.280 ;
        RECT 430.750 3.555 430.830 4.280 ;
        RECT 431.670 3.555 431.750 4.280 ;
        RECT 432.590 3.555 432.670 4.280 ;
        RECT 433.510 3.555 433.590 4.280 ;
        RECT 434.430 3.555 434.510 4.280 ;
        RECT 435.350 3.555 435.430 4.280 ;
        RECT 436.270 3.555 436.350 4.280 ;
        RECT 437.190 3.555 437.270 4.280 ;
        RECT 438.110 3.555 438.190 4.280 ;
        RECT 439.030 3.555 439.110 4.280 ;
        RECT 439.950 3.555 440.030 4.280 ;
        RECT 440.870 3.555 440.950 4.280 ;
        RECT 441.790 3.555 441.870 4.280 ;
        RECT 442.710 3.555 442.790 4.280 ;
        RECT 443.630 3.555 443.710 4.280 ;
        RECT 444.550 3.555 444.630 4.280 ;
        RECT 445.470 3.555 445.550 4.280 ;
        RECT 446.390 3.555 446.470 4.280 ;
        RECT 447.310 3.555 447.390 4.280 ;
        RECT 448.230 3.555 448.310 4.280 ;
        RECT 449.150 3.555 449.230 4.280 ;
        RECT 450.070 3.555 450.150 4.280 ;
        RECT 450.990 3.555 451.070 4.280 ;
        RECT 451.910 3.555 451.990 4.280 ;
        RECT 452.830 3.555 452.910 4.280 ;
        RECT 453.750 3.555 453.830 4.280 ;
        RECT 454.670 3.555 454.750 4.280 ;
        RECT 455.590 3.555 455.670 4.280 ;
        RECT 456.510 3.555 456.590 4.280 ;
        RECT 457.430 3.555 457.510 4.280 ;
        RECT 458.350 3.555 458.430 4.280 ;
        RECT 459.270 3.555 459.350 4.280 ;
        RECT 460.190 3.555 460.270 4.280 ;
        RECT 461.110 3.555 461.190 4.280 ;
        RECT 462.030 3.555 462.110 4.280 ;
        RECT 462.950 3.555 463.030 4.280 ;
        RECT 463.870 3.555 463.950 4.280 ;
        RECT 464.790 3.555 464.870 4.280 ;
        RECT 465.710 3.555 465.790 4.280 ;
        RECT 466.630 3.555 466.710 4.280 ;
        RECT 467.550 3.555 467.630 4.280 ;
        RECT 468.470 3.555 468.550 4.280 ;
        RECT 469.390 3.555 469.470 4.280 ;
        RECT 470.310 3.555 470.390 4.280 ;
        RECT 471.230 3.555 471.310 4.280 ;
        RECT 472.150 3.555 472.230 4.280 ;
        RECT 473.070 3.555 473.150 4.280 ;
        RECT 473.990 3.555 474.070 4.280 ;
        RECT 474.910 3.555 474.990 4.280 ;
        RECT 475.830 3.555 475.910 4.280 ;
        RECT 476.750 3.555 476.830 4.280 ;
        RECT 477.670 3.555 477.750 4.280 ;
        RECT 478.590 3.555 478.670 4.280 ;
        RECT 479.510 3.555 479.590 4.280 ;
        RECT 480.430 3.555 480.510 4.280 ;
        RECT 481.350 3.555 481.430 4.280 ;
        RECT 482.270 3.555 482.350 4.280 ;
        RECT 483.190 3.555 483.270 4.280 ;
        RECT 484.110 3.555 484.190 4.280 ;
        RECT 485.030 3.555 485.110 4.280 ;
        RECT 485.950 3.555 486.030 4.280 ;
        RECT 486.870 3.555 486.950 4.280 ;
        RECT 487.790 3.555 487.870 4.280 ;
        RECT 488.710 3.555 488.790 4.280 ;
        RECT 489.630 3.555 489.710 4.280 ;
        RECT 490.550 3.555 490.630 4.280 ;
        RECT 491.470 3.555 491.550 4.280 ;
        RECT 492.390 3.555 492.470 4.280 ;
        RECT 493.310 3.555 493.390 4.280 ;
        RECT 494.230 3.555 494.310 4.280 ;
        RECT 495.150 3.555 495.230 4.280 ;
        RECT 496.070 3.555 496.150 4.280 ;
        RECT 496.990 3.555 497.070 4.280 ;
        RECT 497.910 3.555 497.990 4.280 ;
        RECT 498.830 3.555 498.910 4.280 ;
        RECT 499.750 3.555 499.830 4.280 ;
        RECT 500.670 3.555 500.750 4.280 ;
        RECT 501.590 3.555 501.670 4.280 ;
        RECT 502.510 3.555 502.590 4.280 ;
        RECT 503.430 3.555 503.510 4.280 ;
        RECT 504.350 3.555 504.430 4.280 ;
        RECT 505.270 3.555 505.350 4.280 ;
        RECT 506.190 3.555 506.270 4.280 ;
        RECT 507.110 3.555 507.190 4.280 ;
        RECT 508.030 3.555 508.110 4.280 ;
        RECT 508.950 3.555 509.030 4.280 ;
        RECT 509.870 3.555 509.950 4.280 ;
        RECT 510.790 3.555 510.870 4.280 ;
        RECT 511.710 3.555 511.790 4.280 ;
        RECT 512.630 3.555 512.710 4.280 ;
        RECT 513.550 3.555 513.630 4.280 ;
        RECT 514.470 3.555 514.550 4.280 ;
        RECT 515.390 3.555 515.470 4.280 ;
        RECT 516.310 3.555 516.390 4.280 ;
        RECT 517.230 3.555 517.310 4.280 ;
        RECT 518.150 3.555 518.230 4.280 ;
        RECT 519.070 3.555 519.150 4.280 ;
        RECT 519.990 3.555 520.070 4.280 ;
        RECT 520.910 3.555 520.990 4.280 ;
        RECT 521.830 3.555 521.910 4.280 ;
        RECT 522.750 3.555 522.830 4.280 ;
        RECT 523.670 3.555 523.750 4.280 ;
        RECT 524.590 3.555 524.670 4.280 ;
        RECT 525.510 3.555 525.590 4.280 ;
        RECT 526.430 3.555 526.510 4.280 ;
        RECT 527.350 3.555 527.430 4.280 ;
        RECT 528.270 3.555 528.350 4.280 ;
        RECT 529.190 3.555 529.270 4.280 ;
        RECT 530.110 3.555 530.190 4.280 ;
        RECT 531.030 3.555 531.110 4.280 ;
        RECT 531.950 3.555 532.030 4.280 ;
        RECT 532.870 3.555 532.950 4.280 ;
        RECT 533.790 3.555 533.870 4.280 ;
        RECT 534.710 3.555 534.790 4.280 ;
        RECT 535.630 3.555 535.710 4.280 ;
        RECT 536.550 3.555 536.630 4.280 ;
        RECT 537.470 3.555 537.550 4.280 ;
        RECT 538.390 3.555 538.470 4.280 ;
        RECT 539.310 3.555 539.390 4.280 ;
        RECT 540.230 3.555 540.310 4.280 ;
        RECT 541.150 3.555 541.230 4.280 ;
        RECT 542.070 3.555 542.150 4.280 ;
        RECT 542.990 3.555 543.070 4.280 ;
        RECT 543.910 3.555 543.990 4.280 ;
        RECT 544.830 3.555 544.910 4.280 ;
        RECT 545.750 3.555 545.830 4.280 ;
        RECT 546.670 3.555 546.750 4.280 ;
        RECT 547.590 3.555 547.670 4.280 ;
        RECT 548.510 3.555 548.590 4.280 ;
        RECT 549.430 3.555 549.510 4.280 ;
        RECT 550.350 3.555 550.430 4.280 ;
        RECT 551.270 3.555 551.350 4.280 ;
        RECT 552.190 3.555 552.270 4.280 ;
        RECT 553.110 3.555 553.190 4.280 ;
        RECT 554.030 3.555 554.110 4.280 ;
        RECT 554.950 3.555 555.030 4.280 ;
        RECT 555.870 3.555 555.950 4.280 ;
        RECT 556.790 3.555 556.870 4.280 ;
        RECT 557.710 3.555 557.790 4.280 ;
        RECT 558.630 3.555 558.710 4.280 ;
        RECT 559.550 3.555 559.630 4.280 ;
        RECT 560.470 3.555 560.550 4.280 ;
        RECT 561.390 3.555 561.470 4.280 ;
        RECT 562.310 3.555 562.390 4.280 ;
        RECT 563.230 3.555 563.310 4.280 ;
        RECT 564.150 3.555 564.230 4.280 ;
        RECT 565.070 3.555 565.150 4.280 ;
        RECT 565.990 3.555 566.070 4.280 ;
        RECT 566.910 3.555 566.990 4.280 ;
        RECT 567.830 3.555 567.910 4.280 ;
        RECT 568.750 3.555 568.830 4.280 ;
        RECT 569.670 3.555 569.750 4.280 ;
        RECT 570.590 3.555 570.670 4.280 ;
        RECT 571.510 3.555 571.590 4.280 ;
        RECT 572.430 3.555 572.510 4.280 ;
        RECT 573.350 3.555 573.430 4.280 ;
        RECT 574.270 3.555 574.350 4.280 ;
        RECT 575.190 3.555 575.270 4.280 ;
        RECT 576.110 3.555 576.190 4.280 ;
        RECT 577.030 3.555 577.110 4.280 ;
        RECT 577.950 3.555 578.030 4.280 ;
        RECT 578.870 3.555 578.950 4.280 ;
        RECT 579.790 3.555 579.870 4.280 ;
        RECT 580.710 3.555 580.790 4.280 ;
        RECT 581.630 3.555 581.710 4.280 ;
        RECT 582.550 3.555 582.630 4.280 ;
        RECT 583.470 3.555 583.550 4.280 ;
        RECT 584.390 3.555 584.470 4.280 ;
        RECT 585.310 3.555 585.390 4.280 ;
        RECT 586.230 3.555 586.310 4.280 ;
        RECT 587.150 3.555 587.230 4.280 ;
        RECT 588.070 3.555 588.150 4.280 ;
        RECT 588.990 3.555 589.070 4.280 ;
        RECT 589.910 3.555 589.990 4.280 ;
        RECT 590.830 3.555 590.910 4.280 ;
        RECT 591.750 3.555 591.830 4.280 ;
        RECT 592.670 3.555 592.750 4.280 ;
        RECT 593.590 3.555 593.670 4.280 ;
        RECT 594.510 3.555 594.590 4.280 ;
        RECT 595.430 3.555 595.510 4.280 ;
        RECT 596.350 3.555 596.430 4.280 ;
        RECT 597.270 3.555 597.350 4.280 ;
        RECT 598.190 3.555 598.270 4.280 ;
        RECT 599.110 3.555 599.190 4.280 ;
        RECT 600.030 3.555 600.110 4.280 ;
        RECT 600.950 3.555 601.030 4.280 ;
        RECT 601.870 3.555 601.950 4.280 ;
        RECT 602.790 3.555 602.870 4.280 ;
        RECT 603.710 3.555 603.790 4.280 ;
        RECT 604.630 3.555 604.710 4.280 ;
        RECT 605.550 3.555 605.630 4.280 ;
        RECT 606.470 3.555 606.550 4.280 ;
        RECT 607.390 3.555 607.470 4.280 ;
        RECT 608.310 3.555 608.390 4.280 ;
        RECT 609.230 3.555 609.310 4.280 ;
        RECT 610.150 3.555 610.230 4.280 ;
        RECT 611.070 3.555 611.150 4.280 ;
        RECT 611.990 3.555 612.070 4.280 ;
        RECT 612.910 3.555 612.990 4.280 ;
        RECT 613.830 3.555 613.910 4.280 ;
        RECT 614.750 3.555 614.830 4.280 ;
        RECT 615.670 3.555 615.750 4.280 ;
        RECT 616.590 3.555 616.670 4.280 ;
        RECT 617.510 3.555 617.590 4.280 ;
        RECT 618.430 3.555 618.510 4.280 ;
        RECT 619.350 3.555 619.430 4.280 ;
        RECT 620.270 3.555 620.350 4.280 ;
        RECT 621.190 3.555 621.270 4.280 ;
        RECT 622.110 3.555 622.190 4.280 ;
        RECT 623.030 3.555 623.110 4.280 ;
        RECT 623.950 3.555 624.030 4.280 ;
        RECT 624.870 3.555 624.950 4.280 ;
        RECT 625.790 3.555 625.870 4.280 ;
        RECT 626.710 3.555 626.790 4.280 ;
        RECT 627.630 3.555 627.710 4.280 ;
        RECT 628.550 3.555 628.630 4.280 ;
        RECT 629.470 3.555 629.550 4.280 ;
        RECT 630.390 3.555 630.470 4.280 ;
        RECT 631.310 3.555 631.390 4.280 ;
        RECT 632.230 3.555 632.310 4.280 ;
        RECT 633.150 3.555 633.230 4.280 ;
        RECT 634.070 3.555 634.150 4.280 ;
        RECT 634.990 3.555 635.070 4.280 ;
        RECT 635.910 3.555 635.990 4.280 ;
        RECT 636.830 3.555 636.910 4.280 ;
        RECT 637.750 3.555 637.830 4.280 ;
        RECT 638.670 3.555 638.750 4.280 ;
        RECT 639.590 3.555 639.670 4.280 ;
        RECT 640.510 3.555 640.590 4.280 ;
        RECT 641.430 3.555 641.510 4.280 ;
        RECT 642.350 3.555 642.430 4.280 ;
        RECT 643.270 3.555 643.350 4.280 ;
        RECT 644.190 3.555 644.270 4.280 ;
        RECT 645.110 3.555 645.190 4.280 ;
        RECT 646.030 3.555 646.110 4.280 ;
        RECT 646.950 3.555 647.030 4.280 ;
        RECT 647.870 3.555 647.950 4.280 ;
        RECT 648.790 3.555 648.870 4.280 ;
        RECT 649.710 3.555 649.790 4.280 ;
        RECT 650.630 3.555 650.710 4.280 ;
        RECT 651.550 3.555 651.630 4.280 ;
        RECT 652.470 3.555 652.550 4.280 ;
        RECT 653.390 3.555 653.470 4.280 ;
        RECT 654.310 3.555 654.390 4.280 ;
        RECT 655.230 3.555 655.310 4.280 ;
        RECT 656.150 3.555 656.230 4.280 ;
        RECT 657.070 3.555 657.150 4.280 ;
        RECT 657.990 3.555 658.070 4.280 ;
        RECT 658.910 3.555 658.990 4.280 ;
        RECT 659.830 3.555 659.910 4.280 ;
        RECT 660.750 3.555 660.830 4.280 ;
        RECT 661.670 3.555 661.750 4.280 ;
        RECT 662.590 3.555 662.670 4.280 ;
        RECT 663.510 3.555 663.590 4.280 ;
        RECT 664.430 3.555 664.510 4.280 ;
        RECT 665.350 3.555 665.430 4.280 ;
        RECT 666.270 3.555 666.350 4.280 ;
        RECT 667.190 3.555 667.270 4.280 ;
        RECT 668.110 3.555 668.190 4.280 ;
        RECT 669.030 3.555 669.110 4.280 ;
        RECT 669.950 3.555 670.030 4.280 ;
        RECT 670.870 3.555 670.950 4.280 ;
        RECT 671.790 3.555 671.870 4.280 ;
        RECT 672.710 3.555 672.790 4.280 ;
        RECT 673.630 3.555 673.710 4.280 ;
        RECT 674.550 3.555 674.630 4.280 ;
        RECT 675.470 3.555 675.550 4.280 ;
        RECT 676.390 3.555 676.470 4.280 ;
        RECT 677.310 3.555 677.390 4.280 ;
        RECT 678.230 3.555 678.310 4.280 ;
        RECT 679.150 3.555 679.230 4.280 ;
        RECT 680.070 3.555 680.150 4.280 ;
        RECT 680.990 3.555 681.070 4.280 ;
        RECT 681.910 3.555 681.990 4.280 ;
        RECT 682.830 3.555 682.910 4.280 ;
        RECT 683.750 3.555 683.830 4.280 ;
        RECT 684.670 3.555 684.750 4.280 ;
        RECT 685.590 3.555 685.670 4.280 ;
        RECT 686.510 3.555 686.590 4.280 ;
        RECT 687.430 3.555 687.510 4.280 ;
        RECT 688.350 3.555 688.430 4.280 ;
        RECT 689.270 3.555 689.350 4.280 ;
        RECT 690.190 3.555 690.270 4.280 ;
        RECT 691.110 3.555 691.190 4.280 ;
        RECT 692.030 3.555 692.110 4.280 ;
        RECT 692.950 3.555 693.030 4.280 ;
        RECT 693.870 3.555 693.950 4.280 ;
        RECT 694.790 3.555 694.870 4.280 ;
        RECT 695.710 3.555 695.790 4.280 ;
        RECT 696.630 3.555 696.710 4.280 ;
        RECT 697.550 3.555 697.630 4.280 ;
        RECT 698.470 3.555 698.550 4.280 ;
        RECT 699.390 3.555 699.470 4.280 ;
        RECT 700.310 3.555 700.390 4.280 ;
        RECT 701.230 3.555 749.700 4.280 ;
      LAYER met3 ;
        RECT 3.990 437.600 746.000 488.745 ;
        RECT 4.400 60.840 745.600 437.600 ;
        RECT 3.990 3.575 746.000 60.840 ;
      LAYER met4 ;
        RECT 23.295 3.575 23.940 483.305 ;
        RECT 26.340 3.575 174.240 483.305 ;
        RECT 176.640 3.575 177.540 483.305 ;
        RECT 179.940 3.575 327.840 483.305 ;
        RECT 330.240 3.575 331.140 483.305 ;
        RECT 333.540 3.575 481.440 483.305 ;
        RECT 483.840 3.575 484.740 483.305 ;
        RECT 487.140 3.575 635.040 483.305 ;
        RECT 637.440 3.575 638.340 483.305 ;
        RECT 640.740 3.575 737.545 483.305 ;
  END
END wavg_pipe_m
END LIBRARY

